VERSION 5.8 ;
BUSBITCHARS "[]" ;
DIVIDERCHAR "/" ;
UNITS
    DATABASE MICRONS 1000 ;
END UNITS

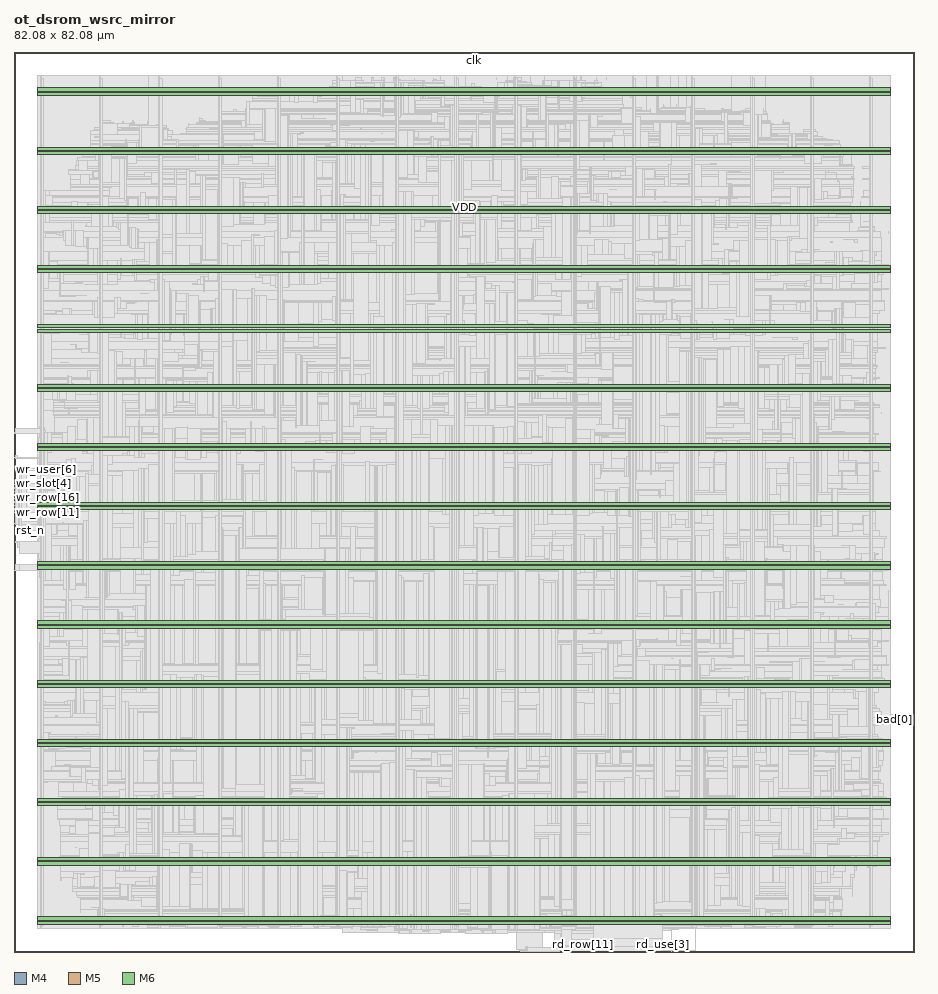
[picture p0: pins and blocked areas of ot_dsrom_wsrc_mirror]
MACRO ot_dsrom_wsrc_mirror
  FOREIGN ot_dsrom_wsrc_mirror 0 0 ;
  CLASS BLOCK ;
  SIZE 82.08 BY 82.08 ;
  PIN bad[0]
    DIRECTION OUTPUT ;
    USE SIGNAL ;
    PORT
      LAYER M4 ;
        RECT  81.996 21.216 82.08 21.24 ;
    END
  END bad[0]
  PIN bad[1]
    DIRECTION OUTPUT ;
    USE SIGNAL ;
    PORT
      LAYER M4 ;
        RECT  81.996 21.312 82.08 21.336 ;
    END
  END bad[1]
  PIN bad[2]
    DIRECTION OUTPUT ;
    USE SIGNAL ;
    PORT
      LAYER M4 ;
        RECT  81.996 21.408 82.08 21.432 ;
    END
  END bad[2]
  PIN bad[3]
    DIRECTION OUTPUT ;
    USE SIGNAL ;
    PORT
      LAYER M4 ;
        RECT  81.996 21.504 82.08 21.528 ;
    END
  END bad[3]
  PIN clk
    DIRECTION INPUT ;
    USE SIGNAL ;
    PORT
      LAYER M5 ;
        RECT  41.952 81.996 41.976 82.08 ;
    END
  END clk
  PIN j_user[0]
    DIRECTION INPUT ;
    USE SIGNAL ;
    PORT
      LAYER M5 ;
        RECT  49.824 0 49.848 0.084 ;
    END
  END j_user[0]
  PIN j_user[1]
    DIRECTION INPUT ;
    USE SIGNAL ;
    PORT
      LAYER M5 ;
        RECT  49.92 0 49.944 0.084 ;
    END
  END j_user[1]
  PIN j_user[2]
    DIRECTION INPUT ;
    USE SIGNAL ;
    PORT
      LAYER M5 ;
        RECT  50.016 0 50.04 0.084 ;
    END
  END j_user[2]
  PIN j_user[3]
    DIRECTION INPUT ;
    USE SIGNAL ;
    PORT
      LAYER M5 ;
        RECT  50.112 0 50.136 0.084 ;
    END
  END j_user[3]
  PIN j_user[4]
    DIRECTION INPUT ;
    USE SIGNAL ;
    PORT
      LAYER M5 ;
        RECT  50.208 0 50.232 0.084 ;
    END
  END j_user[4]
  PIN j_user[5]
    DIRECTION INPUT ;
    USE SIGNAL ;
    PORT
      LAYER M5 ;
        RECT  50.304 0 50.328 0.084 ;
    END
  END j_user[5]
  PIN j_user[6]
    DIRECTION INPUT ;
    USE SIGNAL ;
    PORT
      LAYER M5 ;
        RECT  50.4 0 50.424 0.084 ;
    END
  END j_user[6]
  PIN j_user[7]
    DIRECTION INPUT ;
    USE SIGNAL ;
    PORT
      LAYER M5 ;
        RECT  50.496 0 50.52 0.084 ;
    END
  END j_user[7]
  PIN j_user[8]
    DIRECTION INPUT ;
    USE SIGNAL ;
    PORT
      LAYER M5 ;
        RECT  50.592 0 50.616 0.084 ;
    END
  END j_user[8]
  PIN j_user[9]
    DIRECTION INPUT ;
    USE SIGNAL ;
    PORT
      LAYER M5 ;
        RECT  50.688 0 50.712 0.084 ;
    END
  END j_user[9]
  PIN rd_row[0]
    DIRECTION INPUT ;
    USE SIGNAL ;
    PORT
      LAYER M5 ;
        RECT  50.784 0 50.808 0.084 ;
    END
  END rd_row[0]
  PIN rd_row[10]
    DIRECTION INPUT ;
    USE SIGNAL ;
    PORT
      LAYER M5 ;
        RECT  51.744 0 51.768 0.084 ;
    END
  END rd_row[10]
  PIN rd_row[11]
    DIRECTION INPUT ;
    USE SIGNAL ;
    PORT
      LAYER M5 ;
        RECT  51.84 0 51.864 0.084 ;
    END
  END rd_row[11]
  PIN rd_row[12]
    DIRECTION INPUT ;
    USE SIGNAL ;
    PORT
      LAYER M5 ;
        RECT  51.936 0 51.96 0.084 ;
    END
  END rd_row[12]
  PIN rd_row[13]
    DIRECTION INPUT ;
    USE SIGNAL ;
    PORT
      LAYER M5 ;
        RECT  52.032 0 52.056 0.084 ;
    END
  END rd_row[13]
  PIN rd_row[14]
    DIRECTION INPUT ;
    USE SIGNAL ;
    PORT
      LAYER M5 ;
        RECT  52.128 0 52.152 0.084 ;
    END
  END rd_row[14]
  PIN rd_row[15]
    DIRECTION INPUT ;
    USE SIGNAL ;
    PORT
      LAYER M5 ;
        RECT  52.224 0 52.248 0.084 ;
    END
  END rd_row[15]
  PIN rd_row[16]
    DIRECTION INPUT ;
    USE SIGNAL ;
    PORT
      LAYER M5 ;
        RECT  52.32 0 52.344 0.084 ;
    END
  END rd_row[16]
  PIN rd_row[17]
    DIRECTION INPUT ;
    USE SIGNAL ;
    PORT
      LAYER M5 ;
        RECT  52.416 0 52.44 0.084 ;
    END
  END rd_row[17]
  PIN rd_row[18]
    DIRECTION INPUT ;
    USE SIGNAL ;
    PORT
      LAYER M5 ;
        RECT  52.512 0 52.536 0.084 ;
    END
  END rd_row[18]
  PIN rd_row[19]
    DIRECTION INPUT ;
    USE SIGNAL ;
    PORT
      LAYER M5 ;
        RECT  52.608 0 52.632 0.084 ;
    END
  END rd_row[19]
  PIN rd_row[1]
    DIRECTION INPUT ;
    USE SIGNAL ;
    PORT
      LAYER M5 ;
        RECT  50.88 0 50.904 0.084 ;
    END
  END rd_row[1]
  PIN rd_row[20]
    DIRECTION INPUT ;
    USE SIGNAL ;
    PORT
      LAYER M5 ;
        RECT  52.704 0 52.728 0.084 ;
    END
  END rd_row[20]
  PIN rd_row[21]
    DIRECTION INPUT ;
    USE SIGNAL ;
    PORT
      LAYER M5 ;
        RECT  52.8 0 52.824 0.084 ;
    END
  END rd_row[21]
  PIN rd_row[22]
    DIRECTION INPUT ;
    USE SIGNAL ;
    PORT
      LAYER M5 ;
        RECT  52.896 0 52.92 0.084 ;
    END
  END rd_row[22]
  PIN rd_row[23]
    DIRECTION INPUT ;
    USE SIGNAL ;
    PORT
      LAYER M5 ;
        RECT  52.992 0 53.016 0.084 ;
    END
  END rd_row[23]
  PIN rd_row[24]
    DIRECTION INPUT ;
    USE SIGNAL ;
    PORT
      LAYER M5 ;
        RECT  53.088 0 53.112 0.084 ;
    END
  END rd_row[24]
  PIN rd_row[25]
    DIRECTION INPUT ;
    USE SIGNAL ;
    PORT
      LAYER M5 ;
        RECT  53.184 0 53.208 0.084 ;
    END
  END rd_row[25]
  PIN rd_row[26]
    DIRECTION INPUT ;
    USE SIGNAL ;
    PORT
      LAYER M5 ;
        RECT  53.28 0 53.304 0.084 ;
    END
  END rd_row[26]
  PIN rd_row[27]
    DIRECTION INPUT ;
    USE SIGNAL ;
    PORT
      LAYER M5 ;
        RECT  53.376 0 53.4 0.084 ;
    END
  END rd_row[27]
  PIN rd_row[28]
    DIRECTION INPUT ;
    USE SIGNAL ;
    PORT
      LAYER M5 ;
        RECT  53.472 0 53.496 0.084 ;
    END
  END rd_row[28]
  PIN rd_row[29]
    DIRECTION INPUT ;
    USE SIGNAL ;
    PORT
      LAYER M5 ;
        RECT  53.568 0 53.592 0.084 ;
    END
  END rd_row[29]
  PIN rd_row[2]
    DIRECTION INPUT ;
    USE SIGNAL ;
    PORT
      LAYER M5 ;
        RECT  50.976 0 51 0.084 ;
    END
  END rd_row[2]
  PIN rd_row[30]
    DIRECTION INPUT ;
    USE SIGNAL ;
    PORT
      LAYER M5 ;
        RECT  53.664 0 53.688 0.084 ;
    END
  END rd_row[30]
  PIN rd_row[31]
    DIRECTION INPUT ;
    USE SIGNAL ;
    PORT
      LAYER M5 ;
        RECT  53.76 0 53.784 0.084 ;
    END
  END rd_row[31]
  PIN rd_row[32]
    DIRECTION INPUT ;
    USE SIGNAL ;
    PORT
      LAYER M5 ;
        RECT  53.856 0 53.88 0.084 ;
    END
  END rd_row[32]
  PIN rd_row[33]
    DIRECTION INPUT ;
    USE SIGNAL ;
    PORT
      LAYER M5 ;
        RECT  53.952 0 53.976 0.084 ;
    END
  END rd_row[33]
  PIN rd_row[34]
    DIRECTION INPUT ;
    USE SIGNAL ;
    PORT
      LAYER M5 ;
        RECT  54.048 0 54.072 0.084 ;
    END
  END rd_row[34]
  PIN rd_row[35]
    DIRECTION INPUT ;
    USE SIGNAL ;
    PORT
      LAYER M5 ;
        RECT  54.144 0 54.168 0.084 ;
    END
  END rd_row[35]
  PIN rd_row[36]
    DIRECTION INPUT ;
    USE SIGNAL ;
    PORT
      LAYER M5 ;
        RECT  54.24 0 54.264 0.084 ;
    END
  END rd_row[36]
  PIN rd_row[37]
    DIRECTION INPUT ;
    USE SIGNAL ;
    PORT
      LAYER M5 ;
        RECT  54.336 0 54.36 0.084 ;
    END
  END rd_row[37]
  PIN rd_row[38]
    DIRECTION INPUT ;
    USE SIGNAL ;
    PORT
      LAYER M5 ;
        RECT  54.432 0 54.456 0.084 ;
    END
  END rd_row[38]
  PIN rd_row[39]
    DIRECTION INPUT ;
    USE SIGNAL ;
    PORT
      LAYER M5 ;
        RECT  54.528 0 54.552 0.084 ;
    END
  END rd_row[39]
  PIN rd_row[3]
    DIRECTION INPUT ;
    USE SIGNAL ;
    PORT
      LAYER M5 ;
        RECT  51.072 0 51.096 0.084 ;
    END
  END rd_row[3]
  PIN rd_row[40]
    DIRECTION INPUT ;
    USE SIGNAL ;
    PORT
      LAYER M5 ;
        RECT  54.624 0 54.648 0.084 ;
    END
  END rd_row[40]
  PIN rd_row[41]
    DIRECTION INPUT ;
    USE SIGNAL ;
    PORT
      LAYER M5 ;
        RECT  54.72 0 54.744 0.084 ;
    END
  END rd_row[41]
  PIN rd_row[42]
    DIRECTION INPUT ;
    USE SIGNAL ;
    PORT
      LAYER M5 ;
        RECT  54.816 0 54.84 0.084 ;
    END
  END rd_row[42]
  PIN rd_row[43]
    DIRECTION INPUT ;
    USE SIGNAL ;
    PORT
      LAYER M5 ;
        RECT  54.912 0 54.936 0.084 ;
    END
  END rd_row[43]
  PIN rd_row[44]
    DIRECTION INPUT ;
    USE SIGNAL ;
    PORT
      LAYER M5 ;
        RECT  55.008 0 55.032 0.084 ;
    END
  END rd_row[44]
  PIN rd_row[45]
    DIRECTION INPUT ;
    USE SIGNAL ;
    PORT
      LAYER M5 ;
        RECT  55.104 0 55.128 0.084 ;
    END
  END rd_row[45]
  PIN rd_row[46]
    DIRECTION INPUT ;
    USE SIGNAL ;
    PORT
      LAYER M5 ;
        RECT  55.2 0 55.224 0.084 ;
    END
  END rd_row[46]
  PIN rd_row[47]
    DIRECTION INPUT ;
    USE SIGNAL ;
    PORT
      LAYER M5 ;
        RECT  55.296 0 55.32 0.084 ;
    END
  END rd_row[47]
  PIN rd_row[48]
    DIRECTION INPUT ;
    USE SIGNAL ;
    PORT
      LAYER M5 ;
        RECT  55.392 0 55.416 0.084 ;
    END
  END rd_row[48]
  PIN rd_row[49]
    DIRECTION INPUT ;
    USE SIGNAL ;
    PORT
      LAYER M5 ;
        RECT  55.488 0 55.512 0.084 ;
    END
  END rd_row[49]
  PIN rd_row[4]
    DIRECTION INPUT ;
    USE SIGNAL ;
    PORT
      LAYER M5 ;
        RECT  51.168 0 51.192 0.084 ;
    END
  END rd_row[4]
  PIN rd_row[50]
    DIRECTION INPUT ;
    USE SIGNAL ;
    PORT
      LAYER M5 ;
        RECT  55.584 0 55.608 0.084 ;
    END
  END rd_row[50]
  PIN rd_row[51]
    DIRECTION INPUT ;
    USE SIGNAL ;
    PORT
      LAYER M5 ;
        RECT  55.68 0 55.704 0.084 ;
    END
  END rd_row[51]
  PIN rd_row[52]
    DIRECTION INPUT ;
    USE SIGNAL ;
    PORT
      LAYER M5 ;
        RECT  55.776 0 55.8 0.084 ;
    END
  END rd_row[52]
  PIN rd_row[53]
    DIRECTION INPUT ;
    USE SIGNAL ;
    PORT
      LAYER M5 ;
        RECT  55.872 0 55.896 0.084 ;
    END
  END rd_row[53]
  PIN rd_row[54]
    DIRECTION INPUT ;
    USE SIGNAL ;
    PORT
      LAYER M5 ;
        RECT  55.968 0 55.992 0.084 ;
    END
  END rd_row[54]
  PIN rd_row[55]
    DIRECTION INPUT ;
    USE SIGNAL ;
    PORT
      LAYER M5 ;
        RECT  56.064 0 56.088 0.084 ;
    END
  END rd_row[55]
  PIN rd_row[56]
    DIRECTION INPUT ;
    USE SIGNAL ;
    PORT
      LAYER M5 ;
        RECT  56.16 0 56.184 0.084 ;
    END
  END rd_row[56]
  PIN rd_row[57]
    DIRECTION INPUT ;
    USE SIGNAL ;
    PORT
      LAYER M5 ;
        RECT  56.256 0 56.28 0.084 ;
    END
  END rd_row[57]
  PIN rd_row[58]
    DIRECTION INPUT ;
    USE SIGNAL ;
    PORT
      LAYER M5 ;
        RECT  56.352 0 56.376 0.084 ;
    END
  END rd_row[58]
  PIN rd_row[59]
    DIRECTION INPUT ;
    USE SIGNAL ;
    PORT
      LAYER M5 ;
        RECT  56.448 0 56.472 0.084 ;
    END
  END rd_row[59]
  PIN rd_row[5]
    DIRECTION INPUT ;
    USE SIGNAL ;
    PORT
      LAYER M5 ;
        RECT  51.264 0 51.288 0.084 ;
    END
  END rd_row[5]
  PIN rd_row[60]
    DIRECTION INPUT ;
    USE SIGNAL ;
    PORT
      LAYER M5 ;
        RECT  56.544 0 56.568 0.084 ;
    END
  END rd_row[60]
  PIN rd_row[61]
    DIRECTION INPUT ;
    USE SIGNAL ;
    PORT
      LAYER M5 ;
        RECT  56.64 0 56.664 0.084 ;
    END
  END rd_row[61]
  PIN rd_row[62]
    DIRECTION INPUT ;
    USE SIGNAL ;
    PORT
      LAYER M5 ;
        RECT  56.736 0 56.76 0.084 ;
    END
  END rd_row[62]
  PIN rd_row[63]
    DIRECTION INPUT ;
    USE SIGNAL ;
    PORT
      LAYER M5 ;
        RECT  56.832 0 56.856 0.084 ;
    END
  END rd_row[63]
  PIN rd_row[64]
    DIRECTION INPUT ;
    USE SIGNAL ;
    PORT
      LAYER M5 ;
        RECT  56.928 0 56.952 0.084 ;
    END
  END rd_row[64]
  PIN rd_row[65]
    DIRECTION INPUT ;
    USE SIGNAL ;
    PORT
      LAYER M5 ;
        RECT  57.024 0 57.048 0.084 ;
    END
  END rd_row[65]
  PIN rd_row[66]
    DIRECTION INPUT ;
    USE SIGNAL ;
    PORT
      LAYER M5 ;
        RECT  57.12 0 57.144 0.084 ;
    END
  END rd_row[66]
  PIN rd_row[67]
    DIRECTION INPUT ;
    USE SIGNAL ;
    PORT
      LAYER M5 ;
        RECT  57.216 0 57.24 0.084 ;
    END
  END rd_row[67]
  PIN rd_row[68]
    DIRECTION INPUT ;
    USE SIGNAL ;
    PORT
      LAYER M5 ;
        RECT  57.312 0 57.336 0.084 ;
    END
  END rd_row[68]
  PIN rd_row[69]
    DIRECTION INPUT ;
    USE SIGNAL ;
    PORT
      LAYER M5 ;
        RECT  57.408 0 57.432 0.084 ;
    END
  END rd_row[69]
  PIN rd_row[6]
    DIRECTION INPUT ;
    USE SIGNAL ;
    PORT
      LAYER M5 ;
        RECT  51.36 0 51.384 0.084 ;
    END
  END rd_row[6]
  PIN rd_row[70]
    DIRECTION INPUT ;
    USE SIGNAL ;
    PORT
      LAYER M5 ;
        RECT  57.504 0 57.528 0.084 ;
    END
  END rd_row[70]
  PIN rd_row[71]
    DIRECTION INPUT ;
    USE SIGNAL ;
    PORT
      LAYER M5 ;
        RECT  57.6 0 57.624 0.084 ;
    END
  END rd_row[71]
  PIN rd_row[72]
    DIRECTION INPUT ;
    USE SIGNAL ;
    PORT
      LAYER M5 ;
        RECT  57.696 0 57.72 0.084 ;
    END
  END rd_row[72]
  PIN rd_row[73]
    DIRECTION INPUT ;
    USE SIGNAL ;
    PORT
      LAYER M5 ;
        RECT  57.792 0 57.816 0.084 ;
    END
  END rd_row[73]
  PIN rd_row[74]
    DIRECTION INPUT ;
    USE SIGNAL ;
    PORT
      LAYER M5 ;
        RECT  57.888 0 57.912 0.084 ;
    END
  END rd_row[74]
  PIN rd_row[75]
    DIRECTION INPUT ;
    USE SIGNAL ;
    PORT
      LAYER M5 ;
        RECT  57.984 0 58.008 0.084 ;
    END
  END rd_row[75]
  PIN rd_row[76]
    DIRECTION INPUT ;
    USE SIGNAL ;
    PORT
      LAYER M5 ;
        RECT  58.08 0 58.104 0.084 ;
    END
  END rd_row[76]
  PIN rd_row[77]
    DIRECTION INPUT ;
    USE SIGNAL ;
    PORT
      LAYER M5 ;
        RECT  58.176 0 58.2 0.084 ;
    END
  END rd_row[77]
  PIN rd_row[78]
    DIRECTION INPUT ;
    USE SIGNAL ;
    PORT
      LAYER M5 ;
        RECT  58.272 0 58.296 0.084 ;
    END
  END rd_row[78]
  PIN rd_row[79]
    DIRECTION INPUT ;
    USE SIGNAL ;
    PORT
      LAYER M5 ;
        RECT  58.368 0 58.392 0.084 ;
    END
  END rd_row[79]
  PIN rd_row[7]
    DIRECTION INPUT ;
    USE SIGNAL ;
    PORT
      LAYER M5 ;
        RECT  51.456 0 51.48 0.084 ;
    END
  END rd_row[7]
  PIN rd_row[80]
    DIRECTION INPUT ;
    USE SIGNAL ;
    PORT
      LAYER M5 ;
        RECT  58.464 0 58.488 0.084 ;
    END
  END rd_row[80]
  PIN rd_row[81]
    DIRECTION INPUT ;
    USE SIGNAL ;
    PORT
      LAYER M5 ;
        RECT  58.56 0 58.584 0.084 ;
    END
  END rd_row[81]
  PIN rd_row[82]
    DIRECTION INPUT ;
    USE SIGNAL ;
    PORT
      LAYER M5 ;
        RECT  58.656 0 58.68 0.084 ;
    END
  END rd_row[82]
  PIN rd_row[83]
    DIRECTION INPUT ;
    USE SIGNAL ;
    PORT
      LAYER M5 ;
        RECT  58.752 0 58.776 0.084 ;
    END
  END rd_row[83]
  PIN rd_row[8]
    DIRECTION INPUT ;
    USE SIGNAL ;
    PORT
      LAYER M5 ;
        RECT  51.552 0 51.576 0.084 ;
    END
  END rd_row[8]
  PIN rd_row[9]
    DIRECTION INPUT ;
    USE SIGNAL ;
    PORT
      LAYER M5 ;
        RECT  51.648 0 51.672 0.084 ;
    END
  END rd_row[9]
  PIN rd_use[0]
    DIRECTION INPUT ;
    USE SIGNAL ;
    PORT
      LAYER M5 ;
        RECT  58.848 0 58.872 0.084 ;
    END
  END rd_use[0]
  PIN rd_use[1]
    DIRECTION INPUT ;
    USE SIGNAL ;
    PORT
      LAYER M5 ;
        RECT  58.944 0 58.968 0.084 ;
    END
  END rd_use[1]
  PIN rd_use[2]
    DIRECTION INPUT ;
    USE SIGNAL ;
    PORT
      LAYER M5 ;
        RECT  59.04 0 59.064 0.084 ;
    END
  END rd_use[2]
  PIN rd_use[3]
    DIRECTION INPUT ;
    USE SIGNAL ;
    PORT
      LAYER M5 ;
        RECT  59.136 0 59.16 0.084 ;
    END
  END rd_use[3]
  PIN rst_n
    DIRECTION INPUT ;
    USE SIGNAL ;
    PORT
      LAYER M6 ;
        RECT  0 38.4 0.069 38.432 ;
    END
  END rst_n
  PIN wr_clr
    DIRECTION INPUT ;
    USE SIGNAL ;
    PORT
      LAYER M6 ;
        RECT  0 38.528 0.069 38.56 ;
    END
  END wr_clr
  PIN wr_row[0]
    DIRECTION INPUT ;
    USE SIGNAL ;
    PORT
      LAYER M6 ;
        RECT  0 38.656 0.069 38.688 ;
    END
  END wr_row[0]
  PIN wr_row[10]
    DIRECTION INPUT ;
    USE SIGNAL ;
    PORT
      LAYER M6 ;
        RECT  0 39.936 0.069 39.968 ;
    END
  END wr_row[10]
  PIN wr_row[11]
    DIRECTION INPUT ;
    USE SIGNAL ;
    PORT
      LAYER M6 ;
        RECT  0 40.064 0.069 40.096 ;
    END
  END wr_row[11]
  PIN wr_row[12]
    DIRECTION INPUT ;
    USE SIGNAL ;
    PORT
      LAYER M6 ;
        RECT  0 40.192 0.069 40.224 ;
    END
  END wr_row[12]
  PIN wr_row[13]
    DIRECTION INPUT ;
    USE SIGNAL ;
    PORT
      LAYER M6 ;
        RECT  0 40.32 0.069 40.352 ;
    END
  END wr_row[13]
  PIN wr_row[14]
    DIRECTION INPUT ;
    USE SIGNAL ;
    PORT
      LAYER M6 ;
        RECT  0 40.448 0.069 40.48 ;
    END
  END wr_row[14]
  PIN wr_row[15]
    DIRECTION INPUT ;
    USE SIGNAL ;
    PORT
      LAYER M6 ;
        RECT  0 40.576 0.069 40.608 ;
    END
  END wr_row[15]
  PIN wr_row[16]
    DIRECTION INPUT ;
    USE SIGNAL ;
    PORT
      LAYER M6 ;
        RECT  0 40.704 0.069 40.736 ;
    END
  END wr_row[16]
  PIN wr_row[17]
    DIRECTION INPUT ;
    USE SIGNAL ;
    PORT
      LAYER M6 ;
        RECT  0 40.832 0.069 40.864 ;
    END
  END wr_row[17]
  PIN wr_row[18]
    DIRECTION INPUT ;
    USE SIGNAL ;
    PORT
      LAYER M6 ;
        RECT  0 40.96 0.069 40.992 ;
    END
  END wr_row[18]
  PIN wr_row[19]
    DIRECTION INPUT ;
    USE SIGNAL ;
    PORT
      LAYER M6 ;
        RECT  0 41.088 0.069 41.12 ;
    END
  END wr_row[19]
  PIN wr_row[1]
    DIRECTION INPUT ;
    USE SIGNAL ;
    PORT
      LAYER M6 ;
        RECT  0 38.784 0.069 38.816 ;
    END
  END wr_row[1]
  PIN wr_row[20]
    DIRECTION INPUT ;
    USE SIGNAL ;
    PORT
      LAYER M6 ;
        RECT  0 41.216 0.069 41.248 ;
    END
  END wr_row[20]
  PIN wr_row[2]
    DIRECTION INPUT ;
    USE SIGNAL ;
    PORT
      LAYER M6 ;
        RECT  0 38.912 0.069 38.944 ;
    END
  END wr_row[2]
  PIN wr_row[3]
    DIRECTION INPUT ;
    USE SIGNAL ;
    PORT
      LAYER M6 ;
        RECT  0 39.04 0.069 39.072 ;
    END
  END wr_row[3]
  PIN wr_row[4]
    DIRECTION INPUT ;
    USE SIGNAL ;
    PORT
      LAYER M6 ;
        RECT  0 39.168 0.069 39.2 ;
    END
  END wr_row[4]
  PIN wr_row[5]
    DIRECTION INPUT ;
    USE SIGNAL ;
    PORT
      LAYER M6 ;
        RECT  0 39.296 0.069 39.328 ;
    END
  END wr_row[5]
  PIN wr_row[6]
    DIRECTION INPUT ;
    USE SIGNAL ;
    PORT
      LAYER M6 ;
        RECT  0 39.424 0.069 39.456 ;
    END
  END wr_row[6]
  PIN wr_row[7]
    DIRECTION INPUT ;
    USE SIGNAL ;
    PORT
      LAYER M6 ;
        RECT  0 39.552 0.069 39.584 ;
    END
  END wr_row[7]
  PIN wr_row[8]
    DIRECTION INPUT ;
    USE SIGNAL ;
    PORT
      LAYER M6 ;
        RECT  0 39.68 0.069 39.712 ;
    END
  END wr_row[8]
  PIN wr_row[9]
    DIRECTION INPUT ;
    USE SIGNAL ;
    PORT
      LAYER M6 ;
        RECT  0 39.808 0.069 39.84 ;
    END
  END wr_row[9]
  PIN wr_set
    DIRECTION INPUT ;
    USE SIGNAL ;
    PORT
      LAYER M6 ;
        RECT  0 41.344 0.069 41.376 ;
    END
  END wr_set
  PIN wr_slot[0]
    DIRECTION INPUT ;
    USE SIGNAL ;
    PORT
      LAYER M6 ;
        RECT  0 41.472 0.069 41.504 ;
    END
  END wr_slot[0]
  PIN wr_slot[1]
    DIRECTION INPUT ;
    USE SIGNAL ;
    PORT
      LAYER M6 ;
        RECT  0 41.6 0.069 41.632 ;
    END
  END wr_slot[1]
  PIN wr_slot[2]
    DIRECTION INPUT ;
    USE SIGNAL ;
    PORT
      LAYER M6 ;
        RECT  0 41.728 0.069 41.76 ;
    END
  END wr_slot[2]
  PIN wr_slot[3]
    DIRECTION INPUT ;
    USE SIGNAL ;
    PORT
      LAYER M6 ;
        RECT  0 41.856 0.069 41.888 ;
    END
  END wr_slot[3]
  PIN wr_slot[4]
    DIRECTION INPUT ;
    USE SIGNAL ;
    PORT
      LAYER M6 ;
        RECT  0 41.984 0.069 42.016 ;
    END
  END wr_slot[4]
  PIN wr_slot[5]
    DIRECTION INPUT ;
    USE SIGNAL ;
    PORT
      LAYER M6 ;
        RECT  0 42.112 0.069 42.144 ;
    END
  END wr_slot[5]
  PIN wr_slot[6]
    DIRECTION INPUT ;
    USE SIGNAL ;
    PORT
      LAYER M6 ;
        RECT  0 42.24 0.069 42.272 ;
    END
  END wr_slot[6]
  PIN wr_tag
    DIRECTION INPUT ;
    USE SIGNAL ;
    PORT
      LAYER M6 ;
        RECT  0 42.368 0.069 42.4 ;
    END
  END wr_tag
  PIN wr_user[0]
    DIRECTION INPUT ;
    USE SIGNAL ;
    PORT
      LAYER M6 ;
        RECT  0 42.496 0.069 42.528 ;
    END
  END wr_user[0]
  PIN wr_user[1]
    DIRECTION INPUT ;
    USE SIGNAL ;
    PORT
      LAYER M6 ;
        RECT  0 42.624 0.069 42.656 ;
    END
  END wr_user[1]
  PIN wr_user[2]
    DIRECTION INPUT ;
    USE SIGNAL ;
    PORT
      LAYER M6 ;
        RECT  0 42.752 0.069 42.784 ;
    END
  END wr_user[2]
  PIN wr_user[3]
    DIRECTION INPUT ;
    USE SIGNAL ;
    PORT
      LAYER M6 ;
        RECT  0 42.88 0.069 42.912 ;
    END
  END wr_user[3]
  PIN wr_user[4]
    DIRECTION INPUT ;
    USE SIGNAL ;
    PORT
      LAYER M6 ;
        RECT  0 43.008 0.069 43.04 ;
    END
  END wr_user[4]
  PIN wr_user[5]
    DIRECTION INPUT ;
    USE SIGNAL ;
    PORT
      LAYER M6 ;
        RECT  0 43.136 0.069 43.168 ;
    END
  END wr_user[5]
  PIN wr_user[6]
    DIRECTION INPUT ;
    USE SIGNAL ;
    PORT
      LAYER M6 ;
        RECT  0 43.264 0.069 43.296 ;
    END
  END wr_user[6]
  PIN wr_user[7]
    DIRECTION INPUT ;
    USE SIGNAL ;
    PORT
      LAYER M6 ;
        RECT  0 43.392 0.069 43.424 ;
    END
  END wr_user[7]
  PIN wr_user[8]
    DIRECTION INPUT ;
    USE SIGNAL ;
    PORT
      LAYER M6 ;
        RECT  0 43.52 0.069 43.552 ;
    END
  END wr_user[8]
  PIN wr_user[9]
    DIRECTION INPUT ;
    USE SIGNAL ;
    PORT
      LAYER M6 ;
        RECT  0 43.648 0.069 43.68 ;
    END
  END wr_user[9]
  PIN VDD
    DIRECTION INOUT ;
    USE POWER ;
    PORT
      LAYER M6 ;
        RECT  2.16 78.513 79.92 78.801 ;
        RECT  2.16 73.113 79.92 73.401 ;
        RECT  2.16 67.713 79.92 68.001 ;
        RECT  2.16 62.313 79.92 62.601 ;
        RECT  2.16 56.913 79.92 57.201 ;
        RECT  2.16 51.513 79.92 51.801 ;
        RECT  2.16 46.113 79.92 46.401 ;
        RECT  2.16 40.713 79.92 41.001 ;
        RECT  2.16 35.313 79.92 35.601 ;
        RECT  2.16 29.913 79.92 30.201 ;
        RECT  2.16 24.513 79.92 24.801 ;
        RECT  2.16 19.113 79.92 19.401 ;
        RECT  2.16 13.713 79.92 14.001 ;
        RECT  2.16 8.313 79.92 8.601 ;
        RECT  2.16 2.913 79.92 3.201 ;
    END
  END VDD
  PIN VSS
    DIRECTION INOUT ;
    USE GROUND ;
    PORT
      LAYER M6 ;
        RECT  2.16 78.129 79.92 78.417 ;
        RECT  2.16 72.729 79.92 73.017 ;
        RECT  2.16 67.329 79.92 67.617 ;
        RECT  2.16 61.929 79.92 62.217 ;
        RECT  2.16 56.529 79.92 56.817 ;
        RECT  2.16 51.129 79.92 51.417 ;
        RECT  2.16 45.729 79.92 46.017 ;
        RECT  2.16 40.329 79.92 40.617 ;
        RECT  2.16 34.929 79.92 35.217 ;
        RECT  2.16 29.529 79.92 29.817 ;
        RECT  2.16 24.129 79.92 24.417 ;
        RECT  2.16 18.729 79.92 19.017 ;
        RECT  2.16 13.329 79.92 13.617 ;
        RECT  2.16 7.929 79.92 8.217 ;
        RECT  2.16 2.529 79.92 2.817 ;
    END
  END VSS
  OBS
    LAYER RVTN ;
     RECT  2.16 2.16 79.92 2.295 ;
     RECT  2.16 2.565 79.92 2.835 ;
     RECT  2.16 3.105 79.92 3.375 ;
     RECT  2.16 3.645 79.92 3.915 ;
     RECT  2.16 4.185 79.92 4.455 ;
     RECT  2.16 4.725 79.92 4.995 ;
     RECT  2.16 5.265 79.92 5.535 ;
     RECT  2.16 5.805 79.92 6.075 ;
     RECT  2.16 6.345 79.92 6.615 ;
     RECT  2.16 6.885 79.92 7.155 ;
     RECT  2.16 7.425 79.92 7.695 ;
     RECT  2.16 7.965 79.92 8.235 ;
     RECT  2.16 8.505 79.92 8.775 ;
     RECT  2.16 9.045 79.92 9.315 ;
     RECT  2.16 9.585 79.92 9.855 ;
     RECT  2.16 10.125 79.92 10.395 ;
     RECT  2.16 10.665 79.92 10.935 ;
     RECT  2.16 11.205 79.92 11.475 ;
     RECT  2.16 11.745 79.92 12.015 ;
     RECT  2.16 12.285 79.92 12.555 ;
     RECT  2.16 12.825 79.92 13.095 ;
     RECT  2.16 13.365 79.92 13.635 ;
     RECT  2.16 13.905 79.92 14.175 ;
     RECT  2.16 14.445 79.92 14.715 ;
     RECT  2.16 14.985 79.92 15.255 ;
     RECT  2.16 15.525 79.92 15.795 ;
     RECT  2.16 16.065 79.92 16.335 ;
     RECT  2.16 16.605 79.92 16.875 ;
     RECT  2.16 17.145 79.92 17.415 ;
     RECT  2.16 17.685 79.92 17.955 ;
     RECT  2.16 18.225 79.92 18.495 ;
     RECT  2.16 18.765 79.92 19.035 ;
     RECT  2.16 19.305 79.92 19.575 ;
     RECT  2.16 19.845 79.92 20.115 ;
     RECT  2.16 20.385 79.92 20.655 ;
     RECT  2.16 20.925 79.92 21.195 ;
     RECT  2.16 21.465 79.92 21.735 ;
     RECT  2.16 22.005 79.92 22.275 ;
     RECT  2.16 22.545 79.92 22.815 ;
     RECT  2.16 23.085 79.92 23.355 ;
     RECT  2.16 23.625 79.92 23.895 ;
     RECT  2.16 24.165 79.92 24.435 ;
     RECT  2.16 24.705 79.92 24.975 ;
     RECT  2.16 25.245 79.92 25.515 ;
     RECT  2.16 25.785 79.92 26.055 ;
     RECT  2.16 26.325 79.92 26.595 ;
     RECT  2.16 26.865 79.92 27.135 ;
     RECT  2.16 27.405 79.92 27.675 ;
     RECT  2.16 27.945 79.92 28.215 ;
     RECT  2.16 28.485 79.92 28.755 ;
     RECT  2.16 29.025 79.92 29.295 ;
     RECT  2.16 29.565 79.92 29.835 ;
     RECT  2.16 30.105 79.92 30.375 ;
     RECT  2.16 30.645 79.92 30.915 ;
     RECT  2.16 31.185 79.92 31.455 ;
     RECT  2.16 31.725 79.92 31.995 ;
     RECT  2.16 32.265 79.92 32.535 ;
     RECT  2.16 32.805 79.92 33.075 ;
     RECT  2.16 33.345 79.92 33.615 ;
     RECT  2.16 33.885 79.92 34.155 ;
     RECT  2.16 34.425 79.92 34.695 ;
     RECT  2.16 34.965 79.92 35.235 ;
     RECT  2.16 35.505 79.92 35.775 ;
     RECT  2.16 36.045 79.92 36.315 ;
     RECT  2.16 36.585 79.92 36.855 ;
     RECT  2.16 37.125 79.92 37.395 ;
     RECT  2.16 37.665 79.92 37.935 ;
     RECT  2.16 38.205 79.92 38.475 ;
     RECT  2.16 38.745 79.92 39.015 ;
     RECT  2.16 39.285 79.92 39.555 ;
     RECT  2.16 39.825 79.92 40.095 ;
     RECT  2.16 40.365 79.92 40.635 ;
     RECT  2.16 40.905 79.92 41.175 ;
     RECT  2.16 41.445 79.92 41.715 ;
     RECT  2.16 41.985 79.92 42.255 ;
     RECT  2.16 42.525 79.92 42.795 ;
     RECT  2.16 43.065 79.92 43.335 ;
     RECT  2.16 43.605 79.92 43.875 ;
     RECT  2.16 44.145 79.92 44.415 ;
     RECT  2.16 44.685 79.92 44.955 ;
     RECT  2.16 45.225 79.92 45.495 ;
     RECT  2.16 45.765 79.92 46.035 ;
     RECT  2.16 46.305 79.92 46.575 ;
     RECT  2.16 46.845 79.92 47.115 ;
     RECT  2.16 47.385 79.92 47.655 ;
     RECT  2.16 47.925 79.92 48.195 ;
     RECT  2.16 48.465 79.92 48.735 ;
     RECT  2.16 49.005 79.92 49.275 ;
     RECT  2.16 49.545 79.92 49.815 ;
     RECT  2.16 50.085 79.92 50.355 ;
     RECT  2.16 50.625 79.92 50.895 ;
     RECT  2.16 51.165 79.92 51.435 ;
     RECT  2.16 51.705 79.92 51.975 ;
     RECT  2.16 52.245 79.92 52.515 ;
     RECT  2.16 52.785 79.92 53.055 ;
     RECT  2.16 53.325 79.92 53.595 ;
     RECT  2.16 53.865 79.92 54.135 ;
     RECT  2.16 54.405 79.92 54.675 ;
     RECT  2.16 54.945 79.92 55.215 ;
     RECT  2.16 55.485 79.92 55.755 ;
     RECT  2.16 56.025 79.92 56.295 ;
     RECT  2.16 56.565 79.92 56.835 ;
     RECT  2.16 57.105 79.92 57.375 ;
     RECT  2.16 57.645 79.92 57.915 ;
     RECT  2.16 58.185 79.92 58.455 ;
     RECT  2.16 58.725 79.92 58.995 ;
     RECT  2.16 59.265 79.92 59.535 ;
     RECT  2.16 59.805 79.92 60.075 ;
     RECT  2.16 60.345 79.92 60.615 ;
     RECT  2.16 60.885 79.92 61.155 ;
     RECT  2.16 61.425 79.92 61.695 ;
     RECT  2.16 61.965 79.92 62.235 ;
     RECT  2.16 62.505 79.92 62.775 ;
     RECT  2.16 63.045 79.92 63.315 ;
     RECT  2.16 63.585 79.92 63.855 ;
     RECT  2.16 64.125 79.92 64.395 ;
     RECT  2.16 64.665 79.92 64.935 ;
     RECT  2.16 65.205 79.92 65.475 ;
     RECT  2.16 65.745 79.92 66.015 ;
     RECT  2.16 66.285 79.92 66.555 ;
     RECT  2.16 66.825 79.92 67.095 ;
     RECT  2.16 67.365 79.92 67.635 ;
     RECT  2.16 67.905 79.92 68.175 ;
     RECT  2.16 68.445 79.92 68.715 ;
     RECT  2.16 68.985 79.92 69.255 ;
     RECT  2.16 69.525 79.92 69.795 ;
     RECT  2.16 70.065 79.92 70.335 ;
     RECT  2.16 70.605 79.92 70.875 ;
     RECT  2.16 71.145 79.92 71.415 ;
     RECT  2.16 71.685 79.92 71.955 ;
     RECT  2.16 72.225 79.92 72.495 ;
     RECT  2.16 72.765 79.92 73.035 ;
     RECT  2.16 73.305 79.92 73.575 ;
     RECT  2.16 73.845 79.92 74.115 ;
     RECT  2.16 74.385 79.92 74.655 ;
     RECT  2.16 74.925 79.92 75.195 ;
     RECT  2.16 75.465 79.92 75.735 ;
     RECT  2.16 76.005 79.92 76.275 ;
     RECT  2.16 76.545 79.92 76.815 ;
     RECT  2.16 77.085 79.92 77.355 ;
     RECT  2.16 77.625 79.92 77.895 ;
     RECT  2.16 78.165 79.92 78.435 ;
     RECT  2.16 78.705 79.92 78.975 ;
     RECT  2.16 79.245 79.92 79.515 ;
     RECT  2.16 79.785 79.92 79.92 ;
    LAYER RVTP ;
     RECT  2.16 2.295 79.92 2.565 ;
     RECT  2.16 2.835 79.92 3.105 ;
     RECT  2.16 3.375 79.92 3.645 ;
     RECT  2.16 3.915 79.92 4.185 ;
     RECT  2.16 4.455 79.92 4.725 ;
     RECT  2.16 4.995 79.92 5.265 ;
     RECT  2.16 5.535 79.92 5.805 ;
     RECT  2.16 6.075 79.92 6.345 ;
     RECT  2.16 6.615 79.92 6.885 ;
     RECT  2.16 7.155 79.92 7.425 ;
     RECT  2.16 7.695 79.92 7.965 ;
     RECT  2.16 8.235 79.92 8.505 ;
     RECT  2.16 8.775 79.92 9.045 ;
     RECT  2.16 9.315 79.92 9.585 ;
     RECT  2.16 9.855 79.92 10.125 ;
     RECT  2.16 10.395 79.92 10.665 ;
     RECT  2.16 10.935 79.92 11.205 ;
     RECT  2.16 11.475 79.92 11.745 ;
     RECT  2.16 12.015 79.92 12.285 ;
     RECT  2.16 12.555 79.92 12.825 ;
     RECT  2.16 13.095 79.92 13.365 ;
     RECT  2.16 13.635 79.92 13.905 ;
     RECT  2.16 14.175 79.92 14.445 ;
     RECT  2.16 14.715 79.92 14.985 ;
     RECT  2.16 15.255 79.92 15.525 ;
     RECT  2.16 15.795 79.92 16.065 ;
     RECT  2.16 16.335 79.92 16.605 ;
     RECT  2.16 16.875 79.92 17.145 ;
     RECT  2.16 17.415 79.92 17.685 ;
     RECT  2.16 17.955 79.92 18.225 ;
     RECT  2.16 18.495 79.92 18.765 ;
     RECT  2.16 19.035 79.92 19.305 ;
     RECT  2.16 19.575 79.92 19.845 ;
     RECT  2.16 20.115 79.92 20.385 ;
     RECT  2.16 20.655 79.92 20.925 ;
     RECT  2.16 21.195 79.92 21.465 ;
     RECT  2.16 21.735 79.92 22.005 ;
     RECT  2.16 22.275 79.92 22.545 ;
     RECT  2.16 22.815 79.92 23.085 ;
     RECT  2.16 23.355 79.92 23.625 ;
     RECT  2.16 23.895 79.92 24.165 ;
     RECT  2.16 24.435 79.92 24.705 ;
     RECT  2.16 24.975 79.92 25.245 ;
     RECT  2.16 25.515 79.92 25.785 ;
     RECT  2.16 26.055 79.92 26.325 ;
     RECT  2.16 26.595 79.92 26.865 ;
     RECT  2.16 27.135 79.92 27.405 ;
     RECT  2.16 27.675 79.92 27.945 ;
     RECT  2.16 28.215 79.92 28.485 ;
     RECT  2.16 28.755 79.92 29.025 ;
     RECT  2.16 29.295 79.92 29.565 ;
     RECT  2.16 29.835 79.92 30.105 ;
     RECT  2.16 30.375 79.92 30.645 ;
     RECT  2.16 30.915 79.92 31.185 ;
     RECT  2.16 31.455 79.92 31.725 ;
     RECT  2.16 31.995 79.92 32.265 ;
     RECT  2.16 32.535 79.92 32.805 ;
     RECT  2.16 33.075 79.92 33.345 ;
     RECT  2.16 33.615 79.92 33.885 ;
     RECT  2.16 34.155 79.92 34.425 ;
     RECT  2.16 34.695 79.92 34.965 ;
     RECT  2.16 35.235 79.92 35.505 ;
     RECT  2.16 35.775 79.92 36.045 ;
     RECT  2.16 36.315 79.92 36.585 ;
     RECT  2.16 36.855 79.92 37.125 ;
     RECT  2.16 37.395 79.92 37.665 ;
     RECT  2.16 37.935 79.92 38.205 ;
     RECT  2.16 38.475 79.92 38.745 ;
     RECT  2.16 39.015 79.92 39.285 ;
     RECT  2.16 39.555 79.92 39.825 ;
     RECT  2.16 40.095 79.92 40.365 ;
     RECT  2.16 40.635 79.92 40.905 ;
     RECT  2.16 41.175 79.92 41.445 ;
     RECT  2.16 41.715 79.92 41.985 ;
     RECT  2.16 42.255 79.92 42.525 ;
     RECT  2.16 42.795 79.92 43.065 ;
     RECT  2.16 43.335 79.92 43.605 ;
     RECT  2.16 43.875 79.92 44.145 ;
     RECT  2.16 44.415 79.92 44.685 ;
     RECT  2.16 44.955 79.92 45.225 ;
     RECT  2.16 45.495 79.92 45.765 ;
     RECT  2.16 46.035 79.92 46.305 ;
     RECT  2.16 46.575 79.92 46.845 ;
     RECT  2.16 47.115 79.92 47.385 ;
     RECT  2.16 47.655 79.92 47.925 ;
     RECT  2.16 48.195 79.92 48.465 ;
     RECT  2.16 48.735 79.92 49.005 ;
     RECT  2.16 49.275 79.92 49.545 ;
     RECT  2.16 49.815 79.92 50.085 ;
     RECT  2.16 50.355 79.92 50.625 ;
     RECT  2.16 50.895 79.92 51.165 ;
     RECT  2.16 51.435 79.92 51.705 ;
     RECT  2.16 51.975 79.92 52.245 ;
     RECT  2.16 52.515 79.92 52.785 ;
     RECT  2.16 53.055 79.92 53.325 ;
     RECT  2.16 53.595 79.92 53.865 ;
     RECT  2.16 54.135 79.92 54.405 ;
     RECT  2.16 54.675 79.92 54.945 ;
     RECT  2.16 55.215 79.92 55.485 ;
     RECT  2.16 55.755 79.92 56.025 ;
     RECT  2.16 56.295 79.92 56.565 ;
     RECT  2.16 56.835 79.92 57.105 ;
     RECT  2.16 57.375 79.92 57.645 ;
     RECT  2.16 57.915 79.92 58.185 ;
     RECT  2.16 58.455 79.92 58.725 ;
     RECT  2.16 58.995 79.92 59.265 ;
     RECT  2.16 59.535 79.92 59.805 ;
     RECT  2.16 60.075 79.92 60.345 ;
     RECT  2.16 60.615 79.92 60.885 ;
     RECT  2.16 61.155 79.92 61.425 ;
     RECT  2.16 61.695 79.92 61.965 ;
     RECT  2.16 62.235 79.92 62.505 ;
     RECT  2.16 62.775 79.92 63.045 ;
     RECT  2.16 63.315 79.92 63.585 ;
     RECT  2.16 63.855 79.92 64.125 ;
     RECT  2.16 64.395 79.92 64.665 ;
     RECT  2.16 64.935 79.92 65.205 ;
     RECT  2.16 65.475 79.92 65.745 ;
     RECT  2.16 66.015 79.92 66.285 ;
     RECT  2.16 66.555 79.92 66.825 ;
     RECT  2.16 67.095 79.92 67.365 ;
     RECT  2.16 67.635 79.92 67.905 ;
     RECT  2.16 68.175 79.92 68.445 ;
     RECT  2.16 68.715 79.92 68.985 ;
     RECT  2.16 69.255 79.92 69.525 ;
     RECT  2.16 69.795 79.92 70.065 ;
     RECT  2.16 70.335 79.92 70.605 ;
     RECT  2.16 70.875 79.92 71.145 ;
     RECT  2.16 71.415 79.92 71.685 ;
     RECT  2.16 71.955 79.92 72.225 ;
     RECT  2.16 72.495 79.92 72.765 ;
     RECT  2.16 73.035 79.92 73.305 ;
     RECT  2.16 73.575 79.92 73.845 ;
     RECT  2.16 74.115 79.92 74.385 ;
     RECT  2.16 74.655 79.92 74.925 ;
     RECT  2.16 75.195 79.92 75.465 ;
     RECT  2.16 75.735 79.92 76.005 ;
     RECT  2.16 76.275 79.92 76.545 ;
     RECT  2.16 76.815 79.92 77.085 ;
     RECT  2.16 77.355 79.92 77.625 ;
     RECT  2.16 77.895 79.92 78.165 ;
     RECT  2.16 78.435 79.92 78.705 ;
     RECT  2.16 78.975 79.92 79.245 ;
     RECT  2.16 79.515 79.92 79.785 ;
    LAYER M1 ;
     RECT  2.16 2.151 79.92 79.929 ;
    LAYER M2 ;
     RECT  0.571 39.024 0.607 39.042 ;
     RECT  1.723 42.192 2.119 42.75 ;
     RECT  1.147 44.082 2.119 44.1 ;
     RECT  2.119 42.192 2.155 44.1 ;
     RECT  0.607 39.024 2.16 39.276 ;
     RECT  1.723 40.302 2.16 40.32 ;
     RECT  2.155 41.958 2.16 44.1 ;
     RECT  2.155 45.774 2.16 45.792 ;
     RECT  2.16 2.151 12.307 79.929 ;
     RECT  12.307 2.106 13.163 79.929 ;
     RECT  13.163 2.151 29.947 79.929 ;
     RECT  29.947 1.8 35.095 79.929 ;
     RECT  35.095 1.728 38.939 79.929 ;
     RECT  38.939 1.764 41.179 79.929 ;
     RECT  41.179 1.728 44.987 79.929 ;
     RECT  46.507 0.036 46.651 0.054 ;
     RECT  46.651 0.036 46.903 0.126 ;
     RECT  44.987 1.764 47.147 79.929 ;
     RECT  46.903 0.036 48.163 0.198 ;
     RECT  47.147 1.8 48.343 79.929 ;
     RECT  48.163 0.036 50.107 0.234 ;
     RECT  50.107 0.036 50.999 0.279 ;
     RECT  48.343 1.764 51.295 79.929 ;
     RECT  51.295 1.692 51.655 79.929 ;
     RECT  51.655 1.152 51.755 79.929 ;
     RECT  51.755 1.152 51.791 1.17 ;
     RECT  50.999 0.036 52.619 0.234 ;
     RECT  52.619 0.216 52.727 0.234 ;
     RECT  51.755 2.034 56.363 79.929 ;
     RECT  56.363 2.106 57.695 79.929 ;
     RECT  57.695 2.151 58.639 79.929 ;
     RECT  58.639 2.106 58.711 79.929 ;
     RECT  58.711 2.034 58.819 79.929 ;
     RECT  58.819 1.998 59.891 79.929 ;
     RECT  59.891 2.034 60.611 79.929 ;
     RECT  60.611 2.106 61.367 79.929 ;
     RECT  61.367 2.151 65.443 79.929 ;
     RECT  65.443 2.106 68.531 79.929 ;
     RECT  68.531 2.151 79.92 79.929 ;
     RECT  79.92 20.736 80.951 21.654 ;
     RECT  80.951 20.736 80.987 20.754 ;
    LAYER M3 ;
     RECT  46.512 0.031 46.53 0.043 ;
     RECT  46.512 0.043 46.782 0.067 ;
     RECT  52.596 0.031 52.614 0.067 ;
     RECT  46.512 0.067 47.466 0.091 ;
     RECT  51.552 0.043 51.57 0.091 ;
     RECT  52.416 0.067 52.614 0.091 ;
     RECT  56.952 0.043 56.97 0.091 ;
     RECT  50.112 0.091 52.614 0.139 ;
     RECT  55.944 0.091 55.962 0.139 ;
     RECT  56.808 0.091 58.482 0.139 ;
     RECT  50.112 0.139 52.722 0.187 ;
     RECT  46.152 0.091 47.466 0.211 ;
     RECT  46.152 0.211 48.186 0.235 ;
     RECT  50.112 0.187 53.118 0.235 ;
     RECT  50.112 0.235 53.19 0.239 ;
     RECT  53.1 0.239 53.19 0.317 ;
     RECT  55.944 0.139 58.482 0.317 ;
     RECT  54.468 0.043 54.486 0.379 ;
     RECT  50.112 0.239 52.29 0.427 ;
     RECT  49.932 0.427 52.29 0.475 ;
     RECT  54.072 0.379 54.486 0.523 ;
     RECT  49.248 0.475 52.29 0.557 ;
     RECT  50.58 0.557 52.29 1.147 ;
     RECT  53.172 0.317 53.19 1.147 ;
     RECT  54.072 0.523 54.954 1.147 ;
     RECT  55.944 0.317 58.41 1.147 ;
     RECT  49.248 0.557 49.842 1.723 ;
     RECT  50.58 1.147 59.094 1.723 ;
     RECT  41.184 1.723 41.202 1.759 ;
     RECT  45.864 0.235 48.186 1.759 ;
     RECT  36.252 1.759 36.27 1.795 ;
     RECT  43.92 1.759 43.938 1.795 ;
     RECT  37.764 1.795 37.782 1.831 ;
     RECT  35.1 1.723 35.118 1.876 ;
     RECT  38.916 1.723 38.934 1.876 ;
     RECT  39.78 1.831 39.798 1.876 ;
     RECT  41.04 1.759 41.202 1.876 ;
     RECT  42.768 1.795 42.786 1.876 ;
     RECT  35.1 1.876 35.19 1.921 ;
     RECT  36.036 1.795 36.27 1.921 ;
     RECT  38.916 1.876 39.798 1.921 ;
     RECT  42.624 1.876 42.786 1.921 ;
     RECT  43.668 1.795 43.938 1.921 ;
     RECT  44.964 1.723 44.982 1.921 ;
     RECT  49.248 1.723 59.094 1.921 ;
     RECT  32.148 1.921 32.166 1.957 ;
     RECT  33.12 1.831 33.138 1.957 ;
     RECT  37.296 1.831 37.818 1.957 ;
     RECT  40.572 1.876 41.202 1.957 ;
     RECT  45.864 1.759 48.366 1.957 ;
     RECT  49.176 1.921 59.094 1.957 ;
     RECT  44.964 1.921 45.126 1.963 ;
     RECT  45.864 1.957 59.094 1.963 ;
     RECT  35.1 1.921 36.27 1.993 ;
     RECT  42.624 1.921 43.938 1.993 ;
     RECT  59.976 0.091 59.994 1.993 ;
     RECT  38.844 1.921 39.798 2.029 ;
     RECT  40.572 1.957 41.742 2.029 ;
     RECT  59.868 1.993 59.994 2.029 ;
     RECT  32.148 1.957 33.138 2.065 ;
     RECT  34.74 1.993 36.27 2.065 ;
     RECT  37.296 1.957 37.962 2.065 ;
     RECT  38.844 2.029 41.742 2.065 ;
     RECT  42.516 1.993 43.938 2.065 ;
     RECT  38.844 2.065 43.938 2.101 ;
     RECT  44.964 1.963 59.094 2.101 ;
     RECT  59.868 2.029 60.606 2.101 ;
     RECT  13.14 2.101 13.158 2.143 ;
     RECT  29.952 1.795 29.97 2.143 ;
     RECT  44.964 2.101 61.362 2.143 ;
     RECT  62.136 0.139 62.154 2.143 ;
     RECT  29.415 2.143 29.97 2.191 ;
     RECT  30.816 2.101 30.834 2.191 ;
     RECT  31.572 2.065 33.138 2.191 ;
     RECT  17.28 2.191 17.298 2.203 ;
     RECT  18.615 2.143 18.705 2.203 ;
     RECT  12.312 2.101 12.33 2.227 ;
     RECT  13.14 2.143 13.305 2.227 ;
     RECT  15.66 2.191 15.678 2.227 ;
     RECT  16.812 2.203 18.705 2.227 ;
     RECT  22.32 2.191 22.338 2.227 ;
     RECT  24.015 2.143 24.105 2.227 ;
     RECT  38.844 2.101 44.01 2.227 ;
     RECT  67.215 2.143 67.305 2.227 ;
     RECT  68.508 2.101 68.526 2.227 ;
     RECT  71.208 2.191 71.226 2.227 ;
     RECT  12.312 2.227 13.374 2.263 ;
     RECT  20.88 2.227 20.898 2.263 ;
     RECT  23.4 2.227 24.105 2.263 ;
     RECT  27.72 2.227 27.738 2.263 ;
     RECT  28.836 2.191 29.97 2.263 ;
     RECT  30.78 2.191 30.834 2.263 ;
     RECT  31.572 2.191 33.714 2.263 ;
     RECT  44.964 2.143 62.154 2.263 ;
     RECT  64.476 2.227 64.494 2.263 ;
     RECT  71.208 2.227 71.874 2.263 ;
     RECT  72.615 2.143 72.705 2.263 ;
     RECT  28.836 2.263 30.834 2.293 ;
     RECT  31.572 2.263 33.858 2.293 ;
     RECT  14.148 2.263 14.166 2.299 ;
     RECT  27.36 2.263 27.738 2.299 ;
     RECT  28.836 2.293 33.858 2.299 ;
     RECT  34.74 2.065 37.962 2.299 ;
     RECT  14.148 2.299 14.31 2.335 ;
     RECT  15.66 2.227 16.002 2.335 ;
     RECT  16.812 2.227 19.026 2.371 ;
     RECT  20.88 2.263 21.186 2.371 ;
     RECT  22.212 2.227 22.338 2.371 ;
     RECT  23.256 2.263 24.138 2.371 ;
     RECT  25.2 2.227 25.218 2.371 ;
     RECT  26.1 2.299 26.118 2.371 ;
     RECT  27.36 2.299 37.962 2.371 ;
     RECT  38.844 2.227 44.082 2.371 ;
     RECT  63.36 2.263 63.378 2.371 ;
     RECT  64.404 2.263 64.494 2.371 ;
     RECT  65.448 2.101 65.466 2.371 ;
     RECT  66.672 2.227 68.526 2.371 ;
     RECT  69.516 2.263 69.534 2.371 ;
     RECT  71.208 2.263 72.705 2.371 ;
     RECT  74.268 2.335 74.286 2.371 ;
     RECT  2.415 2.143 2.505 2.413 ;
     RECT  7.815 2.143 7.905 2.413 ;
     RECT  12.132 2.263 13.374 2.413 ;
     RECT  14.148 2.335 16.002 2.413 ;
     RECT  23.076 2.371 24.174 2.413 ;
     RECT  71.172 2.371 72.705 2.413 ;
     RECT  78.015 2.143 78.105 2.413 ;
     RECT  44.856 2.263 62.226 2.443 ;
     RECT  63 2.371 65.466 2.443 ;
     RECT  16.812 2.371 22.338 2.461 ;
     RECT  23.076 2.413 24.297 2.461 ;
     RECT  12.132 2.413 16.002 2.497 ;
     RECT  16.812 2.461 24.297 2.497 ;
     RECT  10.8 2.299 11.394 2.569 ;
     RECT  12.132 2.497 24.297 2.569 ;
     RECT  66.672 2.371 69.894 2.587 ;
     RECT  7.815 2.413 8.097 2.605 ;
     RECT  9.936 2.371 9.954 2.605 ;
     RECT  25.2 2.371 26.226 2.605 ;
     RECT  44.856 2.443 65.466 2.605 ;
     RECT  66.6 2.587 69.894 2.605 ;
     RECT  71.172 2.413 72.897 2.605 ;
     RECT  7.488 2.605 8.694 2.641 ;
     RECT  9.792 2.605 9.954 2.641 ;
     RECT  10.8 2.569 24.297 2.641 ;
     RECT  25.2 2.605 26.334 2.641 ;
     RECT  27.36 2.371 44.082 2.641 ;
     RECT  44.856 2.605 69.894 2.641 ;
     RECT  70.956 2.605 73.062 2.641 ;
     RECT  27.072 2.641 70.218 2.731 ;
     RECT  70.956 2.641 73.242 2.731 ;
     RECT  25.164 2.641 26.334 2.767 ;
     RECT  9.576 2.641 24.297 2.779 ;
     RECT  25.092 2.767 26.334 2.779 ;
     RECT  74.268 2.371 74.61 2.827 ;
     RECT  7.488 2.641 8.838 2.861 ;
     RECT  7.596 2.861 8.838 3.001 ;
     RECT  9.576 2.779 26.334 3.001 ;
     RECT  27.072 2.731 73.242 3.001 ;
     RECT  74.016 2.827 74.61 3.001 ;
     RECT  7.596 3.001 26.334 3.109 ;
     RECT  27.072 3.001 74.61 3.109 ;
     RECT  7.596 3.109 74.61 3.145 ;
     RECT  7.596 3.145 74.646 3.541 ;
     RECT  7.596 3.541 74.682 3.685 ;
     RECT  75.42 2.803 75.438 3.685 ;
     RECT  7.596 3.685 75.438 3.811 ;
     RECT  7.596 3.811 75.546 3.875 ;
     RECT  6.048 3.613 6.066 3.919 ;
     RECT  7.596 3.875 74.718 3.919 ;
     RECT  6.048 3.919 74.718 4.801 ;
     RECT  75.528 3.875 75.546 4.801 ;
     RECT  6.048 4.801 75.582 4.919 ;
     RECT  6.048 4.919 75.438 4.927 ;
     RECT  5.76 4.927 75.438 5.161 ;
     RECT  5.688 5.161 75.438 5.539 ;
     RECT  5.292 5.539 75.438 5.755 ;
     RECT  76.428 5.071 76.446 5.755 ;
     RECT  5.292 5.755 76.446 5.999 ;
     RECT  76.32 5.999 76.446 6.781 ;
     RECT  4.284 6.511 4.302 6.817 ;
     RECT  5.292 5.999 75.582 6.817 ;
     RECT  76.32 6.781 76.626 7.079 ;
     RECT  4.284 6.817 75.582 7.321 ;
     RECT  4.284 7.321 75.798 7.339 ;
     RECT  4.248 7.339 75.798 7.385 ;
     RECT  76.608 7.079 76.626 7.429 ;
     RECT  78.015 2.413 78.297 7.699 ;
     RECT  76.608 7.429 76.806 7.771 ;
     RECT  77.832 7.699 78.297 7.771 ;
     RECT  4.284 7.385 75.798 7.861 ;
     RECT  76.608 7.771 76.95 7.861 ;
     RECT  4.284 7.861 76.95 7.889 ;
     RECT  4.284 7.889 76.806 8.401 ;
     RECT  77.832 7.771 78.642 8.401 ;
     RECT  77.832 8.401 79.11 8.537 ;
     RECT  4.248 8.401 76.806 8.581 ;
     RECT  4.14 8.581 76.806 8.735 ;
     RECT  4.248 8.735 76.806 8.779 ;
     RECT  77.832 8.537 78.786 8.779 ;
     RECT  4.248 8.779 78.786 10.093 ;
     RECT  4.248 10.093 78.93 10.561 ;
     RECT  4.248 10.561 79.218 10.741 ;
     RECT  4.248 10.741 79.794 10.859 ;
     RECT  4.248 10.859 79.146 11.551 ;
     RECT  4.14 11.551 79.146 12.055 ;
     RECT  3.96 12.055 79.146 12.091 ;
     RECT  3.96 12.091 79.794 12.209 ;
     RECT  3.96 12.209 79.326 13.019 ;
     RECT  3.96 13.019 28.134 13.469 ;
     RECT  28.98 13.019 79.074 13.801 ;
     RECT  4.392 13.469 28.134 13.945 ;
     RECT  28.98 13.801 79.182 13.945 ;
     RECT  4.392 13.945 79.182 13.981 ;
     RECT  4.392 13.981 79.578 14.099 ;
     RECT  4.392 14.099 79.254 14.215 ;
     RECT  4.068 14.215 79.254 14.639 ;
     RECT  4.068 14.639 5.67 14.675 ;
     RECT  6.624 14.639 79.254 15.359 ;
     RECT  4.068 14.675 5.454 15.421 ;
     RECT  6.624 15.359 79.038 15.421 ;
     RECT  2.415 2.413 2.697 15.493 ;
     RECT  2.415 15.493 3.078 15.529 ;
     RECT  4.068 15.421 79.038 15.529 ;
     RECT  2.415 15.529 79.038 15.719 ;
     RECT  2.415 15.719 78.822 16.501 ;
     RECT  2.415 16.501 79.002 16.565 ;
     RECT  3.42 16.565 79.002 16.943 ;
     RECT  3.78 16.943 79.002 17.041 ;
     RECT  3.78 17.041 79.182 17.455 ;
     RECT  2.415 16.565 2.697 18.265 ;
     RECT  3.78 17.455 79.254 18.265 ;
     RECT  2.415 18.265 79.254 18.419 ;
     RECT  2.415 18.419 79.182 19.499 ;
     RECT  2.415 19.499 78.858 19.679 ;
     RECT  2.415 19.679 78.714 19.877 ;
     RECT  2.415 19.877 78.498 20.695 ;
     RECT  2.415 20.695 78.822 20.731 ;
     RECT  80.964 20.731 80.982 21.211 ;
     RECT  80.784 21.211 80.982 21.299 ;
     RECT  80.928 21.299 80.982 21.341 ;
     RECT  2.415 20.731 79.326 21.389 ;
     RECT  2.415 21.389 79.182 21.425 ;
     RECT  80.928 21.341 80.946 21.659 ;
     RECT  2.415 21.425 79.146 21.929 ;
     RECT  2.415 21.929 79.002 21.965 ;
     RECT  2.415 21.965 78.966 22.199 ;
     RECT  2.415 22.199 78.822 22.235 ;
     RECT  2.415 22.235 78.678 22.469 ;
     RECT  2.415 22.469 78.498 22.505 ;
     RECT  2.415 22.505 78.462 23.629 ;
     RECT  2.415 23.629 78.822 24.133 ;
     RECT  2.34 24.133 78.822 24.331 ;
     RECT  2.34 24.331 79.362 24.511 ;
     RECT  2.34 24.511 79.47 24.629 ;
     RECT  2.34 24.629 79.362 24.773 ;
     RECT  2.34 24.773 44.01 24.809 ;
     RECT  44.892 24.773 79.362 24.899 ;
     RECT  44.892 24.899 79.218 25.007 ;
     RECT  44.892 25.007 79.11 25.555 ;
     RECT  2.34 24.809 43.974 25.591 ;
     RECT  44.856 25.555 79.11 25.591 ;
     RECT  2.34 25.591 79.11 26.131 ;
     RECT  2.34 26.131 79.794 26.249 ;
     RECT  2.34 26.249 79.578 26.933 ;
     RECT  57.564 26.933 79.578 27.059 ;
     RECT  57.564 27.059 79.11 27.365 ;
     RECT  2.34 26.933 56.826 27.715 ;
     RECT  57.564 27.365 79.074 27.715 ;
     RECT  2.34 27.715 79.074 28.247 ;
     RECT  2.415 28.247 79.074 28.291 ;
     RECT  2.415 28.291 79.794 28.409 ;
     RECT  2.415 28.409 79.074 29.405 ;
     RECT  75.204 29.405 79.074 29.641 ;
     RECT  2.415 29.405 74.358 29.803 ;
     RECT  2.376 29.803 74.358 30.569 ;
     RECT  2.415 30.569 74.358 30.613 ;
     RECT  75.204 29.641 79.794 30.613 ;
     RECT  2.415 30.613 79.794 31.379 ;
     RECT  2.415 31.379 79.002 31.531 ;
     RECT  2.376 31.531 79.002 32.189 ;
     RECT  79.776 31.379 79.794 32.999 ;
     RECT  2.376 32.189 78.93 33.421 ;
     RECT  2.376 33.421 79.578 33.539 ;
     RECT  2.376 33.539 79.254 33.917 ;
     RECT  2.376 33.917 79.218 34.735 ;
     RECT  2.304 34.735 79.218 34.771 ;
     RECT  2.304 34.771 79.794 34.889 ;
     RECT  2.304 34.889 79.686 35.429 ;
     RECT  2.304 35.429 79.218 35.815 ;
     RECT  2.196 35.815 79.218 36.931 ;
     RECT  2.196 36.931 79.362 37.741 ;
     RECT  2.196 37.741 79.578 37.859 ;
     RECT  2.196 37.859 78.894 38.471 ;
     RECT  2.196 38.471 78.534 39.119 ;
     RECT  0.576 39.019 0.594 39.253 ;
     RECT  0.576 39.253 0.63 39.821 ;
     RECT  0.576 39.821 0.594 39.917 ;
     RECT  2.232 39.119 78.534 40.219 ;
     RECT  1.728 40.219 78.534 40.325 ;
     RECT  2.196 40.325 78.534 40.711 ;
     RECT  2.196 40.711 78.966 40.829 ;
     RECT  2.304 40.829 78.534 40.865 ;
     RECT  2.376 40.865 78.534 40.937 ;
     RECT  2.376 40.937 78.39 41.755 ;
     RECT  2.304 41.755 78.39 41.899 ;
     RECT  1.98 41.899 78.39 42.139 ;
     RECT  1.728 42.139 78.39 42.755 ;
     RECT  2.124 42.755 78.39 43.807 ;
     RECT  2.124 43.807 79.038 43.853 ;
     RECT  2.124 43.853 78.822 43.871 ;
     RECT  1.152 43.051 1.17 44.105 ;
     RECT  2.16 43.871 78.822 44.609 ;
     RECT  2.16 44.609 78.297 45.797 ;
     RECT  2.196 45.797 78.297 46.381 ;
     RECT  2.196 46.381 78.57 46.877 ;
     RECT  2.304 46.877 78.57 47.191 ;
     RECT  2.304 47.191 78.822 47.309 ;
     RECT  2.304 47.309 78.39 47.381 ;
     RECT  2.304 47.381 2.862 47.579 ;
     RECT  2.304 47.579 2.826 47.759 ;
     RECT  2.34 47.759 2.826 47.849 ;
     RECT  2.34 47.849 2.697 47.885 ;
     RECT  3.672 47.381 78.39 48.731 ;
     RECT  3.672 48.731 78.354 48.901 ;
     RECT  3.636 48.901 78.354 49.009 ;
     RECT  79.128 49.081 79.146 49.199 ;
     RECT  3.564 49.009 78.354 49.315 ;
     RECT  3.492 49.315 78.354 49.373 ;
     RECT  3.564 49.373 78.354 49.621 ;
     RECT  3.564 49.621 78.966 49.811 ;
     RECT  25.56 49.811 78.966 49.919 ;
     RECT  25.56 49.919 78.498 50.009 ;
     RECT  3.564 49.811 24.822 50.081 ;
     RECT  25.56 50.009 78.354 50.117 ;
     RECT  3.564 50.081 12.114 50.279 ;
     RECT  2.415 47.885 2.697 50.395 ;
     RECT  3.564 50.279 4.77 50.395 ;
     RECT  2.415 50.395 4.77 50.432 ;
     RECT  12.96 50.081 24.822 50.665 ;
     RECT  25.56 50.117 78.297 50.665 ;
     RECT  5.58 50.279 12.114 50.827 ;
     RECT  12.96 50.665 78.297 50.827 ;
     RECT  3.528 50.432 4.77 51.097 ;
     RECT  5.58 50.827 78.297 51.097 ;
     RECT  3.528 51.097 78.297 51.169 ;
     RECT  3.528 51.169 78.714 51.269 ;
     RECT  3.528 51.269 78.642 51.359 ;
     RECT  2.415 50.432 2.697 51.475 ;
     RECT  3.528 51.359 78.57 51.475 ;
     RECT  2.415 51.475 78.57 52.213 ;
     RECT  2.415 52.213 78.678 52.321 ;
     RECT  2.415 52.321 78.894 52.439 ;
     RECT  2.415 52.439 78.57 53.221 ;
     RECT  2.415 53.221 78.642 53.401 ;
     RECT  2.415 53.401 78.786 53.519 ;
     RECT  2.415 53.519 78.57 53.591 ;
     RECT  3.42 53.591 78.57 54.095 ;
     RECT  15.408 54.095 78.57 54.401 ;
     RECT  21.996 54.401 78.57 54.667 ;
     RECT  21.996 54.667 78.75 54.869 ;
     RECT  3.42 54.095 14.67 54.949 ;
     RECT  15.408 54.401 21.258 54.949 ;
     RECT  22.068 54.869 78.75 55.021 ;
     RECT  22.068 55.021 79.47 55.139 ;
     RECT  3.42 54.949 21.258 55.651 ;
     RECT  22.068 55.139 78.786 55.651 ;
     RECT  3.42 55.651 78.786 56.641 ;
     RECT  3.42 56.641 78.966 56.759 ;
     RECT  2.415 53.591 2.697 57.109 ;
     RECT  3.42 56.759 78.786 57.109 ;
     RECT  2.415 57.109 78.786 58.225 ;
     RECT  2.415 58.225 78.966 58.531 ;
     RECT  2.415 58.531 79.362 59.341 ;
     RECT  2.415 59.341 79.398 59.459 ;
     RECT  2.415 59.459 79.146 60.305 ;
     RECT  53.136 60.305 79.146 60.421 ;
     RECT  53.136 60.421 79.794 60.539 ;
     RECT  2.415 60.305 52.398 61.123 ;
     RECT  53.136 60.539 79.146 61.123 ;
     RECT  2.415 61.123 79.146 61.771 ;
     RECT  2.415 61.771 79.254 62.041 ;
     RECT  2.415 62.041 79.794 62.699 ;
     RECT  2.415 62.699 79.146 63.101 ;
     RECT  2.415 63.101 69.498 63.931 ;
     RECT  70.236 63.101 79.146 63.931 ;
     RECT  2.415 63.931 79.146 65.165 ;
     RECT  2.415 65.165 79.002 65.669 ;
     RECT  79.776 65.551 79.794 65.669 ;
     RECT  76.932 65.669 78.498 65.777 ;
     RECT  77.004 65.777 78.498 66.119 ;
     RECT  77.22 66.119 78.498 66.209 ;
     RECT  2.415 65.669 76.194 66.559 ;
     RECT  2.415 66.559 76.482 66.749 ;
     RECT  2.415 66.749 76.338 67.019 ;
     RECT  75.024 67.019 76.338 67.289 ;
     RECT  77.22 66.209 78.297 67.829 ;
     RECT  2.415 67.019 74.286 67.909 ;
     RECT  75.024 67.289 76.266 67.909 ;
     RECT  2.415 67.909 76.266 68.099 ;
     RECT  3.528 68.099 76.266 68.377 ;
     RECT  77.22 67.829 77.238 68.441 ;
     RECT  3.528 68.377 76.446 68.791 ;
     RECT  78.015 67.829 78.297 68.791 ;
     RECT  3.528 68.791 76.554 68.909 ;
     RECT  77.292 68.791 78.297 68.909 ;
     RECT  3.528 68.909 8.838 68.945 ;
     RECT  2.415 68.099 2.697 68.971 ;
     RECT  3.528 68.945 8.73 68.971 ;
     RECT  2.415 68.971 8.73 69.449 ;
     RECT  77.436 68.909 78.297 69.449 ;
     RECT  2.415 69.449 3.186 69.485 ;
     RECT  4.284 69.449 4.302 69.491 ;
     RECT  5.184 69.449 8.73 69.763 ;
     RECT  5.184 69.763 8.874 69.835 ;
     RECT  9.612 68.909 76.518 69.835 ;
     RECT  5.184 69.835 76.518 70.025 ;
     RECT  5.184 70.025 6.03 70.411 ;
     RECT  6.876 70.025 76.518 70.411 ;
     RECT  78.015 69.449 78.297 70.411 ;
     RECT  6.876 70.411 76.662 70.529 ;
     RECT  77.4 70.411 78.297 70.529 ;
     RECT  5.148 70.411 6.03 70.915 ;
     RECT  5.004 70.915 6.03 70.951 ;
     RECT  6.876 70.529 76.518 70.951 ;
     RECT  5.004 70.951 76.518 71.261 ;
     RECT  5.004 71.261 5.886 71.339 ;
     RECT  6.66 71.261 76.518 71.491 ;
     RECT  78.015 70.529 78.297 71.491 ;
     RECT  6.66 71.491 76.662 71.609 ;
     RECT  77.4 71.491 78.297 71.609 ;
     RECT  5.652 71.339 5.886 71.753 ;
     RECT  76.392 71.609 76.446 71.789 ;
     RECT  5.724 71.753 5.886 72.149 ;
     RECT  5.76 72.149 5.886 72.193 ;
     RECT  6.66 71.609 75.582 72.193 ;
     RECT  5.76 72.193 75.582 72.491 ;
     RECT  6.228 72.491 75.582 72.571 ;
     RECT  6.228 72.571 75.618 72.955 ;
     RECT  76.392 71.789 76.41 72.955 ;
     RECT  6.228 72.955 76.41 72.995 ;
     RECT  7.02 72.995 76.41 73.031 ;
     RECT  7.02 73.031 75.942 73.067 ;
     RECT  7.02 73.067 75.87 73.229 ;
     RECT  7.02 73.229 75.762 73.409 ;
     RECT  7.02 73.409 75.402 73.679 ;
     RECT  7.02 73.679 75.33 73.769 ;
     RECT  7.02 73.769 75.258 74.039 ;
     RECT  22.752 74.039 74.61 74.075 ;
     RECT  22.752 74.075 74.106 74.147 ;
     RECT  55.548 74.147 74.106 74.219 ;
     RECT  55.584 74.219 73.71 74.381 ;
     RECT  55.584 74.381 73.314 74.453 ;
     RECT  7.02 74.039 21.978 74.579 ;
     RECT  15.228 74.579 21.978 74.651 ;
     RECT  55.584 74.453 71.226 74.651 ;
     RECT  15.732 74.651 21.978 74.827 ;
     RECT  22.752 74.147 54.81 74.827 ;
     RECT  72 74.453 73.314 74.849 ;
     RECT  7.02 74.579 14.49 74.885 ;
     RECT  7.02 74.885 14.13 74.921 ;
     RECT  72 74.849 73.062 74.993 ;
     RECT  15.732 74.827 54.81 75.001 ;
     RECT  55.584 74.651 70.686 75.001 ;
     RECT  7.344 74.921 14.13 75.029 ;
     RECT  9.828 75.029 14.13 75.119 ;
     RECT  7.344 75.029 9.054 75.155 ;
     RECT  15.732 75.001 70.686 75.155 ;
     RECT  9.828 75.119 13.95 75.2 ;
     RECT  9.864 75.2 13.95 75.227 ;
     RECT  9.936 75.227 13.95 75.389 ;
     RECT  9.936 75.389 12.222 75.425 ;
     RECT  12.996 75.389 13.497 75.425 ;
     RECT  15.912 75.155 70.686 75.425 ;
     RECT  15.912 75.425 69.282 75.461 ;
     RECT  16.668 75.461 69.282 75.533 ;
     RECT  9.936 75.425 11.034 75.539 ;
     RECT  70.056 75.425 70.686 75.541 ;
     RECT  15.912 75.461 15.93 75.569 ;
     RECT  7.815 75.155 9.054 75.659 ;
     RECT  10.728 75.539 11.034 75.659 ;
     RECT  70.056 75.541 70.722 75.659 ;
     RECT  7.815 75.659 8.982 75.695 ;
     RECT  10.836 75.659 11.034 75.695 ;
     RECT  16.668 75.533 69.03 75.695 ;
     RECT  16.884 75.695 69.03 75.731 ;
     RECT  70.056 75.659 70.182 75.731 ;
     RECT  9.936 75.539 9.954 75.767 ;
     RECT  12.204 75.425 12.222 75.767 ;
     RECT  18.36 75.731 69.03 75.767 ;
     RECT  7.815 75.695 8.802 75.803 ;
     RECT  10.836 75.695 10.854 75.803 ;
     RECT  16.884 75.731 17.478 75.803 ;
     RECT  18.615 75.767 69.03 75.839 ;
     RECT  70.164 75.731 70.182 75.929 ;
     RECT  16.884 75.803 17.154 76.001 ;
     RECT  16.884 76.001 16.902 76.109 ;
     RECT  18.615 75.839 68.706 76.349 ;
     RECT  18.615 76.349 67.497 76.469 ;
     RECT  68.364 76.349 68.706 76.469 ;
     RECT  58.788 76.469 67.497 76.541 ;
     RECT  18.615 76.469 58.05 76.649 ;
     RECT  58.896 76.541 67.497 76.649 ;
     RECT  68.364 76.469 68.598 76.649 ;
     RECT  21.096 76.649 58.05 76.739 ;
     RECT  66.384 76.649 67.497 76.739 ;
     RECT  58.896 76.649 65.43 76.775 ;
     RECT  63.864 76.775 65.43 76.781 ;
     RECT  20.052 76.649 20.322 76.811 ;
     RECT  64.548 76.781 65.43 76.811 ;
     RECT  21.096 76.739 57.222 76.847 ;
     RECT  21.096 76.847 35.838 76.883 ;
     RECT  58.896 76.775 62.982 76.883 ;
     RECT  66.672 76.739 67.497 76.883 ;
     RECT  68.364 76.649 68.382 76.883 ;
     RECT  21.24 76.883 35.838 76.919 ;
     RECT  58.032 76.739 58.05 76.919 ;
     RECT  58.896 76.883 62.55 76.919 ;
     RECT  64.548 76.811 64.674 76.919 ;
     RECT  58.896 76.919 62.097 76.925 ;
     RECT  36.576 76.847 57.222 77.009 ;
     RECT  59.04 76.925 62.097 77.009 ;
     RECT  59.22 77.009 62.097 77.045 ;
     RECT  61.632 77.045 62.097 77.117 ;
     RECT  59.22 77.045 59.31 77.153 ;
     RECT  36.576 77.009 55.566 77.279 ;
     RECT  59.22 77.153 59.238 77.279 ;
     RECT  60.408 77.045 60.426 77.279 ;
     RECT  21.456 76.919 35.838 77.585 ;
     RECT  21.744 77.585 35.838 77.665 ;
     RECT  36.576 77.279 55.494 77.665 ;
     RECT  21.744 77.665 55.494 77.855 ;
     RECT  56.415 77.009 56.697 77.971 ;
     RECT  21.78 77.855 55.494 78.089 ;
     RECT  56.268 77.971 56.697 78.089 ;
     RECT  21.78 78.089 54.522 78.125 ;
     RECT  21.78 78.125 25.11 78.197 ;
     RECT  23.076 78.197 25.074 78.221 ;
     RECT  21.816 78.197 21.978 78.233 ;
     RECT  55.332 78.089 55.35 78.233 ;
     RECT  21.96 78.233 21.978 78.359 ;
     RECT  23.076 78.221 24.966 78.359 ;
     RECT  25.848 78.125 54.126 78.359 ;
     RECT  26.064 78.359 27.954 78.395 ;
     RECT  23.076 78.359 24.297 78.431 ;
     RECT  26.064 78.395 27.09 78.431 ;
     RECT  28.728 78.359 54.054 78.431 ;
     RECT  26.136 78.431 27.09 78.467 ;
     RECT  27.828 78.395 27.882 78.467 ;
     RECT  26.136 78.467 26.154 78.503 ;
     RECT  26.928 78.467 27.09 78.629 ;
     RECT  27.864 78.467 27.882 78.629 ;
     RECT  45.576 78.431 54.054 78.629 ;
     RECT  26.928 78.629 26.946 78.665 ;
     RECT  28.728 78.431 44.73 78.701 ;
     RECT  43.488 78.701 44.73 78.737 ;
     RECT  43.524 78.737 44.73 78.773 ;
     RECT  28.728 78.701 42.678 78.899 ;
     RECT  28.728 78.899 39.474 78.935 ;
     RECT  41.544 78.899 41.994 78.971 ;
     RECT  45.576 78.629 53.586 78.971 ;
     RECT  45.576 78.971 49.626 79.043 ;
     RECT  45.576 79.043 47.286 79.079 ;
     RECT  41.688 78.971 41.994 79.169 ;
     RECT  29.088 78.935 39.294 79.241 ;
     RECT  34.632 79.241 39.294 79.277 ;
     RECT  45.576 79.079 47.178 79.277 ;
     RECT  52.92 78.971 53.586 79.277 ;
     RECT  31.068 79.241 33.822 79.313 ;
     RECT  44.1 78.773 44.73 79.313 ;
     RECT  45.576 79.277 46.782 79.321 ;
     RECT  44.82 79.321 46.782 79.349 ;
     RECT  29.088 79.241 30.33 79.439 ;
     RECT  31.104 79.313 31.878 79.439 ;
     RECT  34.632 79.277 37.422 79.439 ;
     RECT  38.196 79.277 39.294 79.439 ;
     RECT  44.82 79.349 46.314 79.439 ;
     RECT  48.168 79.043 48.33 79.439 ;
     RECT  49.104 79.043 49.626 79.439 ;
     RECT  50.4 78.971 52.146 79.439 ;
     RECT  52.92 79.277 53.226 79.439 ;
     RECT  37.26 79.439 37.278 79.469 ;
     RECT  48.168 79.439 48.186 79.469 ;
     RECT  49.248 79.439 49.266 79.469 ;
     RECT  29.088 79.439 30.186 79.475 ;
     RECT  31.14 79.439 31.878 79.475 ;
     RECT  32.616 79.313 33.822 79.475 ;
     RECT  38.268 79.439 38.826 79.475 ;
     RECT  50.4 79.439 52.002 79.475 ;
     RECT  53.064 79.439 53.154 79.475 ;
     RECT  34.632 79.439 36.522 79.511 ;
     RECT  34.632 79.511 35.262 79.583 ;
     RECT  38.268 79.475 38.574 79.583 ;
     RECT  32.616 79.475 32.814 79.619 ;
     RECT  36.504 79.511 36.522 79.619 ;
     RECT  38.268 79.583 38.286 79.619 ;
     RECT  2.415 69.485 2.697 79.667 ;
     RECT  7.815 75.803 8.097 79.667 ;
     RECT  13.215 75.425 13.497 79.667 ;
     RECT  18.615 76.649 18.897 79.667 ;
     RECT  24.015 78.431 24.297 79.667 ;
     RECT  29.415 79.475 29.697 79.667 ;
     RECT  34.632 79.583 35.097 79.667 ;
     RECT  40.215 78.899 40.497 79.667 ;
     RECT  51.015 79.475 51.297 79.667 ;
     RECT  56.415 78.089 56.697 79.667 ;
     RECT  61.815 77.117 62.097 79.667 ;
     RECT  67.215 76.883 67.497 79.667 ;
     RECT  72.615 74.993 72.897 79.667 ;
     RECT  78.015 71.609 78.297 79.667 ;
     RECT  31.14 79.475 31.698 79.709 ;
     RECT  32.616 79.619 32.778 79.709 ;
     RECT  33.552 79.475 33.822 79.709 ;
     RECT  34.632 79.667 34.905 79.709 ;
     RECT  43.992 79.555 44.01 79.709 ;
     RECT  45.576 79.439 46.314 79.709 ;
     RECT  53.136 79.475 53.154 79.709 ;
     RECT  31.14 79.709 31.194 79.745 ;
     RECT  54 79.591 54.018 79.781 ;
     RECT  2.415 79.667 2.505 79.937 ;
     RECT  7.815 79.667 7.905 79.937 ;
     RECT  13.215 79.667 13.305 79.937 ;
     RECT  18.615 79.667 18.705 79.937 ;
     RECT  24.015 79.667 24.105 79.937 ;
     RECT  29.415 79.667 29.505 79.937 ;
     RECT  34.815 79.709 34.905 79.937 ;
     RECT  40.215 79.667 40.305 79.937 ;
     RECT  45.615 79.709 45.705 79.937 ;
     RECT  51.015 79.667 51.105 79.937 ;
     RECT  56.415 79.667 56.505 79.937 ;
     RECT  61.815 79.667 61.905 79.937 ;
     RECT  67.215 79.667 67.305 79.937 ;
     RECT  72.615 79.667 72.705 79.937 ;
     RECT  78.015 79.667 78.105 79.937 ;
    LAYER M4 ;
     RECT  0.037 39.072 0.085 39.096 ;
     RECT  0.037 42 0.085 42.024 ;
     RECT  0.037 34.752 0.133 34.776 ;
     RECT  0.085 38.976 0.133 39.096 ;
     RECT  0.085 40.08 0.133 42.696 ;
     RECT  0.085 45.12 0.133 45.144 ;
     RECT  0.037 47.328 0.133 47.352 ;
     RECT  0.133 38.976 0.181 42.696 ;
     RECT  0.181 37.392 0.277 37.416 ;
     RECT  0.133 45.024 0.323 45.24 ;
     RECT  0.277 37.344 0.325 37.416 ;
     RECT  0.181 38.976 0.373 43.08 ;
     RECT  0.325 36.912 0.469 37.416 ;
     RECT  0.133 34.752 0.517 35.304 ;
     RECT  0.373 38.448 0.517 43.08 ;
     RECT  0.517 38.448 0.641 43.896 ;
     RECT  0.641 40.08 1.181 43.896 ;
     RECT  0.641 38.448 2.293 39 ;
     RECT  1.181 40.08 2.293 42.696 ;
     RECT  1.181 43.872 2.293 43.896 ;
     RECT  0.323 45.024 2.293 45.144 ;
     RECT  0.517 34.752 2.365 35.352 ;
     RECT  0.133 47.328 2.401 47.784 ;
     RECT  2.365 27.888 2.408 27.912 ;
     RECT  2.365 34.128 2.408 35.352 ;
     RECT  0.469 36.384 2.408 37.416 ;
     RECT  2.293 38.448 2.408 42.696 ;
     RECT  2.293 43.872 2.408 45.72 ;
     RECT  2.401 47.04 2.408 47.784 ;
     RECT  2.408 2.148 2.512 79.932 ;
     RECT  2.512 2.418 2.704 79.662 ;
     RECT  2.704 43.152 2.801 47.352 ;
     RECT  2.704 66.576 2.867 69.48 ;
     RECT  2.704 22.608 2.873 22.824 ;
     RECT  2.704 33.888 2.909 42.072 ;
     RECT  2.704 65.136 2.917 65.592 ;
     RECT  2.909 40.08 3.011 42.072 ;
     RECT  2.801 43.632 3.089 47.352 ;
     RECT  2.704 18.432 3.107 19.992 ;
     RECT  2.704 60.528 3.107 63.864 ;
     RECT  2.867 68.976 3.197 69.48 ;
     RECT  3.107 61.44 3.233 63.864 ;
     RECT  2.704 27.888 3.269 29.784 ;
     RECT  2.867 66.576 3.277 67.512 ;
     RECT  3.107 19.968 3.341 19.992 ;
     RECT  2.909 33.888 3.413 39 ;
     RECT  3.089 45.552 3.443 47.352 ;
     RECT  3.443 45.696 3.449 47.352 ;
     RECT  2.704 49.344 3.539 49.368 ;
     RECT  2.704 25.248 3.697 25.272 ;
     RECT  3.449 45.696 3.773 46.2 ;
     RECT  2.704 58.128 3.805 58.152 ;
     RECT  3.805 58.128 3.845 58.392 ;
     RECT  3.011 40.416 3.881 42.072 ;
     RECT  2.917 65.568 3.905 65.592 ;
     RECT  3.697 25.248 3.913 25.32 ;
     RECT  3.413 38.064 3.917 39 ;
     RECT  2.704 50.4 3.949 50.424 ;
     RECT  2.704 51.84 3.949 51.864 ;
     RECT  2.704 56.4 3.949 56.424 ;
     RECT  3.805 21.504 3.971 21.528 ;
     RECT  3.233 61.44 3.971 63 ;
     RECT  3.917 38.16 3.981 39 ;
     RECT  3.269 28.8 3.985 29.784 ;
     RECT  2.704 26.688 4.021 26.712 ;
     RECT  3.107 18.432 4.025 18.552 ;
     RECT  3.277 67.488 4.025 67.512 ;
     RECT  4.021 26.448 4.093 26.712 ;
     RECT  3.949 56.4 4.093 56.76 ;
     RECT  3.971 61.44 4.117 62.184 ;
     RECT  3.949 50.4 4.129 51.864 ;
     RECT  4.117 60.672 4.129 62.184 ;
     RECT  3.905 65.472 4.129 65.592 ;
     RECT  3.985 28.8 4.165 29.832 ;
     RECT  2.704 30.96 4.165 30.984 ;
     RECT  4.129 50.16 4.169 51.864 ;
     RECT  4.093 56.4 4.169 56.808 ;
     RECT  4.129 59.808 4.205 62.184 ;
     RECT  3.413 33.888 4.241 37.08 ;
     RECT  3.197 69.456 4.313 69.48 ;
     RECT  4.093 26.352 4.417 26.712 ;
     RECT  3.845 58.176 4.417 58.392 ;
     RECT  3.913 25.2 4.453 25.32 ;
     RECT  4.417 26.352 4.453 26.76 ;
     RECT  3.773 46.08 4.453 46.2 ;
     RECT  3.449 47.28 4.453 47.352 ;
     RECT  4.129 65.376 4.453 65.592 ;
     RECT  3.981 38.976 4.46 39 ;
     RECT  4.241 33.888 4.489 37.032 ;
     RECT  3.881 41.376 4.489 42.072 ;
     RECT  3.089 43.632 4.489 44.472 ;
     RECT  4.453 65.376 4.489 65.784 ;
     RECT  4.169 56.736 4.493 56.808 ;
     RECT  4.205 60.96 4.529 62.184 ;
     RECT  4.165 28.8 4.547 30.984 ;
     RECT  4.46 38.976 4.547 39.144 ;
     RECT  4.169 50.16 4.561 50.184 ;
     RECT  2.873 22.608 4.597 22.776 ;
     RECT  4.025 18.528 4.601 18.552 ;
     RECT  4.561 49.584 4.601 50.184 ;
     RECT  4.489 41.376 4.643 44.472 ;
     RECT  4.489 64.848 4.669 65.784 ;
     RECT  4.547 29.808 4.741 30.984 ;
     RECT  4.345 32.064 4.741 32.088 ;
     RECT  4.741 29.808 4.777 32.088 ;
     RECT  4.489 33.072 4.777 37.032 ;
     RECT  4.493 56.784 4.781 56.808 ;
     RECT  4.7 20.736 4.787 20.76 ;
     RECT  4.643 44.448 4.813 44.472 ;
     RECT  4.169 51.216 4.885 51.864 ;
     RECT  4.597 22.608 4.921 22.824 ;
     RECT  4.453 46.08 4.921 47.352 ;
     RECT  4.547 38.976 4.957 39 ;
     RECT  4.201 53.76 4.961 53.784 ;
     RECT  4.885 51.216 4.969 52.536 ;
     RECT  4.601 49.584 4.981 49.608 ;
     RECT  4.453 25.2 4.993 26.76 ;
     RECT  4.777 27.984 4.993 28.392 ;
     RECT  4.777 29.808 4.997 37.032 ;
     RECT  5.029 11.424 5.065 11.448 ;
     RECT  4.561 17.04 5.065 17.064 ;
     RECT  4.813 18.672 5.065 18.696 ;
     RECT  4.021 24.096 5.065 24.12 ;
     RECT  4.993 25.2 5.065 28.392 ;
     RECT  4.981 48.96 5.069 49.608 ;
     RECT  4.529 62.16 5.069 62.184 ;
     RECT  5.065 24.096 5.077 28.392 ;
     RECT  4.417 58.176 5.101 58.68 ;
     RECT  4.997 33.072 5.105 37.032 ;
     RECT  5.125 21.504 5.173 21.528 ;
     RECT  4.921 22.608 5.173 22.92 ;
     RECT  5.065 15.984 5.177 17.112 ;
     RECT  5.105 35.712 5.177 37.032 ;
     RECT  4.813 44.448 5.209 44.904 ;
     RECT  4.997 29.808 5.213 32.088 ;
     RECT  4.969 51.216 5.213 52.488 ;
     RECT  5.101 58.128 5.213 58.68 ;
     RECT  4.669 64.416 5.245 65.784 ;
     RECT  4.993 67.872 5.245 67.896 ;
     RECT  5.245 67.872 5.281 68.424 ;
     RECT  5.173 21.504 5.321 22.92 ;
     RECT  4.237 7.344 5.389 7.368 ;
     RECT  5.389 6.672 5.429 7.368 ;
     RECT  5.213 51.216 5.429 51.864 ;
     RECT  5.245 64.416 5.429 66.744 ;
     RECT  5.321 21.744 5.533 22.92 ;
     RECT  5.429 51.216 5.533 51.24 ;
     RECT  4.205 59.808 5.533 59.832 ;
     RECT  5.105 33.072 5.573 34.728 ;
     RECT  5.209 44.448 5.573 45 ;
     RECT  5.065 18.672 5.605 18.792 ;
     RECT  4.529 60.96 5.605 60.984 ;
     RECT  5.533 59.76 5.617 59.88 ;
     RECT  5.065 10.8 5.641 11.448 ;
     RECT  5.533 21.744 5.641 23.064 ;
     RECT  5.077 24.096 5.641 26.712 ;
     RECT  5.429 64.416 5.641 65.784 ;
     RECT  5.573 44.976 5.645 45 ;
     RECT  4.921 46.08 5.645 47.928 ;
     RECT  5.137 55.392 5.649 55.416 ;
     RECT  4.643 41.376 5.677 43.368 ;
     RECT  5.641 21.744 5.681 26.712 ;
     RECT  5.605 18.672 5.692 19.656 ;
     RECT  5.569 9.552 5.699 9.576 ;
     RECT  5.649 55.008 5.699 55.416 ;
     RECT  5.429 6.672 5.749 7.128 ;
     RECT  5.645 46.752 5.749 47.928 ;
     RECT  5.281 67.824 5.749 68.424 ;
     RECT  5.069 49.584 5.753 49.608 ;
     RECT  5.749 67.776 5.789 68.424 ;
     RECT  5.177 35.76 5.821 37.032 ;
     RECT  4.957 38.016 5.821 39 ;
     RECT  5.677 41.184 6.001 43.368 ;
     RECT  5.749 5.856 6.077 7.128 ;
     RECT  5.681 21.792 6.109 26.712 ;
     RECT  5.177 15.984 6.145 16.824 ;
     RECT  5.699 55.008 6.145 55.032 ;
     RECT  5.692 18.672 6.217 18.984 ;
     RECT  5.077 27.888 6.217 28.392 ;
     RECT  5.213 29.808 6.217 31.608 ;
     RECT  5.573 33.6 6.217 34.728 ;
     RECT  5.821 35.76 6.217 39 ;
     RECT  6.217 27.888 6.221 31.608 ;
     RECT  5.605 60.96 6.221 61.032 ;
     RECT  5.641 64.368 6.293 65.784 ;
     RECT  5.749 71.232 6.293 71.256 ;
     RECT  6.217 33.6 6.325 39 ;
     RECT  6.109 21.792 6.365 26.856 ;
     RECT  6.077 7.104 6.401 7.128 ;
     RECT  6.365 21.792 6.437 23.064 ;
     RECT  6.145 13.584 6.505 13.608 ;
     RECT  6.001 40.656 6.541 43.368 ;
     RECT  6.145 15.456 6.545 16.824 ;
     RECT  6.293 64.368 6.577 65.16 ;
     RECT  5.617 59.856 6.581 59.88 ;
     RECT  6.397 32.304 6.613 32.328 ;
     RECT  6.325 33.6 6.613 39.384 ;
     RECT  6.217 45.504 6.613 45.624 ;
     RECT  5.749 46.752 6.613 48.552 ;
     RECT  6.505 66.192 6.613 66.216 ;
     RECT  5.965 56.304 6.685 56.328 ;
     RECT  5.9 62.4 6.685 62.424 ;
     RECT  6.577 64.128 6.685 65.16 ;
     RECT  5.789 67.776 6.716 68.376 ;
     RECT  6.545 15.456 6.721 15.768 ;
     RECT  6.365 24.24 6.721 26.856 ;
     RECT  6.221 27.888 6.721 31.224 ;
     RECT  6.613 45.504 6.721 48.552 ;
     RECT  6.397 52.416 6.721 52.44 ;
     RECT  6.685 62.4 6.761 65.16 ;
     RECT  6.613 32.304 6.793 39.384 ;
     RECT  6.541 40.656 6.793 43.656 ;
     RECT  6.145 54.672 6.793 55.032 ;
     RECT  6.685 56.304 6.793 56.52 ;
     RECT  5.641 10.752 6.797 11.976 ;
     RECT  6.716 20.016 6.803 20.04 ;
     RECT  6.716 67.488 6.805 68.376 ;
     RECT  5.929 8.544 6.829 9.48 ;
     RECT  6.797 10.752 6.829 10.776 ;
     RECT  6.793 32.304 6.833 43.944 ;
     RECT  6.797 11.952 6.853 11.976 ;
     RECT  6.793 54.672 6.901 56.52 ;
     RECT  5.533 51.168 6.937 51.24 ;
     RECT  6.721 52.416 6.937 53.016 ;
     RECT  6.545 16.8 6.973 16.824 ;
     RECT  6.217 18.528 6.973 18.984 ;
     RECT  6.973 16.8 7.009 18.984 ;
     RECT  6.937 51.168 7.009 53.016 ;
     RECT  6.833 43.584 7.045 43.944 ;
     RECT  6.613 66.192 7.081 66.504 ;
     RECT  6.805 67.488 7.081 68.184 ;
     RECT  6.853 11.952 7.117 12.072 ;
     RECT  6.505 13.104 7.117 13.608 ;
     RECT  5.213 58.128 7.117 58.536 ;
     RECT  6.721 15.408 7.153 15.768 ;
     RECT  6.077 5.856 7.225 5.88 ;
     RECT  7.045 43.584 7.225 44.376 ;
     RECT  6.721 45.504 7.225 48.792 ;
     RECT  7.117 70.656 7.225 71.16 ;
     RECT  6.761 62.4 7.261 64.152 ;
     RECT  7.117 58.128 7.333 59.304 ;
     RECT  7.225 5.856 7.369 6.072 ;
     RECT  6.397 72.96 7.405 72.984 ;
     RECT  6.437 21.792 7.513 22.968 ;
     RECT  7.477 2.832 7.585 2.856 ;
     RECT  7.333 57.84 7.585 59.304 ;
     RECT  7.009 50.832 7.649 53.016 ;
     RECT  6.901 54.672 7.657 56.616 ;
     RECT  6.469 60.864 7.657 60.888 ;
     RECT  7.261 61.968 7.657 64.152 ;
     RECT  7.585 2.832 7.669 3.096 ;
     RECT  7.045 4.08 7.669 4.104 ;
     RECT  7.153 15.216 7.669 15.768 ;
     RECT  7.225 70.608 7.669 71.16 ;
     RECT  7.405 72.192 7.669 72.984 ;
     RECT  7.669 2.832 7.808 4.104 ;
     RECT  7.369 5.856 7.808 6.888 ;
     RECT  6.829 8.448 7.808 10.776 ;
     RECT  7.117 11.952 7.808 13.608 ;
     RECT  7.669 14.784 7.808 15.768 ;
     RECT  7.009 16.8 7.808 19.368 ;
     RECT  7.513 20.928 7.808 22.968 ;
     RECT  6.721 24.24 7.808 31.224 ;
     RECT  6.833 32.304 7.808 42.552 ;
     RECT  7.225 43.584 7.808 48.792 ;
     RECT  7.649 50.208 7.808 53.016 ;
     RECT  7.657 54.624 7.808 56.616 ;
     RECT  7.585 57.84 7.808 59.736 ;
     RECT  7.657 60.864 7.808 64.152 ;
     RECT  6.761 65.136 7.808 65.16 ;
     RECT  7.081 66.192 7.808 68.184 ;
     RECT  6.577 69.408 7.808 69.432 ;
     RECT  7.669 70.608 7.808 72.984 ;
     RECT  7.34 74.304 7.808 74.328 ;
     RECT  7.808 2.148 7.912 79.932 ;
     RECT  7.912 2.418 8.104 79.662 ;
     RECT  8.104 2.832 8.243 3.96 ;
     RECT  8.104 12.768 8.243 13.848 ;
     RECT  8.104 29.04 8.291 34.776 ;
     RECT  8.291 32.256 8.345 34.776 ;
     RECT  8.345 32.304 8.453 34.776 ;
     RECT  8.453 32.304 8.489 34.728 ;
     RECT  8.104 60.864 8.489 63.048 ;
     RECT  8.104 15.216 8.561 22.248 ;
     RECT  8.104 35.904 8.561 45.288 ;
     RECT  8.561 15.888 8.572 22.248 ;
     RECT  8.104 66.144 8.579 68.904 ;
     RECT  8.104 47.04 8.627 56.568 ;
     RECT  8.627 56.016 8.633 56.568 ;
     RECT  8.489 32.496 8.741 34.728 ;
     RECT  8.104 70.176 8.921 73.512 ;
     RECT  8.561 35.904 8.957 43.416 ;
     RECT  8.579 66.144 8.957 67.464 ;
     RECT  8.561 44.448 8.965 45.288 ;
     RECT  8.243 12.768 9.097 13.656 ;
     RECT  8.957 66.144 9.107 66.744 ;
     RECT  8.104 57.84 9.157 59.304 ;
     RECT  8.104 10.656 9.173 11.4 ;
     RECT  8.627 47.04 9.173 54.888 ;
     RECT  9.157 57.84 9.209 59.736 ;
     RECT  8.104 5.856 9.245 7.416 ;
     RECT  9.173 11.376 9.277 11.4 ;
     RECT  8.572 16.56 9.277 22.248 ;
     RECT  8.104 23.28 9.277 27.864 ;
     RECT  8.243 2.832 9.353 3.096 ;
     RECT  9.107 66.144 9.385 66.552 ;
     RECT  9.173 47.04 9.389 54.792 ;
     RECT  8.104 74.592 9.425 75.528 ;
     RECT  9.209 58.224 9.443 59.736 ;
     RECT  8.291 29.04 9.452 31.224 ;
     RECT  8.104 8.88 9.457 8.904 ;
     RECT  8.489 60.864 9.457 60.888 ;
     RECT  8.489 62.16 9.457 63.048 ;
     RECT  9.457 60.864 9.461 63.048 ;
     RECT  9.277 11.376 9.493 11.496 ;
     RECT  9.097 12.48 9.493 13.656 ;
     RECT  9.385 66.048 9.529 66.552 ;
     RECT  9.452 28.992 9.569 31.224 ;
     RECT  9.245 5.856 9.596 6.264 ;
     RECT  9.596 5.616 9.601 6.264 ;
     RECT  9.277 16.56 9.601 27.864 ;
     RECT  8.579 68.688 9.601 68.904 ;
     RECT  8.921 70.176 9.601 72.408 ;
     RECT  9.245 7.344 9.637 7.416 ;
     RECT  9.457 8.88 9.637 9.048 ;
     RECT  9.493 11.376 9.637 13.656 ;
     RECT  9.601 16.56 9.637 27.96 ;
     RECT  9.569 28.992 9.637 30.936 ;
     RECT  9.443 58.704 9.677 59.736 ;
     RECT  8.741 32.736 9.709 34.728 ;
     RECT  8.957 35.904 9.709 38.76 ;
     RECT  8.104 64.416 9.709 64.92 ;
     RECT  9.529 65.904 9.709 66.552 ;
     RECT  9.601 5.04 9.724 6.264 ;
     RECT  8.633 56.016 9.733 56.328 ;
     RECT  9.461 61.296 9.733 63.048 ;
     RECT  9.709 32.736 9.749 38.76 ;
     RECT  9.733 61.296 9.749 63.24 ;
     RECT  9.637 16.56 9.785 30.936 ;
     RECT  9.733 56.016 9.82 56.52 ;
     RECT  9.749 61.728 9.82 63.24 ;
     RECT  9.785 16.56 9.836 22.824 ;
     RECT  9.785 23.952 9.893 30.936 ;
     RECT  9.389 47.04 9.893 52.248 ;
     RECT  9.389 53.568 9.893 54.792 ;
     RECT  8.957 39.984 9.925 43.416 ;
     RECT  8.965 45.264 9.925 45.288 ;
     RECT  9.893 27.984 9.929 30.936 ;
     RECT  9.893 51.312 9.965 52.248 ;
     RECT  9.637 7.344 10.001 9.048 ;
     RECT  9.82 56.016 10.033 56.328 ;
     RECT  9.601 68.688 10.105 72.408 ;
     RECT  9.893 47.04 10.145 50.136 ;
     RECT  8.921 73.44 10.172 73.512 ;
     RECT  9.929 27.984 10.181 30.168 ;
     RECT  10.001 7.392 10.213 9.048 ;
     RECT  9.637 11.376 10.213 14.808 ;
     RECT  9.836 15.84 10.213 22.824 ;
     RECT  9.677 58.704 10.217 59.304 ;
     RECT  10.105 68.496 10.253 72.408 ;
     RECT  10.172 73.44 10.259 74.136 ;
     RECT  10.253 68.496 10.285 68.76 ;
     RECT  10.217 58.704 10.289 59.256 ;
     RECT  10.253 70.704 10.307 72.408 ;
     RECT  10.307 71.952 10.321 72.408 ;
     RECT  10.259 73.44 10.321 73.8 ;
     RECT  9.925 45.264 10.357 45.48 ;
     RECT  9.709 64.416 10.357 66.552 ;
     RECT  10.285 67.728 10.357 68.76 ;
     RECT  9.724 5.04 10.393 6.12 ;
     RECT  10.357 64.416 10.397 68.76 ;
     RECT  10.213 10.992 10.433 22.824 ;
     RECT  10.181 27.984 10.433 28.2 ;
     RECT  10.393 4.704 10.465 6.12 ;
     RECT  10.433 28.08 10.469 28.2 ;
     RECT  10.213 7.392 10.505 9.816 ;
     RECT  10.469 28.176 10.505 28.2 ;
     RECT  10.505 9.024 10.573 9.816 ;
     RECT  10.433 10.992 10.573 22.2 ;
     RECT  10.357 45.264 10.573 45.624 ;
     RECT  10.145 47.04 10.573 47.88 ;
     RECT  10.397 64.416 10.573 66.072 ;
     RECT  9.425 75.168 10.577 75.528 ;
     RECT  9.893 53.568 10.609 54.12 ;
     RECT  10.573 64.224 10.717 66.072 ;
     RECT  10.465 4.656 10.721 6.12 ;
     RECT  9.82 61.728 10.789 63.048 ;
     RECT  9.749 32.736 10.861 35.88 ;
     RECT  10.721 4.656 10.901 5.064 ;
     RECT  10.573 9.024 10.924 22.2 ;
     RECT  10.789 31.2 10.933 31.224 ;
     RECT  9.749 36.864 10.933 38.76 ;
     RECT  9.925 39.984 10.933 43.896 ;
     RECT  10.033 55.92 10.933 56.328 ;
     RECT  10.573 45.264 10.969 47.88 ;
     RECT  10.789 61.728 10.969 63.144 ;
     RECT  9.353 2.832 10.973 2.856 ;
     RECT  10.289 59.184 10.973 59.256 ;
     RECT  9.965 51.36 10.981 52.248 ;
     RECT  10.609 53.376 10.981 54.12 ;
     RECT  10.981 51.36 11.005 54.12 ;
     RECT  10.181 29.184 11.041 30.168 ;
     RECT  10.933 31.2 11.041 31.56 ;
     RECT  10.505 7.392 11.045 7.992 ;
     RECT  10.717 64.128 11.045 66.072 ;
     RECT  11.005 51.36 11.068 54.168 ;
     RECT  10.861 32.688 11.081 35.88 ;
     RECT  10.721 6.096 11.113 6.12 ;
     RECT  10.933 55.92 11.113 56.424 ;
     RECT  10.753 58.128 11.113 58.152 ;
     RECT  9.893 23.952 11.149 26.616 ;
     RECT  10.924 9.024 11.153 14.232 ;
     RECT  10.321 71.952 11.153 73.8 ;
     RECT  11.153 9.024 11.189 11.784 ;
     RECT  10.973 59.232 11.189 59.256 ;
     RECT  10.969 61.2 11.189 63.144 ;
     RECT  11.041 29.184 11.221 31.56 ;
     RECT  11.113 55.92 11.257 58.152 ;
     RECT  10.924 15.504 11.261 22.2 ;
     RECT  11.045 64.128 11.261 65.976 ;
     RECT  10.397 67.248 11.261 68.76 ;
     RECT  10.969 45.12 11.329 47.88 ;
     RECT  10.145 49.536 11.329 50.136 ;
     RECT  11.068 51.36 11.329 52.296 ;
     RECT  11.261 67.296 11.329 68.76 ;
     RECT  11.153 72.768 11.329 73.8 ;
     RECT  11.261 64.128 11.333 65.928 ;
     RECT  10.933 36.864 11.365 43.896 ;
     RECT  11.329 45.12 11.401 48.456 ;
     RECT  11.329 49.536 11.401 52.296 ;
     RECT  11.329 72.768 11.413 74.088 ;
     RECT  10.577 75.168 11.413 75.384 ;
     RECT  11.401 45.12 11.441 52.296 ;
     RECT  11.333 65.904 11.477 65.928 ;
     RECT  11.149 23.664 11.509 26.616 ;
     RECT  11.329 67.296 11.545 68.904 ;
     RECT  11.441 45.12 11.621 47.88 ;
     RECT  10.901 4.656 11.653 5.016 ;
     RECT  11.081 34.416 11.653 35.88 ;
     RECT  11.365 36.864 11.653 44.136 ;
     RECT  11.413 72.768 11.657 75.384 ;
     RECT  11.509 23.664 11.725 27.432 ;
     RECT  11.725 23.664 11.729 27.72 ;
     RECT  11.621 47.328 11.729 47.88 ;
     RECT  11.257 55.872 11.729 58.152 ;
     RECT  11.045 7.968 11.765 7.992 ;
     RECT  11.261 15.504 11.765 21.864 ;
     RECT  11.653 34.416 11.801 44.136 ;
     RECT  11.068 53.376 11.801 54.168 ;
     RECT  11.621 45.12 11.909 45.48 ;
     RECT  11.729 23.952 11.941 27.72 ;
     RECT  11.221 28.8 11.941 31.56 ;
     RECT  11.801 53.52 11.941 54.168 ;
     RECT  11.189 62.976 11.941 63.144 ;
     RECT  11.333 64.128 11.941 64.68 ;
     RECT  10.307 70.704 11.941 70.728 ;
     RECT  11.801 37.344 11.945 44.136 ;
     RECT  11.941 23.952 12.013 31.56 ;
     RECT  11.081 32.688 12.013 33.384 ;
     RECT  11.441 49.056 12.017 52.296 ;
     RECT  11.545 67.296 12.017 69.288 ;
     RECT  12.013 23.952 12.053 33.384 ;
     RECT  11.941 53.52 12.053 54.84 ;
     RECT  12.053 53.52 12.076 54.696 ;
     RECT  11.945 37.344 12.131 39.576 ;
     RECT  11.729 55.968 12.157 58.152 ;
     RECT  11.945 40.656 12.229 44.136 ;
     RECT  12.017 67.296 12.229 68.712 ;
     RECT  11.581 60.048 12.233 60.072 ;
     RECT  11.189 11.232 12.301 11.784 ;
     RECT  12.157 55.968 12.301 58.248 ;
     RECT  12.284 59.28 12.301 59.304 ;
     RECT  11.189 61.2 12.337 61.224 ;
     RECT  11.941 62.976 12.337 64.68 ;
     RECT  11.113 6.096 12.373 6.408 ;
     RECT  12.337 61.2 12.409 61.368 ;
     RECT  12.053 24.192 12.481 33.384 ;
     RECT  11.801 34.416 12.481 35.736 ;
     RECT  12.301 10.944 12.517 11.784 ;
     RECT  11.153 13.056 12.517 14.232 ;
     RECT  11.941 70.704 12.517 71.064 ;
     RECT  11.189 9.024 12.613 9.816 ;
     RECT  12.517 10.944 12.613 14.232 ;
     RECT  12.373 6.096 12.661 6.84 ;
     RECT  11.729 47.376 12.697 47.88 ;
     RECT  12.409 61.056 12.769 61.368 ;
     RECT  12.613 9.024 12.805 14.232 ;
     RECT  12.049 2.832 12.913 2.856 ;
     RECT  12.017 49.488 12.949 52.296 ;
     RECT  12.076 53.52 12.949 54.12 ;
     RECT  11.653 4.176 12.985 5.016 ;
     RECT  12.661 6.096 12.985 6.888 ;
     RECT  12.337 62.448 13.021 64.68 ;
     RECT  12.229 66.816 13.021 68.712 ;
     RECT  12.985 3.84 13.057 6.888 ;
     RECT  13.057 3.84 13.093 7.752 ;
     RECT  12.805 9.024 13.093 14.328 ;
     RECT  11.765 15.504 13.093 17.496 ;
     RECT  12.949 49.488 13.093 54.12 ;
     RECT  12.769 60.336 13.093 61.368 ;
     RECT  13.021 62.448 13.093 64.968 ;
     RECT  12.913 2.784 13.208 2.856 ;
     RECT  13.093 3.84 13.208 14.328 ;
     RECT  13.093 15.504 13.208 17.688 ;
     RECT  11.765 18.72 13.208 21.864 ;
     RECT  12.481 24.192 13.208 35.736 ;
     RECT  12.131 37.44 13.208 39.576 ;
     RECT  12.229 40.656 13.208 44.472 ;
     RECT  11.909 45.456 13.208 45.48 ;
     RECT  12.697 47.328 13.208 47.88 ;
     RECT  13.093 49.008 13.208 54.12 ;
     RECT  12.301 55.968 13.208 59.304 ;
     RECT  13.093 60.336 13.208 64.968 ;
     RECT  13.021 66.768 13.208 68.712 ;
     RECT  12.517 70.08 13.208 71.064 ;
     RECT  11.657 72.768 13.208 75.192 ;
     RECT  13.208 2.148 13.312 79.932 ;
     RECT  13.312 2.418 13.504 79.662 ;
     RECT  13.504 53.808 13.565 54.696 ;
     RECT  13.504 10.8 13.637 14.424 ;
     RECT  13.504 74.112 13.667 75.144 ;
     RECT  13.504 26.304 13.709 47.736 ;
     RECT  13.504 55.776 13.745 61.368 ;
     RECT  13.504 2.784 13.781 2.856 ;
     RECT  13.504 49.008 13.853 52.296 ;
     RECT  13.853 49.008 13.925 52.104 ;
     RECT  13.667 74.112 13.961 75 ;
     RECT  13.781 2.784 14.141 2.808 ;
     RECT  13.504 4.176 14.141 9.384 ;
     RECT  13.745 55.776 14.177 61.128 ;
     RECT  13.504 15.504 14.243 25.272 ;
     RECT  14.177 55.776 14.249 60.504 ;
     RECT  13.709 26.304 14.285 39.048 ;
     RECT  14.249 56.304 14.285 60.504 ;
     RECT  13.961 74.112 14.321 74.328 ;
     RECT  14.285 56.304 14.357 60.312 ;
     RECT  13.709 40.128 14.429 47.736 ;
     RECT  13.637 10.944 14.497 14.424 ;
     RECT  14.243 15.504 14.497 17.496 ;
     RECT  13.504 62.64 14.497 63.672 ;
     RECT  13.504 65.472 14.497 68.616 ;
     RECT  13.504 70.032 14.497 70.104 ;
     RECT  14.497 10.944 14.537 17.496 ;
     RECT  13.925 49.248 14.537 52.104 ;
     RECT  14.285 34.368 14.573 39.048 ;
     RECT  14.537 49.536 14.573 52.104 ;
     RECT  14.537 15.36 14.581 17.496 ;
     RECT  14.497 69.984 14.605 70.104 ;
     RECT  13.504 71.136 14.605 71.352 ;
     RECT  14.429 41.184 14.609 47.736 ;
     RECT  14.285 26.304 14.677 33.384 ;
     RECT  14.609 45.12 14.713 47.736 ;
     RECT  14.497 62.64 14.741 68.616 ;
     RECT  14.713 45.12 14.753 47.832 ;
     RECT  14.357 56.544 14.753 60.312 ;
     RECT  14.573 36.048 14.785 39.048 ;
     RECT  14.429 40.128 14.785 40.152 ;
     RECT  14.605 69.984 14.789 71.352 ;
     RECT  13.504 72.768 14.821 72.792 ;
     RECT  14.321 74.112 14.821 74.136 ;
     RECT  14.243 18.48 14.825 25.272 ;
     RECT  14.753 59.28 14.825 60.312 ;
     RECT  14.741 62.64 14.857 68.712 ;
     RECT  14.789 69.984 14.857 70.008 ;
     RECT  14.573 49.776 14.861 52.104 ;
     RECT  14.857 62.64 14.861 70.008 ;
     RECT  14.821 72.768 14.969 74.136 ;
     RECT  13.565 53.856 15.005 54.696 ;
     RECT  14.537 10.944 15.013 14.088 ;
     RECT  15.013 10.848 15.1 14.088 ;
     RECT  15.1 10.944 15.105 14.088 ;
     RECT  14.141 4.176 15.109 9.048 ;
     RECT  14.573 34.368 15.113 35.016 ;
     RECT  14.785 36.048 15.149 40.152 ;
     RECT  14.825 18.48 15.221 25.032 ;
     RECT  15.037 2.832 15.289 2.856 ;
     RECT  14.677 26.256 15.365 33.384 ;
     RECT  14.861 50.208 15.397 52.104 ;
     RECT  15.397 50.208 15.443 53.304 ;
     RECT  15.221 18.48 15.473 18.504 ;
     RECT  14.753 56.544 15.493 58.152 ;
     RECT  15.005 54.432 15.505 54.696 ;
     RECT  15.493 56.256 15.505 58.152 ;
     RECT  15.289 2.496 15.509 2.856 ;
     RECT  15.105 12.048 15.532 14.088 ;
     RECT  15.365 26.304 15.577 33.384 ;
     RECT  15.505 54.432 15.581 58.152 ;
     RECT  15.149 36.048 15.617 39.768 ;
     RECT  15.509 2.496 15.649 2.616 ;
     RECT  14.753 45.12 15.649 45.72 ;
     RECT  15.581 56.64 15.757 58.152 ;
     RECT  14.825 59.28 15.757 60.024 ;
     RECT  14.861 65.52 15.757 70.008 ;
     RECT  14.789 71.136 15.757 71.352 ;
     RECT  15.685 75.12 15.772 75.144 ;
     RECT  14.753 46.848 15.781 47.832 ;
     RECT  15.649 2.208 15.797 2.616 ;
     RECT  15.649 44.88 15.829 45.72 ;
     RECT  15.781 46.848 15.829 47.88 ;
     RECT  15.617 36.048 15.833 39.048 ;
     RECT  15.829 44.88 15.868 47.88 ;
     RECT  15.757 56.64 15.941 60.024 ;
     RECT  15.443 50.208 15.973 52.008 ;
     RECT  15.757 65.52 15.977 71.352 ;
     RECT  14.861 62.64 16.019 64.44 ;
     RECT  15.109 4.176 16.045 9.912 ;
     RECT  15.977 70.128 16.049 71.352 ;
     RECT  16.045 3.984 16.085 9.912 ;
     RECT  16.085 7.248 16.229 9.912 ;
     RECT  15.833 36.24 16.265 39.048 ;
     RECT  15.221 19.584 16.297 25.032 ;
     RECT  16.229 7.248 16.3 9.768 ;
     RECT  15.577 26.304 16.333 33.96 ;
     RECT  15.113 34.992 16.333 35.016 ;
     RECT  15.105 10.944 16.357 10.968 ;
     RECT  15.532 12.048 16.357 13.656 ;
     RECT  16.333 26.304 16.369 35.016 ;
     RECT  14.969 72.768 16.405 73.512 ;
     RECT  14.581 15.504 16.412 17.496 ;
     RECT  14.609 41.184 16.441 43.608 ;
     RECT  16.357 10.944 16.477 13.656 ;
     RECT  16.297 18.768 16.477 25.032 ;
     RECT  15.577 48.96 16.508 48.984 ;
     RECT  15.973 50.064 16.508 52.008 ;
     RECT  16.477 10.8 16.513 13.656 ;
     RECT  16.369 26.256 16.513 35.016 ;
     RECT  16.405 72.768 16.513 73.56 ;
     RECT  15.443 53.04 16.553 53.304 ;
     RECT  16.049 70.128 16.553 71.16 ;
     RECT  16.513 26.256 16.589 35.064 ;
     RECT  16.265 36.288 16.589 39.048 ;
     RECT  16.412 15.456 16.621 17.496 ;
     RECT  16.477 18.768 16.621 25.272 ;
     RECT  16.553 53.28 16.693 53.304 ;
     RECT  15.581 54.432 16.693 55.368 ;
     RECT  16.645 75.648 16.732 75.672 ;
     RECT  16.297 60.864 16.765 60.984 ;
     RECT  16.508 48.96 16.769 52.008 ;
     RECT  16.589 26.256 16.805 33.384 ;
     RECT  15.941 56.64 16.805 59.832 ;
     RECT  16.513 72.144 16.805 73.56 ;
     RECT  16.693 53.28 16.837 55.368 ;
     RECT  16.805 56.64 16.837 59.256 ;
     RECT  16.837 53.28 16.913 59.256 ;
     RECT  16.913 56.256 16.924 59.256 ;
     RECT  15.977 65.52 16.981 68.664 ;
     RECT  16.553 70.128 16.981 70.824 ;
     RECT  16.924 56.64 16.985 59.256 ;
     RECT  15.868 44.88 17.021 47.736 ;
     RECT  16.441 41.184 17.053 43.656 ;
     RECT  16.765 60.864 17.053 61.368 ;
     RECT  16.019 62.832 17.053 64.44 ;
     RECT  16.621 15.456 17.057 25.272 ;
     RECT  16.589 34.608 17.125 35.064 ;
     RECT  16.589 36.528 17.125 39.048 ;
     RECT  17.053 40.224 17.125 43.656 ;
     RECT  17.021 45.12 17.129 47.736 ;
     RECT  16.913 53.28 17.129 54.888 ;
     RECT  17.053 62.64 17.137 64.44 ;
     RECT  16.3 7.248 17.161 9.24 ;
     RECT  17.137 63.12 17.161 64.44 ;
     RECT  16.981 65.52 17.161 70.824 ;
     RECT  17.125 36.528 17.171 43.656 ;
     RECT  17.161 7.152 17.201 9.24 ;
     RECT  17.129 53.904 17.201 54.888 ;
     RECT  16.085 3.984 17.233 6.12 ;
     RECT  17.201 7.152 17.233 9.048 ;
     RECT  16.513 10.8 17.241 14.28 ;
     RECT  17.057 15.456 17.241 25.176 ;
     RECT  17.125 34.608 17.269 35.304 ;
     RECT  17.241 10.8 17.273 25.176 ;
     RECT  17.053 60.864 17.276 61.56 ;
     RECT  17.276 60.24 17.363 61.56 ;
     RECT  17.161 63.12 17.453 70.824 ;
     RECT  17.129 45.12 17.597 46.536 ;
     RECT  17.233 3.984 17.653 9.048 ;
     RECT  16.769 49.056 17.665 52.008 ;
     RECT  17.363 61.2 17.773 61.56 ;
     RECT  16.805 72.144 17.773 72.984 ;
     RECT  16.985 56.64 17.953 58.584 ;
     RECT  17.953 56.64 18.025 58.68 ;
     RECT  17.665 49.056 18.133 52.824 ;
     RECT  18.025 56.64 18.133 58.728 ;
     RECT  18.133 48.768 18.205 52.824 ;
     RECT  17.201 53.904 18.205 54.744 ;
     RECT  17.171 41.184 18.241 43.656 ;
     RECT  16.805 26.304 18.373 33.384 ;
     RECT  17.269 34.608 18.373 35.4 ;
     RECT  17.171 36.528 18.373 39.624 ;
     RECT  18.133 56.496 18.421 58.728 ;
     RECT  18.241 41.136 18.469 43.656 ;
     RECT  17.597 45.552 18.601 46.536 ;
     RECT  17.773 61.2 18.601 62.04 ;
     RECT  17.453 63.12 18.601 69.528 ;
     RECT  15.797 2.208 18.608 2.52 ;
     RECT  17.653 3.936 18.608 9.048 ;
     RECT  17.273 10.8 18.608 25.128 ;
     RECT  18.373 26.304 18.608 35.4 ;
     RECT  18.373 36.528 18.608 39.768 ;
     RECT  18.469 41.136 18.608 43.848 ;
     RECT  18.601 45.504 18.608 46.536 ;
     RECT  17.129 47.664 18.608 47.736 ;
     RECT  18.205 48.768 18.608 54.744 ;
     RECT  18.421 56.496 18.608 59.592 ;
     RECT  18.601 61.2 18.608 69.528 ;
     RECT  17.453 70.608 18.608 70.824 ;
     RECT  17.773 72.144 18.608 73.224 ;
     RECT  17.845 75.12 18.608 75.144 ;
     RECT  18.608 2.148 18.712 79.932 ;
     RECT  18.712 2.418 18.904 79.662 ;
     RECT  18.904 56.496 18.929 70.632 ;
     RECT  18.929 56.496 18.965 64.632 ;
     RECT  18.904 41.088 19.001 48.792 ;
     RECT  18.904 14.928 19.037 38.76 ;
     RECT  19.001 41.088 19.037 48.408 ;
     RECT  18.904 71.856 19.043 75.432 ;
     RECT  19.037 14.928 19.132 38.52 ;
     RECT  19.043 71.856 19.145 74.568 ;
     RECT  19.037 41.28 19.361 48.408 ;
     RECT  19.145 74.544 19.379 74.568 ;
     RECT  18.965 62.016 19.505 64.632 ;
     RECT  18.904 3.984 19.685 9.096 ;
     RECT  19.361 41.28 19.756 47.736 ;
     RECT  19.756 47.088 19.763 47.736 ;
     RECT  18.904 49.824 19.897 55.176 ;
     RECT  18.965 56.496 19.897 60.456 ;
     RECT  18.904 10.656 19.969 11.256 ;
     RECT  19.897 49.824 19.973 60.456 ;
     RECT  18.929 66.144 19.973 70.632 ;
     RECT  19.969 10.608 20.005 11.256 ;
     RECT  18.904 12.288 20.005 13.656 ;
     RECT  19.505 62.016 20.045 64.392 ;
     RECT  20.005 10.608 20.185 13.656 ;
     RECT  19.132 14.928 20.185 37.992 ;
     RECT  20.185 10.608 20.189 37.992 ;
     RECT  19.756 41.28 20.261 46.104 ;
     RECT  19.973 49.824 20.261 55.8 ;
     RECT  20.261 49.824 20.293 52.92 ;
     RECT  20.189 15.312 20.333 37.992 ;
     RECT  19.973 56.784 20.333 60.456 ;
     RECT  20.333 26.304 20.473 37.992 ;
     RECT  19.145 71.856 20.513 73.512 ;
     RECT  19.973 66.384 20.549 70.632 ;
     RECT  20.293 49.536 20.579 52.92 ;
     RECT  20.473 26.304 20.585 38.76 ;
     RECT  20.221 75.792 20.617 75.816 ;
     RECT  20.513 72.48 20.657 73.512 ;
     RECT  20.261 45.504 20.693 46.104 ;
     RECT  20.549 66.384 20.693 70.2 ;
     RECT  20.261 41.28 20.725 44.472 ;
     RECT  20.045 62.448 20.725 64.392 ;
     RECT  20.617 75.504 20.725 75.816 ;
     RECT  20.189 10.608 20.761 14.136 ;
     RECT  20.693 67.392 20.801 70.2 ;
     RECT  19.685 3.984 20.869 9.048 ;
     RECT  20.761 10.176 20.869 14.136 ;
     RECT  20.585 36.816 20.869 38.76 ;
     RECT  18.904 39.744 20.869 39.768 ;
     RECT  20.725 41.232 20.869 44.472 ;
     RECT  19.933 2.928 20.905 2.952 ;
     RECT  20.869 36.816 20.941 39.768 ;
     RECT  20.869 41.184 20.941 44.472 ;
     RECT  20.941 36.816 20.945 44.472 ;
     RECT  20.801 67.44 20.945 70.2 ;
     RECT  20.945 67.44 20.981 68.424 ;
     RECT  20.905 2.64 21.049 2.952 ;
     RECT  20.869 3.984 21.049 14.136 ;
     RECT  20.693 45.792 21.085 46.104 ;
     RECT  19.763 47.664 21.085 47.736 ;
     RECT  20.945 69.744 21.089 70.2 ;
     RECT  20.725 75.216 21.121 75.816 ;
     RECT  20.945 36.816 21.125 43.656 ;
     RECT  20.585 26.304 21.161 35.544 ;
     RECT  21.121 75.216 21.205 76.776 ;
     RECT  21.205 75.216 21.233 77.544 ;
     RECT  20.261 53.904 21.337 55.8 ;
     RECT  20.333 56.784 21.337 59.64 ;
     RECT  21.049 2.64 21.341 14.136 ;
     RECT  21.161 34.32 21.413 35.544 ;
     RECT  21.233 75.504 21.485 77.544 ;
     RECT  21.085 45.792 21.548 47.736 ;
     RECT  21.548 45.792 21.635 48.408 ;
     RECT  20.725 62.448 21.661 64.872 ;
     RECT  20.579 49.824 21.692 52.92 ;
     RECT  21.337 53.904 21.692 59.64 ;
     RECT  21.692 49.824 21.697 59.64 ;
     RECT  21.697 49.824 21.733 60.552 ;
     RECT  20.657 72.768 21.737 73.512 ;
     RECT  21.737 72.768 21.769 72.792 ;
     RECT  21.125 37.92 21.773 43.656 ;
     RECT  21.661 62.448 21.841 65.4 ;
     RECT  20.693 66.384 21.841 66.408 ;
     RECT  20.981 67.44 21.841 68.376 ;
     RECT  21.841 61.968 21.845 65.4 ;
     RECT  21.733 49.488 21.917 60.552 ;
     RECT  21.773 37.92 21.953 40.152 ;
     RECT  21.635 45.792 21.985 47.736 ;
     RECT  21.845 61.968 21.985 64.392 ;
     RECT  21.917 49.488 22.133 59.832 ;
     RECT  21.161 26.304 22.309 33.192 ;
     RECT  21.773 41.136 22.345 43.656 ;
     RECT  20.333 15.312 22.381 25.32 ;
     RECT  22.309 26.304 22.381 33.288 ;
     RECT  22.381 15.312 22.385 33.288 ;
     RECT  22.133 54.768 22.385 59.832 ;
     RECT  21.845 65.376 22.385 65.4 ;
     RECT  22.385 30.336 22.417 33.288 ;
     RECT  21.413 34.32 22.417 34.776 ;
     RECT  21.985 61.536 22.421 64.392 ;
     RECT  22.385 15.312 22.493 29.352 ;
     RECT  21.089 69.744 22.597 70.056 ;
     RECT  21.841 74.064 22.633 74.088 ;
     RECT  21.485 75.504 22.633 76.872 ;
     RECT  21.341 2.64 22.652 13.656 ;
     RECT  21.985 45.6 22.669 47.736 ;
     RECT  22.421 61.536 22.705 61.656 ;
     RECT  22.417 30.336 22.745 34.776 ;
     RECT  22.597 69.744 22.745 70.968 ;
     RECT  22.652 2.64 22.787 14.088 ;
     RECT  22.745 70.032 22.787 70.968 ;
     RECT  22.787 10.128 22.813 14.088 ;
     RECT  22.493 15.312 22.813 29.304 ;
     RECT  22.133 49.488 22.813 53.544 ;
     RECT  22.633 74.064 22.813 76.872 ;
     RECT  21.841 66.384 22.817 68.376 ;
     RECT  22.421 62.688 22.849 64.392 ;
     RECT  22.787 2.64 22.853 9.096 ;
     RECT  22.669 45.6 22.853 47.88 ;
     RECT  22.345 41.136 22.885 44.424 ;
     RECT  22.853 45.6 22.885 47.736 ;
     RECT  22.813 73.92 22.921 76.872 ;
     RECT  22.745 30.336 22.925 33.624 ;
     RECT  22.817 66.432 22.925 68.376 ;
     RECT  21.953 37.968 22.993 40.152 ;
     RECT  22.885 41.136 22.993 47.736 ;
     RECT  22.385 54.864 23.033 59.832 ;
     RECT  22.925 67.296 23.209 68.376 ;
     RECT  21.769 71.952 23.245 72.792 ;
     RECT  22.201 78 23.353 78.024 ;
     RECT  22.705 60.96 23.389 61.656 ;
     RECT  22.813 10.128 23.461 29.304 ;
     RECT  22.925 30.336 23.461 33.384 ;
     RECT  22.813 49.008 23.641 53.544 ;
     RECT  23.641 49.008 23.749 53.592 ;
     RECT  22.849 62.688 23.785 65.256 ;
     RECT  23.749 48.768 23.821 53.592 ;
     RECT  22.787 70.032 23.857 70.584 ;
     RECT  23.245 71.616 23.857 72.792 ;
     RECT  23.389 60.816 23.893 61.656 ;
     RECT  22.921 73.92 23.893 76.968 ;
     RECT  23.461 10.128 24.001 33.384 ;
     RECT  23.857 70.032 24.001 72.792 ;
     RECT  23.893 73.776 24.001 76.968 ;
     RECT  22.853 2.784 24.008 9.096 ;
     RECT  24.001 10.128 24.008 33.576 ;
     RECT  23.228 35.616 24.008 35.64 ;
     RECT  21.125 36.816 24.008 36.936 ;
     RECT  22.993 37.968 24.008 47.736 ;
     RECT  23.821 48.72 24.008 53.592 ;
     RECT  23.033 54.864 24.008 59.496 ;
     RECT  23.893 60.576 24.008 61.656 ;
     RECT  23.785 62.688 24.008 65.784 ;
     RECT  23.209 67.296 24.008 69 ;
     RECT  24.001 70.032 24.008 76.968 ;
     RECT  23.353 78 24.008 78.216 ;
     RECT  24.008 2.148 24.112 79.932 ;
     RECT  24.112 2.418 24.304 79.662 ;
     RECT  24.304 30.336 24.419 33.576 ;
     RECT  24.304 36.816 24.419 48.792 ;
     RECT  24.419 30.336 24.473 33.384 ;
     RECT  24.304 49.824 24.509 63.816 ;
     RECT  24.304 10.128 24.581 29.304 ;
     RECT  24.419 48.48 24.581 48.792 ;
     RECT  24.509 49.824 24.581 59.496 ;
     RECT  24.473 32.208 24.689 33.384 ;
     RECT  24.581 55.68 24.689 59.496 ;
     RECT  24.473 30.336 24.797 31.224 ;
     RECT  24.419 36.816 24.797 46.728 ;
     RECT  24.304 65.04 24.977 76.248 ;
     RECT  24.509 60.624 25.013 63.816 ;
     RECT  24.977 65.136 25.049 76.248 ;
     RECT  25.013 60.672 25.085 63.816 ;
     RECT  24.304 77.568 25.085 78.216 ;
     RECT  24.581 10.224 25.121 29.304 ;
     RECT  25.049 75.744 25.121 76.248 ;
     RECT  24.304 2.418 25.189 9.096 ;
     RECT  25.121 14.4 25.193 29.304 ;
     RECT  25.049 65.136 25.193 74.616 ;
     RECT  24.797 36.816 25.265 46.248 ;
     RECT  25.193 14.4 25.337 14.952 ;
     RECT  25.265 36.816 25.337 44.424 ;
     RECT  25.265 45.984 25.337 46.248 ;
     RECT  25.337 14.544 25.373 14.952 ;
     RECT  25.193 65.76 25.373 74.616 ;
     RECT  25.085 77.568 25.549 78.072 ;
     RECT  25.337 36.816 25.553 44.184 ;
     RECT  24.581 48.48 25.669 48.744 ;
     RECT  24.581 49.824 25.697 54.648 ;
     RECT  25.669 47.856 25.729 48.744 ;
     RECT  25.697 49.824 25.729 54.456 ;
     RECT  25.193 16.08 25.733 29.304 ;
     RECT  25.553 36.816 25.769 43.944 ;
     RECT  25.729 47.856 25.769 54.456 ;
     RECT  25.733 26.544 25.837 29.304 ;
     RECT  25.189 2.304 25.873 9.096 ;
     RECT  25.837 26.544 25.877 29.352 ;
     RECT  25.373 68.928 25.877 74.616 ;
     RECT  24.797 31.2 25.916 31.224 ;
     RECT  24.689 32.304 25.916 33.384 ;
     RECT  24.689 55.68 25.945 59.208 ;
     RECT  25.549 77.52 25.949 78.072 ;
     RECT  25.873 2.304 25.981 9.144 ;
     RECT  25.121 10.224 25.981 13.416 ;
     RECT  25.945 55.68 25.985 59.256 ;
     RECT  25.085 60.864 26.017 63.816 ;
     RECT  25.877 74.592 26.089 74.616 ;
     RECT  25.733 16.08 26.093 25.416 ;
     RECT  25.877 27.168 26.125 29.352 ;
     RECT  25.981 2.304 26.129 13.416 ;
     RECT  25.769 48 26.129 54.456 ;
     RECT  26.089 74.592 26.129 74.712 ;
     RECT  25.916 31.2 26.197 33.384 ;
     RECT  26.125 35.808 26.197 35.832 ;
     RECT  26.017 60.864 26.197 64.728 ;
     RECT  25.373 65.76 26.197 67.848 ;
     RECT  26.129 48 26.201 54.408 ;
     RECT  25.877 68.928 26.201 73.272 ;
     RECT  25.405 76.368 26.233 76.392 ;
     RECT  26.093 16.08 26.243 19.896 ;
     RECT  26.201 48 26.273 54.36 ;
     RECT  25.373 14.688 26.309 14.952 ;
     RECT  26.197 60.864 26.413 67.848 ;
     RECT  26.201 68.928 26.413 72.792 ;
     RECT  26.129 74.688 26.417 74.712 ;
     RECT  25.337 45.984 26.453 46.104 ;
     RECT  26.413 60.864 26.525 72.792 ;
     RECT  26.197 31.2 26.531 34.344 ;
     RECT  26.243 16.08 26.629 17.496 ;
     RECT  26.273 48 26.705 53.88 ;
     RECT  26.705 48.048 26.777 53.88 ;
     RECT  26.093 20.928 26.993 25.416 ;
     RECT  26.125 27.168 27.025 29.64 ;
     RECT  26.197 35.52 27.097 35.832 ;
     RECT  25.769 36.816 27.101 43.8 ;
     RECT  26.993 20.928 27.173 24.504 ;
     RECT  26.629 15.792 27.205 17.496 ;
     RECT  26.243 18.48 27.205 19.896 ;
     RECT  26.233 75.984 27.281 76.392 ;
     RECT  27.101 40.128 27.308 43.8 ;
     RECT  27.308 40.128 27.313 44.664 ;
     RECT  25.985 55.68 27.313 56.088 ;
     RECT  25.985 57.36 27.313 59.256 ;
     RECT  26.129 3.12 27.349 13.416 ;
     RECT  27.313 55.68 27.349 59.256 ;
     RECT  25.949 77.568 27.349 78.072 ;
     RECT  26.525 60.864 27.389 64.728 ;
     RECT  27.313 40.128 27.395 44.952 ;
     RECT  27.205 15.792 27.421 19.896 ;
     RECT  27.173 20.928 27.421 24.216 ;
     RECT  26.525 65.76 27.421 72.792 ;
     RECT  26.593 46.368 27.493 46.536 ;
     RECT  26.777 53.856 27.497 53.88 ;
     RECT  27.421 15.792 27.529 24.216 ;
     RECT  27.421 65.76 27.569 72.984 ;
     RECT  27.281 75.984 27.605 76.056 ;
     RECT  26.777 48.048 27.635 52.872 ;
     RECT  27.349 77.52 27.641 78.072 ;
     RECT  27.395 40.128 27.677 43.8 ;
     RECT  27.389 60.864 27.677 63.672 ;
     RECT  27.349 2.304 27.685 13.416 ;
     RECT  26.521 14.448 27.685 14.472 ;
     RECT  27.685 2.304 27.713 14.472 ;
     RECT  27.677 60.864 27.713 62.472 ;
     RECT  27.349 55.248 27.779 59.256 ;
     RECT  27.493 46.368 27.836 46.632 ;
     RECT  27.635 48.048 27.836 49.896 ;
     RECT  27.635 50.928 27.853 52.872 ;
     RECT  27.836 46.368 27.857 49.896 ;
     RECT  27.101 36.816 27.893 39.096 ;
     RECT  27.857 46.368 27.923 47.256 ;
     RECT  27.569 65.76 27.929 69.576 ;
     RECT  27.713 60.96 27.965 62.472 ;
     RECT  27.929 65.76 28.001 69 ;
     RECT  27.857 48.432 28.037 49.896 ;
     RECT  27.853 50.928 28.037 52.92 ;
     RECT  27.529 15.456 28.073 24.216 ;
     RECT  27.779 57.456 28.073 59.256 ;
     RECT  27.641 78.048 28.073 78.072 ;
     RECT  27.713 2.304 28.109 9.048 ;
     RECT  27.025 25.776 28.141 29.64 ;
     RECT  27.395 44.928 28.145 44.952 ;
     RECT  27.569 70.656 28.145 72.216 ;
     RECT  26.531 31.2 28.165 34.152 ;
     RECT  28.109 2.304 28.181 5.016 ;
     RECT  28.165 30.768 28.249 34.152 ;
     RECT  27.097 35.328 28.249 35.832 ;
     RECT  28.249 30.768 28.285 35.832 ;
     RECT  27.893 36.816 28.285 36.84 ;
     RECT  28.285 30.768 28.309 36.84 ;
     RECT  27.713 10.08 28.321 14.472 ;
     RECT  28.073 15.456 28.321 19.8 ;
     RECT  28.073 21.168 28.357 24.216 ;
     RECT  28.309 30.672 28.397 36.84 ;
     RECT  27.605 76.032 28.433 76.056 ;
     RECT  27.893 37.968 28.465 39.096 ;
     RECT  27.677 40.128 28.465 43.704 ;
     RECT  28.357 21.168 28.501 24.408 ;
     RECT  28.141 25.584 28.501 29.64 ;
     RECT  27.923 46.368 28.537 46.632 ;
     RECT  28.037 48.48 28.645 49.896 ;
     RECT  28.037 50.928 28.645 52.872 ;
     RECT  27.677 63.456 28.645 63.672 ;
     RECT  27.389 64.704 28.645 64.728 ;
     RECT  27.965 61.392 28.681 62.472 ;
     RECT  28.645 63.456 28.681 64.728 ;
     RECT  28.429 73.488 28.825 73.512 ;
     RECT  28.465 37.968 28.897 43.704 ;
     RECT  28.897 37.968 28.969 43.944 ;
     RECT  28.001 66.768 28.981 69 ;
     RECT  28.073 57.648 29.005 59.256 ;
     RECT  28.981 66.768 29.029 69.48 ;
     RECT  28.145 70.656 29.029 71.976 ;
     RECT  28.537 45.552 29.077 46.632 ;
     RECT  29.005 57.648 29.077 59.496 ;
     RECT  28.897 75.408 29.077 75.432 ;
     RECT  28.645 48.48 29.185 52.872 ;
     RECT  28.969 37.968 29.293 44.376 ;
     RECT  29.029 66.768 29.329 71.976 ;
     RECT  28.181 3.12 29.365 5.016 ;
     RECT  28.109 6.096 29.365 9.048 ;
     RECT  29.077 57.552 29.365 59.784 ;
     RECT  29.365 3.12 29.408 9.048 ;
     RECT  28.321 10.08 29.408 19.8 ;
     RECT  28.501 21.168 29.408 29.64 ;
     RECT  28.397 30.768 29.408 36.84 ;
     RECT  29.293 37.968 29.408 44.472 ;
     RECT  29.077 45.552 29.408 47.304 ;
     RECT  29.185 48.48 29.408 53.016 ;
     RECT  29.293 54.384 29.408 54.408 ;
     RECT  27.779 55.44 29.408 56.088 ;
     RECT  29.365 57.12 29.408 59.784 ;
     RECT  28.681 61.392 29.408 64.728 ;
     RECT  28.825 65.712 29.408 65.736 ;
     RECT  29.329 66.768 29.408 72.168 ;
     RECT  28.825 73.488 29.408 73.8 ;
     RECT  29.077 74.88 29.408 75.432 ;
     RECT  29.077 79.44 29.408 79.464 ;
     RECT  29.408 2.148 29.512 79.932 ;
     RECT  29.512 2.418 29.704 79.662 ;
     RECT  29.704 54.192 29.801 69.048 ;
     RECT  29.704 37.872 29.843 53.016 ;
     RECT  29.843 40.128 29.909 53.016 ;
     RECT  29.909 45.504 29.987 53.016 ;
     RECT  29.801 59.472 30.017 69.048 ;
     RECT  29.909 40.128 30.089 44.472 ;
     RECT  29.704 30.864 30.233 36.84 ;
     RECT  30.017 59.472 30.241 67.8 ;
     RECT  30.017 68.976 30.275 69.048 ;
     RECT  29.704 70.08 30.277 74.088 ;
     RECT  29.704 3.12 30.305 7.464 ;
     RECT  29.704 8.448 30.305 20.52 ;
     RECT  30.305 3.12 30.413 7.224 ;
     RECT  30.305 9.024 30.413 20.52 ;
     RECT  30.277 70.08 30.449 73.8 ;
     RECT  30.233 30.912 30.485 36.84 ;
     RECT  30.413 9.264 30.557 20.52 ;
     RECT  29.987 47.952 30.557 53.016 ;
     RECT  29.704 75.36 30.593 75.384 ;
     RECT  30.485 35.472 30.733 36.84 ;
     RECT  29.843 37.872 30.733 38.808 ;
     RECT  30.557 51.36 30.733 53.016 ;
     RECT  29.801 54.192 30.733 58.248 ;
     RECT  29.704 76.56 30.733 77.16 ;
     RECT  29.704 78.48 30.733 79.464 ;
     RECT  30.557 17.616 30.737 20.52 ;
     RECT  30.737 19.632 30.809 20.52 ;
     RECT  30.241 59.472 30.809 65.544 ;
     RECT  30.449 70.08 30.809 73.752 ;
     RECT  30.737 17.616 30.851 18.264 ;
     RECT  30.485 30.912 30.917 34.152 ;
     RECT  30.413 3.12 30.949 4.008 ;
     RECT  30.851 17.616 30.953 18.216 ;
     RECT  30.733 51.36 30.985 58.248 ;
     RECT  30.809 59.472 30.985 63.672 ;
     RECT  30.241 66.768 30.985 67.8 ;
     RECT  30.557 47.952 30.989 49.896 ;
     RECT  30.985 51.36 30.989 63.672 ;
     RECT  30.809 70.08 31.021 73.608 ;
     RECT  30.985 66.768 31.025 67.848 ;
     RECT  30.413 4.992 31.061 7.224 ;
     RECT  30.557 9.264 31.097 16.392 ;
     RECT  30.809 20.4 31.097 20.52 ;
     RECT  29.987 45.504 31.097 46.776 ;
     RECT  30.733 35.472 31.169 38.808 ;
     RECT  30.733 76.56 31.169 79.464 ;
     RECT  31.169 79.44 31.205 79.464 ;
     RECT  31.169 37.872 31.313 38.808 ;
     RECT  31.061 6.672 31.333 7.224 ;
     RECT  30.989 48.912 31.349 49.896 ;
     RECT  31.333 6.672 31.381 7.992 ;
     RECT  31.097 9.264 31.381 16.344 ;
     RECT  30.953 18.192 31.385 18.216 ;
     RECT  29.704 21.744 31.417 29.304 ;
     RECT  31.349 49.536 31.525 49.896 ;
     RECT  31.169 35.472 31.561 36.84 ;
     RECT  31.021 69.6 31.597 73.608 ;
     RECT  31.169 76.56 31.597 77.784 ;
     RECT  31.525 75.168 31.628 75.192 ;
     RECT  31.097 45.792 31.633 46.776 ;
     RECT  31.025 66.816 31.633 67.848 ;
     RECT  31.597 68.88 31.633 73.608 ;
     RECT  30.949 2.304 31.669 4.008 ;
     RECT  31.061 4.992 31.669 5.544 ;
     RECT  31.525 49.536 31.705 50.328 ;
     RECT  30.989 51.36 31.705 52.68 ;
     RECT  31.628 75.12 31.715 75.192 ;
     RECT  31.381 6.672 31.745 16.344 ;
     RECT  31.417 21.12 31.853 29.304 ;
     RECT  31.597 76.464 31.907 77.784 ;
     RECT  31.633 66.816 32.033 73.608 ;
     RECT  30.089 40.128 32.065 44.376 ;
     RECT  31.705 49.536 32.065 52.68 ;
     RECT  31.853 21.12 32.069 25.08 ;
     RECT  31.669 2.304 32.209 5.544 ;
     RECT  31.745 6.672 32.209 9.096 ;
     RECT  31.907 76.464 32.213 76.968 ;
     RECT  32.213 76.56 32.249 76.968 ;
     RECT  32.069 21.12 32.285 24.84 ;
     RECT  30.989 53.904 32.285 63.672 ;
     RECT  30.809 64.704 32.317 65.544 ;
     RECT  32.033 66.816 32.317 72.936 ;
     RECT  32.285 53.904 32.321 58.248 ;
     RECT  30.917 30.912 32.425 33.816 ;
     RECT  32.065 40.128 32.429 44.76 ;
     RECT  32.065 49.536 32.497 52.776 ;
     RECT  32.321 53.904 32.497 58.2 ;
     RECT  31.633 45.792 32.537 47.928 ;
     RECT  32.317 64.704 32.537 72.936 ;
     RECT  32.537 66.288 32.573 72.936 ;
     RECT  32.573 66.288 32.609 69 ;
     RECT  31.715 75.168 32.717 75.192 ;
     RECT  32.209 2.304 32.785 9.096 ;
     RECT  31.745 10.08 32.785 16.344 ;
     RECT  32.285 21.12 32.785 24.216 ;
     RECT  31.853 26.256 32.785 29.304 ;
     RECT  32.425 30.48 32.785 33.816 ;
     RECT  32.497 49.536 32.789 58.2 ;
     RECT  32.537 47.712 32.825 47.928 ;
     RECT  31.313 37.872 32.857 38.76 ;
     RECT  32.429 40.128 32.857 44.376 ;
     RECT  32.533 73.92 32.861 73.944 ;
     RECT  31.561 34.848 32.917 36.84 ;
     RECT  32.857 37.872 32.917 44.376 ;
     RECT  32.713 79.248 32.917 79.272 ;
     RECT  32.785 26.256 33.001 33.816 ;
     RECT  32.917 34.848 33.001 44.376 ;
     RECT  33.001 26.256 33.071 44.376 ;
     RECT  32.789 49.536 33.073 56.856 ;
     RECT  32.285 59.232 33.073 63.672 ;
     RECT  32.537 64.704 33.073 64.872 ;
     RECT  33.073 59.232 33.077 64.872 ;
     RECT  33.001 18.192 33.085 18.216 ;
     RECT  33.071 26.208 33.109 44.376 ;
     RECT  32.713 19.344 33.113 19.368 ;
     RECT  32.789 57.936 33.289 58.2 ;
     RECT  33.077 59.232 33.289 64.392 ;
     RECT  32.609 66.288 33.292 68.952 ;
     RECT  32.537 45.792 33.365 46.728 ;
     RECT  33.365 45.984 33.401 46.728 ;
     RECT  32.785 2.304 33.433 16.344 ;
     RECT  32.249 76.8 33.469 76.968 ;
     RECT  32.917 78.624 33.469 79.272 ;
     RECT  33.433 2.304 33.505 17.112 ;
     RECT  32.785 20.88 33.577 24.216 ;
     RECT  33.109 25.44 33.577 44.376 ;
     RECT  33.5 74.64 33.587 74.664 ;
     RECT  33.469 76.272 33.644 79.272 ;
     RECT  33.292 67.248 33.649 68.952 ;
     RECT  32.573 70.176 33.649 72.936 ;
     RECT  33.649 67.248 33.653 72.936 ;
     RECT  33.644 76.176 33.653 79.272 ;
     RECT  33.653 77.664 33.685 79.272 ;
     RECT  33.073 48.816 33.689 56.856 ;
     RECT  33.653 76.176 33.731 76.536 ;
     RECT  33.685 77.664 33.769 79.56 ;
     RECT  33.689 50.976 33.829 56.856 ;
     RECT  33.289 57.936 33.829 64.392 ;
     RECT  33.577 20.88 33.937 44.376 ;
     RECT  33.401 46.176 33.973 46.728 ;
     RECT  32.825 47.712 33.973 47.736 ;
     RECT  33.505 2.304 34.289 17.208 ;
     RECT  33.541 65.712 34.412 65.736 ;
     RECT  33.829 50.976 34.513 64.392 ;
     RECT  33.973 46.176 34.693 47.736 ;
     RECT  33.689 48.816 34.693 49.848 ;
     RECT  33.731 76.272 34.729 76.536 ;
     RECT  33.769 77.664 34.729 79.272 ;
     RECT  34.513 50.976 34.765 64.68 ;
     RECT  34.412 65.712 34.765 65.928 ;
     RECT  34.693 46.176 34.801 49.848 ;
     RECT  34.765 50.976 34.801 65.928 ;
     RECT  34.289 2.304 34.808 17.304 ;
     RECT  33.541 19.872 34.808 19.896 ;
     RECT  33.937 20.88 34.808 44.472 ;
     RECT  34.801 46.176 34.808 65.928 ;
     RECT  33.653 67.248 34.808 72.744 ;
     RECT  34.549 74.976 34.808 75 ;
     RECT  34.729 76.272 34.808 79.272 ;
     RECT  34.808 2.148 34.912 79.932 ;
     RECT  34.912 2.148 35.104 79.662 ;
     RECT  35.104 2.148 35.201 24.168 ;
     RECT  35.104 76.08 35.26 79.272 ;
     RECT  35.104 25.296 35.309 34.344 ;
     RECT  35.26 76.272 35.309 79.272 ;
     RECT  35.201 21.168 35.345 24.168 ;
     RECT  35.201 2.148 35.452 20.184 ;
     RECT  35.104 35.328 35.489 69.336 ;
     RECT  35.309 76.368 35.489 79.272 ;
     RECT  35.309 25.296 35.525 34.152 ;
     RECT  35.489 35.328 35.555 48.696 ;
     RECT  35.525 25.296 35.633 33.864 ;
     RECT  35.345 21.168 35.651 24.072 ;
     RECT  35.452 10.176 35.669 20.184 ;
     RECT  35.489 49.824 35.669 69.336 ;
     RECT  35.452 2.148 35.845 9.192 ;
     RECT  35.104 70.656 35.891 74.904 ;
     RECT  35.489 76.512 35.957 79.272 ;
     RECT  35.669 17.664 36.209 20.184 ;
     RECT  35.651 21.168 36.245 23.976 ;
     RECT  35.669 60 36.268 69.336 ;
     RECT  36.245 23.04 36.281 23.976 ;
     RECT  35.555 35.328 36.281 48.6 ;
     RECT  36.281 35.328 36.284 45.864 ;
     RECT  36.281 23.328 36.353 23.976 ;
     RECT  35.669 49.824 36.353 59.016 ;
     RECT  36.284 34.896 36.371 45.864 ;
     RECT  35.845 2.064 36.457 9.192 ;
     RECT  35.669 10.176 36.457 16.68 ;
     RECT  36.209 18.768 36.461 20.184 ;
     RECT  36.268 67.92 36.461 69.336 ;
     RECT  35.891 70.944 36.461 74.904 ;
     RECT  36.461 74.016 36.497 74.904 ;
     RECT  35.957 76.512 36.497 79.032 ;
     RECT  36.457 2.064 36.533 16.68 ;
     RECT  36.268 60 36.533 66.792 ;
     RECT  36.461 70.944 36.569 72.888 ;
     RECT  36.497 74.016 36.569 74.856 ;
     RECT  36.353 53.664 36.673 59.016 ;
     RECT  35.633 25.296 36.745 33.816 ;
     RECT  36.533 2.064 36.749 16.536 ;
     RECT  36.371 35.664 36.749 45.864 ;
     RECT  36.353 49.824 36.817 52.584 ;
     RECT  36.569 70.944 36.853 72.552 ;
     RECT  36.745 25.056 36.857 33.816 ;
     RECT  36.569 74.304 36.899 74.856 ;
     RECT  36.245 21.168 37.033 22.008 ;
     RECT  36.749 35.712 37.043 45.864 ;
     RECT  36.209 17.664 37.045 17.688 ;
     RECT  36.497 77.664 37.073 79.032 ;
     RECT  36.281 47.232 37.105 48.6 ;
     RECT  36.817 49.584 37.105 52.584 ;
     RECT  36.533 65.808 37.109 66.792 ;
     RECT  36.749 2.064 37.145 15.96 ;
     RECT  37.105 47.232 37.217 52.584 ;
     RECT  37.073 77.808 37.244 79.032 ;
     RECT  37.033 20.832 37.285 22.008 ;
     RECT  37.244 77.808 37.331 79.464 ;
     RECT  36.857 25.2 37.381 33.816 ;
     RECT  37.109 66.144 37.433 66.792 ;
     RECT  36.673 53.664 37.541 59.112 ;
     RECT  37.433 66.624 37.541 66.792 ;
     RECT  37.331 77.808 37.541 79.032 ;
     RECT  37.285 20.832 37.609 22.2 ;
     RECT  36.853 70.176 37.619 72.552 ;
     RECT  37.145 2.064 37.649 15.912 ;
     RECT  37.541 54.048 37.721 59.112 ;
     RECT  36.899 74.832 37.721 74.856 ;
     RECT  37.541 77.808 37.757 78.36 ;
     RECT  37.649 2.064 37.793 14.52 ;
     RECT  37.721 54.048 37.793 57.96 ;
     RECT  36.353 23.328 37.825 23.928 ;
     RECT  37.381 25.2 37.825 34.536 ;
     RECT  36.461 18.768 37.829 19.8 ;
     RECT  37.043 35.76 37.829 45.864 ;
     RECT  37.829 40.128 37.865 45.864 ;
     RECT  37.609 20.832 37.933 22.296 ;
     RECT  37.825 23.328 37.933 34.536 ;
     RECT  37.217 49.584 37.937 52.584 ;
     RECT  37.217 47.232 37.969 48.6 ;
     RECT  37.789 73.824 37.969 73.848 ;
     RECT  37.619 72.528 38.041 72.552 ;
     RECT  37.969 73.824 38.041 74.328 ;
     RECT  37.045 17.52 38.077 17.688 ;
     RECT  36.497 76.512 38.113 76.536 ;
     RECT  36.461 67.92 38.149 69 ;
     RECT  37.937 49.824 38.153 52.584 ;
     RECT  37.829 35.76 38.261 38.808 ;
     RECT  38.041 72.528 38.297 74.328 ;
     RECT  37.829 19.44 38.329 19.8 ;
     RECT  37.933 20.832 38.329 34.68 ;
     RECT  38.261 35.76 38.329 38.76 ;
     RECT  37.721 59.088 38.333 59.112 ;
     RECT  37.541 66.624 38.437 66.648 ;
     RECT  38.077 16.896 38.585 18.168 ;
     RECT  37.969 46.224 38.621 48.6 ;
     RECT  38.297 72.528 38.621 74.088 ;
     RECT  36.533 60.096 38.653 64.68 ;
     RECT  38.437 65.664 38.653 66.648 ;
     RECT  38.113 75.648 38.657 76.536 ;
     RECT  38.653 60.096 38.689 66.648 ;
     RECT  38.149 67.776 38.689 69 ;
     RECT  37.619 70.176 38.689 71.208 ;
     RECT  37.649 15.744 38.725 15.912 ;
     RECT  38.689 67.776 38.725 71.208 ;
     RECT  38.621 72.528 38.725 74.04 ;
     RECT  38.725 67.776 38.729 74.04 ;
     RECT  38.153 50.976 38.761 52.584 ;
     RECT  38.689 59.28 38.78 66.648 ;
     RECT  38.725 15.36 38.821 15.912 ;
     RECT  37.793 54.048 38.828 54.168 ;
     RECT  38.773 79.44 38.86 79.464 ;
     RECT  38.78 59.28 38.867 66.792 ;
     RECT  38.729 67.824 38.867 74.04 ;
     RECT  37.757 77.808 38.869 77.928 ;
     RECT  38.585 16.896 38.873 17.976 ;
     RECT  38.828 53.952 38.915 54.168 ;
     RECT  38.915 54.048 38.945 54.168 ;
     RECT  38.869 77.136 38.977 77.928 ;
     RECT  38.821 15.072 38.981 15.912 ;
     RECT  37.865 40.128 39.085 45 ;
     RECT  39.085 40.08 39.109 45 ;
     RECT  38.761 50.976 39.157 52.776 ;
     RECT  38.977 77.136 39.233 78.168 ;
     RECT  38.945 54.144 39.265 54.168 ;
     RECT  37.793 55.2 39.265 57.96 ;
     RECT  38.153 49.824 39.301 49.896 ;
     RECT  38.657 75.648 39.301 76.152 ;
     RECT  39.109 39.888 39.349 45 ;
     RECT  38.621 46.224 39.349 47.976 ;
     RECT  39.265 54.144 39.404 57.96 ;
     RECT  39.301 49.248 39.644 49.896 ;
     RECT  39.157 50.976 39.644 52.968 ;
     RECT  39.644 49.248 39.661 52.968 ;
     RECT  38.329 19.44 39.697 38.76 ;
     RECT  39.697 19.44 39.733 38.808 ;
     RECT  39.349 39.888 39.733 47.976 ;
     RECT  38.867 73.536 39.733 74.04 ;
     RECT  39.301 75.024 39.733 76.152 ;
     RECT  39.404 54.144 39.769 58.152 ;
     RECT  38.867 59.28 39.769 66.648 ;
     RECT  39.733 73.536 39.769 76.152 ;
     RECT  39.233 77.136 39.769 77.16 ;
     RECT  37.793 2.064 39.797 13.992 ;
     RECT  38.981 15.072 39.797 15.816 ;
     RECT  39.733 19.44 39.913 47.976 ;
     RECT  39.769 54.144 39.925 66.648 ;
     RECT  38.867 67.824 39.925 72.216 ;
     RECT  39.797 2.064 39.949 15.816 ;
     RECT  38.873 17.136 39.949 17.976 ;
     RECT  39.949 2.064 39.973 17.976 ;
     RECT  39.913 19.008 39.973 47.976 ;
     RECT  39.769 73.536 40.021 77.16 ;
     RECT  39.973 2.064 40.208 47.976 ;
     RECT  39.661 48.96 40.208 52.968 ;
     RECT  39.925 54.144 40.208 72.216 ;
     RECT  40.021 73.344 40.208 77.16 ;
     RECT  39.233 78.144 40.208 78.168 ;
     RECT  40.208 2.064 40.312 79.932 ;
     RECT  40.312 2.064 40.504 79.662 ;
     RECT  40.504 77.664 40.565 78.648 ;
     RECT  40.504 65.28 40.601 73.368 ;
     RECT  40.504 36.816 40.637 55.224 ;
     RECT  40.601 67.824 40.835 73.368 ;
     RECT  40.504 56.304 40.889 59.88 ;
     RECT  40.601 65.28 40.889 66.504 ;
     RECT  40.504 19.104 40.924 21.72 ;
     RECT  40.504 23.088 40.961 35.208 ;
     RECT  40.835 67.872 40.969 73.368 ;
     RECT  40.889 58.656 41.027 59.88 ;
     RECT  40.969 67.872 41.033 72.168 ;
     RECT  40.637 37.056 41.105 55.224 ;
     RECT  40.889 56.304 41.105 57.576 ;
     RECT  41.027 59.04 41.105 59.88 ;
     RECT  41.105 48.96 41.177 55.224 ;
     RECT  40.565 77.664 41.213 77.688 ;
     RECT  40.504 2.064 41.321 3.432 ;
     RECT  40.504 61.536 41.321 64.152 ;
     RECT  41.177 48.96 41.393 50.088 ;
     RECT  40.504 8.736 41.429 17.064 ;
     RECT  40.924 19.632 41.497 21.72 ;
     RECT  40.961 23.088 41.497 33.528 ;
     RECT  41.105 56.304 41.497 56.664 ;
     RECT  41.321 61.536 41.573 61.704 ;
     RECT  41.177 51.072 41.603 55.224 ;
     RECT  40.969 73.344 41.605 73.368 ;
     RECT  41.66 77.712 41.669 77.736 ;
     RECT  41.321 2.256 41.677 3.432 ;
     RECT  40.504 4.416 41.677 7.752 ;
     RECT  41.321 62.832 41.677 64.152 ;
     RECT  40.889 65.28 41.677 65.304 ;
     RECT  41.605 73.344 41.713 73.608 ;
     RECT  41.669 77.712 41.747 78.696 ;
     RECT  41.429 8.784 41.753 17.064 ;
     RECT  41.033 69.504 41.753 72.168 ;
     RECT  41.747 78.048 41.753 78.696 ;
     RECT  41.713 73.344 41.785 74.472 ;
     RECT  40.961 34.56 41.821 35.208 ;
     RECT  41.497 19.632 41.893 33.528 ;
     RECT  41.105 59.136 41.893 59.88 ;
     RECT  40.889 66.48 41.893 66.504 ;
     RECT  41.033 67.872 41.893 68.52 ;
     RECT  41.105 37.056 41.933 47.976 ;
     RECT  41.893 19.392 42.073 33.528 ;
     RECT  41.497 56.208 42.073 56.664 ;
     RECT  42.001 58.128 42.073 58.152 ;
     RECT  41.893 59.136 42.109 59.928 ;
     RECT  41.573 61.536 42.109 61.56 ;
     RECT  41.677 62.832 42.109 65.304 ;
     RECT  41.893 66.48 42.109 68.52 ;
     RECT  42.073 18.576 42.14 33.528 ;
     RECT  41.821 34.56 42.14 35.688 ;
     RECT  42.14 18.576 42.143 35.688 ;
     RECT  41.933 37.056 42.143 38.76 ;
     RECT  41.393 49.536 42.145 50.088 ;
     RECT  41.603 51.072 42.145 52.872 ;
     RECT  41.603 54.096 42.145 55.224 ;
     RECT  42.073 56.208 42.145 58.152 ;
     RECT  41.785 73.344 42.145 74.856 ;
     RECT  41.677 76.368 42.145 76.392 ;
     RECT  42.145 54.096 42.181 58.152 ;
     RECT  42.109 59.136 42.181 61.56 ;
     RECT  42.143 18.576 42.227 38.76 ;
     RECT  41.677 2.256 42.289 7.752 ;
     RECT  41.933 39.792 42.329 47.976 ;
     RECT  42.145 73.344 42.401 76.392 ;
     RECT  42.109 62.832 42.473 68.52 ;
     RECT  42.473 62.832 42.581 68.424 ;
     RECT  42.401 76.368 42.649 76.392 ;
     RECT  41.753 8.784 42.721 8.808 ;
     RECT  42.227 34.896 42.725 38.76 ;
     RECT  42.649 76.368 42.733 76.728 ;
     RECT  41.753 10.128 42.793 17.064 ;
     RECT  41.753 78.048 42.793 78.552 ;
     RECT  42.725 35.136 42.797 38.76 ;
     RECT  42.145 49.536 42.865 52.872 ;
     RECT  42.581 62.832 42.865 66.84 ;
     RECT  42.793 10.128 42.905 17.16 ;
     RECT  42.181 54.096 42.905 61.56 ;
     RECT  42.905 15.216 42.941 17.16 ;
     RECT  42.905 54.096 42.941 59.496 ;
     RECT  42.865 49.536 42.973 52.968 ;
     RECT  42.905 60.528 42.977 61.56 ;
     RECT  42.329 40.032 43.045 47.976 ;
     RECT  42.865 62.544 43.049 66.84 ;
     RECT  42.973 49.056 43.153 52.968 ;
     RECT  42.797 35.136 43.157 38.664 ;
     RECT  42.227 18.576 43.189 33.384 ;
     RECT  42.289 2.16 43.261 7.752 ;
     RECT  42.721 8.736 43.261 8.808 ;
     RECT  43.189 17.712 43.283 33.384 ;
     RECT  43.153 49.056 43.301 53.112 ;
     RECT  43.261 2.16 43.333 8.808 ;
     RECT  41.753 70.368 43.333 72.168 ;
     RECT  42.941 15.216 43.337 16.296 ;
     RECT  43.333 2.16 43.34 9.144 ;
     RECT  42.905 10.128 43.34 13.704 ;
     RECT  43.301 49.488 43.369 53.112 ;
     RECT  42.941 54.096 43.369 59.16 ;
     RECT  43.283 18.576 43.405 33.384 ;
     RECT  43.34 2.16 43.417 13.704 ;
     RECT  43.417 2.16 43.427 13.656 ;
     RECT  42.401 73.344 43.441 75.192 ;
     RECT  42.733 76.368 43.441 76.536 ;
     RECT  42.581 67.92 43.477 68.424 ;
     RECT  43.477 67.92 43.513 68.568 ;
     RECT  43.427 2.16 43.517 9.144 ;
     RECT  43.517 2.16 43.549 8.808 ;
     RECT  42.977 60.528 43.553 60.984 ;
     RECT  43.333 70.368 43.621 72.216 ;
     RECT  43.621 70.368 43.628 72.264 ;
     RECT  43.441 73.344 43.628 76.536 ;
     RECT  43.045 40.032 43.657 48.024 ;
     RECT  43.628 70.368 43.715 76.536 ;
     RECT  43.405 18.576 43.733 33.48 ;
     RECT  43.657 39.984 43.769 48.024 ;
     RECT  43.769 39.984 43.801 47.832 ;
     RECT  43.715 73.344 43.837 76.536 ;
     RECT  42.793 77.52 43.837 78.552 ;
     RECT  43.369 49.488 43.841 59.16 ;
     RECT  43.733 19.92 43.877 33.48 ;
     RECT  43.841 49.488 43.907 56.328 ;
     RECT  43.427 10.128 43.913 13.656 ;
     RECT  43.733 18.576 43.913 18.888 ;
     RECT  43.157 35.136 43.913 35.496 ;
     RECT  43.049 62.928 43.913 66.84 ;
     RECT  43.837 73.344 43.913 78.552 ;
     RECT  43.841 57.456 43.945 59.16 ;
     RECT  43.553 60.528 43.945 60.744 ;
     RECT  43.337 15.216 43.949 16.008 ;
     RECT  43.913 76.368 44.017 78.552 ;
     RECT  43.877 25.728 44.089 33.48 ;
     RECT  44.053 34.704 44.089 34.728 ;
     RECT  43.913 63.072 44.089 66.84 ;
     RECT  43.513 67.92 44.089 69 ;
     RECT  44.089 63.072 44.093 69 ;
     RECT  44.017 76.368 44.093 78.696 ;
     RECT  43.157 36.528 44.161 38.664 ;
     RECT  44.093 63.072 44.165 64.92 ;
     RECT  44.093 76.368 44.195 76.584 ;
     RECT  44.093 78.048 44.273 78.696 ;
     RECT  44.161 36 44.3 38.664 ;
     RECT  43.913 18.624 44.309 18.888 ;
     RECT  43.945 57.456 44.309 60.744 ;
     RECT  44.165 63.072 44.417 64.2 ;
     RECT  43.715 70.368 44.449 72.264 ;
     RECT  43.913 73.344 44.453 75.24 ;
     RECT  44.273 78.096 44.453 78.696 ;
     RECT  43.877 19.92 44.476 24.744 ;
     RECT  44.093 65.952 44.483 68.424 ;
     RECT  44.476 19.92 44.489 22.872 ;
     RECT  44.453 74.4 44.489 75.24 ;
     RECT  43.913 10.176 44.557 13.656 ;
     RECT  44.557 10.176 44.593 13.704 ;
     RECT  43.801 39.792 44.597 47.832 ;
     RECT  44.483 67.632 44.597 68.424 ;
     RECT  43.949 15.456 44.809 16.008 ;
     RECT  44.476 23.904 44.845 24.744 ;
     RECT  44.089 25.728 44.845 34.728 ;
     RECT  44.809 15.456 44.881 16.584 ;
     RECT  43.907 49.824 44.953 56.328 ;
     RECT  44.309 57.456 44.953 60.12 ;
     RECT  44.953 49.824 44.989 60.12 ;
     RECT  43.549 2.064 45.025 8.808 ;
     RECT  44.881 15.456 45.025 17.448 ;
     RECT  44.597 45.504 45.025 47.832 ;
     RECT  45.025 1.968 45.097 8.808 ;
     RECT  44.593 10.176 45.097 14.28 ;
     RECT  45.025 15.456 45.097 17.64 ;
     RECT  44.309 18.624 45.097 18.84 ;
     RECT  45.097 1.968 45.133 14.28 ;
     RECT  45.133 1.968 45.209 14.424 ;
     RECT  44.195 76.368 45.349 76.392 ;
     RECT  45.349 76.368 45.493 76.776 ;
     RECT  44.3 36 45.565 38.808 ;
     RECT  44.597 39.792 45.565 44.232 ;
     RECT  45.025 45.504 45.565 47.88 ;
     RECT  45.209 2.064 45.608 14.424 ;
     RECT  45.097 15.456 45.608 18.84 ;
     RECT  44.489 19.92 45.608 22.824 ;
     RECT  44.845 23.904 45.608 34.728 ;
     RECT  45.565 36 45.608 44.232 ;
     RECT  45.565 45.456 45.608 47.88 ;
     RECT  44.989 49.776 45.608 60.12 ;
     RECT  45.421 61.104 45.608 61.128 ;
     RECT  44.417 63.216 45.608 64.2 ;
     RECT  44.483 65.952 45.608 66.6 ;
     RECT  44.597 68.16 45.608 68.424 ;
     RECT  44.449 69.456 45.608 72.264 ;
     RECT  44.453 73.344 45.608 73.368 ;
     RECT  44.489 74.64 45.608 75.24 ;
     RECT  45.493 76.368 45.608 77.112 ;
     RECT  44.453 78.096 45.608 78.408 ;
     RECT  45.608 2.064 45.712 79.932 ;
     RECT  45.712 2.064 45.904 79.662 ;
     RECT  45.904 19.92 45.965 44.472 ;
     RECT  45.904 15.456 46.001 15.624 ;
     RECT  45.965 19.92 46.037 22.728 ;
     RECT  45.853 0.24 46.141 0.264 ;
     RECT  45.904 62.544 46.145 64.2 ;
     RECT  46.145 62.736 46.217 64.2 ;
     RECT  45.904 65.76 46.217 77.16 ;
     RECT  46.217 70.32 46.253 77.16 ;
     RECT  46.253 70.32 46.289 73.944 ;
     RECT  45.904 45.456 46.325 45.768 ;
     RECT  46.289 70.368 46.325 73.944 ;
     RECT  46.253 75.216 46.325 77.16 ;
     RECT  46.325 70.368 46.397 71.4 ;
     RECT  45.904 46.848 46.577 48.408 ;
     RECT  46.141 0.096 46.609 0.264 ;
     RECT  45.965 23.712 46.613 44.472 ;
     RECT  46.397 70.368 46.649 71.352 ;
     RECT  45.904 16.704 46.739 18.744 ;
     RECT  46.577 46.848 46.739 48.312 ;
     RECT  46.609 0.096 46.751 0.504 ;
     RECT  46.325 75.216 46.757 77.112 ;
     RECT  46.751 0.048 46.793 0.504 ;
     RECT  46.649 70.656 46.793 71.352 ;
     RECT  46.757 75.216 46.793 75.96 ;
     RECT  46.217 68.208 46.828 69.336 ;
     RECT  45.904 54.336 46.865 57.624 ;
     RECT  46.613 36.048 46.898 44.472 ;
     RECT  46.793 75.84 46.901 75.96 ;
     RECT  46.739 17.424 47.005 18.744 ;
     RECT  45.904 50.064 47.041 51.336 ;
     RECT  45.904 52.416 47.041 53.016 ;
     RECT  45.904 78.144 47.045 78.648 ;
     RECT  47.041 50.064 47.173 53.016 ;
     RECT  45.904 59.52 47.185 61.368 ;
     RECT  46.217 63.216 47.185 64.2 ;
     RECT  47.005 17.424 47.188 18.792 ;
     RECT  46.898 36.048 47.189 44.424 ;
     RECT  46.325 45.504 47.189 45.768 ;
     RECT  46.739 46.848 47.189 48.264 ;
     RECT  46.217 65.76 47.219 67.032 ;
     RECT  47.189 36.048 47.225 44.328 ;
     RECT  47.185 62.976 47.257 64.2 ;
     RECT  47.173 49.968 47.26 53.016 ;
     RECT  46.325 72.72 47.276 73.944 ;
     RECT  47.185 59.424 47.293 61.368 ;
     RECT  47.257 62.976 47.293 64.632 ;
     RECT  46.865 54.336 47.333 57.336 ;
     RECT  47.276 72.72 47.363 74.808 ;
     RECT  47.293 59.424 47.365 64.632 ;
     RECT  47.365 59.424 47.369 64.968 ;
     RECT  45.904 2.064 47.441 14.424 ;
     RECT  47.225 38.112 47.441 44.328 ;
     RECT  47.26 50.448 47.509 53.016 ;
     RECT  47.333 54.336 47.509 57 ;
     RECT  47.509 50.448 47.513 57 ;
     RECT  47.369 59.808 47.585 64.968 ;
     RECT  47.363 72.72 47.585 74.136 ;
     RECT  47.513 50.448 47.596 56.904 ;
     RECT  47.219 66 47.653 67.032 ;
     RECT  46.828 68.736 47.653 69.336 ;
     RECT  46.793 70.656 47.653 70.68 ;
     RECT  46.037 19.92 47.689 22.152 ;
     RECT  47.596 50.448 47.699 52.584 ;
     RECT  47.585 59.904 47.729 62.328 ;
     RECT  46.001 15.456 47.761 15.48 ;
     RECT  47.189 45.744 47.765 45.768 ;
     RECT  47.441 38.976 47.801 44.328 ;
     RECT  47.699 52.416 47.801 52.584 ;
     RECT  47.653 66 47.801 67.272 ;
     RECT  47.653 68.736 47.861 70.68 ;
     RECT  47.189 47.04 47.869 48.264 ;
     RECT  46.901 75.84 47.869 75.864 ;
     RECT  46.757 76.944 47.869 77.112 ;
     RECT  47.045 78.144 47.869 78.6 ;
     RECT  46.613 23.712 47.873 34.728 ;
     RECT  47.699 50.448 47.873 51.432 ;
     RECT  47.761 15.456 47.893 16.296 ;
     RECT  47.188 17.424 47.893 18.84 ;
     RECT  47.441 2.064 47.909 10.392 ;
     RECT  47.893 15.456 47.909 18.84 ;
     RECT  47.873 23.712 47.909 34.392 ;
     RECT  47.596 54.336 47.909 56.904 ;
     RECT  47.689 19.92 47.941 22.536 ;
     RECT  47.909 23.712 47.941 33.96 ;
     RECT  47.873 50.448 47.981 51.24 ;
     RECT  47.861 68.736 48.035 71.352 ;
     RECT  47.909 2.208 48.053 10.392 ;
     RECT  47.869 75.84 48.053 78.6 ;
     RECT  47.869 47.04 48.157 48.936 ;
     RECT  48.157 47.04 48.193 48.984 ;
     RECT  47.941 19.92 48.268 33.96 ;
     RECT  47.585 63.312 48.277 64.968 ;
     RECT  47.801 66 48.277 66.168 ;
     RECT  47.801 39.024 48.301 44.328 ;
     RECT  47.801 52.56 48.305 52.584 ;
     RECT  47.225 36.048 48.421 37.08 ;
     RECT  47.909 17.856 48.445 18.84 ;
     RECT  47.585 73.008 48.445 74.136 ;
     RECT  48.445 73.008 48.517 74.856 ;
     RECT  48.053 75.84 48.517 78.408 ;
     RECT  48.517 73.008 48.549 78.408 ;
     RECT  47.801 67.248 48.553 67.272 ;
     RECT  48.053 2.208 48.557 3.432 ;
     RECT  48.193 46.464 48.557 48.984 ;
     RECT  48.549 73.008 48.593 77.976 ;
     RECT  47.441 11.52 48.629 14.424 ;
     RECT  48.301 39.024 48.629 44.472 ;
     RECT  48.557 46.464 48.701 47.88 ;
     RECT  48.593 73.008 48.701 76.392 ;
     RECT  48.053 5.04 48.769 10.392 ;
     RECT  47.909 54.624 48.769 56.904 ;
     RECT  48.085 58.128 48.769 58.152 ;
     RECT  47.729 62.256 48.773 62.328 ;
     RECT  48.421 35.904 48.805 37.08 ;
     RECT  48.805 35.904 48.841 37.32 ;
     RECT  47.909 15.456 48.877 16.824 ;
     RECT  48.445 17.856 48.877 18.936 ;
     RECT  48.557 48.912 48.985 48.984 ;
     RECT  48.277 63.312 48.997 66.168 ;
     RECT  48.553 67.248 48.997 67.32 ;
     RECT  48.629 11.712 49.021 14.424 ;
     RECT  48.877 15.456 49.021 18.936 ;
     RECT  48.629 39.888 49.021 44.472 ;
     RECT  48.157 79.44 49.021 79.464 ;
     RECT  48.841 35.328 49.025 37.32 ;
     RECT  48.985 48.912 49.025 49.032 ;
     RECT  49.021 11.712 49.057 18.936 ;
     RECT  48.268 19.92 49.057 33.672 ;
     RECT  48.035 68.736 49.057 70.632 ;
     RECT  48.557 2.208 49.061 2.808 ;
     RECT  47.729 59.904 49.061 60.936 ;
     RECT  49.025 36.576 49.093 37.32 ;
     RECT  48.841 38.4 49.093 38.424 ;
     RECT  49.021 39.888 49.093 45 ;
     RECT  48.701 46.464 49.093 47.832 ;
     RECT  49.093 36.576 49.139 38.424 ;
     RECT  48.769 54.624 49.187 58.152 ;
     RECT  46.793 0.048 49.237 0.456 ;
     RECT  47.981 50.496 49.237 51.24 ;
     RECT  48.769 5.04 49.273 10.728 ;
     RECT  48.701 73.008 49.273 75.48 ;
     RECT  48.773 62.256 49.345 62.28 ;
     RECT  49.057 11.712 49.381 33.672 ;
     RECT  49.025 48.96 49.385 49.032 ;
     RECT  48.997 63.312 49.417 67.32 ;
     RECT  49.139 38.112 49.421 38.424 ;
     RECT  49.061 59.904 49.489 60.264 ;
     RECT  49.273 72.72 49.561 75.48 ;
     RECT  48.593 77.424 49.561 77.976 ;
     RECT  49.021 78.96 49.561 79.464 ;
     RECT  49.381 11.712 49.565 33.864 ;
     RECT  49.385 48.96 49.565 48.984 ;
     RECT  49.237 50.448 49.597 51.24 ;
     RECT  49.057 68.736 49.637 70.728 ;
     RECT  49.187 54.624 49.645 57.048 ;
     RECT  49.565 29.04 49.669 33.864 ;
     RECT  49.025 35.328 49.669 35.352 ;
     RECT  49.561 77.424 49.669 79.464 ;
     RECT  49.669 29.04 49.673 35.352 ;
     RECT  49.645 54.624 49.673 56.712 ;
     RECT  49.561 72.576 49.673 75.48 ;
     RECT  49.669 76.896 49.715 79.464 ;
     RECT  49.715 76.896 49.756 76.92 ;
     RECT  49.237 0.048 49.772 0.504 ;
     RECT  49.273 4.128 49.777 10.728 ;
     RECT  49.187 58.032 49.777 58.152 ;
     RECT  49.637 68.736 49.817 70.296 ;
     RECT  49.777 3.888 49.849 10.728 ;
     RECT  49.565 11.712 49.849 28.008 ;
     RECT  49.849 3.888 49.889 28.008 ;
     RECT  49.345 61.344 49.909 62.28 ;
     RECT  49.061 2.304 49.957 2.808 ;
     RECT  49.777 58.032 49.964 58.248 ;
     RECT  49.489 59.808 49.964 60.264 ;
     RECT  49.909 61.344 49.993 62.328 ;
     RECT  49.417 63.312 49.993 67.464 ;
     RECT  49.673 29.376 49.997 35.352 ;
     RECT  49.993 61.344 50.029 67.464 ;
     RECT  49.817 68.736 50.029 68.808 ;
     RECT  49.957 2.304 50.053 3.768 ;
     RECT  49.997 29.472 50.137 35.352 ;
     RECT  49.139 36.576 50.137 37.08 ;
     RECT  49.021 52.944 50.281 52.968 ;
     RECT  49.093 39.888 50.317 47.832 ;
     RECT  49.673 74.976 50.317 75.48 ;
     RECT  49.597 50.448 50.353 51.912 ;
     RECT  50.053 2.256 50.425 3.768 ;
     RECT  50.281 52.944 50.437 53.592 ;
     RECT  49.715 77.952 50.677 79.464 ;
     RECT  50.353 50.16 50.725 51.912 ;
     RECT  49.673 72.576 50.749 73.896 ;
     RECT  50.317 74.976 50.749 75.528 ;
     RECT  50.029 61.344 50.785 68.808 ;
     RECT  49.817 69.888 50.785 70.296 ;
     RECT  50.425 1.728 50.819 3.768 ;
     RECT  49.964 58.032 50.821 60.264 ;
     RECT  50.785 61.296 50.821 68.808 ;
     RECT  50.137 29.472 50.857 37.08 ;
     RECT  49.889 4.752 50.869 28.008 ;
     RECT  50.725 50.112 50.893 51.912 ;
     RECT  50.317 39.888 50.929 48.648 ;
     RECT  50.819 2.064 51.008 3.768 ;
     RECT  50.869 4.752 51.008 28.44 ;
     RECT  50.857 29.472 51.008 37.176 ;
     RECT  49.421 38.16 51.008 38.424 ;
     RECT  50.929 39.888 51.008 48.984 ;
     RECT  50.893 50.064 51.008 51.912 ;
     RECT  50.437 52.896 51.008 53.592 ;
     RECT  49.673 54.624 51.008 56.328 ;
     RECT  50.821 58.032 51.008 68.808 ;
     RECT  50.785 69.888 51.008 70.68 ;
     RECT  50.749 72.576 51.008 75.528 ;
     RECT  50.677 77.568 51.008 79.464 ;
     RECT  51.008 2.064 51.112 79.932 ;
     RECT  51.112 2.064 51.251 79.662 ;
     RECT  51.251 2.208 51.304 79.662 ;
     RECT  49.772 0.048 51.325 0.552 ;
     RECT  51.304 50.064 51.365 50.808 ;
     RECT  51.304 65.52 51.401 69.192 ;
     RECT  51.325 0.048 51.409 0.6 ;
     RECT  51.304 71.328 51.58 75.816 ;
     RECT  51.409 0.048 51.581 0.552 ;
     RECT  51.401 65.76 51.581 69.192 ;
     RECT  51.304 34.56 51.689 38.04 ;
     RECT  51.304 61.632 51.731 64.392 ;
     RECT  51.304 54.624 51.797 56.328 ;
     RECT  51.304 77.568 51.797 79.272 ;
     RECT  51.304 27.264 51.833 28.008 ;
     RECT  51.833 27.264 51.869 27.912 ;
     RECT  51.797 77.568 51.869 77.976 ;
     RECT  51.304 19.872 52.013 22.776 ;
     RECT  51.869 77.952 52.049 77.976 ;
     RECT  51.689 34.656 52.06 38.04 ;
     RECT  51.304 48.96 52.121 48.984 ;
     RECT  51.797 54.72 52.157 56.328 ;
     RECT  51.731 62.16 52.265 64.392 ;
     RECT  51.581 69.168 52.297 69.192 ;
     RECT  51.304 70.272 52.297 70.296 ;
     RECT  51.304 11.712 52.333 14.568 ;
     RECT  51.304 15.744 52.333 18.072 ;
     RECT  51.304 59.184 52.333 59.208 ;
     RECT  51.304 23.808 52.369 26.184 ;
     RECT  51.304 30.336 52.369 33.096 ;
     RECT  52.369 30.192 52.405 33.096 ;
     RECT  51.365 50.112 52.405 50.808 ;
     RECT  51.304 51.888 52.405 52.44 ;
     RECT  52.333 58.704 52.405 59.208 ;
     RECT  51.58 72.96 52.405 75.816 ;
     RECT  52.265 62.16 52.409 62.28 ;
     RECT  51.304 39.792 52.445 45.816 ;
     RECT  51.581 65.76 52.453 67.32 ;
     RECT  52.405 72.96 52.492 76.248 ;
     RECT  52.297 69.168 52.501 70.296 ;
     RECT  51.58 71.328 52.501 71.64 ;
     RECT  52.445 39.792 52.517 44.472 ;
     RECT  51.581 0.096 52.549 0.552 ;
     RECT  52.453 65.52 52.553 67.32 ;
     RECT  51.304 2.208 52.585 10.728 ;
     RECT  52.333 11.712 52.585 18.072 ;
     RECT  52.445 45.744 52.585 45.816 ;
     RECT  51.304 46.8 52.585 47.688 ;
     RECT  52.409 62.256 52.589 62.28 ;
     RECT  52.501 69.168 52.621 71.64 ;
     RECT  52.492 75.168 52.621 76.248 ;
     RECT  52.621 68.496 52.625 71.64 ;
     RECT  52.549 0.096 52.669 1.176 ;
     RECT  52.157 55.92 52.693 56.328 ;
     RECT  52.405 58.656 52.729 59.208 ;
     RECT  52.517 39.984 52.787 44.472 ;
     RECT  52.369 23.664 52.801 26.184 ;
     RECT  51.869 27.264 52.801 27.336 ;
     RECT  52.405 29.04 52.837 29.064 ;
     RECT  52.405 30.096 52.837 33.096 ;
     RECT  52.06 34.656 52.837 37.752 ;
     RECT  52.625 68.496 52.841 70.824 ;
     RECT  52.729 58.656 52.909 59.352 ;
     RECT  52.265 63.648 52.909 64.392 ;
     RECT  52.585 45.744 52.913 47.688 ;
     RECT  52.837 29.04 52.924 37.752 ;
     RECT  52.787 40.08 52.949 44.472 ;
     RECT  52.013 19.872 52.981 22.632 ;
     RECT  52.801 23.664 52.981 27.336 ;
     RECT  52.945 54.432 53.017 54.552 ;
     RECT  52.585 2.208 53.027 18.072 ;
     RECT  52.841 70.512 53.027 70.824 ;
     RECT  52.693 55.92 53.053 56.376 ;
     RECT  51.304 57.408 53.053 57.432 ;
     RECT  52.909 58.656 53.092 60.168 ;
     RECT  53.092 58.608 53.125 60.168 ;
     RECT  52.841 68.496 53.125 69.192 ;
     RECT  53.027 17.088 53.129 18.072 ;
     RECT  52.924 34.176 53.129 37.752 ;
     RECT  53.129 17.136 53.201 18.072 ;
     RECT  52.621 75.168 53.212 76.392 ;
     RECT  53.125 58.608 53.233 60.696 ;
     RECT  53.053 55.92 53.305 57.432 ;
     RECT  53.233 58.608 53.305 61.176 ;
     RECT  52.405 50.112 53.309 52.44 ;
     RECT  51.797 79.248 53.309 79.272 ;
     RECT  53.125 68.4 53.341 69.192 ;
     RECT  53.305 55.92 53.345 61.176 ;
     RECT  53.017 53.568 53.365 54.552 ;
     RECT  53.345 55.92 53.365 60.696 ;
     RECT  53.089 48.096 53.377 48.12 ;
     RECT  52.913 45.744 53.381 47.112 ;
     RECT  53.365 53.568 53.453 60.696 ;
     RECT  52.949 43.152 53.525 44.472 ;
     RECT  53.525 43.536 53.555 44.472 ;
     RECT  52.981 19.872 53.593 27.336 ;
     RECT  53.377 48.096 53.593 48.648 ;
     RECT  53.309 50.112 53.593 52.104 ;
     RECT  53.453 53.568 53.593 54.648 ;
     RECT  52.924 29.04 53.596 33.048 ;
     RECT  53.381 45.744 53.597 47.064 ;
     RECT  53.212 76.224 53.633 76.392 ;
     RECT  53.633 76.368 53.669 76.392 ;
     RECT  53.129 34.8 53.701 37.752 ;
     RECT  53.557 38.784 53.701 38.808 ;
     RECT  52.909 63.648 53.701 64.968 ;
     RECT  52.669 0.144 53.729 1.176 ;
     RECT  53.027 2.208 53.729 15.528 ;
     RECT  53.555 44.112 53.737 44.472 ;
     RECT  53.597 45.744 53.737 46.008 ;
     RECT  52.553 66.192 53.737 67.32 ;
     RECT  53.341 68.352 53.737 69.192 ;
     RECT  53.701 34.8 53.777 38.808 ;
     RECT  52.492 72.96 53.797 73.896 ;
     RECT  53.729 0.144 53.813 15.528 ;
     RECT  52.949 40.08 53.849 42.072 ;
     RECT  53.596 29.616 53.884 33.048 ;
     RECT  53.797 72.144 53.884 73.896 ;
     RECT  53.884 73.008 53.885 73.896 ;
     RECT  53.593 19.872 53.917 27.624 ;
     RECT  53.201 17.184 53.953 18.072 ;
     RECT  53.813 0.144 54.065 1.224 ;
     RECT  53.917 19.392 54.097 27.624 ;
     RECT  53.849 40.08 54.169 41.976 ;
     RECT  53.737 66.192 54.172 69.192 ;
     RECT  54.097 19.392 54.173 28.44 ;
     RECT  53.701 63.648 54.173 65.016 ;
     RECT  53.027 70.512 54.205 70.68 ;
     RECT  54.173 23.616 54.245 28.44 ;
     RECT  53.597 47.04 54.245 47.064 ;
     RECT  53.212 75.168 54.317 75.192 ;
     RECT  53.953 17.184 54.385 18.168 ;
     RECT  54.173 19.392 54.385 22.632 ;
     RECT  53.777 34.8 54.385 38.184 ;
     RECT  53.453 56.016 54.389 60.696 ;
     RECT  54.172 66.192 54.389 68.424 ;
     RECT  53.813 2.208 54.421 15.528 ;
     RECT  54.065 0.144 54.457 0.6 ;
     RECT  54.173 63.648 54.461 64.776 ;
     RECT  53.737 44.112 54.497 46.008 ;
     RECT  54.205 70.512 54.497 71.208 ;
     RECT  54.389 66.192 54.533 68.328 ;
     RECT  53.593 48.096 54.565 52.104 ;
     RECT  53.885 73.056 54.565 73.896 ;
     RECT  54.385 17.184 54.601 22.632 ;
     RECT  54.565 47.712 54.601 52.104 ;
     RECT  53.593 53.088 54.601 54.648 ;
     RECT  54.601 47.712 54.677 54.648 ;
     RECT  54.245 23.616 54.707 28.152 ;
     RECT  54.533 66.192 54.707 68.088 ;
     RECT  54.677 47.712 54.713 53.4 ;
     RECT  53.884 30.144 54.745 33.048 ;
     RECT  54.385 34.08 54.745 38.184 ;
     RECT  54.707 66.192 54.749 67.704 ;
     RECT  54.389 56.016 54.805 60.168 ;
     RECT  54.169 39.792 54.889 41.976 ;
     RECT  54.745 30.144 54.949 38.184 ;
     RECT  54.889 39.792 54.949 42.216 ;
     RECT  54.313 69.504 54.965 69.528 ;
     RECT  54.707 26.064 55.001 28.152 ;
     RECT  54.949 30.144 55.037 42.216 ;
     RECT  55.001 26.064 55.145 26.088 ;
     RECT  54.713 47.712 55.145 49.032 ;
     RECT  54.457 0.048 55.177 0.6 ;
     RECT  55.037 39.792 55.213 42.216 ;
     RECT  54.601 17.136 55.217 22.632 ;
     RECT  54.805 55.824 55.235 60.168 ;
     RECT  55.217 17.184 55.249 22.632 ;
     RECT  54.707 23.616 55.249 24.648 ;
     RECT  55.037 30.144 55.253 38.76 ;
     RECT  55.177 0.048 55.26 1.176 ;
     RECT  54.745 76.464 55.321 76.488 ;
     RECT  55.249 17.184 55.325 24.648 ;
     RECT  54.497 70.656 55.325 71.208 ;
     RECT  55.321 76.464 55.381 76.92 ;
     RECT  55.001 27.072 55.393 28.152 ;
     RECT  55.325 17.184 55.397 18.312 ;
     RECT  55.393 27.072 55.397 28.392 ;
     RECT  55.26 0.048 55.427 1.224 ;
     RECT  55.235 56.208 55.501 60.168 ;
     RECT  55.213 61.2 55.501 61.368 ;
     RECT  54.497 44.112 55.645 45.048 ;
     RECT  54.461 63.648 55.645 64.584 ;
     RECT  54.565 73.056 55.645 74.472 ;
     RECT  54.421 2.208 55.717 15.576 ;
     RECT  55.645 43.92 55.717 45.048 ;
     RECT  54.601 46.32 55.753 46.584 ;
     RECT  55.145 47.712 55.753 48.696 ;
     RECT  55.253 30.144 55.789 35.832 ;
     RECT  55.325 70.8 55.789 71.208 ;
     RECT  55.325 19.344 55.813 24.648 ;
     RECT  55.717 43.344 55.861 45.048 ;
     RECT  55.501 56.208 55.933 61.368 ;
     RECT  55.933 56.208 56.005 62.136 ;
     RECT  55.213 39.792 56.041 42.36 ;
     RECT  55.861 43.344 56.077 45.192 ;
     RECT  55.753 46.32 56.077 48.696 ;
     RECT  56.041 39.744 56.149 42.36 ;
     RECT  56.077 43.344 56.149 48.696 ;
     RECT  56.149 39.744 56.257 48.696 ;
     RECT  55.717 2.208 56.408 15.96 ;
     RECT  55.397 17.184 56.408 18.168 ;
     RECT  55.813 19.344 56.408 24.984 ;
     RECT  55.397 27.168 56.408 28.392 ;
     RECT  55.789 29.568 56.408 35.832 ;
     RECT  55.253 37.056 56.408 38.76 ;
     RECT  56.257 39.744 56.408 48.792 ;
     RECT  54.713 50.352 56.408 53.4 ;
     RECT  54.677 54.432 56.408 54.648 ;
     RECT  56.005 56.208 56.408 62.232 ;
     RECT  55.645 63.264 56.408 64.584 ;
     RECT  54.749 66.288 56.408 67.704 ;
     RECT  55.645 68.88 56.408 68.904 ;
     RECT  55.789 70.8 56.408 71.64 ;
     RECT  55.645 72.96 56.408 74.472 ;
     RECT  55.381 75.552 56.408 76.92 ;
     RECT  56.408 2.148 56.512 79.932 ;
     RECT  56.512 2.304 56.704 79.662 ;
     RECT  56.704 17.088 56.801 28.488 ;
     RECT  56.704 43.104 56.801 58.2 ;
     RECT  56.704 68.88 56.801 71.64 ;
     RECT  56.704 60.624 56.834 63.624 ;
     RECT  56.704 30.72 56.837 42.072 ;
     RECT  56.837 30.72 56.908 33.816 ;
     RECT  56.704 59.28 56.909 59.592 ;
     RECT  56.837 34.896 56.945 42.072 ;
     RECT  55.427 0.048 56.981 1.176 ;
     RECT  56.834 60.672 57.017 63.624 ;
     RECT  56.704 64.896 57.017 67.464 ;
     RECT  56.801 27.888 57.059 28.488 ;
     RECT  56.704 2.304 57.089 16.056 ;
     RECT  56.801 43.872 57.089 58.2 ;
     RECT  57.017 60.672 57.089 62.568 ;
     RECT  56.704 72.816 57.097 76.2 ;
     RECT  57.059 27.984 57.125 28.488 ;
     RECT  56.945 34.896 57.161 40.152 ;
     RECT  57.097 75.84 57.161 76.2 ;
     RECT  57.161 34.896 57.233 35.832 ;
     RECT  57.161 37.056 57.233 38.424 ;
     RECT  57.089 43.872 57.305 58.152 ;
     RECT  56.801 68.88 57.305 71.448 ;
     RECT  56.909 59.28 57.377 59.496 ;
     RECT  57.305 68.88 57.484 71.4 ;
     RECT  57.233 35.088 57.485 35.832 ;
     RECT  57.484 70.512 57.485 71.4 ;
     RECT  57.089 2.304 57.629 15.816 ;
     RECT  57.097 72.816 57.881 74.808 ;
     RECT  57.017 64.992 57.884 67.464 ;
     RECT  56.801 17.088 57.953 26.616 ;
     RECT  57.884 64.992 57.971 67.56 ;
     RECT  56.704 29.568 58.057 29.592 ;
     RECT  56.908 30.912 58.057 33.816 ;
     RECT  58.057 29.568 58.061 33.816 ;
     RECT  57.161 75.84 58.061 75.864 ;
     RECT  57.305 43.872 58.085 58.104 ;
     RECT  58.085 43.536 58.169 58.104 ;
     RECT  57.233 37.68 58.237 38.424 ;
     RECT  57.161 39.456 58.237 40.152 ;
     RECT  57.017 63.6 58.273 63.624 ;
     RECT  57.881 74.784 58.309 74.808 ;
     RECT  57.629 2.688 58.345 15.816 ;
     RECT  57.953 17.088 58.345 26.232 ;
     RECT  57.377 59.28 58.357 59.352 ;
     RECT  57.089 60.672 58.357 62.328 ;
     RECT  58.237 37.68 58.381 40.152 ;
     RECT  57.484 68.88 58.412 69.528 ;
     RECT  58.357 59.28 58.417 62.328 ;
     RECT  58.273 63.552 58.417 63.816 ;
     RECT  58.345 2.688 58.421 26.232 ;
     RECT  57.485 70.56 58.421 71.352 ;
     RECT  58.417 59.28 58.444 63.816 ;
     RECT  58.444 59.28 58.453 59.352 ;
     RECT  58.412 68.64 58.499 69.528 ;
     RECT  58.169 43.92 58.529 58.104 ;
     RECT  58.421 70.56 58.529 71.304 ;
     RECT  57.125 28.416 58.556 28.488 ;
     RECT  58.421 4.464 58.565 26.232 ;
     RECT  57.485 35.328 58.633 35.832 ;
     RECT  58.381 37.392 58.633 40.152 ;
     RECT  58.061 30.048 58.637 33.816 ;
     RECT  58.499 69.504 58.637 69.528 ;
     RECT  58.556 28.416 58.643 28.632 ;
     RECT  57.971 64.992 58.681 67.128 ;
     RECT  58.633 35.328 58.709 40.152 ;
     RECT  58.529 43.92 58.745 44.52 ;
     RECT  56.945 41.664 58.777 42.072 ;
     RECT  58.444 60.576 58.781 63.816 ;
     RECT  57.881 73.488 58.844 73.8 ;
     RECT  58.309 74.784 58.844 75.672 ;
     RECT  58.777 41.616 58.849 42.072 ;
     RECT  58.529 45.552 58.853 58.104 ;
     RECT  58.853 48.96 58.889 58.104 ;
     RECT  58.849 41.472 58.957 42.072 ;
     RECT  58.844 73.488 58.957 75.672 ;
     RECT  58.957 41.472 58.961 42.168 ;
     RECT  58.745 44.112 58.961 44.52 ;
     RECT  58.709 35.808 58.972 40.152 ;
     RECT  58.421 2.688 58.993 3.384 ;
     RECT  58.993 2.256 59.033 3.384 ;
     RECT  59.033 2.256 59.077 3.288 ;
     RECT  58.781 63.168 59.101 63.816 ;
     RECT  58.681 64.992 59.101 65.064 ;
     RECT  56.981 0.096 59.105 1.176 ;
     RECT  59.077 2.88 59.105 3.288 ;
     RECT  59.105 0.096 59.123 0.264 ;
     RECT  58.565 4.56 59.177 26.232 ;
     RECT  58.889 57.456 59.177 58.104 ;
     RECT  59.177 57.552 59.213 58.104 ;
     RECT  58.637 30.048 59.249 33.384 ;
     RECT  59.177 4.608 59.315 26.232 ;
     RECT  59.269 68.4 59.317 68.424 ;
     RECT  58.853 45.552 59.321 47.976 ;
     RECT  58.529 70.56 59.353 70.68 ;
     RECT  59.315 4.608 59.357 25.752 ;
     RECT  59.249 30.72 59.357 33.384 ;
     RECT  58.961 41.616 59.413 42.168 ;
     RECT  58.681 66.288 59.461 67.128 ;
     RECT  58.889 48.96 59.465 56.328 ;
     RECT  59.357 30.72 59.501 32.856 ;
     RECT  59.317 68.352 59.501 68.424 ;
     RECT  59.213 57.648 59.533 58.104 ;
     RECT  58.453 59.232 59.533 59.352 ;
     RECT  58.972 35.808 59.573 37.704 ;
     RECT  59.321 45.552 59.573 47.928 ;
     RECT  59.105 2.88 59.645 3.048 ;
     RECT  58.972 38.736 59.645 40.152 ;
     RECT  58.643 28.416 59.677 28.44 ;
     RECT  59.389 29.472 59.677 29.496 ;
     RECT  59.101 63.168 59.677 65.064 ;
     RECT  59.461 66.288 59.677 67.176 ;
     RECT  59.353 69.84 59.677 70.68 ;
     RECT  59.465 51.984 59.681 56.328 ;
     RECT  59.501 68.352 59.681 68.376 ;
     RECT  59.677 63.168 59.785 67.176 ;
     RECT  59.785 63.168 59.821 67.32 ;
     RECT  59.357 4.608 59.825 13.656 ;
     RECT  59.677 69.84 59.843 71.832 ;
     RECT  59.821 63.168 59.897 67.56 ;
     RECT  59.843 71.136 59.897 71.832 ;
     RECT  59.645 38.736 59.933 39.912 ;
     RECT  59.681 56.208 59.965 56.328 ;
     RECT  59.897 71.808 59.965 71.832 ;
     RECT  58.957 73.344 59.965 75.672 ;
     RECT  59.965 71.808 59.969 75.672 ;
     RECT  58.885 76.896 59.969 76.92 ;
     RECT  59.533 57.648 60.001 59.352 ;
     RECT  59.123 0.096 60.005 0.168 ;
     RECT  60.001 57.648 60.077 59.544 ;
     RECT  59.413 41.616 60.109 42.984 ;
     RECT  60.001 26.784 60.113 26.808 ;
     RECT  60.109 40.896 60.145 42.984 ;
     RECT  58.961 44.16 60.145 44.52 ;
     RECT  58.781 60.576 60.185 61.992 ;
     RECT  60.185 60.672 60.217 61.992 ;
     RECT  60.077 59.232 60.257 59.544 ;
     RECT  59.933 38.976 60.329 39.912 ;
     RECT  60.257 59.232 60.364 59.352 ;
     RECT  59.357 14.736 60.365 25.752 ;
     RECT  59.677 28.416 60.397 29.496 ;
     RECT  60.217 60.672 60.397 62.04 ;
     RECT  59.897 63.168 60.397 64.296 ;
     RECT  60.077 57.648 60.401 58.248 ;
     RECT  59.969 72.72 60.445 75.672 ;
     RECT  60.401 57.648 60.469 58.008 ;
     RECT  59.897 65.424 60.473 67.56 ;
     RECT  59.843 69.84 60.473 70.104 ;
     RECT  59.573 35.808 60.545 37.608 ;
     RECT  59.965 56.208 60.613 56.424 ;
     RECT  59.825 13.344 60.649 13.656 ;
     RECT  60.365 14.736 60.649 16.056 ;
     RECT  60.361 2.448 60.653 2.472 ;
     RECT  60.469 57.6 60.653 58.008 ;
     RECT  60.445 72.72 60.653 74.424 ;
     RECT  60.365 17.424 60.661 25.752 ;
     RECT  60.145 40.896 60.685 44.52 ;
     RECT  59.573 45.792 60.685 47.928 ;
     RECT  59.465 49.152 60.685 51 ;
     RECT  59.681 51.984 60.689 55.128 ;
     RECT  60.397 60.672 60.689 64.296 ;
     RECT  60.685 40.896 60.721 51 ;
     RECT  60.689 51.984 60.721 54.744 ;
     RECT  60.613 56.208 60.721 56.472 ;
     RECT  60.653 57.6 60.721 57.96 ;
     RECT  60.661 17.424 60.748 26.712 ;
     RECT  60.397 27.936 60.761 29.496 ;
     RECT  60.473 66.24 60.761 67.56 ;
     RECT  59.501 30.72 60.793 32.328 ;
     RECT  60.721 56.208 60.829 57.96 ;
     RECT  60.793 30.72 60.901 33.048 ;
     RECT  60.761 29.04 60.937 29.496 ;
     RECT  60.901 30.624 60.937 33.048 ;
     RECT  60.689 60.816 61.225 64.296 ;
     RECT  60.445 75.648 61.225 75.672 ;
     RECT  61.045 76.992 61.225 77.016 ;
     RECT  60.329 38.976 61.285 39.432 ;
     RECT  60.721 40.896 61.369 54.744 ;
     RECT  60.473 70.08 61.505 70.104 ;
     RECT  61.505 70.08 61.525 70.968 ;
     RECT  61.285 38.688 61.549 39.432 ;
     RECT  61.369 40.464 61.549 54.744 ;
     RECT  59.825 4.608 61.621 12.312 ;
     RECT  61.525 69.984 61.621 70.968 ;
     RECT  61.621 4.512 61.669 12.312 ;
     RECT  60.649 13.344 61.669 16.056 ;
     RECT  60.545 35.808 61.669 37.464 ;
     RECT  61.549 38.688 61.669 54.744 ;
     RECT  60.829 55.968 61.669 57.96 ;
     RECT  60.653 72.768 61.669 74.424 ;
     RECT  61.225 75.648 61.669 77.016 ;
     RECT  61.669 4.512 61.808 16.056 ;
     RECT  60.748 17.424 61.808 26.04 ;
     RECT  60.761 27.936 61.808 27.96 ;
     RECT  60.937 29.04 61.808 33.048 ;
     RECT  60.829 34.224 61.808 34.248 ;
     RECT  61.669 35.424 61.808 37.464 ;
     RECT  61.669 38.688 61.808 58.104 ;
     RECT  60.364 59.328 61.808 59.352 ;
     RECT  61.225 60.816 61.808 64.92 ;
     RECT  60.761 66.24 61.808 67.368 ;
     RECT  60.937 68.352 61.808 68.376 ;
     RECT  61.621 69.84 61.808 70.968 ;
     RECT  61.669 72.768 61.808 77.016 ;
     RECT  61.808 2.148 61.912 79.932 ;
     RECT  61.912 2.418 62.104 79.662 ;
     RECT  62.104 2.448 62.129 37.992 ;
     RECT  60.005 0.144 62.165 0.168 ;
     RECT  62.104 73.344 62.165 75.192 ;
     RECT  62.129 2.448 62.201 32.76 ;
     RECT  62.201 28.416 62.243 32.76 ;
     RECT  62.104 55.824 62.273 57.624 ;
     RECT  62.273 55.824 62.345 57.336 ;
     RECT  62.201 2.448 62.353 27.384 ;
     RECT  62.104 42.048 62.417 54.216 ;
     RECT  62.165 73.344 62.489 75.144 ;
     RECT  62.417 45.264 62.525 54.216 ;
     RECT  62.345 55.824 62.531 56.712 ;
     RECT  62.353 2.448 62.561 26.232 ;
     RECT  62.525 45.456 62.561 54.216 ;
     RECT  62.561 22.608 62.633 26.232 ;
     RECT  62.129 33.888 62.675 37.992 ;
     RECT  62.561 45.984 62.705 54.216 ;
     RECT  62.104 58.704 62.723 68.616 ;
     RECT  62.633 22.608 62.741 23.928 ;
     RECT  62.104 39.216 62.741 40.632 ;
     RECT  62.104 69.84 62.741 71.832 ;
     RECT  62.723 58.704 62.777 68.088 ;
     RECT  62.489 73.776 62.777 75.144 ;
     RECT  62.777 73.776 62.813 74.904 ;
     RECT  62.104 76.368 62.885 76.392 ;
     RECT  62.561 2.448 62.921 21.528 ;
     RECT  62.705 45.984 62.921 54.12 ;
     RECT  62.921 3.84 62.993 21.528 ;
     RECT  62.993 12.288 63.037 21.528 ;
     RECT  63.037 17.136 63.065 21.528 ;
     RECT  62.921 45.984 63.065 54.072 ;
     RECT  63.037 12.288 63.137 15.864 ;
     RECT  63.137 12.528 63.173 15.864 ;
     RECT  62.993 3.84 63.251 11.208 ;
     RECT  63.173 12.528 63.251 12.552 ;
     RECT  63.173 14.064 63.251 15.864 ;
     RECT  63.065 17.136 63.251 18.216 ;
     RECT  62.741 39.792 63.277 40.632 ;
     RECT  63.251 17.136 63.317 17.736 ;
     RECT  62.353 27.312 63.317 27.384 ;
     RECT  62.777 58.704 63.34 62.04 ;
     RECT  63.251 14.256 63.353 15.864 ;
     RECT  62.417 42.048 63.385 44.232 ;
     RECT  62.633 25.2 63.425 26.232 ;
     RECT  62.675 34.752 63.457 37.992 ;
     RECT  63.317 17.616 63.461 17.736 ;
     RECT  62.741 71.808 63.493 71.832 ;
     RECT  62.243 28.512 63.5 32.76 ;
     RECT  62.777 63.024 63.605 68.088 ;
     RECT  63.425 25.632 63.637 26.232 ;
     RECT  62.531 56.064 63.673 56.328 ;
     RECT  63.596 57.456 63.673 57.48 ;
     RECT  63.673 56.064 63.683 57.48 ;
     RECT  63.457 34.752 63.781 38.568 ;
     RECT  63.277 39.792 63.781 40.92 ;
     RECT  63.385 41.952 63.781 44.232 ;
     RECT  63.605 64.56 63.785 68.088 ;
     RECT  62.813 73.776 63.809 74.424 ;
     RECT  63.5 28.128 63.817 32.76 ;
     RECT  63.781 34.752 63.817 40.92 ;
     RECT  63.683 56.064 63.829 57 ;
     RECT  63.781 41.952 63.853 45 ;
     RECT  63.065 45.984 63.853 46.872 ;
     RECT  63.853 41.952 63.857 46.872 ;
     RECT  63.857 42.048 63.868 46.872 ;
     RECT  63.251 4.224 63.893 11.208 ;
     RECT  63.637 25.632 63.893 26.76 ;
     RECT  63.785 66.096 63.893 68.088 ;
     RECT  63.809 72.912 63.893 74.424 ;
     RECT  63.817 28.128 63.925 32.856 ;
     RECT  63.893 67.344 63.929 68.088 ;
     RECT  63.929 67.392 63.961 68.088 ;
     RECT  63.868 45.552 64.037 46.872 ;
     RECT  63.065 47.856 64.067 54.072 ;
     RECT  62.741 22.752 64.073 23.928 ;
     RECT  63.493 71.808 64.073 71.928 ;
     RECT  64.073 22.752 64.109 22.872 ;
     RECT  63.829 55.824 64.109 57 ;
     RECT  64.067 49.776 64.177 54.072 ;
     RECT  63.893 73.776 64.177 74.424 ;
     RECT  63.34 58.704 64.181 60.888 ;
     RECT  63.34 61.968 64.213 62.04 ;
     RECT  63.605 63.024 64.213 63.24 ;
     RECT  62.741 69.84 64.249 70.68 ;
     RECT  63.785 64.56 64.253 64.584 ;
     RECT  64.109 22.752 64.289 22.776 ;
     RECT  63.961 67.392 64.321 68.568 ;
     RECT  63.925 28.128 64.364 32.904 ;
     RECT  64.364 27.744 64.451 32.904 ;
     RECT  63.893 4.224 64.469 6.024 ;
     RECT  63.893 25.728 64.469 25.896 ;
     RECT  63.065 19.344 64.501 21.528 ;
     RECT  63.853 75.744 64.501 75.768 ;
     RECT  63.829 76.752 64.501 76.776 ;
     RECT  62.921 2.448 64.505 2.472 ;
     RECT  64.501 75.744 64.541 76.776 ;
     RECT  64.213 61.968 64.597 63.24 ;
     RECT  64.037 45.648 64.613 46.872 ;
     RECT  63.461 17.712 64.681 17.736 ;
     RECT  63.817 34.128 64.685 40.92 ;
     RECT  64.177 49.776 64.685 54.936 ;
     RECT  64.451 28.128 64.693 32.904 ;
     RECT  64.685 34.128 64.693 37.176 ;
     RECT  64.073 23.904 64.825 23.928 ;
     RECT  64.597 61.872 64.825 63.24 ;
     RECT  64.177 73.776 64.825 74.616 ;
     RECT  64.541 75.744 64.825 76.536 ;
     RECT  64.693 28.128 64.865 37.176 ;
     RECT  63.893 66.096 64.892 66.312 ;
     RECT  64.501 19.344 64.933 22.248 ;
     RECT  63.868 42.048 64.933 44.472 ;
     RECT  64.865 28.128 64.937 35.976 ;
     RECT  64.933 42.048 64.969 44.52 ;
     RECT  64.937 31.44 64.973 35.976 ;
     RECT  64.892 65.904 64.979 66.312 ;
     RECT  64.979 66.096 64.981 66.312 ;
     RECT  64.321 67.392 64.981 68.712 ;
     RECT  63.893 7.152 65.005 11.208 ;
     RECT  64.685 38.208 65.005 40.92 ;
     RECT  64.969 41.952 65.005 44.52 ;
     RECT  64.613 45.648 65.005 46.68 ;
     RECT  64.469 25.824 65.009 25.896 ;
     RECT  64.249 69.84 65.009 71.304 ;
     RECT  63.353 14.256 65.029 15.816 ;
     RECT  64.681 16.848 65.029 17.736 ;
     RECT  64.825 73.776 65.045 76.536 ;
     RECT  65.029 14.256 65.113 17.736 ;
     RECT  64.933 18.864 65.113 22.248 ;
     RECT  64.825 61.872 65.117 64.104 ;
     RECT  64.981 66.096 65.149 68.712 ;
     RECT  65.009 69.84 65.149 70.104 ;
     RECT  65.045 73.776 65.153 74.856 ;
     RECT  64.825 23.904 65.18 24.168 ;
     RECT  65.005 7.152 65.185 11.976 ;
     RECT  64.437 13.008 65.185 13.032 ;
     RECT  64.973 31.44 65.189 34.68 ;
     RECT  64.973 35.808 65.189 35.976 ;
     RECT  65.009 71.088 65.189 71.304 ;
     RECT  64.109 55.92 65.221 56.568 ;
     RECT  64.837 57.648 65.221 57.672 ;
     RECT  64.469 4.944 65.257 6.024 ;
     RECT  65.185 7.152 65.257 13.032 ;
     RECT  64.181 58.752 65.257 60.888 ;
     RECT  65.117 61.872 65.257 62.952 ;
     RECT  65.149 66.096 65.261 70.104 ;
     RECT  65.18 23.28 65.267 24.168 ;
     RECT  65.221 55.92 65.297 57.672 ;
     RECT  64.685 50.16 65.329 54.936 ;
     RECT  65.267 24.144 65.333 24.168 ;
     RECT  65.261 67.632 65.333 70.104 ;
     RECT  65.257 4.944 65.401 13.032 ;
     RECT  65.333 68.688 65.405 70.104 ;
     RECT  65.153 73.776 65.441 74.04 ;
     RECT  65.149 72.528 65.473 72.552 ;
     RECT  65.441 73.776 65.473 73.8 ;
     RECT  65.009 25.824 65.477 25.848 ;
     RECT  65.113 26.832 65.516 26.856 ;
     RECT  64.937 28.128 65.516 29.832 ;
     RECT  65.113 14.256 65.545 22.248 ;
     RECT  65.545 14.256 65.549 23.064 ;
     RECT  65.189 31.44 65.549 33.864 ;
     RECT  65.405 68.688 65.549 69.912 ;
     RECT  65.117 63.936 65.581 64.104 ;
     RECT  65.297 56.352 65.585 57.672 ;
     RECT  65.189 71.088 65.585 71.16 ;
     RECT  65.516 26.832 65.621 29.832 ;
     RECT  64.067 47.856 65.621 48.216 ;
     RECT  65.621 27.024 65.649 29.832 ;
     RECT  65.401 4.944 65.833 13.176 ;
     RECT  65.549 14.256 65.833 16.872 ;
     RECT  65.257 58.752 65.905 62.952 ;
     RECT  65.549 17.856 65.909 23.064 ;
     RECT  65.261 66.096 65.939 66.504 ;
     RECT  65.649 29.808 65.941 29.832 ;
     RECT  65.549 31.44 65.941 33.576 ;
     RECT  65.549 68.688 65.945 68.712 ;
     RECT  65.833 4.944 66.013 16.872 ;
     RECT  64.865 37.104 66.013 37.176 ;
     RECT  65.005 38.208 66.013 46.68 ;
     RECT  65.329 50.16 66.049 55.176 ;
     RECT  66.013 4.272 66.125 16.872 ;
     RECT  65.905 57.936 66.133 62.952 ;
     RECT  65.581 63.936 66.133 64.92 ;
     RECT  66.013 37.104 66.193 46.68 ;
     RECT  65.941 29.808 66.197 33.576 ;
     RECT  66.193 37.104 66.197 46.728 ;
     RECT  65.045 76.512 66.229 76.536 ;
     RECT  65.189 35.808 66.301 35.832 ;
     RECT  66.197 37.104 66.301 37.464 ;
     RECT  65.585 71.136 66.301 71.16 ;
     RECT  65.585 56.352 66.373 56.856 ;
     RECT  66.337 25.056 66.409 25.08 ;
     RECT  66.125 4.272 66.445 10.92 ;
     RECT  66.229 76.368 66.517 76.536 ;
     RECT  65.689 2.784 66.553 2.808 ;
     RECT  66.337 34.8 66.553 34.824 ;
     RECT  66.301 35.808 66.553 37.464 ;
     RECT  66.553 2.688 66.589 2.808 ;
     RECT  66.409 24.72 66.589 25.08 ;
     RECT  66.589 2.592 66.62 2.808 ;
     RECT  66.589 24.624 66.62 25.08 ;
     RECT  66.62 2.256 66.625 2.808 ;
     RECT  65.909 21.12 66.625 23.064 ;
     RECT  66.62 24.624 66.625 25.128 ;
     RECT  65.649 27.024 66.661 28.632 ;
     RECT  66.197 30.576 66.661 33.576 ;
     RECT  65.621 48.192 66.661 48.216 ;
     RECT  66.049 49.536 66.661 55.176 ;
     RECT  66.373 56.304 66.697 56.856 ;
     RECT  66.661 30.576 66.841 33.672 ;
     RECT  66.553 34.8 66.841 37.464 ;
     RECT  65.909 17.856 66.877 20.088 ;
     RECT  66.625 21.12 66.877 25.128 ;
     RECT  66.133 57.936 66.949 64.92 ;
     RECT  65.939 66.288 66.956 66.504 ;
     RECT  66.949 57.936 66.997 65.016 ;
     RECT  66.956 66.192 66.997 66.504 ;
     RECT  66.125 11.952 67.021 16.872 ;
     RECT  66.877 17.856 67.021 25.128 ;
     RECT  66.517 75.408 67.129 76.536 ;
     RECT  66.197 38.496 67.201 46.728 ;
     RECT  66.661 48.192 67.201 55.176 ;
     RECT  66.625 2.256 67.208 2.904 ;
     RECT  66.445 4.128 67.208 10.92 ;
     RECT  67.021 11.952 67.208 25.128 ;
     RECT  66.661 26.208 67.208 29.352 ;
     RECT  66.841 30.576 67.208 37.464 ;
     RECT  67.201 38.496 67.208 55.176 ;
     RECT  66.697 56.256 67.208 56.856 ;
     RECT  66.997 57.936 67.208 66.504 ;
     RECT  65.333 67.632 67.208 67.656 ;
     RECT  65.549 69.888 67.208 69.912 ;
     RECT  66.301 71.136 67.208 71.304 ;
     RECT  65.473 72.528 67.208 73.8 ;
     RECT  67.129 74.928 67.208 76.536 ;
     RECT  67.208 2.148 67.312 79.932 ;
     RECT  67.312 2.418 67.504 79.662 ;
     RECT  67.504 66 67.601 67.272 ;
     RECT  67.504 18.192 67.673 25.992 ;
     RECT  67.504 2.592 67.709 3.96 ;
     RECT  67.504 38.496 67.763 54.84 ;
     RECT  67.763 48.96 67.811 54.84 ;
     RECT  67.504 72.576 67.817 76.344 ;
     RECT  67.817 73.632 67.853 76.344 ;
     RECT  67.811 49.536 67.9 54.744 ;
     RECT  67.709 2.736 67.997 3.96 ;
     RECT  67.504 5.184 67.997 10.632 ;
     RECT  67.504 11.952 67.997 17.064 ;
     RECT  67.997 17.04 68.033 17.064 ;
     RECT  67.9 54.72 68.033 54.744 ;
     RECT  67.673 18.192 68.105 23.928 ;
     RECT  67.853 74.304 68.177 76.344 ;
     RECT  67.763 38.496 68.249 47.688 ;
     RECT  67.504 56.256 68.249 57.624 ;
     RECT  67.504 30.672 68.465 37.464 ;
     RECT  67.9 49.536 68.465 53.352 ;
     RECT  67.673 24.912 68.473 25.992 ;
     RECT  68.105 18.192 68.501 23.592 ;
     RECT  68.473 24.912 68.501 25.08 ;
     RECT  68.465 30.672 68.531 35.88 ;
     RECT  68.249 56.352 68.537 57.624 ;
     RECT  67.997 2.784 68.573 3.96 ;
     RECT  68.249 38.496 68.573 46.68 ;
     RECT  68.531 33.6 68.609 35.88 ;
     RECT  68.501 18.192 68.641 23.16 ;
     RECT  67.997 5.184 68.677 5.304 ;
     RECT  67.504 27.648 68.677 29.016 ;
     RECT  68.609 33.6 68.681 34.776 ;
     RECT  67.504 61.344 68.713 64.968 ;
     RECT  67.601 66 68.713 66.216 ;
     RECT  68.465 37.008 68.749 37.464 ;
     RECT  68.573 38.496 68.749 44.136 ;
     RECT  68.609 35.856 68.753 35.88 ;
     RECT  67.997 11.952 68.825 15.576 ;
     RECT  68.677 27.408 68.825 29.016 ;
     RECT  68.465 49.536 68.893 50.376 ;
     RECT  68.749 37.008 68.897 44.136 ;
     RECT  68.537 57.12 68.924 57.624 ;
     RECT  67.504 58.608 68.924 59.832 ;
     RECT  68.465 51.36 68.929 53.352 ;
     RECT  68.713 61.344 68.963 66.216 ;
     RECT  68.501 24.912 68.969 24.936 ;
     RECT  68.177 74.304 68.969 75.528 ;
     RECT  68.825 11.952 69.001 13.128 ;
     RECT  68.531 30.672 69.001 31.944 ;
     RECT  68.963 66.192 69.001 66.216 ;
     RECT  67.601 67.248 69.001 67.272 ;
     RECT  68.573 2.784 69.005 3.624 ;
     RECT  68.897 37.008 69.005 40.44 ;
     RECT  68.963 61.344 69.005 64.968 ;
     RECT  68.924 57.12 69.033 59.832 ;
     RECT  68.641 17.136 69.037 23.16 ;
     RECT  69.001 66.192 69.041 67.272 ;
     RECT  69.033 58.608 69.113 59.832 ;
     RECT  67.504 68.256 69.113 71.256 ;
     RECT  68.969 74.544 69.113 75.528 ;
     RECT  69.005 2.784 69.149 3.528 ;
     RECT  67.997 6.336 69.149 9.864 ;
     RECT  69.149 9.072 69.185 9.864 ;
     RECT  68.249 47.664 69.217 47.688 ;
     RECT  69.113 69.456 69.221 71.256 ;
     RECT  69.149 6.336 69.257 8.04 ;
     RECT  69.005 37.008 69.257 39.912 ;
     RECT  68.825 14.112 69.289 15.576 ;
     RECT  69.221 69.6 69.293 71.256 ;
     RECT  69.113 74.544 69.293 74.616 ;
     RECT  69.001 30.192 69.365 31.944 ;
     RECT  69.217 47.664 69.397 48.408 ;
     RECT  68.893 49.44 69.397 50.376 ;
     RECT  69.033 57.12 69.401 57.624 ;
     RECT  68.677 5.136 69.437 5.304 ;
     RECT  69.005 61.728 69.473 64.968 ;
     RECT  68.897 41.76 69.532 44.136 ;
     RECT  69.257 37.008 69.617 37.896 ;
     RECT  68.573 45.696 69.617 46.68 ;
     RECT  69.397 47.664 69.644 50.376 ;
     RECT  68.929 51.36 69.644 53.592 ;
     RECT  69.473 61.728 69.653 64.92 ;
     RECT  69.293 74.592 69.653 74.616 ;
     RECT  69.289 14.112 69.685 15.912 ;
     RECT  69.037 17.088 69.685 23.16 ;
     RECT  69.685 14.112 69.725 23.16 ;
     RECT  69.644 47.664 69.731 53.592 ;
     RECT  69.185 9.312 69.757 9.864 ;
     RECT  69.365 31.2 69.761 31.944 ;
     RECT  68.825 27.888 69.793 29.016 ;
     RECT  69.365 30.192 69.793 30.216 ;
     RECT  69.257 6.336 69.797 7.992 ;
     RECT  69.757 9.312 69.829 10.344 ;
     RECT  67.817 72.576 69.836 72.6 ;
     RECT  69.532 41.76 69.865 42.552 ;
     RECT  69.731 47.664 69.868 50.376 ;
     RECT  69.836 72.336 69.877 72.6 ;
     RECT  69.041 66.288 69.901 67.272 ;
     RECT  69.113 68.256 69.901 68.28 ;
     RECT  69.877 72.336 69.923 72.936 ;
     RECT  69.617 46.56 69.937 46.68 ;
     RECT  69.868 47.664 69.937 48.264 ;
     RECT  69.149 2.784 69.973 3.144 ;
     RECT  69.829 9.312 69.973 10.824 ;
     RECT  69.001 11.808 69.973 13.128 ;
     RECT  69.217 56.064 70.009 56.088 ;
     RECT  69.937 46.56 70.013 48.264 ;
     RECT  69.725 14.928 70.081 23.16 ;
     RECT  68.681 33.648 70.081 34.776 ;
     RECT  69.973 2.736 70.117 3.144 ;
     RECT  69.761 31.344 70.117 31.944 ;
     RECT  69.617 37.008 70.117 37.176 ;
     RECT  69.731 51.36 70.117 53.592 ;
     RECT  70.117 31.344 70.153 32.184 ;
     RECT  70.081 33.168 70.153 34.776 ;
     RECT  70.117 36.624 70.153 37.176 ;
     RECT  69.923 72.912 70.153 72.936 ;
     RECT  70.153 36.528 70.157 37.176 ;
     RECT  69.293 71.088 70.157 71.256 ;
     RECT  69.113 59.04 70.189 59.064 ;
     RECT  69.901 60.336 70.189 60.36 ;
     RECT  70.153 31.344 70.225 34.776 ;
     RECT  70.117 51.36 70.261 54.072 ;
     RECT  70.117 2.736 70.333 3.864 ;
     RECT  69.437 5.184 70.333 5.304 ;
     RECT  69.797 6.336 70.333 7.752 ;
     RECT  70.189 60.336 70.409 60.936 ;
     RECT  69.868 49.344 70.481 50.376 ;
     RECT  70.153 72.912 70.513 72.984 ;
     RECT  69.653 62.544 70.517 64.92 ;
     RECT  70.157 71.232 70.517 71.256 ;
     RECT  69.793 27.888 70.549 30.216 ;
     RECT  69.532 43.632 70.549 44.136 ;
     RECT  70.517 62.736 70.549 64.92 ;
     RECT  69.401 57.12 70.589 57.144 ;
     RECT  70.513 72.912 70.621 73.56 ;
     RECT  69.973 9.312 70.625 13.128 ;
     RECT  70.081 14.928 70.625 23.784 ;
     RECT  70.333 2.736 70.657 3.912 ;
     RECT  70.333 5.184 70.657 7.752 ;
     RECT  69.257 39.024 70.657 39.912 ;
     RECT  69.865 41.088 70.657 42.552 ;
     RECT  70.549 43.632 70.657 44.664 ;
     RECT  70.261 51.36 70.657 54.36 ;
     RECT  70.657 2.736 70.661 7.752 ;
     RECT  70.657 51.36 70.661 54.504 ;
     RECT  69.325 24.816 70.691 24.84 ;
     RECT  70.691 24.768 70.693 24.84 ;
     RECT  70.657 41.088 70.693 44.664 ;
     RECT  70.481 49.68 70.693 50.376 ;
     RECT  70.657 39.024 70.765 40.104 ;
     RECT  70.693 41.088 70.765 45.096 ;
     RECT  70.549 62.736 70.769 65.256 ;
     RECT  70.225 31.344 70.801 35.352 ;
     RECT  70.157 36.528 70.801 37.08 ;
     RECT  69.901 66.288 70.801 68.28 ;
     RECT  69.293 69.6 70.801 69.768 ;
     RECT  70.625 19.392 70.805 23.784 ;
     RECT  70.801 31.344 70.841 37.08 ;
     RECT  70.625 9.36 70.873 13.128 ;
     RECT  70.769 64.896 70.877 65.256 ;
     RECT  70.873 9.36 70.909 13.752 ;
     RECT  70.621 72.912 70.909 74.424 ;
     RECT  70.693 24.768 70.981 25.032 ;
     RECT  68.857 26.448 70.981 26.472 ;
     RECT  70.013 47.328 70.981 48.264 ;
     RECT  70.909 72.912 70.981 74.616 ;
     RECT  70.981 47.328 71.017 48.696 ;
     RECT  70.009 56.016 71.017 56.088 ;
     RECT  70.661 2.784 71.053 7.752 ;
     RECT  70.765 39.024 71.129 45.096 ;
     RECT  70.805 21.264 71.237 23.784 ;
     RECT  70.661 51.888 71.267 54.504 ;
     RECT  71.017 46.8 71.269 48.696 ;
     RECT  71.267 54.048 71.273 54.504 ;
     RECT  70.769 62.736 71.273 63.912 ;
     RECT  70.981 72.672 71.273 74.616 ;
     RECT  71.269 46.272 71.305 48.696 ;
     RECT  70.189 58.512 71.341 59.064 ;
     RECT  70.841 31.728 71.345 37.08 ;
     RECT  71.273 72.672 71.345 73.56 ;
     RECT  71.129 39.024 71.381 44.664 ;
     RECT  71.017 55.872 71.453 56.088 ;
     RECT  70.801 66.288 71.489 69.768 ;
     RECT  70.909 9.36 71.561 13.896 ;
     RECT  70.877 65.088 71.629 65.256 ;
     RECT  71.489 66.288 71.629 69.72 ;
     RECT  70.981 24.768 71.665 26.472 ;
     RECT  71.305 46.128 71.737 48.696 ;
     RECT  70.693 49.68 71.737 50.808 ;
     RECT  71.341 58.512 71.773 59.256 ;
     RECT  71.053 2.784 71.797 7.848 ;
     RECT  71.237 21.264 71.809 22.824 ;
     RECT  71.273 63.792 71.809 63.912 ;
     RECT  71.665 24.768 71.845 26.76 ;
     RECT  71.737 46.128 71.917 50.808 ;
     RECT  71.267 51.888 71.917 52.776 ;
     RECT  71.561 9.36 71.989 13.224 ;
     RECT  71.989 9.216 72.025 13.224 ;
     RECT  71.273 54.096 72.037 54.504 ;
     RECT  70.409 60.816 72.061 60.936 ;
     RECT  71.345 72.672 72.061 72.696 ;
     RECT  71.773 58.416 72.169 59.256 ;
     RECT  72.061 60.672 72.277 60.936 ;
     RECT  70.805 19.392 72.349 20.04 ;
     RECT  71.273 74.592 72.349 74.616 ;
     RECT  71.809 63.792 72.373 64.104 ;
     RECT  71.629 65.088 72.373 69.72 ;
     RECT  72.349 19.008 72.385 20.04 ;
     RECT  71.809 21.12 72.385 22.824 ;
     RECT  71.797 2.544 72.469 7.848 ;
     RECT  70.549 27.888 72.469 30.36 ;
     RECT  71.345 31.92 72.469 37.08 ;
     RECT  70.625 14.928 72.493 18.024 ;
     RECT  72.385 19.008 72.493 22.824 ;
     RECT  72.037 54.096 72.493 55.512 ;
     RECT  71.917 46.128 72.529 52.776 ;
     RECT  72.469 2.544 72.608 7.896 ;
     RECT  72.025 8.976 72.608 13.224 ;
     RECT  72.493 14.928 72.608 22.824 ;
     RECT  71.845 24.144 72.608 26.76 ;
     RECT  72.469 27.888 72.608 37.08 ;
     RECT  71.381 39.024 72.608 42.552 ;
     RECT  71.381 43.584 72.608 44.664 ;
     RECT  72.529 45.744 72.608 52.776 ;
     RECT  72.493 54.096 72.608 55.8 ;
     RECT  72.421 57.072 72.608 57.096 ;
     RECT  72.169 58.416 72.608 59.304 ;
     RECT  72.277 60.672 72.608 61.224 ;
     RECT  71.273 62.736 72.608 62.808 ;
     RECT  72.373 63.792 72.608 69.72 ;
     RECT  72.061 71.904 72.608 72.696 ;
     RECT  72.349 74.064 72.608 74.616 ;
     RECT  72.608 2.148 72.712 79.932 ;
     RECT  72.712 2.418 72.904 79.662 ;
     RECT  72.904 4.656 72.965 5.208 ;
     RECT  72.904 32.256 72.965 37.08 ;
     RECT  72.904 65.76 72.965 67.032 ;
     RECT  72.904 17.712 73.001 20.04 ;
     RECT  72.904 63.792 73.001 64.104 ;
     RECT  72.904 68.4 73.001 70.536 ;
     RECT  73.001 17.904 73.037 20.04 ;
     RECT  72.904 38.832 73.045 49.128 ;
     RECT  72.904 60.96 73.045 62.136 ;
     RECT  72.965 4.656 73.073 5.064 ;
     RECT  72.904 6.288 73.109 9.864 ;
     RECT  73.001 64.032 73.109 64.104 ;
     RECT  73.045 38.832 73.145 48.264 ;
     RECT  72.904 57.552 73.145 59.304 ;
     RECT  73.145 57.552 73.235 58.824 ;
     RECT  72.904 11.136 73.253 13.224 ;
     RECT  72.965 66.288 73.253 67.032 ;
     RECT  73.037 17.904 73.289 17.928 ;
     RECT  73.145 38.832 73.289 47.928 ;
     RECT  72.904 50.16 73.289 53.832 ;
     RECT  73.289 41.952 73.325 47.928 ;
     RECT  73.325 41.952 73.361 46.632 ;
     RECT  73.109 64.032 73.433 64.056 ;
     RECT  73.253 11.952 73.523 13.224 ;
     RECT  73.289 38.832 73.523 40.92 ;
     RECT  73.045 60.96 73.523 61.704 ;
     RECT  72.904 28.224 73.541 30.984 ;
     RECT  72.965 32.256 73.541 36.552 ;
     RECT  72.904 14.208 73.571 16.056 ;
     RECT  73.289 50.304 73.571 53.832 ;
     RECT  73.523 11.952 73.577 13.08 ;
     RECT  73.541 33.6 73.577 36.552 ;
     RECT  73.001 68.64 73.612 70.536 ;
     RECT  73.523 38.832 73.613 39.816 ;
     RECT  73.523 40.848 73.613 40.92 ;
     RECT  73.361 41.952 73.613 46.296 ;
     RECT  73.571 52.176 73.613 53.832 ;
     RECT  72.904 71.904 73.613 72.84 ;
     RECT  73.109 6.288 73.649 7.368 ;
     RECT  73.523 61.008 73.649 61.704 ;
     RECT  73.613 72.48 73.793 72.84 ;
     RECT  72.904 74.064 73.829 74.088 ;
     RECT  73.541 30.768 73.859 30.984 ;
     RECT  73.612 68.64 73.865 69.336 ;
     RECT  73.859 30.96 73.9 30.984 ;
     RECT  72.904 26.496 73.901 26.52 ;
     RECT  73.253 67.008 73.907 67.032 ;
     RECT  73.541 32.256 73.933 32.472 ;
     RECT  72.904 2.832 74.005 3.624 ;
     RECT  73.073 4.656 74.005 4.68 ;
     RECT  73.613 52.512 74.005 53.832 ;
     RECT  72.904 54.96 74.005 54.984 ;
     RECT  73.612 70.512 74.005 70.536 ;
     RECT  74.005 70.512 74.045 71.256 ;
     RECT  73.109 8.544 74.153 9.864 ;
     RECT  73.865 68.736 74.153 69.336 ;
     RECT  73.571 14.688 74.185 16.056 ;
     RECT  73.577 34.08 74.189 35.784 ;
     RECT  73.613 41.952 74.189 45.768 ;
     RECT  73.649 6.336 74.221 7.368 ;
     RECT  72.904 21.168 74.221 22.584 ;
     RECT  72.904 23.664 74.221 25.224 ;
     RECT  74.005 52.512 74.257 54.984 ;
     RECT  73.541 28.224 74.261 29.688 ;
     RECT  73.325 47.664 74.293 47.928 ;
     RECT  74.053 48.96 74.293 48.984 ;
     RECT  74.189 35.52 74.297 35.784 ;
     RECT  74.045 71.088 74.297 71.256 ;
     RECT  74.005 2.832 74.369 4.68 ;
     RECT  74.221 21.168 74.369 25.224 ;
     RECT  74.369 4.56 74.401 4.68 ;
     RECT  74.293 47.664 74.401 48.984 ;
     RECT  73.571 50.304 74.401 50.664 ;
     RECT  74.369 2.832 74.405 2.856 ;
     RECT  74.369 23.424 74.405 25.224 ;
     RECT  74.185 14.688 74.437 16.536 ;
     RECT  74.437 64.8 74.473 64.824 ;
     RECT  74.221 6.336 74.477 8.04 ;
     RECT  73.577 12 74.545 13.08 ;
     RECT  74.437 14.688 74.545 16.728 ;
     RECT  74.221 26.832 74.545 26.856 ;
     RECT  74.401 47.664 74.549 50.664 ;
     RECT  73.613 40.848 74.581 40.872 ;
     RECT  74.189 41.952 74.581 42.264 ;
     RECT  73.235 57.552 74.581 58.44 ;
     RECT  73.037 19.536 74.617 20.04 ;
     RECT  74.369 21.168 74.617 21.672 ;
     RECT  74.257 52.512 74.617 55.848 ;
     RECT  73.649 61.008 74.617 61.608 ;
     RECT  74.405 23.664 74.621 25.224 ;
     RECT  73.897 73.536 74.621 73.56 ;
     RECT  73.613 38.976 74.636 39.816 ;
     RECT  74.636 38.928 74.653 39.816 ;
     RECT  74.581 40.848 74.653 42.264 ;
     RECT  74.581 56.928 74.653 58.44 ;
     RECT  74.473 64.704 74.675 64.824 ;
     RECT  74.401 4.56 74.693 5.112 ;
     RECT  74.477 7.056 74.693 8.04 ;
     RECT  73.933 31.92 74.693 32.472 ;
     RECT  74.545 12 74.765 16.728 ;
     RECT  74.765 12 74.773 13.704 ;
     RECT  74.653 56.832 74.797 58.44 ;
     RECT  74.545 26.832 74.828 26.952 ;
     RECT  74.261 28.224 74.828 29.4 ;
     RECT  74.005 62.688 74.828 62.856 ;
     RECT  74.693 7.728 74.837 8.04 ;
     RECT  74.773 11.376 74.86 13.704 ;
     RECT  74.837 7.728 74.873 7.992 ;
     RECT  74.549 48.528 74.873 50.664 ;
     RECT  74.765 14.688 74.905 16.728 ;
     RECT  74.041 18.192 74.905 18.216 ;
     RECT  74.828 26.832 74.915 29.4 ;
     RECT  74.797 56.832 74.941 58.68 ;
     RECT  74.915 28.272 74.981 29.4 ;
     RECT  74.617 60.432 75.013 61.608 ;
     RECT  74.828 62.688 75.013 63.864 ;
     RECT  74.297 71.088 75.013 71.112 ;
     RECT  75.013 70.56 75.017 71.112 ;
     RECT  74.617 51.888 75.049 55.848 ;
     RECT  74.941 56.832 75.049 58.728 ;
     RECT  74.153 9.84 75.085 9.864 ;
     RECT  75.017 70.56 75.085 70.584 ;
     RECT  74.653 38.016 75.107 42.264 ;
     RECT  74.153 68.736 75.157 68.952 ;
     RECT  75.085 70.272 75.161 70.584 ;
     RECT  74.905 14.688 75.193 18.216 ;
     RECT  74.617 19.536 75.193 21.672 ;
     RECT  74.189 43.44 75.197 45.768 ;
     RECT  75.107 38.016 75.203 41.016 ;
     RECT  74.86 12.336 75.233 13.704 ;
     RECT  74.621 25.2 75.233 25.224 ;
     RECT  75.203 38.016 75.233 39.048 ;
     RECT  75.203 40.56 75.244 41.016 ;
     RECT  74.693 5.088 75.253 5.112 ;
     RECT  73.793 72.48 75.26 72.504 ;
     RECT  75.26 72.288 75.263 72.504 ;
     RECT  75.157 68.688 75.265 68.952 ;
     RECT  75.161 70.272 75.265 70.296 ;
     RECT  75.085 9.84 75.269 10.344 ;
     RECT  75.193 14.688 75.269 21.672 ;
     RECT  74.915 26.832 75.269 26.952 ;
     RECT  74.297 35.76 75.269 35.784 ;
     RECT  74.873 49.44 75.269 50.664 ;
     RECT  75.013 60.432 75.269 63.864 ;
     RECT  75.265 68.688 75.269 70.296 ;
     RECT  75.263 71.76 75.301 72.504 ;
     RECT  75.049 51.888 75.305 58.728 ;
     RECT  75.221 67.008 75.305 67.032 ;
     RECT  75.269 26.88 75.341 26.952 ;
     RECT  75.301 71.76 75.347 72.984 ;
     RECT  75.269 49.44 75.377 50.568 ;
     RECT  75.269 68.688 75.377 69.672 ;
     RECT  74.189 34.08 75.409 34.104 ;
     RECT  75.341 26.928 75.413 26.952 ;
     RECT  75.269 10.32 75.445 10.344 ;
     RECT  75.253 5.088 75.449 5.784 ;
     RECT  75.269 14.688 75.449 19.56 ;
     RECT  75.107 42.192 75.452 42.264 ;
     RECT  75.197 43.44 75.452 43.848 ;
     RECT  75.305 54.672 75.481 58.728 ;
     RECT  75.409 34.08 75.493 34.776 ;
     RECT  75.305 51.888 75.517 52.536 ;
     RECT  75.452 42.192 75.539 43.848 ;
     RECT  75.481 54.672 75.557 59.208 ;
     RECT  75.269 61.728 75.593 63.864 ;
     RECT  75.557 57.84 75.625 59.208 ;
     RECT  75.197 44.832 75.629 45.768 ;
     RECT  75.557 54.672 75.629 56.856 ;
     RECT  75.229 31.68 75.635 31.704 ;
     RECT  75.539 42.192 75.665 42.264 ;
     RECT  75.593 61.728 75.665 63.336 ;
     RECT  75.493 34.08 75.697 34.104 ;
     RECT  75.347 72.96 75.701 72.984 ;
     RECT  75.697 33.648 75.737 34.104 ;
     RECT  75.449 14.688 75.773 17.064 ;
     RECT  74.653 47.424 75.773 47.448 ;
     RECT  74.621 23.664 75.781 23.928 ;
     RECT  75.449 5.76 75.809 5.784 ;
     RECT  75.697 67.248 75.809 67.848 ;
     RECT  75.244 40.992 75.845 41.016 ;
     RECT  75.629 54.672 75.845 56.28 ;
     RECT  75.445 10.32 75.881 11.304 ;
     RECT  75.449 18.768 75.881 19.56 ;
     RECT  75.665 42.24 75.881 42.264 ;
     RECT  75.881 19.2 75.917 19.56 ;
     RECT  75.233 12.336 76.021 13.128 ;
     RECT  75.269 20.544 76.021 21.672 ;
     RECT  74.981 28.368 76.061 29.4 ;
     RECT  75.917 19.2 76.097 19.32 ;
     RECT  75.629 44.832 76.097 45.72 ;
     RECT  75.665 62.496 76.097 63.336 ;
     RECT  75.877 35.808 76.237 35.928 ;
     RECT  75.445 37.056 76.237 37.08 ;
     RECT  74.873 7.968 76.273 7.992 ;
     RECT  75.805 30.384 76.273 30.408 ;
     RECT  75.809 67.248 76.309 67.272 ;
     RECT  75.305 53.664 76.345 53.688 ;
     RECT  75.845 54.672 76.345 55.848 ;
     RECT  75.269 60.432 76.345 60.456 ;
     RECT  76.345 53.664 76.349 55.848 ;
     RECT  76.309 66.624 76.349 67.272 ;
     RECT  76.061 28.368 76.385 28.872 ;
     RECT  76.349 66.624 76.403 66.648 ;
     RECT  75.377 68.928 76.403 69.672 ;
     RECT  75.773 16.512 76.417 17.064 ;
     RECT  75.517 51.84 76.421 52.536 ;
     RECT  76.345 60.432 76.421 60.984 ;
     RECT  75.233 38.352 76.457 39.048 ;
     RECT  76.097 62.976 76.457 63.336 ;
     RECT  75.347 71.76 76.457 71.784 ;
     RECT  75.589 25.728 76.489 25.752 ;
     RECT  76.405 70.656 76.492 70.68 ;
     RECT  75.773 14.688 76.529 15.24 ;
     RECT  76.349 54.144 76.529 55.848 ;
     RECT  76.403 69.456 76.529 69.48 ;
     RECT  76.273 30.384 76.565 30.888 ;
     RECT  75.661 64.944 76.597 64.968 ;
     RECT  75.781 23.664 76.604 23.976 ;
     RECT  76.489 25.728 76.633 26.616 ;
     RECT  76.421 60.96 76.669 60.984 ;
     RECT  75.881 10.32 76.673 10.824 ;
     RECT  75.377 49.44 76.673 50.328 ;
     RECT  76.597 64.848 76.693 64.968 ;
     RECT  76.273 7.968 76.745 8.808 ;
     RECT  76.604 23.136 76.745 23.976 ;
     RECT  75.539 43.488 76.748 43.848 ;
     RECT  76.097 44.832 76.748 44.856 ;
     RECT  76.237 35.808 76.781 37.08 ;
     RECT  75.625 57.84 76.781 59.256 ;
     RECT  76.748 43.488 76.817 44.856 ;
     RECT  76.777 31.488 76.849 31.8 ;
     RECT  76.673 10.704 76.853 10.824 ;
     RECT  76.817 43.488 76.885 44.568 ;
     RECT  76.693 64.752 76.925 64.968 ;
     RECT  76.925 64.752 76.961 64.776 ;
     RECT  76.885 42.768 76.972 44.568 ;
     RECT  76.021 20.544 76.993 22.152 ;
     RECT  76.745 23.136 76.993 23.736 ;
     RECT  76.741 46.032 76.997 46.056 ;
     RECT  76.673 50.304 77.033 50.328 ;
     RECT  76.417 16.512 77.101 17.784 ;
     RECT  77.101 15.84 77.281 17.784 ;
     RECT  76.097 19.296 77.281 19.32 ;
     RECT  76.529 14.688 77.317 14.808 ;
     RECT  76.781 35.808 77.317 36.312 ;
     RECT  77.317 35.376 77.324 36.312 ;
     RECT  76.457 39.024 77.425 39.048 ;
     RECT  76.457 62.976 77.425 63 ;
     RECT  77.18 63.984 77.425 64.008 ;
     RECT  76.565 30.384 77.461 30.408 ;
     RECT  77.425 39.024 77.497 39.768 ;
     RECT  76.421 51.84 77.497 52.296 ;
     RECT  77.497 38.736 77.509 39.768 ;
     RECT  76.993 20.544 77.749 23.736 ;
     RECT  77.497 51.216 77.785 52.296 ;
     RECT  76.529 54.144 77.857 55.272 ;
     RECT  77.281 15.84 77.893 19.32 ;
     RECT  77.749 20.544 77.893 24.504 ;
     RECT  76.385 28.368 77.893 28.632 ;
     RECT  77.749 48.672 78.001 48.696 ;
     RECT  76.745 7.968 78.008 7.992 ;
     RECT  76.853 10.704 78.008 10.728 ;
     RECT  76.021 12.288 78.008 13.128 ;
     RECT  77.317 14.304 78.008 14.808 ;
     RECT  77.893 15.84 78.008 24.504 ;
     RECT  76.633 25.728 78.008 26.712 ;
     RECT  77.893 27.888 78.008 28.632 ;
     RECT  77.461 29.616 78.008 30.408 ;
     RECT  76.849 31.488 78.008 31.896 ;
     RECT  75.737 33.648 78.008 33.672 ;
     RECT  77.324 34.752 78.008 36.312 ;
     RECT  77.509 38.112 78.008 39.768 ;
     RECT  76.972 43.488 78.008 44.568 ;
     RECT  77.509 45.6 78.008 45.624 ;
     RECT  77.893 46.608 78.008 46.632 ;
     RECT  78.001 48.672 78.008 49.32 ;
     RECT  77.785 51.216 78.008 52.824 ;
     RECT  77.857 53.808 78.008 55.272 ;
     RECT  76.781 57.84 78.008 59.064 ;
     RECT  76.669 60.96 78.008 61.896 ;
     RECT  77.425 62.976 78.008 64.008 ;
     RECT  77.489 66.624 78.008 66.648 ;
     RECT  78.008 2.148 78.112 79.932 ;
     RECT  78.112 2.418 78.304 79.662 ;
     RECT  78.304 39.744 78.329 39.768 ;
     RECT  78.304 58.512 78.329 58.536 ;
     RECT  78.304 7.968 78.401 7.992 ;
     RECT  78.304 46.608 78.419 46.92 ;
     RECT  78.304 49.152 78.419 49.176 ;
     RECT  78.304 51.216 78.437 51.24 ;
     RECT  78.304 52.8 78.437 52.824 ;
     RECT  78.304 56.832 78.437 56.856 ;
     RECT  78.304 35.808 78.509 36.408 ;
     RECT  78.304 61.056 78.509 63.912 ;
     RECT  78.304 22.224 78.542 22.296 ;
     RECT  78.304 29.616 78.545 31.752 ;
     RECT  78.509 35.808 78.545 36.312 ;
     RECT  78.545 30.96 78.581 31.752 ;
     RECT  78.509 63.552 78.617 63.912 ;
     RECT  78.304 16.8 78.689 19.512 ;
     RECT  78.542 22.272 78.689 22.296 ;
     RECT  78.617 63.696 78.689 63.912 ;
     RECT  78.304 25.728 78.725 26.136 ;
     RECT  78.304 27.888 78.725 28.392 ;
     RECT  78.689 63.888 78.733 63.912 ;
     RECT  78.509 61.056 78.755 62.184 ;
     RECT  78.304 54.672 78.761 54.696 ;
     RECT  78.304 14.208 78.797 15.144 ;
     RECT  78.755 61.68 78.797 62.184 ;
     RECT  78.689 16.8 78.803 18.408 ;
     RECT  78.803 16.8 78.833 17.4 ;
     RECT  78.304 24.48 78.833 24.504 ;
     RECT  78.725 25.728 78.833 25.752 ;
     RECT  78.545 29.616 78.833 29.64 ;
     RECT  78.581 30.96 78.833 31.512 ;
     RECT  78.304 34.8 78.833 34.824 ;
     RECT  78.689 19.488 78.844 19.512 ;
     RECT  78.797 15.12 78.869 15.144 ;
     RECT  78.725 28.368 78.869 28.392 ;
     RECT  78.545 36.288 78.869 36.312 ;
     RECT  78.797 62.16 78.869 62.184 ;
     RECT  78.304 10.176 78.941 10.2 ;
     RECT  78.833 30.96 78.941 30.984 ;
     RECT  78.304 43.824 79.049 43.848 ;
     RECT  80.773 21.216 80.917 21.24 ;
     RECT  80.917 21.216 82.044 21.528 ;
    LAYER M5 ;
     RECT  49.824 0.016 59.16 0.515 ;
     RECT  49.824 0.515 51.384 0.563 ;
     RECT  49.92 0.563 51.384 0.611 ;
     RECT  52.8 0.515 59.16 1.187 ;
     RECT  49.92 0.611 50.808 2.053 ;
     RECT  67.2 2.137 67.32 2.245 ;
     RECT  49.92 2.053 51.24 2.339 ;
     RECT  2.4 2.137 2.52 2.407 ;
     RECT  7.8 2.137 7.92 2.407 ;
     RECT  13.2 2.137 13.32 2.407 ;
     RECT  18.6 2.137 18.72 2.407 ;
     RECT  24 2.137 24.12 2.407 ;
     RECT  29.4 2.137 29.52 2.407 ;
     RECT  34.8 2.137 34.92 2.407 ;
     RECT  40.2 2.137 40.32 2.407 ;
     RECT  45.6 2.137 45.72 2.407 ;
     RECT  50.016 2.339 51.24 2.407 ;
     RECT  61.8 2.137 61.92 2.407 ;
     RECT  66.672 2.245 67.32 2.407 ;
     RECT  72.6 2.137 72.72 2.407 ;
     RECT  78 2.137 78.12 2.407 ;
     RECT  48.864 2.197 48.888 2.485 ;
     RECT  40.2 2.407 40.512 2.533 ;
     RECT  72.6 2.407 72.912 2.533 ;
     RECT  40.2 2.533 40.776 2.675 ;
     RECT  66.672 2.407 67.512 2.819 ;
     RECT  7.8 2.407 8.112 2.821 ;
     RECT  52.848 1.187 59.16 2.915 ;
     RECT  27.888 2.773 28.008 3.107 ;
     RECT  50.016 2.407 51.312 3.301 ;
     RECT  27.984 3.107 28.008 3.317 ;
     RECT  29.4 2.407 29.712 3.317 ;
     RECT  27.984 3.317 29.712 3.371 ;
     RECT  45.6 2.407 45.912 3.397 ;
     RECT  25.536 2.293 25.56 3.443 ;
     RECT  36.192 2.245 36.216 3.443 ;
     RECT  34.8 2.407 35.112 3.551 ;
     RECT  28.512 3.371 29.712 3.635 ;
     RECT  34.176 3.551 35.112 3.635 ;
     RECT  36.24 3.551 37.08 3.635 ;
     RECT  67.2 2.819 67.512 3.829 ;
     RECT  7.68 2.821 8.112 3.875 ;
     RECT  29.28 3.635 29.712 3.883 ;
     RECT  63.216 3.829 63.24 3.913 ;
     RECT  67.2 3.829 67.848 3.913 ;
     RECT  7.8 3.875 8.112 3.925 ;
     RECT  18.6 2.407 18.912 3.925 ;
     RECT  7.8 3.925 8.232 4.011 ;
     RECT  17.664 3.925 18.912 4.011 ;
     RECT  71.808 2.533 72.912 4.019 ;
     RECT  24 2.407 24.312 4.021 ;
     RECT  49.968 3.301 51.312 4.213 ;
     RECT  49.968 4.213 51.432 4.261 ;
     RECT  52.848 2.915 59.112 4.261 ;
     RECT  36.24 3.635 36.264 4.451 ;
     RECT  29.4 3.883 29.712 4.501 ;
     RECT  61.8 2.407 62.112 4.501 ;
     RECT  24 4.021 24.6 4.511 ;
     RECT  23.904 4.511 24.6 4.587 ;
     RECT  47.856 4.501 47.88 4.587 ;
     RECT  23.904 4.587 24.312 4.595 ;
     RECT  49.968 4.261 59.112 4.595 ;
     RECT  49.968 4.595 59.064 4.787 ;
     RECT  18.6 4.011 18.912 4.789 ;
     RECT  45.6 3.397 46.152 4.981 ;
     RECT  11.76 4.933 11.784 5.035 ;
     RECT  44.688 4.981 46.152 5.171 ;
     RECT  40.2 2.675 40.512 5.173 ;
     RECT  72.48 4.019 72.912 5.173 ;
     RECT  18.6 4.789 19.032 5.219 ;
     RECT  29.4 4.501 30.216 5.219 ;
     RECT  55.536 4.787 59.064 5.219 ;
     RECT  40.2 5.173 40.968 5.315 ;
     RECT  44.976 5.171 46.152 5.413 ;
     RECT  40.2 5.315 40.632 5.483 ;
     RECT  38.736 5.423 38.76 5.507 ;
     RECT  67.2 3.913 67.512 5.605 ;
     RECT  13.2 2.407 13.512 5.663 ;
     RECT  48.864 2.485 48.936 5.715 ;
     RECT  49.968 4.787 54.312 5.715 ;
     RECT  13.2 5.663 14.232 5.747 ;
     RECT  63.744 5.125 63.768 5.747 ;
     RECT  48.864 5.715 54.312 5.803 ;
     RECT  48.864 5.803 48.984 5.833 ;
     RECT  75.264 5.749 75.288 5.833 ;
     RECT  24 4.595 24.312 5.893 ;
     RECT  55.728 5.219 59.064 5.907 ;
     RECT  24 5.893 25.176 5.995 ;
     RECT  49.968 5.803 54.312 5.995 ;
     RECT  55.728 5.907 59.16 5.995 ;
     RECT  44.976 5.413 46.824 6.025 ;
     RECT  10.656 5.941 10.68 6.035 ;
     RECT  49.968 5.995 51.432 6.035 ;
     RECT  22.272 5.173 22.296 6.227 ;
     RECT  43.296 6.181 43.32 6.265 ;
     RECT  9.648 5.605 9.672 6.275 ;
     RECT  33.792 5.077 33.816 6.275 ;
     RECT  52.992 5.995 54.312 6.323 ;
     RECT  55.728 5.995 59.064 6.371 ;
     RECT  55.728 6.371 58.824 6.467 ;
     RECT  66.624 5.605 67.512 6.707 ;
     RECT  29.4 5.219 29.712 6.773 ;
     RECT  18.6 5.219 18.912 6.805 ;
     RECT  27.696 6.767 27.72 6.851 ;
     RECT  71.76 5.173 72.912 6.853 ;
     RECT  29.28 6.773 29.712 6.861 ;
     RECT  52.992 6.323 54.12 7.007 ;
     RECT  49.968 6.035 51.312 7.045 ;
     RECT  52.416 7.007 54.12 7.091 ;
     RECT  55.728 6.467 56.808 7.141 ;
     RECT  45.6 6.025 46.824 7.221 ;
     RECT  45.504 7.221 46.824 7.275 ;
     RECT  53.088 7.091 54.12 7.285 ;
     RECT  45.504 7.275 45.912 7.331 ;
     RECT  55.488 7.141 56.808 7.339 ;
     RECT  55.584 7.339 56.712 7.379 ;
     RECT  24 5.995 24.312 7.391 ;
     RECT  24 7.391 24.504 7.475 ;
     RECT  55.728 7.379 56.712 7.571 ;
     RECT  49.968 7.045 51.432 7.573 ;
     RECT  58.224 6.467 58.824 7.621 ;
     RECT  61.632 4.501 62.112 7.717 ;
     RECT  49.968 7.573 51.48 7.763 ;
     RECT  56.304 7.571 56.712 7.763 ;
     RECT  71.76 6.853 73.032 7.775 ;
     RECT  71.712 7.775 73.032 7.859 ;
     RECT  10.416 7.797 10.44 7.885 ;
     RECT  18.24 6.805 18.912 7.907 ;
     RECT  72.48 7.859 73.032 7.907 ;
     RECT  61.392 7.717 62.112 7.955 ;
     RECT  67.2 6.707 67.512 7.957 ;
     RECT  31.344 7.413 31.368 8.003 ;
     RECT  13.2 5.747 13.512 8.005 ;
     RECT  53.088 7.285 54.408 8.051 ;
     RECT  43.872 7.957 43.896 8.099 ;
     RECT  13.104 8.005 13.512 8.195 ;
     RECT  57.984 7.621 58.824 8.293 ;
     RECT  48.864 5.833 48.936 8.437 ;
     RECT  49.968 7.763 51.312 8.437 ;
     RECT  72.6 7.907 73.032 8.675 ;
     RECT  48.864 8.437 51.312 8.747 ;
     RECT  64.944 8.437 64.968 8.747 ;
     RECT  19.968 8.677 19.992 8.761 ;
     RECT  28.32 8.677 28.344 8.761 ;
     RECT  38.784 8.677 38.808 8.761 ;
     RECT  56.4 7.763 56.712 8.787 ;
     RECT  57.696 8.293 58.824 8.787 ;
     RECT  56.4 8.787 58.824 8.875 ;
     RECT  49.968 8.747 51.312 8.917 ;
     RECT  49.968 8.917 51.432 9.013 ;
     RECT  53.088 8.051 54.216 9.205 ;
     RECT  58.032 8.875 58.824 9.205 ;
     RECT  59.952 8.869 59.976 9.205 ;
     RECT  53.088 9.205 54.936 9.299 ;
     RECT  49.968 9.013 51.48 9.301 ;
     RECT  53.088 9.299 54.168 9.347 ;
     RECT  58.032 9.205 59.976 9.347 ;
     RECT  40.2 5.483 40.512 9.397 ;
     RECT  53.088 9.347 53.64 9.397 ;
     RECT  34.8 3.635 35.112 9.541 ;
     RECT  5.664 9.503 5.688 9.587 ;
     RECT  45.6 7.331 45.912 9.637 ;
     RECT  58.032 9.347 58.824 9.731 ;
     RECT  59.952 9.347 59.976 9.731 ;
     RECT  34.608 9.541 35.112 9.747 ;
     RECT  16.224 9.717 16.248 9.805 ;
     RECT  65.136 9.717 65.16 9.827 ;
     RECT  43.392 9.747 43.416 9.835 ;
     RECT  69.504 9.781 69.528 9.865 ;
     RECT  49.968 9.301 51.576 9.925 ;
     RECT  53.04 9.397 53.64 9.925 ;
     RECT  39.888 9.397 40.512 9.971 ;
     RECT  13.2 8.195 13.512 10.069 ;
     RECT  12.624 10.069 13.512 10.155 ;
     RECT  10.8 10.079 10.824 10.163 ;
     RECT  49.968 9.925 53.64 10.283 ;
     RECT  34.608 9.747 35.4 10.293 ;
     RECT  53.088 10.283 53.64 10.355 ;
     RECT  71.376 9.637 71.4 10.355 ;
     RECT  34.608 10.293 35.976 10.381 ;
     RECT  49.968 10.283 51.48 10.451 ;
     RECT  22.752 9.637 22.776 10.595 ;
     RECT  54.72 10.485 54.744 10.595 ;
     RECT  29.4 6.861 29.712 10.707 ;
     RECT  34.608 10.381 35.112 10.787 ;
     RECT  29.28 10.707 29.712 10.795 ;
     RECT  13.2 10.155 13.512 11.317 ;
     RECT  27.744 11.061 27.768 11.371 ;
     RECT  74.784 10.805 74.808 11.411 ;
     RECT  10.848 11.365 10.872 11.449 ;
     RECT  40.08 9.971 40.512 11.459 ;
     RECT  69.984 10.789 70.008 11.459 ;
     RECT  15.024 10.837 15.048 11.507 ;
     RECT  65.568 11.365 65.592 11.573 ;
     RECT  37.2 10.885 37.224 11.699 ;
     RECT  16.656 11.765 16.68 11.859 ;
     RECT  54.96 11.807 54.984 11.859 ;
     RECT  54.72 11.859 54.984 11.891 ;
     RECT  7.8 4.011 8.112 11.893 ;
     RECT  24 7.475 24.312 11.893 ;
     RECT  65.568 11.573 65.832 11.893 ;
     RECT  67.056 7.957 67.512 11.893 ;
     RECT  9.696 11.347 9.72 11.939 ;
     RECT  13.104 11.317 13.512 11.939 ;
     RECT  16.368 11.859 16.68 11.939 ;
     RECT  33.6 9.925 33.624 11.941 ;
     RECT  16.368 11.939 16.392 11.947 ;
     RECT  54.72 11.891 54.744 11.947 ;
     RECT  65.568 11.893 68.424 11.947 ;
     RECT  6.24 11.893 8.112 11.977 ;
     RECT  22.752 11.893 24.552 11.977 ;
     RECT  23.376 11.977 24.552 11.987 ;
     RECT  33.072 11.941 33.624 11.987 ;
     RECT  66 11.947 68.424 11.987 ;
     RECT  71.376 11.797 71.4 12.011 ;
     RECT  70.08 11.951 70.104 12.035 ;
     RECT  6.864 11.977 8.112 12.083 ;
     RECT  66 11.987 66.024 12.083 ;
     RECT  33.072 11.987 33.096 12.085 ;
     RECT  32.448 12.085 33.096 12.179 ;
     RECT  45.6 9.637 46.152 12.275 ;
     RECT  47.136 12.213 47.16 12.301 ;
     RECT  64.08 10.117 64.104 12.517 ;
     RECT  48.864 8.747 48.936 12.527 ;
     RECT  48.384 12.527 48.936 12.611 ;
     RECT  48.864 12.611 48.936 12.661 ;
     RECT  49.968 10.451 51.312 12.661 ;
     RECT  29.4 10.795 29.712 12.691 ;
     RECT  34.8 10.787 35.112 12.725 ;
     RECT  48.864 12.661 51.312 12.755 ;
     RECT  28.464 12.691 29.712 12.779 ;
     RECT  49.968 12.755 51.312 12.805 ;
     RECT  34.8 12.725 35.208 12.901 ;
     RECT  28.752 12.779 29.712 12.971 ;
     RECT  37.152 12.853 37.176 12.995 ;
     RECT  63.216 12.517 64.104 12.997 ;
     RECT  34.8 12.901 35.256 13.109 ;
     RECT  61.632 7.955 62.112 13.109 ;
     RECT  33.072 12.179 33.096 13.139 ;
     RECT  67.056 11.987 67.512 13.141 ;
     RECT  72.6 8.675 72.912 13.151 ;
     RECT  34.8 13.109 35.976 13.197 ;
     RECT  63.216 12.997 64.488 13.227 ;
     RECT  72.384 13.151 73.512 13.235 ;
     RECT  15.984 12.517 16.008 13.237 ;
     RECT  9.504 13.173 9.528 13.283 ;
     RECT  15.456 13.237 16.008 13.283 ;
     RECT  21.504 12.517 21.528 13.331 ;
     RECT  7.8 12.083 8.112 13.333 ;
     RECT  40.2 11.459 40.512 13.333 ;
     RECT  27.696 13.173 27.72 13.523 ;
     RECT  30.816 12.901 30.84 13.619 ;
     RECT  43.344 12.373 43.368 13.715 ;
     RECT  74.688 13.173 74.712 13.715 ;
     RECT  7.8 13.333 8.232 13.859 ;
     RECT  49.968 12.805 51.432 13.859 ;
     RECT  16.56 13.477 16.68 13.909 ;
     RECT  56.4 8.875 56.712 13.909 ;
     RECT  48.864 12.755 48.936 14.005 ;
     RECT  23.376 11.987 24.312 14.035 ;
     RECT  15.456 13.283 15.48 14.099 ;
     RECT  63.216 13.227 64.104 14.099 ;
     RECT  22.704 14.035 24.312 14.123 ;
     RECT  48.48 14.005 48.936 14.123 ;
     RECT  56.4 13.909 57 14.123 ;
     RECT  9.648 14.005 10.344 14.137 ;
     RECT  23.904 14.123 24.312 14.157 ;
     RECT  10.32 14.137 10.344 14.187 ;
     RECT  16.56 13.909 17.304 14.197 ;
     RECT  18.6 7.907 18.912 14.197 ;
     RECT  72.6 13.235 72.912 14.197 ;
     RECT  78 2.407 78.312 14.197 ;
     RECT  16.56 14.197 18.912 14.251 ;
     RECT  78 14.197 78.744 14.255 ;
     RECT  17.28 14.251 18.912 14.281 ;
     RECT  32.448 14.069 32.472 14.281 ;
     RECT  77.472 14.255 78.744 14.339 ;
     RECT  65.616 14.453 65.64 14.635 ;
     RECT  7.8 13.859 8.112 14.739 ;
     RECT  29.4 12.971 29.712 14.773 ;
     RECT  34.8 13.197 35.112 14.773 ;
     RECT  39.936 13.333 40.512 14.773 ;
     RECT  61.008 13.109 62.112 14.821 ;
     RECT  7.68 14.739 8.112 14.827 ;
     RECT  10.848 14.197 10.872 14.915 ;
     RECT  37.248 13.909 37.272 15.071 ;
     RECT  31.872 15.061 31.896 15.147 ;
     RECT  38.832 15.061 38.856 15.147 ;
     RECT  33.648 15.071 33.672 15.155 ;
     RECT  37.248 15.071 37.608 15.155 ;
     RECT  53.088 10.355 53.448 15.157 ;
     RECT  29.4 14.773 30.408 15.203 ;
     RECT  52.464 15.157 53.448 15.241 ;
     RECT  66.816 13.141 67.512 15.299 ;
     RECT  61.008 14.821 63 15.395 ;
     RECT  24 14.157 24.312 15.397 ;
     RECT  17.28 14.281 17.304 15.413 ;
     RECT  72.6 14.197 73.56 15.443 ;
     RECT  16.464 15.413 17.304 15.467 ;
     RECT  23.904 15.397 24.312 15.481 ;
     RECT  64.08 14.099 64.104 15.493 ;
     RECT  67.056 15.299 67.512 15.493 ;
     RECT  16.464 15.467 16.488 15.501 ;
     RECT  39.84 14.773 40.512 15.539 ;
     RECT  55.248 14.773 55.272 15.539 ;
     RECT  39.936 15.539 40.512 15.635 ;
     RECT  43.2 15.637 43.224 15.723 ;
     RECT  48.864 14.123 48.936 15.829 ;
     RECT  7.8 14.827 8.112 15.877 ;
     RECT  29.4 15.203 29.832 15.877 ;
     RECT  9.888 15.829 9.912 15.925 ;
     RECT  7.8 15.877 8.52 15.979 ;
     RECT  9.888 15.925 10.872 15.979 ;
     RECT  22.8 15.301 22.824 16.019 ;
     RECT  28.416 15.877 29.832 16.019 ;
     RECT  64.08 15.493 65.064 16.019 ;
     RECT  14.544 15.349 14.568 16.067 ;
     RECT  52.992 15.241 53.448 16.259 ;
     RECT  31.248 16.181 31.272 16.269 ;
     RECT  32.352 16.181 32.376 16.269 ;
     RECT  13.2 11.939 13.512 16.357 ;
     RECT  34.8 14.773 36.024 16.501 ;
     RECT  34.56 16.501 36.024 16.547 ;
     RECT  34.56 16.547 35.352 16.565 ;
     RECT  28.416 16.019 29.712 16.595 ;
     RECT  28.992 16.595 29.712 16.643 ;
     RECT  34.32 16.565 35.352 16.643 ;
     RECT  61.632 15.395 63 16.643 ;
     RECT  45.6 12.275 45.912 16.693 ;
     RECT  45.6 16.693 46.728 16.777 ;
     RECT  48.192 15.829 48.936 16.789 ;
     RECT  47.904 16.789 48.936 16.875 ;
     RECT  48.864 16.875 48.936 16.991 ;
     RECT  49.968 13.859 51.312 16.991 ;
     RECT  67.056 15.493 67.8 16.991 ;
     RECT  72.6 15.443 72.912 16.991 ;
     RECT  78 14.339 78.744 17.029 ;
     RECT  5.088 16.991 5.112 17.075 ;
     RECT  41.904 15.877 41.928 17.075 ;
     RECT  65.472 16.693 65.496 17.075 ;
     RECT  71.808 16.991 72.912 17.075 ;
     RECT  56.4 14.123 56.712 17.077 ;
     RECT  67.056 16.991 67.848 17.089 ;
     RECT  58.032 9.731 58.056 17.123 ;
     RECT  64.08 16.019 64.104 17.125 ;
     RECT  13.2 16.357 13.848 17.173 ;
     RECT  39.984 15.635 40.512 17.173 ;
     RECT  48.864 16.991 51.312 17.219 ;
     RECT  34.32 16.643 35.112 17.315 ;
     RECT  59.424 16.501 59.448 17.363 ;
     RECT  13.104 17.173 13.848 17.411 ;
     RECT  20.976 17.317 21 17.555 ;
     RECT  37.248 15.155 37.272 17.557 ;
     RECT  10.848 15.979 10.872 17.567 ;
     RECT  13.2 17.411 13.848 17.567 ;
     RECT  78 17.029 78.792 17.567 ;
     RECT  10.272 17.567 10.872 17.605 ;
     RECT  10.272 17.605 10.92 17.651 ;
     RECT  13.2 17.567 14.232 17.651 ;
     RECT  77.52 17.567 78.792 17.651 ;
     RECT  37.056 17.557 37.272 17.699 ;
     RECT  43.248 17.653 43.272 17.747 ;
     RECT  56.4 17.077 56.808 17.899 ;
     RECT  58.128 17.811 58.152 17.899 ;
     RECT  39.888 17.173 40.512 17.903 ;
     RECT  39.36 17.903 40.512 17.987 ;
     RECT  7.8 15.979 8.112 17.989 ;
     RECT  29.04 16.643 29.712 18.037 ;
     RECT  30.816 17.605 30.84 18.037 ;
     RECT  34.8 17.315 35.112 18.165 ;
     RECT  26.208 18.085 26.232 18.169 ;
     RECT  67.056 17.089 67.8 18.181 ;
     RECT  27.36 18.101 27.384 18.189 ;
     RECT  20.544 18.143 20.568 18.227 ;
     RECT  33.024 18.143 33.048 18.227 ;
     RECT  63.216 17.125 64.104 18.227 ;
     RECT  29.04 18.037 30.84 18.275 ;
     RECT  67.056 18.181 68.376 18.357 ;
     RECT  10.896 17.651 10.92 18.419 ;
     RECT  66.864 18.357 68.376 18.445 ;
     RECT  44.448 18.549 44.472 18.613 ;
     RECT  59.28 18.613 59.304 18.697 ;
     RECT  29.04 18.275 29.928 18.803 ;
     RECT  43.872 18.613 44.472 18.851 ;
     RECT  16.464 18.613 16.488 18.947 ;
     RECT  29.04 18.803 29.712 18.995 ;
     RECT  39.888 17.987 40.512 19.093 ;
     RECT  34.8 18.165 35.64 19.235 ;
     RECT  2.4 2.407 2.712 19.333 ;
     RECT  7.344 17.989 8.112 19.379 ;
     RECT  55.296 18.181 55.32 19.379 ;
     RECT  20.112 18.709 20.136 19.427 ;
     RECT  11.424 19.333 11.448 19.487 ;
     RECT  10.8 19.487 11.448 19.563 ;
     RECT  43.872 18.851 43.896 19.563 ;
     RECT  10.8 19.563 10.824 19.571 ;
     RECT  27.408 19.573 27.432 19.667 ;
     RECT  5.616 19.603 5.64 19.691 ;
     RECT  66.096 19.621 66.12 19.705 ;
     RECT  48.864 17.219 48.936 19.717 ;
     RECT  49.968 17.219 51.312 19.717 ;
     RECT  39.888 19.093 40.872 19.765 ;
     RECT  42.72 19.093 42.744 19.947 ;
     RECT  53.088 16.259 53.448 19.957 ;
     RECT  72.6 17.075 72.912 19.957 ;
     RECT  78 17.651 78.792 19.957 ;
     RECT  2.4 19.333 3.096 20.003 ;
     RECT  61.632 16.643 62.112 20.005 ;
     RECT  77.904 19.957 78.792 20.011 ;
     RECT  6.768 19.957 6.792 20.051 ;
     RECT  53.088 19.957 54.12 20.051 ;
     RECT  67.2 18.445 68.376 20.051 ;
     RECT  72.6 19.957 73.656 20.051 ;
     RECT  77.904 20.011 78.312 20.291 ;
     RECT  15.84 20.101 15.864 20.387 ;
     RECT  48.864 19.717 51.312 20.389 ;
     RECT  64.08 18.227 64.104 20.533 ;
     RECT  64.08 20.533 65.016 20.617 ;
     RECT  42.816 20.533 42.84 20.627 ;
     RECT  7.8 19.379 8.112 20.691 ;
     RECT  4.752 20.691 4.776 20.779 ;
     RECT  7.8 20.691 8.52 20.779 ;
     RECT  18.6 14.281 18.912 20.853 ;
     RECT  9.696 20.725 9.72 20.867 ;
     RECT  48.864 20.389 51.432 20.867 ;
     RECT  70.272 19.909 70.296 20.867 ;
     RECT  20.256 20.725 20.28 20.907 ;
     RECT  18.48 20.853 18.912 20.941 ;
     RECT  61.632 20.005 62.904 20.963 ;
     RECT  61.632 20.963 62.112 21.061 ;
     RECT  34.8 19.235 35.112 21.109 ;
     RECT  39.84 19.765 40.872 21.109 ;
     RECT  67.2 20.051 67.992 21.155 ;
     RECT  48.864 20.867 48.936 21.157 ;
     RECT  39.84 21.109 41.016 21.193 ;
     RECT  34.032 21.109 35.112 21.355 ;
     RECT  32.448 21.301 32.472 21.385 ;
     RECT  76.272 20.533 76.296 21.395 ;
     RECT  48.528 21.157 48.936 21.443 ;
     RECT  49.968 20.867 51.432 21.443 ;
     RECT  3.936 21.493 3.96 21.577 ;
     RECT  5.136 21.493 5.16 21.577 ;
     RECT  25.68 18.853 25.704 21.621 ;
     RECT  39.84 21.193 40.512 21.635 ;
     RECT  29.4 18.995 29.712 21.685 ;
     RECT  25.44 21.621 25.704 21.709 ;
     RECT  28.656 21.685 29.712 21.827 ;
     RECT  18.6 20.941 18.912 21.925 ;
     RECT  72.6 20.051 72.912 21.925 ;
     RECT  67.2 21.155 67.8 22.133 ;
     RECT  7.8 20.779 8.112 22.175 ;
     RECT  69.552 22.127 69.576 22.211 ;
     RECT  67.2 22.133 68.376 22.221 ;
     RECT  10.272 22.165 10.296 22.251 ;
     RECT  7.8 22.175 9.096 22.259 ;
     RECT  65.952 22.419 65.976 22.507 ;
     RECT  30.816 22.501 30.84 22.585 ;
     RECT  45.6 16.777 45.912 22.693 ;
     RECT  44.064 22.549 44.088 22.709 ;
     RECT  49.968 21.443 51.312 22.741 ;
     RECT  56.4 17.899 56.712 22.741 ;
     RECT  57.84 20.725 57.864 22.741 ;
     RECT  44.064 22.709 44.424 22.763 ;
     RECT  45.6 22.693 46.008 22.777 ;
     RECT  31.872 22.703 31.896 22.787 ;
     RECT  26.736 22.741 27.24 22.827 ;
     RECT  72.48 21.925 72.912 22.835 ;
     RECT  56.4 22.741 57.864 22.891 ;
     RECT  32.496 22.837 32.52 22.931 ;
     RECT  26.832 22.827 27.24 23.027 ;
     RECT  29.232 21.827 29.712 23.027 ;
     RECT  57.84 22.891 57.864 23.027 ;
     RECT  61.536 21.061 62.112 23.029 ;
     RECT  18.48 21.925 18.912 23.077 ;
     RECT  76.752 22.117 76.776 23.125 ;
     RECT  76.656 23.125 76.776 23.171 ;
     RECT  30.72 22.789 30.744 23.219 ;
     RECT  18.48 23.077 19.32 23.269 ;
     RECT  37.248 17.699 37.272 23.317 ;
     RECT  65.232 23.251 65.256 23.339 ;
     RECT  17.664 23.269 19.32 23.353 ;
     RECT  16.56 22.741 16.584 23.363 ;
     RECT  67.2 22.221 67.608 23.411 ;
     RECT  44.4 22.763 44.424 23.555 ;
     RECT  76.656 23.171 76.68 23.653 ;
     RECT  49.968 22.741 51.96 23.843 ;
     RECT  75.792 23.653 76.68 23.987 ;
     RECT  34.8 21.355 35.112 23.989 ;
     RECT  37.248 23.317 38.232 23.989 ;
     RECT  45.6 22.777 45.912 23.989 ;
     RECT  34.8 23.989 35.64 24.083 ;
     RECT  37.248 23.989 38.808 24.083 ;
     RECT  45.6 23.989 46.296 24.083 ;
     RECT  74.352 23.989 74.376 24.083 ;
     RECT  10.416 23.941 10.44 24.131 ;
     RECT  29.4 23.027 29.712 24.133 ;
     RECT  5.28 23.989 5.304 24.323 ;
     RECT  39.936 21.635 40.512 24.325 ;
     RECT  48.864 21.443 48.936 24.469 ;
     RECT  49.968 23.843 51.312 24.469 ;
     RECT  72.6 22.835 72.912 24.469 ;
     RECT  22.944 24.469 22.968 24.517 ;
     RECT  25.68 21.709 25.704 24.613 ;
     RECT  67.2 23.411 67.512 24.613 ;
     RECT  25.68 24.613 26.136 24.659 ;
     RECT  28.752 24.133 29.712 24.805 ;
     RECT  9.168 23.989 9.192 24.851 ;
     RECT  37.248 24.083 38.232 24.899 ;
     RECT  22.8 24.517 22.968 24.939 ;
     RECT  28.512 24.805 29.712 24.939 ;
     RECT  56.4 22.891 56.712 24.949 ;
     RECT  39.936 24.325 41.016 25.013 ;
     RECT  42.864 25.007 42.888 25.091 ;
     RECT  48.864 24.469 51.312 25.091 ;
     RECT  59.712 25.007 59.736 25.091 ;
     RECT  55.824 24.949 56.712 25.131 ;
     RECT  39.936 25.013 41.592 25.139 ;
     RECT  45.6 24.083 46.056 25.139 ;
     RECT  66.672 24.613 67.512 25.139 ;
     RECT  72.6 24.469 73.56 25.139 ;
     RECT  54.672 25.077 54.696 25.165 ;
     RECT  34.8 24.083 35.112 25.285 ;
     RECT  26.112 24.659 26.136 25.427 ;
     RECT  53.088 20.051 53.448 25.573 ;
     RECT  18.6 23.353 19.32 25.621 ;
     RECT  45.6 25.139 45.912 25.621 ;
     RECT  9.744 25.525 9.912 25.643 ;
     RECT  52.992 25.573 53.448 25.657 ;
     RECT  7.8 22.259 8.112 25.669 ;
     RECT  48.864 25.091 48.936 25.715 ;
     RECT  11.184 25.683 11.208 25.771 ;
     RECT  6.912 25.669 8.112 25.811 ;
     RECT  31.344 25.045 31.368 25.859 ;
     RECT  67.2 25.139 67.512 25.957 ;
     RECT  22.944 24.939 22.968 26.003 ;
     RECT  67.2 25.957 68.424 26.041 ;
     RECT  7.8 25.811 8.112 26.207 ;
     RECT  9.744 25.643 9.768 26.207 ;
     RECT  34.8 25.285 36.024 26.243 ;
     RECT  49.968 25.091 51.312 26.243 ;
     RECT  59.28 25.621 59.304 26.243 ;
     RECT  7.8 26.207 9.768 26.283 ;
     RECT  7.8 26.283 9.096 26.291 ;
     RECT  27.312 26.207 27.336 26.291 ;
     RECT  39.936 25.139 41.16 26.291 ;
     RECT  28.752 24.939 29.712 26.317 ;
     RECT  78 20.291 78.312 26.485 ;
     RECT  44.976 25.621 45.912 26.531 ;
     RECT  77.52 26.485 78.312 26.579 ;
     RECT  43.92 26.485 43.944 26.581 ;
     RECT  48.912 25.715 48.936 26.629 ;
     RECT  61.008 23.029 62.112 26.643 ;
     RECT  60.672 26.643 62.112 26.707 ;
     RECT  48.912 26.629 49.08 26.725 ;
     RECT  72.6 25.139 72.912 26.725 ;
     RECT  60.672 26.707 62.328 26.731 ;
     RECT  53.088 25.657 53.448 26.773 ;
     RECT  61.632 26.731 62.328 26.795 ;
     RECT  71.808 26.725 72.912 26.809 ;
     RECT  48.864 26.725 49.08 26.915 ;
     RECT  43.728 26.581 43.944 26.963 ;
     RECT  48.864 26.915 48.936 26.987 ;
     RECT  38.736 26.197 38.76 27.059 ;
     RECT  42.72 27.061 42.744 27.145 ;
     RECT  5.04 26.725 5.064 27.251 ;
     RECT  50.064 26.243 51.312 27.253 ;
     RECT  24 15.481 24.312 27.283 ;
     RECT  53.04 26.773 53.448 27.299 ;
     RECT  32.688 27.205 32.712 27.307 ;
     RECT  50.064 27.253 51.432 27.337 ;
     RECT  23.52 27.283 24.312 27.371 ;
     RECT  18.6 25.621 19.992 27.385 ;
     RECT  22.176 27.301 22.2 27.385 ;
     RECT  13.2 17.651 13.512 27.493 ;
     RECT  7.8 26.291 8.112 27.685 ;
     RECT  64.08 20.617 64.104 27.733 ;
     RECT  56.4 25.131 56.712 27.877 ;
     RECT  78 26.579 78.312 27.877 ;
     RECT  6.24 26.629 6.264 27.923 ;
     RECT  45.6 26.531 45.912 27.935 ;
     RECT  64.08 27.733 64.44 27.957 ;
     RECT  9.648 27.301 9.672 27.971 ;
     RECT  45.6 27.935 46.008 28.019 ;
     RECT  34.8 26.243 35.112 28.021 ;
     RECT  18.6 27.385 19.8 28.115 ;
     RECT  63.552 27.957 64.44 28.163 ;
     RECT  13.008 27.493 13.512 28.213 ;
     RECT  67.2 26.041 67.512 28.213 ;
     RECT  38.928 28.213 38.952 28.309 ;
     RECT  39.936 26.291 40.512 28.309 ;
     RECT  48.912 26.987 48.936 28.309 ;
     RECT  50.064 27.337 51.312 28.309 ;
     RECT  26.784 28.117 26.808 28.403 ;
     RECT  38.928 28.309 40.512 28.403 ;
     RECT  61.632 26.795 62.112 28.405 ;
     RECT  65.568 27.205 65.592 28.405 ;
     RECT  33.072 28.213 33.096 28.451 ;
     RECT  12.24 28.213 13.512 28.453 ;
     RECT  61.632 28.405 62.232 28.489 ;
     RECT  56.4 27.877 57.048 28.499 ;
     RECT  74.88 27.301 74.904 28.499 ;
     RECT  68.976 28.357 69 28.595 ;
     RECT  72.6 26.809 72.912 28.627 ;
     RECT  58.608 28.533 58.632 28.643 ;
     RECT  65.568 28.405 66.168 28.643 ;
     RECT  72.6 28.627 73.848 28.715 ;
     RECT  70.8 27.925 70.824 28.739 ;
     RECT  64.08 28.163 64.44 28.789 ;
     RECT  65.568 28.643 65.592 28.789 ;
     RECT  48.912 28.309 51.312 28.895 ;
     RECT  9.936 28.853 9.96 28.941 ;
     RECT  48.432 28.895 51.312 28.941 ;
     RECT  48.432 28.941 49.032 28.979 ;
     RECT  34.8 28.021 35.256 28.981 ;
     RECT  37.248 24.899 37.272 28.981 ;
     RECT  7.8 27.685 8.232 29.029 ;
     RECT  9.504 28.947 9.528 29.029 ;
     RECT  4.512 28.947 4.536 29.035 ;
     RECT  7.8 29.029 9.528 29.035 ;
     RECT  37.056 28.981 37.272 29.065 ;
     RECT  7.8 29.035 9.144 29.075 ;
     RECT  39.168 28.403 40.512 29.075 ;
     RECT  64.08 28.789 65.592 29.075 ;
     RECT  18.6 28.115 19.32 29.077 ;
     RECT  64.08 29.075 65.016 29.092 ;
     RECT  12 28.453 13.512 29.219 ;
     RECT  16.128 29.109 16.152 29.219 ;
     RECT  53.424 27.299 53.448 29.317 ;
     RECT  48.912 28.979 49.032 29.449 ;
     RECT  34.8 28.981 35.544 29.605 ;
     RECT  43.728 26.963 43.752 29.605 ;
     RECT  53.424 29.317 53.544 29.605 ;
     RECT  27.312 28.405 27.336 29.651 ;
     RECT  77.904 27.877 78.312 29.651 ;
     RECT  9.12 29.075 9.144 30.035 ;
     RECT  42.768 29.605 43.752 30.085 ;
     RECT  34.176 29.605 35.544 30.179 ;
     RECT  12 29.219 12.024 30.181 ;
     RECT  13.2 29.219 13.512 30.181 ;
     RECT  17.952 29.077 19.32 30.181 ;
     RECT  45.6 28.019 45.912 30.181 ;
     RECT  42.768 30.085 44.472 30.275 ;
     RECT  55.104 30.325 55.128 30.419 ;
     RECT  48.912 29.449 48.936 30.453 ;
     RECT  56.4 28.499 56.712 30.483 ;
     RECT  15.744 30.453 15.768 30.563 ;
     RECT  17.952 30.181 19.992 30.611 ;
     RECT  48.192 30.453 48.936 30.613 ;
     RECT  12 30.181 13.512 30.659 ;
     RECT  64.08 29.092 64.104 30.661 ;
     RECT  56.256 30.483 56.712 30.709 ;
     RECT  28.32 30.645 28.344 30.733 ;
     RECT  72.6 28.715 72.912 30.743 ;
     RECT  45.6 30.181 46.008 30.755 ;
     RECT  7.8 29.075 8.112 30.757 ;
     RECT  43.728 30.275 44.472 30.757 ;
     RECT  48.192 30.613 49.128 30.757 ;
     RECT  50.304 28.941 51.312 30.757 ;
     RECT  48.192 30.757 51.312 30.763 ;
     RECT  24 27.371 24.312 30.767 ;
     RECT  56.256 30.709 56.856 30.767 ;
     RECT  61.632 28.489 62.112 30.773 ;
     RECT  63.168 30.661 64.104 30.773 ;
     RECT  39.888 29.075 40.512 30.803 ;
     RECT  53.424 29.605 53.832 30.803 ;
     RECT  55.824 30.767 56.856 30.827 ;
     RECT  61.632 30.773 64.344 30.841 ;
     RECT  18.6 30.611 19.992 30.851 ;
     RECT  24 30.767 24.504 30.851 ;
     RECT  55.824 30.827 56.712 30.851 ;
     RECT  12.48 30.659 13.512 30.947 ;
     RECT  9.456 30.853 9.576 30.955 ;
     RECT  72.6 30.743 73.848 30.997 ;
     RECT  72.48 30.997 73.848 31.019 ;
     RECT  15.84 30.709 16.008 31.029 ;
     RECT  25.68 30.901 25.704 31.029 ;
     RECT  67.2 28.213 67.944 31.029 ;
     RECT  66.72 31.029 67.944 31.059 ;
     RECT  25.68 31.029 25.992 31.083 ;
     RECT  34.32 30.179 35.544 31.083 ;
     RECT  9.456 30.955 9.48 31.091 ;
     RECT  15.84 31.029 16.584 31.117 ;
     RECT  66.144 31.059 67.944 31.117 ;
     RECT  15.84 31.117 16.008 31.147 ;
     RECT  72.48 31.019 72.912 31.147 ;
     RECT  67.2 31.117 67.944 31.331 ;
     RECT  25.968 31.083 25.992 31.379 ;
     RECT  78 29.651 78.312 31.443 ;
     RECT  77.328 31.443 78.312 31.477 ;
     RECT  13.2 30.947 13.512 31.525 ;
     RECT  14.496 30.901 14.52 31.525 ;
     RECT  77.328 31.477 78.696 31.561 ;
     RECT  26.784 31.507 26.808 31.595 ;
     RECT  15.984 31.147 16.008 31.619 ;
     RECT  53.424 30.803 53.448 31.715 ;
     RECT  75.6 31.635 75.624 31.723 ;
     RECT  77.328 31.561 78.312 31.723 ;
     RECT  56.4 30.851 56.712 31.813 ;
     RECT  61.632 30.841 62.664 31.813 ;
     RECT  64.08 30.841 64.344 31.859 ;
     RECT  43.728 30.757 44.52 31.861 ;
     RECT  45.6 30.755 45.912 31.861 ;
     RECT  66.144 31.117 66.168 31.861 ;
     RECT  48.912 30.763 51.312 31.891 ;
     RECT  13.2 31.525 14.52 31.909 ;
     RECT  43.728 31.861 45.912 31.909 ;
     RECT  34.8 31.083 35.544 31.915 ;
     RECT  55.728 31.813 56.712 31.915 ;
     RECT  65.28 31.861 66.168 31.915 ;
     RECT  43.44 31.909 45.912 31.945 ;
     RECT  13.2 31.909 14.856 31.979 ;
     RECT  48.912 31.891 51.528 31.979 ;
     RECT  14.832 31.979 14.856 31.993 ;
     RECT  7.8 30.757 8.232 32.101 ;
     RECT  42.144 31.861 42.168 32.117 ;
     RECT  43.44 31.945 44.616 32.117 ;
     RECT  42.144 32.117 44.616 32.171 ;
     RECT  28.176 30.757 28.2 32.293 ;
     RECT  18.6 30.851 19.32 32.341 ;
     RECT  29.4 26.317 29.712 32.341 ;
     RECT  45.6 31.945 45.912 32.341 ;
     RECT  27.84 32.293 28.2 32.373 ;
     RECT  29.4 32.341 30.264 32.373 ;
     RECT  7.8 32.101 8.28 32.387 ;
     RECT  27.84 32.373 30.264 32.427 ;
     RECT  41.52 32.341 41.544 32.427 ;
     RECT  47.376 32.197 47.4 32.491 ;
     RECT  48.912 31.979 51.312 32.491 ;
     RECT  65.28 31.915 65.304 32.491 ;
     RECT  48.912 32.491 49.272 32.723 ;
     RECT  56.112 31.915 56.712 32.875 ;
     RECT  54.624 32.821 54.648 32.905 ;
     RECT  34.8 31.915 35.304 32.917 ;
     RECT  67.2 31.331 67.512 32.949 ;
     RECT  43.008 32.171 44.616 32.963 ;
     RECT  45.6 32.341 46.056 32.963 ;
     RECT  34.8 32.917 35.544 33.003 ;
     RECT  68.496 31.765 68.52 33.003 ;
     RECT  7.8 32.387 8.232 33.011 ;
     RECT  61.632 31.813 63 33.013 ;
     RECT  67.008 32.949 67.512 33.037 ;
     RECT  18.6 32.341 20.04 33.059 ;
     RECT  10.8 32.979 10.824 33.067 ;
     RECT  32.4 32.979 32.424 33.067 ;
     RECT  61.584 33.013 63 33.067 ;
     RECT  12.096 32.053 12.12 33.119 ;
     RECT  56.4 32.875 56.712 33.141 ;
     RECT  12 33.119 12.12 33.155 ;
     RECT  12 33.155 12.024 33.203 ;
     RECT  28.8 32.427 29.712 33.251 ;
     RECT  33.072 33.109 33.384 33.251 ;
     RECT  56.4 33.141 57.432 33.251 ;
     RECT  22.608 33.061 22.632 33.333 ;
     RECT  24 30.851 24.408 33.333 ;
     RECT  43.728 32.963 44.616 33.347 ;
     RECT  55.008 32.965 55.032 33.395 ;
     RECT  22.608 33.333 24.408 33.421 ;
     RECT  33.216 33.251 33.384 33.491 ;
     RECT  70.704 32.965 70.728 33.491 ;
     RECT  24 33.421 24.408 33.587 ;
     RECT  6.768 32.437 6.792 33.635 ;
     RECT  48.912 32.723 48.936 33.683 ;
     RECT  31.344 33.653 31.368 33.779 ;
     RECT  64.08 31.859 64.104 33.811 ;
     RECT  22.608 33.421 22.632 33.827 ;
     RECT  72.6 31.147 72.912 33.829 ;
     RECT  4.608 33.747 4.632 33.835 ;
     RECT  64.08 33.811 64.728 33.899 ;
     RECT  61.584 33.067 62.664 33.923 ;
     RECT  52.848 33.909 52.872 33.997 ;
     RECT  18.6 33.059 19.32 34.003 ;
     RECT  67.2 33.037 67.512 34.069 ;
     RECT  18.384 34.003 19.32 34.091 ;
     RECT  33.216 33.491 33.24 34.115 ;
     RECT  61.584 33.923 62.232 34.163 ;
     RECT  71.808 33.829 72.912 34.165 ;
     RECT  70.656 33.637 70.68 34.219 ;
     RECT  48.192 33.925 48.216 34.223 ;
     RECT  47.28 34.223 48.216 34.283 ;
     RECT  47.28 34.283 47.304 34.307 ;
     RECT  26.496 34.293 26.52 34.309 ;
     RECT  71.664 34.165 72.912 34.355 ;
     RECT  26.208 34.309 26.52 34.381 ;
     RECT  26.208 34.381 26.232 34.411 ;
     RECT  45.6 32.963 45.912 34.453 ;
     RECT  50.304 32.491 51.312 34.485 ;
     RECT  2.4 20.003 2.712 34.501 ;
     RECT  37.248 29.065 37.272 34.501 ;
     RECT  37.248 34.501 37.416 34.677 ;
     RECT  71.808 34.355 72.912 34.681 ;
     RECT  36.336 34.677 37.416 34.731 ;
     RECT  2.4 34.501 2.856 34.741 ;
     RECT  78 31.723 78.312 34.741 ;
     RECT  64.08 33.899 64.632 34.787 ;
     RECT  29.4 33.251 29.712 34.789 ;
     RECT  77.376 34.741 78.312 34.789 ;
     RECT  75.456 34.613 75.48 34.795 ;
     RECT  77.376 34.789 78.696 34.873 ;
     RECT  28.464 34.789 29.712 34.931 ;
     RECT  36.336 34.731 37.272 34.931 ;
     RECT  18.6 34.091 19.32 34.979 ;
     RECT  56.4 33.251 56.712 35.077 ;
     RECT  55.104 34.357 55.128 35.267 ;
     RECT  0.048 34.741 0.072 35.269 ;
     RECT  50.304 34.485 51.432 35.269 ;
     RECT  0.048 35.269 0.168 35.317 ;
     RECT  45.6 34.453 46.008 35.363 ;
     RECT  77.376 34.873 78.312 35.411 ;
     RECT  24 33.587 24.312 35.605 ;
     RECT  42.192 34.037 42.216 35.653 ;
     RECT  23.28 35.605 24.312 35.755 ;
     RECT  32.448 35.605 32.472 35.755 ;
     RECT  42.144 35.653 42.216 35.755 ;
     RECT  37.008 34.931 37.272 35.785 ;
     RECT  58.656 35.317 58.68 35.829 ;
     RECT  58.656 35.829 58.776 35.883 ;
     RECT  4.464 34.117 4.488 35.891 ;
     RECT  64.08 34.787 64.104 35.893 ;
     RECT  48.432 35.701 48.456 35.939 ;
     RECT  58.704 35.883 58.776 35.939 ;
     RECT  64.08 35.893 65.016 35.987 ;
     RECT  42.192 35.755 42.216 36.131 ;
     RECT  50.304 35.269 51.672 36.133 ;
     RECT  38.784 35.667 38.808 36.275 ;
     RECT  2.4 34.741 3.432 36.373 ;
     RECT  72.6 34.681 72.912 36.373 ;
     RECT  2.4 36.373 3.912 36.419 ;
     RECT  39.936 30.803 40.512 36.421 ;
     RECT  66.96 34.069 67.512 36.469 ;
     RECT  58.704 35.939 58.728 36.553 ;
     RECT  66.96 36.469 68.424 36.553 ;
     RECT  45.6 35.363 45.912 36.853 ;
     RECT  48.912 36.469 48.936 36.949 ;
     RECT  50.304 36.133 51.96 36.959 ;
     RECT  48.912 36.949 49.032 36.995 ;
     RECT  7.8 33.011 8.112 36.997 ;
     RECT  13.2 31.979 13.512 36.997 ;
     RECT  50.304 36.959 52.44 37.043 ;
     RECT  66.96 36.553 67.512 37.043 ;
     RECT  37.248 35.785 37.272 37.045 ;
     RECT  49.008 36.995 49.032 37.045 ;
     RECT  56.4 35.077 57.048 37.091 ;
     RECT  71.808 36.373 72.912 37.099 ;
     RECT  70.704 37.045 70.728 37.129 ;
     RECT  18.6 34.979 19.08 37.139 ;
     RECT  49.008 37.045 49.128 37.187 ;
     RECT  34.8 33.003 35.304 37.235 ;
     RECT  7.44 36.997 8.112 37.285 ;
     RECT  6.816 37.285 8.112 37.369 ;
     RECT  37.248 37.045 37.32 37.379 ;
     RECT  2.4 36.419 2.856 37.381 ;
     RECT  3.888 36.419 3.912 37.381 ;
     RECT  39.36 36.421 40.512 37.475 ;
     RECT  39.984 37.475 40.512 37.619 ;
     RECT  13.2 36.997 13.656 37.667 ;
     RECT  50.304 37.043 51.96 38.005 ;
     RECT  78 35.411 78.312 38.101 ;
     RECT  77.52 38.101 78.312 38.187 ;
     RECT  2.4 37.381 3.912 38.195 ;
     RECT  12.096 37.333 12.12 38.195 ;
     RECT  34.8 37.235 35.112 38.197 ;
     RECT  58.896 38.149 58.92 38.197 ;
     RECT  64.08 35.987 64.104 38.197 ;
     RECT  31.872 38.133 31.896 38.221 ;
     RECT  50.304 38.005 52.008 38.251 ;
     RECT  58.128 38.197 58.92 38.251 ;
     RECT  34.8 38.197 35.352 38.291 ;
     RECT  58.128 38.251 58.152 38.291 ;
     RECT  64.08 38.197 64.968 38.291 ;
     RECT  32.928 37.477 32.952 38.435 ;
     RECT  18.6 37.139 18.912 38.485 ;
     RECT  7.8 37.369 8.112 38.517 ;
     RECT  7.68 38.517 8.112 38.605 ;
     RECT  14.784 38.629 14.808 38.677 ;
     RECT  61.584 34.163 62.112 38.677 ;
     RECT  67.2 37.043 67.512 38.677 ;
     RECT  0.048 35.317 0.552 38.699 ;
     RECT  18.6 38.485 19.08 38.699 ;
     RECT  14.784 38.677 15.384 38.713 ;
     RECT  43.728 33.347 43.752 38.739 ;
     RECT  67.2 38.677 68.424 38.763 ;
     RECT  15.36 38.713 15.384 38.819 ;
     RECT  43.728 38.739 44.376 38.827 ;
     RECT  27.36 38.773 27.384 38.857 ;
     RECT  54.96 38.773 54.984 38.867 ;
     RECT  72.6 37.099 72.912 38.869 ;
     RECT  22.8 38.773 22.824 38.915 ;
     RECT  72.6 38.869 73.512 38.955 ;
     RECT  74.688 38.901 74.712 38.989 ;
     RECT  0.048 38.699 0.504 39.107 ;
     RECT  7.8 38.605 8.112 39.205 ;
     RECT  29.4 34.931 29.712 39.205 ;
     RECT  13.2 37.667 13.512 39.253 ;
     RECT  40.032 37.619 40.512 39.253 ;
     RECT  4.512 39.109 4.536 39.275 ;
     RECT  7.8 39.205 8.568 39.289 ;
     RECT  29.4 39.205 29.832 39.289 ;
     RECT  18.6 38.699 18.912 39.301 ;
     RECT  24 35.755 24.312 39.349 ;
     RECT  61.296 38.677 62.112 39.443 ;
     RECT  0.096 39.107 0.504 39.467 ;
     RECT  2.4 38.195 3 39.541 ;
     RECT  2.304 39.541 3 39.635 ;
     RECT  72.6 38.955 72.912 39.637 ;
     RECT  24 39.349 24.792 39.685 ;
     RECT  47.856 39.637 47.88 39.723 ;
     RECT  26.256 38.677 26.28 39.731 ;
     RECT  18.384 39.301 18.912 39.779 ;
     RECT  67.2 38.763 68.376 39.779 ;
     RECT  34.8 38.291 35.112 39.781 ;
     RECT  45.6 36.853 46.104 39.829 ;
     RECT  39.888 39.253 40.512 39.861 ;
     RECT  45.6 39.829 46.152 39.915 ;
     RECT  50.304 38.251 51.312 39.923 ;
     RECT  69.744 39.061 69.768 39.923 ;
     RECT  43.728 38.827 43.752 39.925 ;
     RECT  72.144 39.637 72.912 39.925 ;
     RECT  39.12 39.861 40.512 39.949 ;
     RECT  39.888 39.949 40.512 39.955 ;
     RECT  39.888 39.955 41.064 39.983 ;
     RECT  49.056 39.669 49.08 40.019 ;
     RECT  72.144 39.925 73.512 40.019 ;
     RECT  2.4 39.635 3 40.115 ;
     RECT  52.752 39.973 52.776 40.115 ;
     RECT  34.8 39.781 35.352 40.181 ;
     RECT  17.136 39.061 17.16 40.259 ;
     RECT  34.368 40.181 35.352 40.307 ;
     RECT  72.144 40.019 72.912 40.451 ;
     RECT  37.248 37.379 37.272 40.499 ;
     RECT  75.168 39.877 75.192 40.595 ;
     RECT  43.488 39.925 43.752 40.597 ;
     RECT  33.024 39.829 33.048 40.691 ;
     RECT  39.888 39.983 41.16 40.741 ;
     RECT  39.888 40.741 41.208 40.789 ;
     RECT  42.672 40.597 43.752 40.789 ;
     RECT  24 39.685 24.984 40.835 ;
     RECT  34.8 40.307 35.352 40.835 ;
     RECT  0.096 39.467 0.36 41.003 ;
     RECT  39.888 40.789 43.752 41.029 ;
     RECT  39.888 41.029 44.472 41.075 ;
     RECT  2.4 40.115 2.904 41.077 ;
     RECT  39.888 41.075 42.744 41.171 ;
     RECT  56.4 37.091 56.712 41.205 ;
     RECT  7.8 39.289 8.112 41.221 ;
     RECT  55.584 41.205 56.712 41.293 ;
     RECT  7.8 41.221 9.096 41.333 ;
     RECT  39.888 41.171 42.696 41.459 ;
     RECT  45.6 39.915 46.104 41.459 ;
     RECT  24 40.835 24.792 41.507 ;
     RECT  13.008 39.253 13.512 41.605 ;
     RECT  43.728 41.075 44.472 41.699 ;
     RECT  56.4 41.293 56.712 41.749 ;
     RECT  33.072 41.683 33.096 41.771 ;
     RECT  36.72 41.701 36.744 41.785 ;
     RECT  18.6 39.779 18.912 41.811 ;
     RECT  12.048 41.605 13.512 41.843 ;
     RECT  18.48 41.811 18.912 41.845 ;
     RECT  12.912 41.843 13.512 41.891 ;
     RECT  7.8 41.333 9.144 41.939 ;
     RECT  17.376 41.701 17.4 41.939 ;
     RECT  18.48 41.845 19.176 41.939 ;
     RECT  2.304 41.077 2.904 41.941 ;
     RECT  50.448 39.923 51.312 41.941 ;
     RECT  0.096 41.003 0.168 41.989 ;
     RECT  39.888 41.459 42.168 42.003 ;
     RECT  69.456 41.749 69.48 42.037 ;
     RECT  50.448 41.941 51.528 42.083 ;
     RECT  16.656 41.989 16.68 42.091 ;
     RECT  39.792 42.003 42.168 42.091 ;
     RECT  72.6 40.451 72.912 42.101 ;
     RECT  39.888 42.091 42.168 42.121 ;
     RECT  72.48 42.101 72.912 42.189 ;
     RECT  69.456 42.037 70.152 42.227 ;
     RECT  75.072 41.269 75.096 42.227 ;
     RECT  0.048 41.989 0.168 42.229 ;
     RECT  29.4 39.289 29.712 42.229 ;
     RECT  13.104 41.891 13.512 42.275 ;
     RECT  43.728 41.699 43.896 42.277 ;
     RECT  43.584 42.277 43.896 42.361 ;
     RECT  34.8 40.835 35.112 42.373 ;
     RECT  43.728 42.361 43.896 42.419 ;
     RECT  22.464 41.125 22.488 42.565 ;
     RECT  29.088 42.229 29.712 42.611 ;
     RECT  39.888 42.121 41.4 42.659 ;
     RECT  18.48 41.939 18.912 42.661 ;
     RECT  34.8 42.373 35.208 42.661 ;
     RECT  75.504 42.579 75.528 42.667 ;
     RECT  21.84 42.565 22.488 42.707 ;
     RECT  39.888 42.659 40.92 42.707 ;
     RECT  38.784 42.643 38.808 42.731 ;
     RECT  31.872 42.661 31.896 42.745 ;
     RECT  34.8 42.661 35.832 42.745 ;
     RECT  21.84 42.707 21.864 42.755 ;
     RECT  25.44 42.565 25.464 42.755 ;
     RECT  39.888 42.707 40.512 42.755 ;
     RECT  47.376 41.941 47.4 42.803 ;
     RECT  76.896 42.741 76.92 42.829 ;
     RECT  20.688 42.933 20.712 42.949 ;
     RECT  18.288 42.661 18.912 42.984 ;
     RECT  59.424 42.133 59.448 42.995 ;
     RECT  20.544 42.949 20.712 43.021 ;
     RECT  45.6 41.459 46.008 43.045 ;
     RECT  20.544 43.021 20.568 43.051 ;
     RECT  17.664 42.984 18.912 43.179 ;
     RECT  9.648 43.103 9.672 43.187 ;
     RECT  7.8 41.939 8.232 43.219 ;
     RECT  47.664 43.125 47.688 43.235 ;
     RECT  64.08 38.291 64.104 43.237 ;
     RECT  69.456 42.227 69.48 43.283 ;
     RECT  13.2 42.275 13.512 43.285 ;
     RECT  7.8 43.219 8.52 43.307 ;
     RECT  63.888 43.237 64.104 43.321 ;
     RECT  49.056 43.045 49.08 43.477 ;
     RECT  52.848 42.757 52.872 43.509 ;
     RECT  58.128 43.487 58.152 43.571 ;
     RECT  43.728 42.419 43.752 43.573 ;
     RECT  32.64 43.509 32.664 43.597 ;
     RECT  52.848 43.509 53.544 43.597 ;
     RECT  74.784 43.539 74.808 43.627 ;
     RECT  43.728 43.573 43.896 43.657 ;
     RECT  28.08 43.189 28.104 43.667 ;
     RECT  24 41.507 24.312 43.717 ;
     RECT  34.8 42.745 35.112 43.717 ;
     RECT  49.056 43.477 49.368 43.717 ;
     RECT  4.608 43.701 4.632 43.789 ;
     RECT  24 43.717 24.696 43.819 ;
     RECT  49.008 43.717 49.368 43.859 ;
     RECT  40.032 42.755 40.512 43.871 ;
     RECT  18.48 43.179 18.912 43.883 ;
     RECT  0.048 42.229 0.552 43.907 ;
     RECT  39.888 43.871 40.512 43.955 ;
     RECT  29.4 42.611 29.712 44.063 ;
     RECT  2.304 41.941 3.096 44.099 ;
     RECT  38.16 43.893 38.184 44.099 ;
     RECT  56.4 41.749 57 44.147 ;
     RECT  33.984 43.717 35.112 44.339 ;
     RECT  72.6 42.189 72.912 44.341 ;
     RECT  29.088 44.063 29.712 44.389 ;
     RECT  49.344 43.859 49.368 44.435 ;
     RECT  7.8 43.307 8.112 44.437 ;
     RECT  24 43.819 24.312 44.437 ;
     RECT  45.6 43.045 46.2 44.437 ;
     RECT  13.2 43.285 14.328 44.483 ;
     RECT  52.848 43.597 52.872 44.483 ;
     RECT  76.8 44.469 76.824 44.579 ;
     RECT  67.2 39.779 67.512 44.581 ;
     RECT  29.088 44.389 29.832 44.661 ;
     RECT  13.2 44.483 14.232 44.665 ;
     RECT  67.2 44.581 67.848 44.665 ;
     RECT  27.36 44.629 27.384 44.715 ;
     RECT  28.656 44.661 29.832 44.819 ;
     RECT  74.688 44.831 74.712 44.853 ;
     RECT  74.112 44.853 74.712 44.915 ;
     RECT  64.08 43.321 64.104 44.965 ;
     RECT  23.904 44.437 24.312 45.059 ;
     RECT  74.112 44.915 74.136 45.059 ;
     RECT  56.4 44.147 56.712 45.109 ;
     RECT  56.112 45.109 56.712 45.251 ;
     RECT  7.8 44.437 8.952 45.299 ;
     RECT  78 38.187 78.312 45.493 ;
     RECT  2.4 44.099 3.096 45.541 ;
     RECT  45.6 44.437 46.776 45.541 ;
     RECT  40.032 43.955 40.512 45.551 ;
     RECT  45.504 45.541 46.776 45.625 ;
     RECT  39.36 45.551 40.512 45.635 ;
     RECT  77.52 45.493 78.312 45.635 ;
     RECT  45.6 45.625 46.776 45.683 ;
     RECT  63.792 44.965 64.104 46.019 ;
     RECT  61.584 39.443 62.112 46.213 ;
     RECT  52.56 45.733 52.584 46.357 ;
     RECT  18.6 43.883 18.912 46.405 ;
     RECT  28.656 44.819 29.712 46.453 ;
     RECT  67.2 44.665 67.512 46.501 ;
     RECT  11.328 46.309 11.352 46.571 ;
     RECT  78 45.635 78.312 46.597 ;
     RECT  52.56 46.357 52.872 46.645 ;
     RECT  61.248 46.213 62.112 46.691 ;
     RECT  52.56 46.645 53.016 46.787 ;
     RECT  71.232 46.751 71.256 46.835 ;
     RECT  52.56 46.787 52.872 46.931 ;
     RECT  18.6 46.405 19.704 47.059 ;
     RECT  2.4 45.541 3.432 47.075 ;
     RECT  4.56 46.069 4.584 47.075 ;
     RECT  18.6 47.059 19.752 47.147 ;
     RECT  28.56 46.453 29.712 47.173 ;
     RECT  28.56 47.173 29.976 47.187 ;
     RECT  52.56 46.931 52.584 47.219 ;
     RECT  61.68 46.691 62.112 47.221 ;
     RECT  2.4 47.075 3.384 47.275 ;
     RECT  27.888 47.187 29.976 47.275 ;
     RECT  78 46.597 78.408 47.275 ;
     RECT  29.088 47.275 29.976 47.315 ;
     RECT  32.448 47.221 32.472 47.315 ;
     RECT  61.68 47.221 62.664 47.315 ;
     RECT  0.048 43.907 0.36 47.363 ;
     RECT  0.144 47.363 0.36 47.411 ;
     RECT  0.144 47.411 0.264 47.459 ;
     RECT  40.032 45.635 40.512 47.461 ;
     RECT  24 45.059 24.312 47.541 ;
     RECT  24 47.541 24.408 47.629 ;
     RECT  67.2 46.501 67.752 47.653 ;
     RECT  40.032 47.461 40.92 47.701 ;
     RECT  39.6 47.701 40.92 47.747 ;
     RECT  39.6 47.747 40.512 47.787 ;
     RECT  0.144 47.459 0.168 47.795 ;
     RECT  50.448 42.083 51.312 47.797 ;
     RECT  42.72 47.413 42.744 47.843 ;
     RECT  48.432 47.797 48.456 47.881 ;
     RECT  49.584 47.797 51.312 47.881 ;
     RECT  58.656 47.855 58.68 47.939 ;
     RECT  59.856 47.855 59.88 47.939 ;
     RECT  64.08 46.019 64.104 48.035 ;
     RECT  56.4 45.251 56.712 48.095 ;
     RECT  56.4 48.095 57.624 48.179 ;
     RECT  34.8 44.339 35.112 48.229 ;
     RECT  70.128 47.461 70.152 48.229 ;
     RECT  72.384 44.341 72.912 48.229 ;
     RECT  45.6 45.683 45.912 48.277 ;
     RECT  70.128 48.229 70.776 48.339 ;
     RECT  45.6 48.277 46.728 48.363 ;
     RECT  47.952 48.309 47.976 48.419 ;
     RECT  21.6 48.339 21.624 48.427 ;
     RECT  69.792 48.339 70.776 48.427 ;
     RECT  74.304 48.339 74.328 48.427 ;
     RECT  29.4 47.315 29.976 48.515 ;
     RECT  61.68 47.315 62.616 48.517 ;
     RECT  34.704 48.229 35.112 48.629 ;
     RECT  36.48 48.181 36.504 48.629 ;
     RECT  25.68 47.845 25.704 48.659 ;
     RECT  34.704 48.629 36.504 48.683 ;
     RECT  34.704 48.683 35.544 48.717 ;
     RECT  40.032 47.787 40.512 48.787 ;
     RECT  40.032 48.787 40.728 48.875 ;
     RECT  7.8 45.299 8.112 48.949 ;
     RECT  61.632 48.517 62.616 48.949 ;
     RECT  15.792 47.845 15.816 48.995 ;
     RECT  24 47.629 24.312 48.997 ;
     RECT  4.992 48.915 5.016 49.003 ;
     RECT  74.064 48.915 74.088 49.003 ;
     RECT  34.704 48.717 35.112 49.043 ;
     RECT  78 47.275 78.312 49.077 ;
     RECT  72.384 48.229 73.032 49.139 ;
     RECT  56.4 48.179 57.048 49.187 ;
     RECT  78 49.077 78.408 49.187 ;
     RECT  7.8 48.949 9 49.189 ;
     RECT  18.6 47.147 18.912 49.299 ;
     RECT  2.4 47.275 2.712 49.333 ;
     RECT  7.8 49.189 9.096 49.363 ;
     RECT  17.712 49.299 18.912 49.387 ;
     RECT  43.728 43.657 43.752 49.439 ;
     RECT  43.728 49.439 43.896 49.523 ;
     RECT  13.2 44.665 13.512 49.525 ;
     RECT  67.2 47.653 67.8 49.525 ;
     RECT  70.224 48.427 70.248 49.525 ;
     RECT  69.792 49.525 70.248 49.579 ;
     RECT  67.2 49.525 68.376 49.609 ;
     RECT  43.728 49.523 43.752 49.619 ;
     RECT  53.808 48.949 53.832 49.619 ;
     RECT  54.384 49.653 54.6 49.741 ;
     RECT  69.792 49.579 69.816 49.763 ;
     RECT  61.632 48.949 62.76 49.813 ;
     RECT  38.928 49.845 38.952 49.933 ;
     RECT  34.8 49.043 35.112 49.939 ;
     RECT  47.184 49.909 47.208 50.003 ;
     RECT  61.008 49.813 62.76 50.003 ;
     RECT  34.8 49.939 35.688 50.027 ;
     RECT  16.56 49.205 16.584 50.053 ;
     RECT  72.384 49.139 72.912 50.101 ;
     RECT  15.984 50.053 16.872 50.155 ;
     RECT  7.8 49.363 9.72 50.159 ;
     RECT  18.6 49.387 18.912 50.159 ;
     RECT  54.384 49.741 54.456 50.185 ;
     RECT  20.544 49.525 20.568 50.219 ;
     RECT  7.68 50.159 9.72 50.243 ;
     RECT  18.6 50.159 19.368 50.243 ;
     RECT  23.376 48.997 24.312 50.291 ;
     RECT  40.032 48.875 40.512 50.293 ;
     RECT  56.4 49.187 56.712 50.341 ;
     RECT  13.2 49.525 14.28 50.357 ;
     RECT  39.696 50.293 40.512 50.387 ;
     RECT  15.984 50.155 16.008 50.389 ;
     RECT  13.2 50.357 14.808 50.411 ;
     RECT  2.4 49.333 3.528 50.435 ;
     RECT  14.784 50.411 14.808 50.445 ;
     RECT  7.8 50.243 9.72 50.531 ;
     RECT  25.872 50.485 25.896 50.579 ;
     RECT  7.8 50.531 8.904 50.603 ;
     RECT  64.032 49.045 64.056 50.677 ;
     RECT  71.664 50.101 72.912 50.723 ;
     RECT  27.6 50.549 27.624 50.725 ;
     RECT  26.784 50.725 27.624 50.731 ;
     RECT  72.384 50.723 72.912 50.773 ;
     RECT  29.4 48.515 29.712 50.783 ;
     RECT  64.032 50.677 65.064 50.859 ;
     RECT  21.648 50.783 21.672 50.867 ;
     RECT  28.656 50.783 29.712 50.867 ;
     RECT  67.2 49.609 67.896 50.869 ;
     RECT  20.256 50.805 20.28 50.893 ;
     RECT  65.04 50.859 65.064 50.923 ;
     RECT  66.336 50.869 67.896 50.963 ;
     RECT  15.792 50.389 16.008 50.965 ;
     RECT  72.384 50.773 73.032 50.965 ;
     RECT  61.104 50.003 62.76 50.975 ;
     RECT  22.704 50.899 22.728 50.987 ;
     RECT  32.976 50.101 33 50.997 ;
     RECT  34.8 50.027 35.112 50.997 ;
     RECT  59.904 50.927 59.928 51.011 ;
     RECT  60.96 50.975 62.76 51.051 ;
     RECT  60.96 51.051 62.616 51.059 ;
     RECT  32.976 50.997 33.48 51.108 ;
     RECT  34.8 50.997 35.208 51.155 ;
     RECT  54.432 50.185 54.456 51.157 ;
     RECT  61.632 51.059 62.616 51.299 ;
     RECT  15.408 50.965 16.008 51.347 ;
     RECT  50.448 47.881 51.312 51.347 ;
     RECT  72.384 50.965 73.272 51.349 ;
     RECT  26.784 50.731 26.808 51.587 ;
     RECT  33.456 51.108 33.48 51.635 ;
     RECT  61.632 51.299 62.112 51.635 ;
     RECT  34.8 51.155 35.112 51.887 ;
     RECT  54.432 51.157 54.696 51.923 ;
     RECT  56.4 50.341 57 51.923 ;
     RECT  27.408 51.859 27.528 51.947 ;
     RECT  47.28 51.877 47.304 51.957 ;
     RECT  47.28 51.957 47.688 51.961 ;
     RECT  34.224 51.887 35.112 51.971 ;
     RECT  29.4 50.867 29.712 51.973 ;
     RECT  27.408 51.947 27.432 52.011 ;
     RECT  47.664 51.961 47.688 52.067 ;
     RECT  40.032 50.387 40.512 52.069 ;
     RECT  28.608 51.973 29.712 52.075 ;
     RECT  54.096 52.051 54.12 52.139 ;
     RECT  45.6 48.363 45.912 52.165 ;
     RECT  45.504 52.165 45.912 52.213 ;
     RECT  18.6 50.243 18.912 52.243 ;
     RECT  34.608 51.971 35.112 52.267 ;
     RECT  75.12 52.179 75.144 52.267 ;
     RECT  69.696 51.205 69.72 52.309 ;
     RECT  18.48 52.243 18.912 52.331 ;
     RECT  22.8 52.127 22.824 52.341 ;
     RECT  29.4 52.075 29.712 52.405 ;
     RECT  31.056 52.261 31.08 52.405 ;
     RECT  40.032 52.069 41.016 52.405 ;
     RECT  68.976 52.309 69.72 52.451 ;
     RECT  5.136 51.829 5.16 52.463 ;
     RECT  4.896 52.463 5.16 52.499 ;
     RECT  22.368 52.341 22.824 52.499 ;
     RECT  39.312 52.405 41.016 52.499 ;
     RECT  4.896 52.499 4.92 52.547 ;
     RECT  29.4 52.405 31.08 52.651 ;
     RECT  24 50.291 24.312 52.725 ;
     RECT  40.032 52.499 41.016 52.725 ;
     RECT  40.032 52.725 41.592 52.787 ;
     RECT  42.768 52.703 42.792 52.787 ;
     RECT  51 51.347 51.312 52.885 ;
     RECT  64.032 50.859 64.056 52.885 ;
     RECT  50.448 52.885 51.312 52.971 ;
     RECT  61.68 51.635 62.112 52.981 ;
     RECT  45.024 52.213 46.296 53.027 ;
     RECT  22.896 52.947 22.92 53.035 ;
     RECT  15.408 51.347 15.432 53.075 ;
     RECT  68.976 52.451 69 53.171 ;
     RECT  41.568 52.787 41.592 53.267 ;
     RECT  72.384 51.349 73.56 53.267 ;
     RECT  61.536 52.981 62.112 53.315 ;
     RECT  61.68 53.315 62.112 53.317 ;
     RECT  63.792 52.885 64.632 53.317 ;
     RECT  67.2 50.963 67.512 53.317 ;
     RECT  32.784 52.261 32.808 53.363 ;
     RECT  10.992 52.885 11.016 53.411 ;
     RECT  12 51.925 12.024 53.471 ;
     RECT  13.2 50.411 13.512 53.471 ;
     RECT  24 52.725 24.408 53.493 ;
     RECT  61.68 53.317 64.632 53.507 ;
     RECT  12 53.471 13.512 53.555 ;
     RECT  71.232 53.471 71.256 53.555 ;
     RECT  23.712 53.493 24.408 53.557 ;
     RECT  23.712 53.557 24.504 53.581 ;
     RECT  47.52 53.509 47.544 53.611 ;
     RECT  24 53.581 24.504 53.651 ;
     RECT  67.2 53.317 67.608 53.701 ;
     RECT  67.2 53.701 67.8 53.779 ;
     RECT  21.744 53.685 21.768 53.795 ;
     RECT  43.776 53.557 43.8 53.795 ;
     RECT  64.032 53.507 64.632 53.795 ;
     RECT  67.2 53.779 67.848 53.813 ;
     RECT  66.432 53.813 67.848 53.867 ;
     RECT  38.88 53.907 38.904 53.995 ;
     RECT  66.432 53.867 67.8 54.035 ;
     RECT  56.4 51.923 56.712 54.047 ;
     RECT  72.384 53.267 72.912 54.047 ;
     RECT  56.4 54.047 57.624 54.131 ;
     RECT  71.808 54.047 72.912 54.131 ;
     RECT  40.032 52.787 40.512 54.419 ;
     RECT  51 52.971 51.312 54.581 ;
     RECT  53.04 54.517 53.064 54.581 ;
     RECT  51 54.581 53.064 54.635 ;
     RECT  40.2 54.419 40.512 54.661 ;
     RECT  14.544 54.613 14.568 54.699 ;
     RECT  12 53.555 12.024 54.707 ;
     RECT  45.6 53.027 45.912 54.805 ;
     RECT  24 53.651 24.312 54.837 ;
     RECT  67.2 54.035 67.8 54.851 ;
     RECT  23.232 54.837 24.312 54.925 ;
     RECT  32.448 54.949 32.472 55.033 ;
     RECT  45.6 54.805 46.104 55.091 ;
     RECT  51 54.635 52.104 55.139 ;
     RECT  72.048 54.131 72.912 55.139 ;
     RECT  53.376 55.221 53.4 55.309 ;
     RECT  15.936 54.645 15.96 55.379 ;
     RECT  5.664 54.997 5.688 55.427 ;
     RECT  13.2 53.555 13.512 55.765 ;
     RECT  7.8 50.603 8.112 55.813 ;
     RECT  61.68 53.507 62.112 55.813 ;
     RECT  64.032 53.795 64.056 55.813 ;
     RECT  13.2 55.765 14.232 55.851 ;
     RECT  63.84 55.813 64.056 55.915 ;
     RECT  54.816 55.813 55.224 55.925 ;
     RECT  52.704 55.891 52.728 55.979 ;
     RECT  54 55.925 55.224 55.979 ;
     RECT  64.032 55.915 64.056 56.099 ;
     RECT  47.904 56.101 47.928 56.245 ;
     RECT  15.504 56.211 15.528 56.299 ;
     RECT  16.848 56.211 16.872 56.299 ;
     RECT  61.68 55.813 62.52 56.309 ;
     RECT  47.328 56.245 47.928 56.329 ;
     RECT  7.8 55.813 8.616 56.389 ;
     RECT  6.816 56.389 8.616 56.427 ;
     RECT  60.96 56.309 62.52 56.483 ;
     RECT  9.744 56.373 9.768 56.531 ;
     RECT  64.944 56.309 64.968 56.531 ;
     RECT  24 54.925 24.312 56.677 ;
     RECT  54 55.979 54.024 56.723 ;
     RECT  61.2 56.483 62.52 56.723 ;
     RECT  55.2 55.979 55.224 56.771 ;
     RECT  40.2 54.661 40.824 56.869 ;
     RECT  47.904 56.329 47.928 56.915 ;
     RECT  61.2 56.723 62.112 56.963 ;
     RECT  23.376 56.677 24.312 57.059 ;
     RECT  27.744 55.237 27.768 57.059 ;
     RECT  39.456 56.869 40.824 57.059 ;
     RECT  49.584 55.141 49.608 57.059 ;
     RECT  49.152 57.253 49.176 57.337 ;
     RECT  39.12 57.263 39.144 57.347 ;
     RECT  29.4 52.651 30.12 57.503 ;
     RECT  40.2 57.059 40.824 57.541 ;
     RECT  64.848 57.619 64.872 57.707 ;
     RECT  13.2 55.851 13.512 57.877 ;
     RECT  76.944 57.829 76.968 57.913 ;
     RECT  51 55.139 51.312 58.021 ;
     RECT  13.2 57.877 13.608 58.067 ;
     RECT  56.4 54.131 56.712 58.069 ;
     RECT  56.4 58.069 56.808 58.079 ;
     RECT  61.68 56.963 62.112 58.115 ;
     RECT  18.6 52.331 18.912 58.117 ;
     RECT  40.2 57.541 40.92 58.117 ;
     RECT  55.824 58.079 56.808 58.155 ;
     RECT  6.816 56.427 8.112 58.163 ;
     RECT  15.36 58.079 15.384 58.163 ;
     RECT  21.12 58.079 21.144 58.163 ;
     RECT  55.824 58.155 56.712 58.163 ;
     RECT  68.976 57.589 69 58.163 ;
     RECT  9.408 58.165 9.432 58.259 ;
     RECT  29.088 57.503 30.12 58.515 ;
     RECT  16.56 58.117 16.584 58.549 ;
     RECT  28.512 58.515 30.12 58.549 ;
     RECT  18.048 58.117 18.912 58.603 ;
     RECT  27.888 58.549 30.12 58.603 ;
     RECT  16.56 58.549 17.064 58.633 ;
     RECT  7.8 58.163 8.112 58.645 ;
     RECT  39.456 58.117 40.92 58.645 ;
     RECT  67.2 54.851 67.608 58.645 ;
     RECT  39.456 58.645 41.016 58.655 ;
     RECT  25.632 58.597 25.656 58.681 ;
     RECT  7.8 58.645 8.664 58.731 ;
     RECT  43.968 58.117 43.992 58.739 ;
     RECT  63.648 57.445 63.672 58.739 ;
     RECT  72.384 55.139 72.912 58.741 ;
     RECT  44.112 58.741 44.136 58.835 ;
     RECT  53.76 58.741 53.784 58.835 ;
     RECT  72.384 58.741 73.224 58.835 ;
     RECT  24 57.059 24.312 58.837 ;
     RECT  27.888 58.603 27.912 58.883 ;
     RECT  24 58.837 24.504 59.125 ;
     RECT  23.904 59.125 24.504 59.219 ;
     RECT  13.2 58.067 13.512 59.221 ;
     RECT  34.8 52.267 35.112 59.231 ;
     RECT  24 59.219 24.504 59.236 ;
     RECT  13.2 59.221 13.704 59.253 ;
     RECT  12.336 59.253 13.704 59.307 ;
     RECT  60.288 59.221 60.312 59.307 ;
     RECT  64.368 59.221 64.392 59.307 ;
     RECT  34.8 59.231 35.208 59.315 ;
     RECT  39.456 58.655 41.64 59.315 ;
     RECT  59.232 59.231 59.256 59.315 ;
     RECT  12.336 59.307 13.512 59.341 ;
     RECT  7.8 58.731 8.112 59.701 ;
     RECT  16.56 58.633 16.584 59.747 ;
     RECT  9.168 59.667 9.192 59.755 ;
     RECT  7.68 59.701 8.112 59.785 ;
     RECT  5.568 59.749 5.592 59.833 ;
     RECT  67.2 58.645 67.992 59.843 ;
     RECT  39.888 59.315 41.64 59.891 ;
     RECT  24 59.236 24.408 59.939 ;
     RECT  33.024 59.893 33.048 59.941 ;
     RECT  34.8 59.315 35.112 59.941 ;
     RECT  33.024 59.941 35.112 60.011 ;
     RECT  67.2 59.843 67.896 60.243 ;
     RECT  50.016 58.021 51.312 60.275 ;
     RECT  64.416 59.461 64.44 60.275 ;
     RECT  17.328 60.213 17.352 60.301 ;
     RECT  66.528 60.243 67.896 60.331 ;
     RECT  2.4 50.435 2.712 60.469 ;
     RECT  56.4 58.163 56.712 60.613 ;
     RECT  2.4 60.469 3.432 60.627 ;
     RECT  13.2 59.341 13.512 60.709 ;
     RECT  2.4 60.627 4.152 60.715 ;
     RECT  45.6 55.091 45.912 60.767 ;
     RECT  45.6 60.767 46.728 60.789 ;
     RECT  45.6 60.789 47.352 60.851 ;
     RECT  47.328 60.851 47.352 60.877 ;
     RECT  27.36 60.853 27.384 60.937 ;
     RECT  39.888 59.891 40.92 60.949 ;
     RECT  72.384 58.835 72.912 60.949 ;
     RECT  56.4 60.613 56.808 61.011 ;
     RECT  58.368 59.797 58.392 61.011 ;
     RECT  78 49.187 78.312 61.045 ;
     RECT  56.4 61.011 58.392 61.099 ;
     RECT  72.384 60.949 73.512 61.151 ;
     RECT  72.336 61.151 73.512 61.235 ;
     RECT  33.984 60.011 35.112 61.331 ;
     RECT  12.96 60.709 13.512 61.379 ;
     RECT  56.4 61.099 57.048 61.419 ;
     RECT  72.384 61.235 73.512 61.493 ;
     RECT  75.024 61.459 75.048 61.493 ;
     RECT  72.384 61.493 75.048 61.547 ;
     RECT  18.6 58.603 18.912 61.557 ;
     RECT  47.568 61.477 47.592 61.561 ;
     RECT  39.6 60.949 40.92 61.619 ;
     RECT  58.368 61.099 58.392 61.619 ;
     RECT  72.384 61.547 74.088 61.619 ;
     RECT  50.832 60.275 51.312 61.621 ;
     RECT  17.856 61.557 18.912 61.645 ;
     RECT  50.832 61.621 51.72 61.765 ;
     RECT  2.4 60.715 3.432 61.813 ;
     RECT  61.8 58.115 62.112 61.813 ;
     RECT  63.264 61.765 63.288 61.867 ;
     RECT  61.68 61.813 62.112 61.907 ;
     RECT  64.608 61.813 65.592 61.907 ;
     RECT  75.12 61.813 75.144 61.907 ;
     RECT  56.4 61.419 57 62.101 ;
     RECT  72.384 61.619 73.032 62.147 ;
     RECT  2.4 61.813 4.056 62.195 ;
     RECT  67.2 60.331 67.608 62.195 ;
     RECT  78 61.045 78.744 62.195 ;
     RECT  5.952 60.997 5.976 62.435 ;
     RECT  49.92 61.765 51.72 62.531 ;
     RECT  45.6 60.851 45.912 62.533 ;
     RECT  7.8 59.785 8.112 62.677 ;
     RECT  25.68 62.101 25.704 62.677 ;
     RECT  7.8 62.677 8.568 62.763 ;
     RECT  25.68 62.677 26.136 62.763 ;
     RECT  56.304 62.101 57 62.763 ;
     RECT  13.104 61.379 13.512 62.803 ;
     RECT  12.48 62.803 13.512 62.821 ;
     RECT  15.984 62.629 16.008 62.867 ;
     RECT  12.48 62.821 13.704 62.891 ;
     RECT  13.2 62.891 13.704 62.905 ;
     RECT  19.92 62.629 19.944 62.915 ;
     RECT  3.936 62.195 3.96 63.011 ;
     RECT  45.6 62.533 46.008 63.187 ;
     RECT  78 62.195 78.312 63.187 ;
     RECT  51 62.531 51.72 63.203 ;
     RECT  9.744 63.187 9.768 63.275 ;
     RECT  33.792 62.677 33.816 63.275 ;
     RECT  38.448 63.187 38.472 63.275 ;
     RECT  45.6 63.187 46.776 63.275 ;
     RECT  66.144 63.205 66.168 63.289 ;
     RECT  56.304 62.763 56.712 63.299 ;
     RECT  58.704 62.581 58.728 63.299 ;
     RECT  43.296 63.455 43.32 63.539 ;
     RECT  45.6 63.275 46.008 63.541 ;
     RECT  74.88 62.677 74.904 63.779 ;
     RECT  18.6 61.645 18.912 63.781 ;
     RECT  29.4 58.603 30.12 63.781 ;
     RECT  53.424 63.699 53.448 63.787 ;
     RECT  45.024 63.541 46.008 63.827 ;
     RECT  49.92 62.531 49.944 63.829 ;
     RECT  51 63.203 51.312 63.829 ;
     RECT  61.8 61.907 62.112 63.839 ;
     RECT  77.616 63.187 78.312 63.839 ;
     RECT  25.296 63.763 25.32 63.851 ;
     RECT  77.616 63.839 78.696 63.861 ;
     RECT  45.36 63.827 46.008 63.875 ;
     RECT  17.088 62.629 17.112 63.923 ;
     RECT  29.04 63.781 30.12 63.923 ;
     RECT  61.536 63.839 62.112 63.923 ;
     RECT  77.232 63.861 78.696 63.923 ;
     RECT  18.288 63.781 18.912 64.019 ;
     RECT  77.232 63.923 78.312 64.019 ;
     RECT  34.8 61.331 35.112 64.069 ;
     RECT  12 64.053 12.024 64.141 ;
     RECT  67.2 62.195 67.512 64.165 ;
     RECT  45.6 63.875 46.008 64.211 ;
     RECT  24 59.939 24.312 64.309 ;
     RECT  23.328 64.309 24.312 64.393 ;
     RECT  9.648 64.053 9.672 64.451 ;
     RECT  49.92 63.829 51.312 64.451 ;
     RECT  68.496 64.357 68.52 64.549 ;
     RECT  40.2 61.619 40.92 64.645 ;
     RECT  42.24 64.117 42.264 64.693 ;
     RECT  42.24 64.693 42.744 64.739 ;
     RECT  76.704 64.723 76.728 64.811 ;
     RECT  74.64 64.751 74.664 64.835 ;
     RECT  68.496 64.549 68.808 64.883 ;
     RECT  47.856 64.885 47.88 64.969 ;
     RECT  26.496 63.861 26.52 64.991 ;
     RECT  49.92 64.451 49.944 64.991 ;
     RECT  38.784 64.885 38.808 65.027 ;
     RECT  66.96 64.165 67.512 65.027 ;
     RECT  49.008 64.991 49.944 65.067 ;
     RECT  26.208 64.991 26.52 65.075 ;
     RECT  49.008 65.067 49.032 65.075 ;
     RECT  24 64.393 24.312 65.125 ;
     RECT  24 65.125 25.08 65.267 ;
     RECT  72.384 62.147 72.912 65.269 ;
     RECT  68.928 65.269 68.952 65.353 ;
     RECT  71.76 65.269 72.912 65.451 ;
     RECT  13.2 62.905 13.512 65.461 ;
     RECT  34.464 64.069 35.112 65.461 ;
     RECT  13.2 65.461 14.232 65.509 ;
     RECT  29.4 63.923 30.12 65.509 ;
     RECT  3.936 65.461 3.96 65.545 ;
     RECT  13.2 65.509 15 65.545 ;
     RECT  34.464 65.461 35.928 65.545 ;
     RECT  2.4 62.195 2.904 65.603 ;
     RECT  10.896 64.053 10.92 65.651 ;
     RECT  45.6 64.211 45.912 65.749 ;
     RECT  47.184 65.749 47.208 65.899 ;
     RECT  48.288 65.797 48.312 65.899 ;
     RECT  34.464 65.545 35.112 65.939 ;
     RECT  64.944 65.845 64.968 65.939 ;
     RECT  58.608 65.509 58.632 65.963 ;
     RECT  67.008 65.027 67.512 65.989 ;
     RECT  61.8 63.923 62.112 66.037 ;
     RECT  26.496 65.075 26.52 66.085 ;
     RECT  67.008 65.989 67.848 66.091 ;
     RECT  61.8 66.037 62.232 66.121 ;
     RECT  42.72 64.739 42.744 66.131 ;
     RECT  60.144 65.875 60.168 66.131 ;
     RECT  64.464 65.973 64.584 66.131 ;
     RECT  65.904 66.037 65.928 66.131 ;
     RECT  14.88 65.545 15 66.179 ;
     RECT  29.4 65.509 30.216 66.179 ;
     RECT  67.008 66.091 67.512 66.227 ;
     RECT  49.584 66.085 49.608 66.325 ;
     RECT  17.184 65.701 17.208 66.421 ;
     RECT  7.8 62.763 8.112 66.469 ;
     RECT  2.4 65.603 2.712 66.565 ;
     RECT  78 64.019 78.312 66.579 ;
     RECT  17.136 66.421 17.208 66.661 ;
     RECT  49.008 66.325 49.608 66.667 ;
     RECT  77.52 66.579 78.312 66.667 ;
     RECT  61.8 66.121 62.112 66.677 ;
     RECT  76.368 66.613 76.392 66.697 ;
     RECT  14.88 66.179 14.904 66.707 ;
     RECT  7.392 66.469 8.112 66.709 ;
     RECT  17.088 66.661 17.208 66.741 ;
     RECT  25.92 66.085 26.52 66.755 ;
     RECT  71.232 66.677 71.256 66.765 ;
     RECT  7.392 66.709 9.096 66.795 ;
     RECT  61.68 66.677 62.112 66.851 ;
     RECT  38.832 66.757 38.856 66.859 ;
     RECT  52.464 65.509 52.488 66.899 ;
     RECT  72.6 65.451 72.912 66.963 ;
     RECT  44.448 66.911 44.472 66.995 ;
     RECT  7.392 66.795 8.568 66.997 ;
     RECT  18.6 64.019 18.912 66.997 ;
     RECT  72.6 66.963 73.896 67.051 ;
     RECT  16.752 66.741 17.208 67.061 ;
     RECT  18.6 66.997 19.464 67.061 ;
     RECT  70.704 66.997 70.728 67.081 ;
     RECT  75.264 66.997 75.288 67.081 ;
     RECT  39.936 64.645 40.92 67.091 ;
     RECT  16.752 67.061 19.464 67.115 ;
     RECT  26.496 66.755 26.52 67.179 ;
     RECT  16.752 67.115 18.912 67.189 ;
     RECT  61.8 66.851 62.112 67.189 ;
     RECT  61.8 67.189 62.76 67.273 ;
     RECT  6.768 66.997 8.568 67.283 ;
     RECT  15.984 67.189 18.912 67.283 ;
     RECT  49.008 66.667 49.032 67.283 ;
     RECT  75.84 67.189 75.864 67.283 ;
     RECT  2.4 66.565 3.24 67.523 ;
     RECT  16.752 67.283 16.776 67.523 ;
     RECT  33.216 66.613 33.24 67.571 ;
     RECT  64.992 67.237 65.016 67.621 ;
     RECT  54.144 66.933 54.168 67.669 ;
     RECT  64.368 67.621 65.016 67.763 ;
     RECT  29.4 66.179 30.12 67.765 ;
     RECT  34.8 65.939 35.112 67.765 ;
     RECT  51 64.451 51.312 67.765 ;
     RECT  36.192 66.133 36.216 67.907 ;
     RECT  40.2 67.091 40.92 68.053 ;
     RECT  54.096 67.669 54.168 68.053 ;
     RECT  10.8 67.237 10.824 68.063 ;
     RECT  41.904 66.469 41.928 68.063 ;
     RECT  39.84 68.053 40.92 68.101 ;
     RECT  41.904 68.063 42.168 68.101 ;
     RECT  10.8 68.063 11.448 68.139 ;
     RECT  34.176 67.765 35.112 68.139 ;
     RECT  54.096 68.053 54.696 68.139 ;
     RECT  57.936 67.525 57.96 68.139 ;
     RECT  64.8 67.763 65.016 68.139 ;
     RECT  11.424 68.139 11.448 68.147 ;
     RECT  39.84 68.101 42.168 68.147 ;
     RECT  43.344 68.063 43.368 68.147 ;
     RECT  45.6 65.749 46.008 68.149 ;
     RECT  45.6 68.149 46.776 68.243 ;
     RECT  29.4 67.765 30.264 68.245 ;
     RECT  6.768 67.283 6.792 68.341 ;
     RECT  7.8 67.283 8.568 68.341 ;
     RECT  44.448 68.149 44.472 68.387 ;
     RECT  64.992 68.139 65.016 68.387 ;
     RECT  59.28 68.389 59.304 68.405 ;
     RECT  6.768 68.341 8.568 68.425 ;
     RECT  58.464 68.405 59.304 68.473 ;
     RECT  61.8 67.273 62.112 68.581 ;
     RECT  54.096 68.139 54.12 68.627 ;
     RECT  17.088 68.597 17.112 68.629 ;
     RECT  61.8 68.581 62.712 68.665 ;
     RECT  58.464 68.473 58.488 68.675 ;
     RECT  17.088 68.629 17.208 68.685 ;
     RECT  16.032 68.629 16.056 68.715 ;
     RECT  14.784 67.765 14.808 68.723 ;
     RECT  18.6 67.283 18.912 68.725 ;
     RECT  50.256 67.765 51.312 68.771 ;
     RECT  56.4 63.299 56.712 68.869 ;
     RECT  6.864 68.425 8.568 68.915 ;
     RECT  17.184 68.685 17.208 68.915 ;
     RECT  28.8 68.245 30.264 68.963 ;
     RECT  18.6 68.725 19.032 68.981 ;
     RECT  2.4 67.523 2.856 69.011 ;
     RECT  28.992 68.963 30.264 69.011 ;
     RECT  20.448 68.773 20.472 69.035 ;
     RECT  27.744 68.965 27.768 69.049 ;
     RECT  15.936 69.045 15.96 69.155 ;
     RECT  72.6 67.051 72.912 69.301 ;
     RECT  26.736 68.341 26.76 69.365 ;
     RECT  6.864 68.915 8.112 69.443 ;
     RECT  18.6 68.981 19.464 69.443 ;
     RECT  26.448 69.365 27.432 69.453 ;
     RECT  18.6 69.443 19.032 69.491 ;
     RECT  27.312 69.453 27.432 69.491 ;
     RECT  28.992 69.011 30.12 69.517 ;
     RECT  39.84 68.147 41.64 69.539 ;
     RECT  39.84 69.539 40.92 69.547 ;
     RECT  27.312 69.491 27.336 69.587 ;
     RECT  76.368 68.917 76.392 69.683 ;
     RECT  56.4 68.869 57.432 69.731 ;
     RECT  61.8 68.665 62.112 69.973 ;
     RECT  34.8 68.139 35.112 70.021 ;
     RECT  13.2 65.545 13.512 70.035 ;
     RECT  13.2 70.035 14.28 70.069 ;
     RECT  13.056 70.069 14.28 70.123 ;
     RECT  13.056 70.123 13.512 70.153 ;
     RECT  24 65.267 24.312 70.549 ;
     RECT  72.6 69.301 73.56 70.585 ;
     RECT  23.376 70.549 24.312 70.635 ;
     RECT  34.032 70.021 35.112 70.645 ;
     RECT  51 68.771 51.312 70.645 ;
     RECT  29.04 69.517 30.12 70.691 ;
     RECT  34.032 70.645 35.88 70.691 ;
     RECT  38.688 70.405 38.712 70.699 ;
     RECT  53.904 70.611 53.928 70.699 ;
     RECT  76.416 70.611 76.44 70.699 ;
     RECT  34.176 70.691 35.88 70.729 ;
     RECT  50.88 70.645 51.312 70.773 ;
     RECT  50.88 70.773 52.536 70.789 ;
     RECT  50.88 70.789 53.016 70.827 ;
     RECT  42.624 70.405 42.648 70.979 ;
     RECT  61.536 69.973 62.112 70.979 ;
     RECT  9.552 70.645 9.576 70.995 ;
     RECT  22.752 70.933 22.776 71.019 ;
     RECT  9.552 70.995 10.296 71.083 ;
     RECT  59.808 70.645 59.832 71.171 ;
     RECT  67.2 66.227 67.512 71.187 ;
     RECT  51 70.827 53.016 71.275 ;
     RECT  67.008 71.187 67.512 71.275 ;
     RECT  29.4 70.691 30.12 71.315 ;
     RECT  47.904 69.301 47.928 71.317 ;
     RECT  61.8 70.979 62.112 71.327 ;
     RECT  47.904 71.317 48.024 71.363 ;
     RECT  51 71.275 52.248 71.363 ;
     RECT  58.128 71.279 58.152 71.363 ;
     RECT  48 71.363 48.024 71.403 ;
     RECT  61.8 71.327 62.712 71.411 ;
     RECT  23.904 70.635 24.312 71.437 ;
     RECT  27.264 71.509 27.288 71.595 ;
     RECT  9.552 71.083 9.576 71.651 ;
     RECT  43.776 70.405 43.8 71.651 ;
     RECT  26.064 70.405 26.088 71.653 ;
     RECT  26.064 71.653 26.808 71.737 ;
     RECT  37.104 70.645 37.128 71.797 ;
     RECT  38.736 71.763 38.76 71.797 ;
     RECT  37.104 71.797 38.76 71.891 ;
     RECT  7.8 69.443 8.112 72.019 ;
     RECT  53.808 72.117 53.832 72.205 ;
     RECT  34.176 70.729 35.112 72.229 ;
     RECT  18.6 69.491 18.912 72.277 ;
     RECT  26.064 71.737 26.088 72.419 ;
     RECT  40.2 69.547 40.92 72.419 ;
     RECT  18.336 72.277 18.912 72.565 ;
     RECT  38.448 71.891 38.76 72.565 ;
     RECT  34.176 72.229 35.208 72.611 ;
     RECT  22.656 71.797 22.68 72.619 ;
     RECT  38.448 72.565 38.856 72.659 ;
     RECT  43.68 72.565 43.704 72.947 ;
     RECT  69.888 72.325 69.912 72.947 ;
     RECT  7.68 72.019 8.112 72.949 ;
     RECT  51 71.363 51.528 72.995 ;
     RECT  75.312 70.645 75.336 72.995 ;
     RECT  38.448 72.659 38.472 73.235 ;
     RECT  17.904 72.565 18.912 73.477 ;
     RECT  34.8 72.611 35.208 73.523 ;
     RECT  17.904 73.477 19.368 73.579 ;
     RECT  71.04 73.525 71.064 73.619 ;
     RECT  43.344 73.381 43.368 73.763 ;
     RECT  10.848 73.765 10.872 73.781 ;
     RECT  10.224 73.781 10.872 73.849 ;
     RECT  63.84 72.901 63.864 73.907 ;
     RECT  38.688 73.813 38.712 73.955 ;
     RECT  29.4 71.315 29.712 74.015 ;
     RECT  24 71.437 24.312 74.037 ;
     RECT  22.176 74.015 22.2 74.099 ;
     RECT  29.4 74.015 30.264 74.099 ;
     RECT  10.224 73.849 10.248 74.147 ;
     RECT  7.392 72.949 8.112 74.339 ;
     RECT  23.76 74.037 24.312 74.339 ;
     RECT  36.864 74.259 36.888 74.347 ;
     RECT  38.208 74.293 38.232 74.377 ;
     RECT  56.4 69.731 56.712 74.485 ;
     RECT  18.6 73.579 19.368 74.579 ;
     RECT  51 72.995 51.312 74.581 ;
     RECT  11.424 74.533 11.448 74.617 ;
     RECT  51 74.581 52.008 74.667 ;
     RECT  58.896 74.581 58.92 74.677 ;
     RECT  58.896 74.677 59.88 74.731 ;
     RECT  59.856 74.731 59.88 74.771 ;
     RECT  48.48 74.629 48.504 74.795 ;
     RECT  47.328 74.741 47.352 74.829 ;
     RECT  58.32 74.835 58.344 74.923 ;
     RECT  34.8 73.523 35.112 74.965 ;
     RECT  33.552 74.629 33.576 75.051 ;
     RECT  34.56 74.965 35.112 75.051 ;
     RECT  13.2 70.153 13.512 75.091 ;
     RECT  18.6 74.579 19.032 75.091 ;
     RECT  15.696 75.091 15.72 75.125 ;
     RECT  31.68 74.997 31.704 75.155 ;
     RECT  61.8 71.411 62.112 75.157 ;
     RECT  13.2 75.091 13.656 75.179 ;
     RECT  15.696 75.125 16.68 75.179 ;
     RECT  17.856 75.091 19.032 75.179 ;
     RECT  52.416 74.677 52.44 75.189 ;
     RECT  54.24 75.157 54.264 75.243 ;
     RECT  56.4 74.485 57.048 75.299 ;
     RECT  61.68 75.157 62.112 75.307 ;
     RECT  60.384 75.253 60.408 75.347 ;
     RECT  64.848 75.253 64.872 75.347 ;
     RECT  52.416 75.189 53.16 75.405 ;
     RECT  18.6 75.179 19.032 75.443 ;
     RECT  16.656 75.179 16.68 75.683 ;
     RECT  52.416 75.405 52.44 75.875 ;
     RECT  34.8 75.051 35.112 76.069 ;
     RECT  38.928 76.085 38.952 76.173 ;
     RECT  33.696 76.149 33.72 76.237 ;
     RECT  61.8 75.307 62.112 76.357 ;
     RECT  23.904 74.339 24.312 76.403 ;
     RECT  34.8 76.069 35.208 76.403 ;
     RECT  55.392 75.541 55.416 76.405 ;
     RECT  56.4 75.299 56.712 76.405 ;
     RECT  55.392 76.405 56.712 76.499 ;
     RECT  64.944 75.541 64.968 76.547 ;
     RECT  43.92 76.357 43.944 76.549 ;
     RECT  43.92 76.549 44.184 76.651 ;
     RECT  42.672 76.693 42.696 76.779 ;
     RECT  43.92 76.651 43.944 76.779 ;
     RECT  63.84 76.725 63.864 76.813 ;
     RECT  55.392 76.499 55.416 76.931 ;
     RECT  61.8 76.357 62.76 76.981 ;
     RECT  61.536 76.981 62.76 77.035 ;
     RECT  61.536 77.035 62.112 77.065 ;
     RECT  29.4 74.099 29.712 77.125 ;
     RECT  48.48 77.279 48.504 77.363 ;
     RECT  21.216 76.309 21.24 77.555 ;
     RECT  27.36 77.471 27.384 77.555 ;
     RECT  34.8 76.403 35.112 77.749 ;
     RECT  31.872 77.749 31.896 77.833 ;
     RECT  33.936 77.749 35.112 78.083 ;
     RECT  49.68 76.885 49.704 78.083 ;
     RECT  29.4 77.125 30.216 78.515 ;
     RECT  32.928 77.749 32.952 78.613 ;
     RECT  32.928 78.613 33.72 78.659 ;
     RECT  41.712 77.701 41.736 78.707 ;
     RECT  38.784 79.391 38.808 79.475 ;
     RECT  48.48 78.373 48.504 79.475 ;
     RECT  37.296 79.413 37.32 79.501 ;
     RECT  33.696 78.659 33.72 79.571 ;
     RECT  2.4 69.011 2.712 79.673 ;
     RECT  7.8 74.339 8.112 79.673 ;
     RECT  13.2 75.179 13.512 79.673 ;
     RECT  18.6 75.443 18.912 79.673 ;
     RECT  24 76.403 24.312 79.673 ;
     RECT  29.4 78.515 29.712 79.673 ;
     RECT  34.8 78.083 35.112 79.673 ;
     RECT  40.2 72.419 40.512 79.673 ;
     RECT  45.6 68.243 45.912 79.673 ;
     RECT  51 74.667 51.312 79.673 ;
     RECT  56.4 76.499 56.712 79.673 ;
     RECT  61.8 77.065 62.112 79.673 ;
     RECT  67.2 71.275 67.512 79.673 ;
     RECT  72.6 70.585 72.912 79.673 ;
     RECT  78 66.667 78.312 79.673 ;
     RECT  2.4 79.673 2.52 79.943 ;
     RECT  7.8 79.673 7.92 79.943 ;
     RECT  13.2 79.673 13.32 79.943 ;
     RECT  18.6 79.673 18.72 79.943 ;
     RECT  24 79.673 24.12 79.943 ;
     RECT  29.4 79.673 29.52 79.943 ;
     RECT  34.8 79.673 34.92 79.943 ;
     RECT  40.2 79.673 40.32 79.943 ;
     RECT  45.6 79.673 45.72 79.943 ;
     RECT  51 79.673 51.12 79.943 ;
     RECT  56.4 79.673 56.52 79.943 ;
     RECT  61.8 79.673 61.92 79.943 ;
     RECT  67.2 79.673 67.32 79.943 ;
     RECT  72.6 79.673 72.72 79.943 ;
     RECT  78 79.673 78.12 79.943 ;
     RECT  41.952 81.909 41.976 82.064 ;
    LAYER M6 ;
     RECT  0.016 38.4 0.131 43.68 ;
     RECT  0.131 38.528 0.323 43.68 ;
     RECT  0.323 38.528 0.371 43.552 ;
     RECT  0.371 38.528 2.867 43.296 ;
     RECT  2.867 38.528 2.963 42.4 ;
     RECT  2.16 61.929 3.157 62.601 ;
     RECT  2.16 45.729 3.349 46.401 ;
     RECT  3.349 45.729 3.435 47.264 ;
     RECT  3.061 60.48 3.477 60.512 ;
     RECT  3.157 61.824 3.925 62.601 ;
     RECT  3.925 61.824 4.021 62.944 ;
     RECT  4.021 60.672 4.075 62.944 ;
     RECT  4.075 60.672 4.163 62.601 ;
     RECT  2.16 29.529 4.501 30.201 ;
     RECT  2.963 38.528 4.501 38.56 ;
     RECT  2.963 40.329 4.501 42.4 ;
     RECT  2.16 34.929 4.578 35.601 ;
     RECT  4.501 28.992 4.597 30.201 ;
     RECT  4.578 33.792 4.651 35.601 ;
     RECT  4.578 43.712 4.651 43.744 ;
     RECT  2.16 18.729 4.725 19.401 ;
     RECT  3.925 21.504 4.725 21.536 ;
     RECT  4.725 18.729 4.798 21.536 ;
     RECT  2.16 51.129 4.885 51.801 ;
     RECT  4.597 48.448 4.917 48.48 ;
     RECT  4.885 51.129 4.917 52.512 ;
     RECT  4.917 48.448 4.971 48.992 ;
     RECT  4.917 50.56 4.971 52.512 ;
     RECT  4.971 48.96 5.027 48.992 ;
     RECT  4.798 21.504 5.171 21.536 ;
     RECT  2.16 24.129 5.269 24.801 ;
     RECT  5.269 24 5.355 24.801 ;
     RECT  2.16 67.329 5.365 68.001 ;
     RECT  4.163 61.929 5.557 62.601 ;
     RECT  3.925 65.472 5.611 65.504 ;
     RECT  5.557 59.776 5.626 59.808 ;
     RECT  2.16 7.929 5.653 8.601 ;
     RECT  5.077 17.024 6.261 17.056 ;
     RECT  4.798 18.729 6.261 19.68 ;
     RECT  6.261 17.024 6.315 19.68 ;
     RECT  6.315 17.6 6.757 19.68 ;
     RECT  5.365 67.008 6.757 68.001 ;
     RECT  4.501 38.528 6.805 42.4 ;
     RECT  6.757 17.6 6.827 20 ;
     RECT  6.229 11.904 6.899 11.936 ;
     RECT  6.805 37.312 7.475 42.4 ;
     RECT  2.16 72.729 7.65 73.401 ;
     RECT  2.16 13.329 7.669 14.001 ;
     RECT  4.971 50.56 7.669 51.801 ;
     RECT  7.65 72.064 7.669 73.401 ;
     RECT  7.475 38.528 7.715 42.4 ;
     RECT  7.669 13.329 7.861 14.816 ;
     RECT  7.861 13.184 7.915 14.816 ;
     RECT  7.669 72.064 7.915 74.592 ;
     RECT  2.16 2.529 8.053 3.201 ;
     RECT  5.653 7.929 8.107 9.568 ;
     RECT  8.053 2.529 8.243 4 ;
     RECT  7.715 39.232 8.243 42.4 ;
     RECT  6.757 67.008 8.339 68.384 ;
     RECT  8.485 43.264 8.555 43.296 ;
     RECT  3.435 45.729 8.555 47.072 ;
     RECT  8.243 39.232 8.579 41.504 ;
     RECT  2.16 56.529 8.581 57.201 ;
     RECT  7.669 59.712 8.629 59.744 ;
     RECT  8.629 58.688 8.698 59.744 ;
     RECT  7.669 50.176 9.061 51.801 ;
     RECT  8.339 67.008 9.061 68.001 ;
     RECT  8.579 40.329 9.107 41.504 ;
     RECT  9.107 40.329 9.155 41.376 ;
     RECT  8.698 59.712 9.203 59.744 ;
     RECT  4.597 28.736 9.397 30.201 ;
     RECT  8.581 56.384 9.397 57.201 ;
     RECT  9.397 28.736 9.451 31.008 ;
     RECT  9.397 56.384 9.466 58.208 ;
     RECT  9.451 28.864 9.525 31.008 ;
     RECT  7.915 13.184 9.637 14.001 ;
     RECT  5.557 61.929 9.717 62.752 ;
     RECT  9.637 64.064 9.717 64.096 ;
     RECT  8.485 20.736 9.731 20.768 ;
     RECT  9.061 49.216 9.731 51.801 ;
     RECT  5.355 24.129 9.733 24.801 ;
     RECT  9.061 26.24 9.733 26.272 ;
     RECT  9.733 24.129 9.779 26.272 ;
     RECT  9.466 56.384 9.779 57.201 ;
     RECT  9.717 61.929 9.79 64.096 ;
     RECT  9.525 28.864 9.982 31.136 ;
     RECT  8.107 7.929 10.293 9.184 ;
     RECT  9.637 13.184 10.293 14.112 ;
     RECT  6.827 17.6 10.307 19.401 ;
     RECT  9.061 22.208 10.307 22.24 ;
     RECT  9.541 71.04 10.307 71.072 ;
     RECT  10.293 7.808 10.347 9.184 ;
     RECT  10.293 13.184 10.347 14.176 ;
     RECT  10.347 13.329 10.366 14.176 ;
     RECT  10.347 7.808 10.451 8.601 ;
     RECT  9.685 11.392 10.789 11.424 ;
     RECT  10.307 18.729 10.789 19.401 ;
     RECT  9.397 33.152 10.789 33.184 ;
     RECT  9.061 66.752 10.789 68.001 ;
     RECT  8.485 15.936 10.837 15.968 ;
     RECT  10.789 10.112 10.883 11.424 ;
     RECT  10.837 15.936 10.883 16.672 ;
     RECT  9.779 24.129 11.219 25.76 ;
     RECT  8.555 45.729 11.298 46.401 ;
     RECT  11.298 45.729 11.371 46.56 ;
     RECT  9.731 49.216 11.371 49.44 ;
     RECT  10.789 18.729 11.459 19.552 ;
     RECT  10.789 66.752 11.459 68.128 ;
     RECT  7.915 72.729 11.459 74.592 ;
     RECT  9.637 5.952 11.701 5.984 ;
     RECT  11.701 4.992 11.755 5.984 ;
     RECT  11.755 4.992 11.795 5.024 ;
     RECT  10.789 33.024 12.035 33.184 ;
     RECT  9.79 64.064 12.035 64.096 ;
     RECT  12.035 33.024 12.131 33.056 ;
     RECT  9.79 61.929 12.469 62.601 ;
     RECT  9.397 53.504 12.563 53.536 ;
     RECT  10.883 10.112 12.659 10.144 ;
     RECT  9.982 29.529 13.573 31.136 ;
     RECT  12.325 59.264 13.715 59.296 ;
     RECT  12.469 61.929 13.715 62.88 ;
     RECT  10.883 16.64 13.859 16.672 ;
     RECT  11.459 18.729 14.197 19.401 ;
     RECT  11.371 45.729 14.197 46.401 ;
     RECT  9.779 56.529 14.197 57.201 ;
     RECT  11.459 66.752 14.197 68.001 ;
     RECT  11.371 49.216 14.245 49.248 ;
     RECT  9.731 51.129 14.245 51.801 ;
     RECT  13.045 70.08 14.291 70.112 ;
     RECT  14.197 55.808 14.533 57.201 ;
     RECT  14.197 65.472 14.773 68.001 ;
     RECT  14.245 49.216 14.819 51.801 ;
     RECT  14.533 54.656 14.827 57.201 ;
     RECT  13.573 29.529 14.867 31.968 ;
     RECT  14.827 56.256 15.349 57.201 ;
     RECT  14.773 65.472 15.906 68.704 ;
     RECT  14.827 54.656 15.971 54.688 ;
     RECT  15.906 65.472 15.979 69.088 ;
     RECT  15.979 66.688 16.067 68.704 ;
     RECT  14.867 29.529 16.098 31.136 ;
     RECT  16.098 29.12 16.171 31.136 ;
     RECT  10.451 7.929 16.213 8.601 ;
     RECT  8.243 2.529 16.245 3.201 ;
     RECT  10.366 13.329 16.245 14.112 ;
     RECT  14.197 5.696 16.299 5.728 ;
     RECT  16.213 7.929 16.299 9.76 ;
     RECT  16.245 11.776 16.309 11.808 ;
     RECT  16.245 13.329 16.309 14.24 ;
     RECT  16.309 11.776 16.453 14.24 ;
     RECT  14.197 17.6 16.491 19.401 ;
     RECT  11.219 24.129 16.549 24.801 ;
     RECT  14.819 49.216 16.549 49.248 ;
     RECT  13.045 27.584 16.565 27.616 ;
     RECT  14.819 51.129 16.565 51.801 ;
     RECT  16.549 49.216 16.595 49.44 ;
     RECT  16.549 22.784 16.619 24.801 ;
     RECT  16.565 27.328 16.619 27.616 ;
     RECT  9.155 40.329 16.629 41.001 ;
     RECT  9.637 43.136 16.629 43.168 ;
     RECT  16.453 11.776 16.691 15.456 ;
     RECT  16.629 40.329 16.702 43.168 ;
     RECT  16.595 49.344 16.837 49.44 ;
     RECT  16.565 51.129 16.837 52.768 ;
     RECT  15.349 56.256 16.883 58.144 ;
     RECT  4.651 34.929 17.013 35.601 ;
     RECT  16.883 56.529 17.029 58.144 ;
     RECT  16.067 66.688 17.146 68.64 ;
     RECT  16.691 13.056 17.315 15.456 ;
     RECT  17.317 60.224 17.387 60.256 ;
     RECT  16.245 2.529 17.699 4 ;
     RECT  16.619 23.296 17.699 24.801 ;
     RECT  13.715 61.929 17.826 62.601 ;
     RECT  11.459 72.729 17.845 73.401 ;
     RECT  13.621 75.136 17.845 75.168 ;
     RECT  17.845 75.136 17.891 75.296 ;
     RECT  17.845 72.729 17.893 73.568 ;
     RECT  17.826 61.568 17.899 62.601 ;
     RECT  17.893 72.576 17.939 73.568 ;
     RECT  17.939 72.576 17.963 73.401 ;
     RECT  17.029 56.529 18.083 58.592 ;
     RECT  17.315 13.056 18.275 14.24 ;
     RECT  16.702 43.008 18.277 43.168 ;
     RECT  17.013 34.048 18.419 35.601 ;
     RECT  16.702 40.329 18.469 41.001 ;
     RECT  18.277 42.688 18.469 43.168 ;
     RECT  14.197 44.608 18.469 46.401 ;
     RECT  18.469 40.329 18.485 46.401 ;
     RECT  18.485 40.329 18.539 46.56 ;
     RECT  16.837 49.344 18.539 52.768 ;
     RECT  17.146 67.072 18.997 68.001 ;
     RECT  17.891 75.264 19.043 75.296 ;
     RECT  14.773 38.656 19.091 38.688 ;
     RECT  18.539 40.329 19.187 43.872 ;
     RECT  18.997 67.072 19.475 69.024 ;
     RECT  18.539 45.729 19.717 46.56 ;
     RECT  16.619 27.328 19.765 27.36 ;
     RECT  19.717 45.729 19.765 47.136 ;
     RECT  19.187 43.008 19.819 43.872 ;
     RECT  19.765 45.729 19.819 48.416 ;
     RECT  19.765 27.328 19.829 28.064 ;
     RECT  19.829 26.752 19.883 28.064 ;
     RECT  16.299 7.929 20.003 8.736 ;
     RECT  19.883 26.752 20.003 27.36 ;
     RECT  18.469 20.864 20.291 20.896 ;
     RECT  19.475 67.2 20.483 69.024 ;
     RECT  16.491 18.176 20.579 19.401 ;
     RECT  19.819 43.008 20.579 43.04 ;
     RECT  18.539 50.176 20.579 52.768 ;
     RECT  18.083 56.529 21.155 58.144 ;
     RECT  20.579 50.816 21.683 52.768 ;
     RECT  21.683 50.944 21.733 52.768 ;
     RECT  17.963 72.729 22.165 73.401 ;
     RECT  19.187 40.329 22.389 41.001 ;
     RECT  20.677 42.944 22.389 42.976 ;
     RECT  22.165 72.729 22.626 74.08 ;
     RECT  22.626 72.576 22.645 74.08 ;
     RECT  18.275 13.056 22.693 14.001 ;
     RECT  22.693 13.056 22.741 14.112 ;
     RECT  22.645 71.808 22.741 74.08 ;
     RECT  21.733 50.944 22.763 53.728 ;
     RECT  22.741 70.976 22.773 74.08 ;
     RECT  17.699 24.129 22.789 24.801 ;
     RECT  22.763 51.129 22.955 53.728 ;
     RECT  22.773 70.592 22.955 74.08 ;
     RECT  18.419 34.929 23.269 35.601 ;
     RECT  23.202 54.848 23.275 54.88 ;
     RECT  16.171 29.529 23.403 31.136 ;
     RECT  22.955 70.592 23.411 71.392 ;
     RECT  22.165 27.328 23.595 27.36 ;
     RECT  22.597 33.344 23.603 33.376 ;
     RECT  22.955 72.729 23.893 74.08 ;
     RECT  22.741 11.904 23.939 14.112 ;
     RECT  23.411 70.656 23.939 71.392 ;
     RECT  19.819 45.729 24.373 46.401 ;
     RECT  19.819 48.384 24.373 48.416 ;
     RECT  20.003 7.929 24.469 8.601 ;
     RECT  22.955 51.129 24.469 53.536 ;
     RECT  23.893 59.136 24.515 59.168 ;
     RECT  23.939 11.904 24.563 14.001 ;
     RECT  23.893 4.544 24.611 4.576 ;
     RECT  22.389 40.329 24.661 42.976 ;
     RECT  23.269 34.929 24.757 35.744 ;
     RECT  24.661 40.329 24.757 43.808 ;
     RECT  24.469 51.129 24.757 53.6 ;
     RECT  24.757 34.368 24.811 35.744 ;
     RECT  24.373 45.729 24.811 48.416 ;
     RECT  24.757 50.56 24.811 53.6 ;
     RECT  25.077 5.952 25.187 5.984 ;
     RECT  17.899 61.929 25.285 62.601 ;
     RECT  23.317 64.32 25.285 64.352 ;
     RECT  25.429 21.632 25.515 21.664 ;
     RECT  25.285 61.929 25.653 64.352 ;
     RECT  23.403 29.529 25.669 30.944 ;
     RECT  24.811 50.56 25.845 52.768 ;
     RECT  21.155 56.529 25.845 57.201 ;
     RECT  24.811 48.384 25.899 48.416 ;
     RECT  25.845 50.496 25.918 52.768 ;
     RECT  23.893 72.729 26.053 74.592 ;
     RECT  20.579 18.729 26.197 19.401 ;
     RECT  25.653 61.929 26.243 65.056 ;
     RECT  24.757 39.232 26.245 44.128 ;
     RECT  20.483 67.2 26.421 68.001 ;
     RECT  24.811 34.368 26.466 35.601 ;
     RECT  25.669 29.529 26.485 31.072 ;
     RECT  26.243 61.929 26.485 64.352 ;
     RECT  26.485 60.864 26.531 64.352 ;
     RECT  26.421 67.136 26.531 68.001 ;
     RECT  26.466 34.304 26.539 35.601 ;
     RECT  26.531 60.864 26.554 63.904 ;
     RECT  26.485 29.529 26.819 31.584 ;
     RECT  26.725 22.784 26.867 22.816 ;
     RECT  2.16 78.129 27.061 78.801 ;
     RECT  26.053 71.68 27.234 74.592 ;
     RECT  27.234 71.552 27.307 74.592 ;
     RECT  26.245 38.784 27.349 44.128 ;
     RECT  24.811 45.729 27.349 46.401 ;
     RECT  26.197 18.112 27.381 19.401 ;
     RECT  27.349 38.784 27.395 46.401 ;
     RECT  26.554 60.864 27.395 62.601 ;
     RECT  27.061 77.504 27.395 78.801 ;
     RECT  26.414 69.376 27.397 69.408 ;
     RECT  27.381 18.112 27.441 19.616 ;
     RECT  27.441 18.729 27.454 19.616 ;
     RECT  25.918 50.56 27.499 52.768 ;
     RECT  27.499 50.56 27.635 52.064 ;
     RECT  24.469 7.424 27.685 8.601 ;
     RECT  26.531 67.2 27.701 68.001 ;
     RECT  27.397 69.376 27.701 69.472 ;
     RECT  27.701 11.328 27.733 11.36 ;
     RECT  27.701 67.2 27.755 69.472 ;
     RECT  27.733 11.072 27.779 11.36 ;
     RECT  27.755 67.329 27.779 69.472 ;
     RECT  27.779 11.072 27.819 11.104 ;
     RECT  27.395 39.232 27.877 46.401 ;
     RECT  25.621 58.624 27.877 58.656 ;
     RECT  23.893 15.424 27.893 15.456 ;
     RECT  27.893 15.424 27.947 15.968 ;
     RECT  17.699 2.529 27.973 3.201 ;
     RECT  27.685 6.784 28.309 8.601 ;
     RECT  28.309 6.784 28.395 8.736 ;
     RECT  22.789 24.129 28.547 24.928 ;
     RECT  27.947 15.936 28.597 15.968 ;
     RECT  25.845 56.256 28.597 57.201 ;
     RECT  27.877 58.56 28.597 58.656 ;
     RECT  27.635 50.688 28.651 52.064 ;
     RECT  28.597 21.696 28.691 21.728 ;
     RECT  27.877 39.232 28.691 47.264 ;
     RECT  28.651 50.688 28.715 51.936 ;
     RECT  27.301 26.24 28.787 26.272 ;
     RECT  28.597 15.936 28.981 16.48 ;
     RECT  27.779 69.44 29.027 69.472 ;
     RECT  28.597 56.256 29.035 58.656 ;
     RECT  28.981 15.936 29.05 16.608 ;
     RECT  28.691 39.232 29.123 44.128 ;
     RECT  28.691 45.729 29.123 47.264 ;
     RECT  29.035 56.256 29.123 57.568 ;
     RECT  29.05 15.936 29.219 16.48 ;
     RECT  27.829 32.384 29.221 32.416 ;
     RECT  27.973 2.529 29.269 3.36 ;
     RECT  29.221 32.384 29.291 33.184 ;
     RECT  28.395 6.784 29.315 8.601 ;
     RECT  28.981 10.752 29.315 10.784 ;
     RECT  29.269 2.529 29.611 3.872 ;
     RECT  29.219 15.936 29.843 15.968 ;
     RECT  29.123 39.232 29.843 42.976 ;
     RECT  28.715 51.129 29.941 51.936 ;
     RECT  29.291 32.384 30.275 32.416 ;
     RECT  27.307 72.729 30.275 74.08 ;
     RECT  29.221 22.528 30.851 22.56 ;
     RECT  26.539 34.929 31.333 35.601 ;
     RECT  29.315 7.424 31.379 8.601 ;
     RECT  24.563 12.736 31.861 14.001 ;
     RECT  31.237 16.192 31.861 16.224 ;
     RECT  29.843 40.329 31.861 42.976 ;
     RECT  27.395 78.129 31.861 78.801 ;
     RECT  31.861 22.72 32.373 22.752 ;
     RECT  28.547 24.129 32.373 24.801 ;
     RECT  31.333 33.664 32.389 35.601 ;
     RECT  31.861 12.736 32.427 16.224 ;
     RECT  32.373 22.72 32.427 24.801 ;
     RECT  32.427 12.736 32.437 15.136 ;
     RECT  32.389 33.024 32.437 35.601 ;
     RECT  29.123 45.729 32.437 46.401 ;
     RECT  29.123 56.256 32.437 57.201 ;
     RECT  32.437 33.024 32.491 35.744 ;
     RECT  32.427 22.848 32.531 24.801 ;
     RECT  31.861 40.329 32.675 43.552 ;
     RECT  29.941 51.129 32.819 52.64 ;
     RECT  31.861 38.144 32.963 38.176 ;
     RECT  32.819 51.129 32.965 51.936 ;
     RECT  27.454 18.729 33.013 19.401 ;
     RECT  32.675 40.329 33.013 42.976 ;
     RECT  32.437 12.096 33.107 15.136 ;
     RECT  32.491 33.664 33.251 35.744 ;
     RECT  33.107 12.736 33.683 15.136 ;
     RECT  31.669 75.008 33.685 75.04 ;
     RECT  27.395 61.929 33.781 62.601 ;
     RECT  31.861 77.76 33.971 78.801 ;
     RECT  32.437 21.312 34.067 21.344 ;
     RECT  29.611 2.529 34.165 3.201 ;
     RECT  27.779 67.329 34.165 68.001 ;
     RECT  34.165 67.329 34.283 68.128 ;
     RECT  26.819 29.529 34.355 31.072 ;
     RECT  33.013 59.968 34.547 60 ;
     RECT  33.685 75.008 34.595 76.192 ;
     RECT  31.379 7.929 34.597 8.601 ;
     RECT  32.965 51.008 34.597 51.936 ;
     RECT  34.597 51.008 34.997 52.256 ;
     RECT  32.437 45.729 35.051 47.264 ;
     RECT  34.997 49.984 35.115 52.256 ;
     RECT  33.683 12.736 35.219 14.001 ;
     RECT  35.061 59.264 35.219 59.296 ;
     RECT  34.595 76.16 35.219 76.192 ;
     RECT  33.251 34.929 35.317 35.744 ;
     RECT  34.309 16.576 35.363 16.608 ;
     RECT  33.013 40.192 35.363 42.976 ;
     RECT  35.317 38.208 35.386 38.24 ;
     RECT  34.597 7.929 35.411 9.824 ;
     RECT  34.355 29.529 35.509 30.201 ;
     RECT  35.494 32.96 35.509 32.992 ;
     RECT  32.531 24.129 35.573 24.801 ;
     RECT  35.509 31.872 35.578 32.992 ;
     RECT  32.677 27.264 35.627 27.296 ;
     RECT  35.578 32.96 35.691 32.992 ;
     RECT  35.115 49.984 35.699 51.801 ;
     RECT  35.051 45.729 35.829 46.816 ;
     RECT  34.229 70.272 35.845 70.304 ;
     RECT  35.829 45.568 35.883 46.816 ;
     RECT  34.453 65.472 35.939 65.504 ;
     RECT  35.317 34.929 36.325 36.256 ;
     RECT  33.013 18.176 36.405 19.401 ;
     RECT  35.941 10.304 36.459 10.336 ;
     RECT  34.693 48.64 36.515 48.672 ;
     RECT  30.275 72.729 36.853 73.401 ;
     RECT  34.165 2.529 37.091 3.616 ;
     RECT  35.509 28.992 37.091 30.201 ;
     RECT  35.219 12.864 37.187 14.001 ;
     RECT  33.971 78.016 37.285 78.801 ;
     RECT  36.325 34.688 37.427 36.256 ;
     RECT  37.187 13.329 37.573 14.001 ;
     RECT  35.845 70.272 37.573 70.688 ;
     RECT  36.853 72.729 37.573 74.336 ;
     RECT  35.363 40.329 38.149 42.976 ;
     RECT  37.573 70.272 38.243 74.336 ;
     RECT  38.243 70.272 38.723 73.401 ;
     RECT  38.723 71.808 38.771 73.401 ;
     RECT  35.411 7.929 38.819 8.736 ;
     RECT  35.573 24 38.819 24.801 ;
     RECT  37.427 34.929 38.819 36.256 ;
     RECT  37.285 78.016 38.819 79.456 ;
     RECT  34.283 67.329 38.821 68.001 ;
     RECT  32.437 54.976 38.869 57.201 ;
     RECT  33.781 61.929 38.891 63.264 ;
     RECT  38.821 66.816 38.891 68.001 ;
     RECT  38.723 70.272 38.891 70.304 ;
     RECT  38.771 72.576 38.891 73.401 ;
     RECT  38.819 78.016 38.891 78.801 ;
     RECT  38.149 40.329 38.901 43.936 ;
     RECT  35.699 51.129 38.917 51.801 ;
     RECT  38.901 39.872 38.955 43.936 ;
     RECT  38.837 76.096 38.963 76.128 ;
     RECT  38.869 53.952 39.086 57.201 ;
     RECT  39.086 53.952 39.147 57.312 ;
     RECT  38.955 39.872 39.155 42.336 ;
     RECT  39.147 56.256 39.155 57.312 ;
     RECT  38.917 49.856 39.301 51.801 ;
     RECT  36.405 17.92 39.395 19.401 ;
     RECT  35.883 45.568 39.395 46.401 ;
     RECT  39.589 47.744 39.733 47.776 ;
     RECT  39.301 49.856 39.733 52.448 ;
     RECT  39.733 47.744 39.787 52.448 ;
     RECT  37.573 13.329 39.923 15.136 ;
     RECT  38.955 43.904 39.923 43.936 ;
     RECT  39.829 69.504 40.115 69.536 ;
     RECT  38.725 5.44 40.643 5.472 ;
     RECT  39.787 48.832 40.739 48.864 ;
     RECT  40.069 21.12 41.027 21.152 ;
     RECT  39.155 40.329 41.029 42.336 ;
     RECT  41.029 40 41.171 42.336 ;
     RECT  38.819 34.929 41.525 35.601 ;
     RECT  38.819 24.129 41.557 24.801 ;
     RECT  39.787 51.129 41.557 52.448 ;
     RECT  41.509 32.384 41.579 32.416 ;
     RECT  40.981 58.688 41.651 58.72 ;
     RECT  39.925 81.92 41.987 81.952 ;
     RECT  41.525 34.048 42.133 35.601 ;
     RECT  38.891 67.329 42.133 68.001 ;
     RECT  42.133 34.048 42.227 35.744 ;
     RECT  39.395 18.729 42.677 19.401 ;
     RECT  41.557 51.129 42.803 52.768 ;
     RECT  42.677 18.729 42.851 20.576 ;
     RECT  41.557 24.129 42.899 25.056 ;
     RECT  42.851 18.729 43.237 19.552 ;
     RECT  43.189 15.68 43.253 15.712 ;
     RECT  43.237 17.664 43.253 19.552 ;
     RECT  38.891 61.929 43.285 62.601 ;
     RECT  43.253 15.68 43.307 19.552 ;
     RECT  38.819 7.929 43.362 8.601 ;
     RECT  39.923 13.329 43.381 14.001 ;
     RECT  43.285 6.208 43.435 6.24 ;
     RECT  43.362 7.929 43.435 9.824 ;
     RECT  42.133 32.128 43.475 32.16 ;
     RECT  41.171 40.329 43.477 42.336 ;
     RECT  43.477 39.936 43.619 42.336 ;
     RECT  38.891 72.729 43.669 73.401 ;
     RECT  43.307 15.68 43.883 16.864 ;
     RECT  43.307 18.56 43.947 19.552 ;
     RECT  42.661 76.736 44.13 76.768 ;
     RECT  44.078 58.752 44.147 58.784 ;
     RECT  43.669 72.576 44.149 73.401 ;
     RECT  44.13 76.608 44.149 76.768 ;
     RECT  38.891 78.129 44.149 78.801 ;
     RECT  44.149 71.36 44.203 73.401 ;
     RECT  44.149 76.608 44.203 78.801 ;
     RECT  43.619 39.936 44.341 41.952 ;
     RECT  42.133 67.329 44.437 68.128 ;
     RECT  43.947 18.56 44.483 19.401 ;
     RECT  44.341 38.784 44.523 41.952 ;
     RECT  44.965 5.952 45.493 5.984 ;
     RECT  43.435 7.929 45.493 8.601 ;
     RECT  39.395 45.729 45.493 46.401 ;
     RECT  42.803 51.129 45.493 51.801 ;
     RECT  42.709 27.072 45.941 27.104 ;
     RECT  44.053 22.72 46.019 22.752 ;
     RECT  45.941 27.072 46.019 28 ;
     RECT  43.861 43.584 46.019 43.616 ;
     RECT  44.523 40.329 46.117 41.952 ;
     RECT  45.493 5.952 46.211 8.601 ;
     RECT  42.899 24.129 46.261 24.801 ;
     RECT  46.019 27.072 46.261 27.104 ;
     RECT  45.493 51.129 46.307 52.256 ;
     RECT  46.261 26.816 46.315 27.104 ;
     RECT  46.261 24 46.33 24.801 ;
     RECT  43.883 16.832 46.693 16.864 ;
     RECT  43.861 49.472 46.693 49.504 ;
     RECT  43.285 61.929 46.693 63.52 ;
     RECT  45.493 45.568 46.787 46.401 ;
     RECT  44.437 66.944 46.787 68.192 ;
     RECT  46.211 7.232 46.835 8.601 ;
     RECT  46.693 48.32 47.157 49.504 ;
     RECT  46.307 51.129 47.157 51.936 ;
     RECT  46.787 66.944 47.173 68.001 ;
     RECT  47.157 48.32 47.23 51.936 ;
     RECT  42.227 34.929 47.269 35.744 ;
     RECT  39.155 56.256 47.363 57.201 ;
     RECT  46.693 60.8 47.363 63.52 ;
     RECT  44.965 31.872 47.365 31.904 ;
     RECT  47.363 61.504 47.595 63.52 ;
     RECT  47.595 61.504 47.603 62.601 ;
     RECT  46.117 39.872 47.653 41.952 ;
     RECT  47.23 51.129 47.653 51.936 ;
     RECT  47.653 39.872 47.723 43.168 ;
     RECT  47.23 48.32 47.723 49.504 ;
     RECT  47.653 51.129 47.723 52 ;
     RECT  47.723 39.872 47.845 41.952 ;
     RECT  47.173 65.856 47.845 68.001 ;
     RECT  37.091 29.529 47.861 30.201 ;
     RECT  47.365 31.872 47.861 32.48 ;
     RECT  44.203 71.36 47.893 71.392 ;
     RECT  47.861 29.529 47.915 32.48 ;
     RECT  47.893 71.296 47.979 71.392 ;
     RECT  47.723 48.32 47.987 48.352 ;
     RECT  47.979 71.36 48.035 71.392 ;
     RECT  47.845 64.896 48.043 68.001 ;
     RECT  47.269 34.24 48.227 35.744 ;
     RECT  48.043 65.024 48.323 68.001 ;
     RECT  43.381 12.224 48.373 14.001 ;
     RECT  46.693 16.704 48.373 16.864 ;
     RECT  47.915 29.529 48.421 30.816 ;
     RECT  48.373 16.576 48.442 16.864 ;
     RECT  48.227 34.929 48.467 35.744 ;
     RECT  48.442 16.704 48.501 16.864 ;
     RECT  47.317 74.752 48.515 74.784 ;
     RECT  44.203 77.312 48.515 78.801 ;
     RECT  48.501 16.704 48.707 17.12 ;
     RECT  46.315 26.816 48.853 26.848 ;
     RECT  47.845 4.544 48.949 4.576 ;
     RECT  48.853 26.816 48.949 26.976 ;
     RECT  48.707 17.024 49.043 17.12 ;
     RECT  48.421 28.928 49.077 30.816 ;
     RECT  47.845 39.68 49.091 41.952 ;
     RECT  47.723 51.129 49.141 51.936 ;
     RECT  43.765 53.568 49.141 53.6 ;
     RECT  47.363 56.529 49.141 57.201 ;
     RECT  46.835 7.929 49.189 8.601 ;
     RECT  49.141 51.129 49.195 53.6 ;
     RECT  49.141 56.529 49.21 57.312 ;
     RECT  49.077 28.352 49.237 30.816 ;
     RECT  47.915 32.448 49.237 32.48 ;
     RECT  48.949 4.544 49.259 5.792 ;
     RECT  48.373 11.904 49.259 15.2 ;
     RECT  49.237 28.352 49.269 32.48 ;
     RECT  49.269 28.352 49.379 32.736 ;
     RECT  48.949 26.688 49.387 26.976 ;
     RECT  49.379 28.864 49.387 32.736 ;
     RECT  49.043 17.024 49.571 17.056 ;
     RECT  49.259 5.76 49.619 5.792 ;
     RECT  48.421 47.808 49.619 47.84 ;
     RECT  48.323 66.624 49.619 68.001 ;
     RECT  48.323 65.024 49.955 65.056 ;
     RECT  49.189 7.929 50.101 8.736 ;
     RECT  49.387 28.928 50.17 32.736 ;
     RECT  49.195 51.129 50.483 52.96 ;
     RECT  50.101 7.929 50.725 9.376 ;
     RECT  44.483 18.729 50.741 19.401 ;
     RECT  50.725 6.784 50.795 9.376 ;
     RECT  50.741 18.729 50.819 19.552 ;
     RECT  50.17 31.936 51.381 32.736 ;
     RECT  48.467 34.929 51.381 35.601 ;
     RECT  51.381 31.936 51.435 35.601 ;
     RECT  50.101 27.264 51.443 27.296 ;
     RECT  51.435 31.936 51.539 31.968 ;
     RECT  50.795 7.929 51.587 9.376 ;
     RECT  44.203 72.729 51.973 73.401 ;
     RECT  50.821 38.208 52.019 38.24 ;
     RECT  52.261 5.952 52.405 5.984 ;
     RECT  51.587 7.929 52.405 8.601 ;
     RECT  51.973 72.729 52.405 74.656 ;
     RECT  49.259 13.329 52.499 15.2 ;
     RECT  50.869 70.784 52.547 70.816 ;
     RECT  49.21 56.529 52.693 57.201 ;
     RECT  51.435 33.92 52.883 35.601 ;
     RECT  46.33 24.129 52.981 24.801 ;
     RECT  52.069 54.592 53.301 54.624 ;
     RECT  52.693 55.936 53.301 57.201 ;
     RECT  52.405 5.952 53.365 8.601 ;
     RECT  52.261 10.24 53.365 10.272 ;
     RECT  53.301 54.592 53.411 57.201 ;
     RECT  47.603 61.929 53.413 62.601 ;
     RECT  50.17 28.928 53.493 30.201 ;
     RECT  52.981 24.129 53.547 25.632 ;
     RECT  53.365 5.952 53.651 10.272 ;
     RECT  52.981 71.232 53.749 71.264 ;
     RECT  52.405 72.729 53.749 75.36 ;
     RECT  53.749 71.232 53.803 75.36 ;
     RECT  53.749 58.752 53.818 58.784 ;
     RECT  53.803 72.128 53.843 75.36 ;
     RECT  53.651 6.272 53.891 10.272 ;
     RECT  53.891 7.04 53.939 10.272 ;
     RECT  53.87 70.656 53.939 70.688 ;
     RECT  50.869 48.128 53.941 48.16 ;
     RECT  50.483 51.129 54.069 51.936 ;
     RECT  53.843 72.729 54.069 75.36 ;
     RECT  37.091 2.529 54.085 3.201 ;
     RECT  50.819 18.729 54.085 19.401 ;
     RECT  53.941 47.872 54.123 48.16 ;
     RECT  54.069 72.729 54.123 76.448 ;
     RECT  54.069 49.664 54.133 49.696 ;
     RECT  54.069 51.129 54.133 52.128 ;
     RECT  49.619 67.329 54.133 68.001 ;
     RECT  54.133 49.664 54.142 52.128 ;
     RECT  54.142 49.664 54.187 51.936 ;
     RECT  54.123 75.2 54.275 76.448 ;
     RECT  54.187 49.664 54.611 51.801 ;
     RECT  54.133 66.944 54.638 68.001 ;
     RECT  53.413 61.929 54.645 63.776 ;
     RECT  53.939 7.104 54.69 10.272 ;
     RECT  54.645 61.376 54.699 63.776 ;
     RECT  54.69 7.104 54.763 10.528 ;
     RECT  53.411 55.936 54.851 57.201 ;
     RECT  52.883 34.929 54.901 35.601 ;
     RECT  52.405 36.992 54.901 37.024 ;
     RECT  54.763 7.296 54.947 9.248 ;
     RECT  49.259 11.904 54.949 11.936 ;
     RECT  54.901 34.929 54.955 37.024 ;
     RECT  52.499 13.329 54.965 14.001 ;
     RECT  53.493 28.928 54.965 30.56 ;
     RECT  54.901 38.784 54.995 38.816 ;
     RECT  54.949 11.84 55.019 11.936 ;
     RECT  54.085 18.729 55.093 20 ;
     RECT  52.981 16.192 55.147 16.224 ;
     RECT  55.093 18.624 55.147 20 ;
     RECT  54.965 28.8 55.147 30.56 ;
     RECT  54.085 2.529 55.571 4.192 ;
     RECT  54.613 32.832 55.717 32.864 ;
     RECT  55.717 31.872 55.787 32.864 ;
     RECT  55.147 28.992 55.813 30.56 ;
     RECT  54.851 56.529 55.813 57.201 ;
     RECT  53.547 24.129 55.859 25.12 ;
     RECT  54.275 76.416 55.907 76.448 ;
     RECT  55.787 32.832 56.147 32.864 ;
     RECT  54.699 61.376 56.293 62.601 ;
     RECT  55.571 2.529 56.437 3.201 ;
     RECT  54.947 7.296 56.773 8.736 ;
     RECT  55.147 18.624 56.773 19.401 ;
     RECT  56.293 61.376 56.773 62.752 ;
     RECT  56.437 2.368 56.819 3.201 ;
     RECT  56.773 7.296 56.819 8.864 ;
     RECT  55.813 56.529 56.819 58.144 ;
     RECT  55.813 28.992 56.867 30.816 ;
     RECT  56.819 2.529 56.869 3.201 ;
     RECT  56.437 5.12 56.885 5.152 ;
     RECT  56.869 2.529 56.939 3.744 ;
     RECT  55.859 24.129 56.965 24.801 ;
     RECT  54.965 13.329 57.011 14.112 ;
     RECT  56.773 61.056 57.011 62.752 ;
     RECT  56.965 22.848 57.013 24.801 ;
     RECT  57.013 22.72 57.067 24.801 ;
     RECT  56.867 28.992 57.397 30.56 ;
     RECT  57.397 28.544 57.451 30.56 ;
     RECT  57.378 33.152 57.451 33.184 ;
     RECT  56.885 5.12 57.541 5.28 ;
     RECT  57.541 5.12 57.635 5.984 ;
     RECT  54.123 48.128 57.635 48.16 ;
     RECT  53.749 54.08 57.635 54.112 ;
     RECT  57.635 5.248 57.683 5.984 ;
     RECT  57.011 61.056 57.731 62.601 ;
     RECT  56.819 7.929 58.163 8.864 ;
     RECT  56.773 17.856 58.163 19.401 ;
     RECT  53.509 43.52 58.163 43.552 ;
     RECT  57.909 71.296 58.163 71.328 ;
     RECT  57.013 74.88 58.355 74.912 ;
     RECT  54.638 66.944 58.453 68.128 ;
     RECT  58.453 66.944 58.597 68.448 ;
     RECT  57.067 24.129 58.613 24.801 ;
     RECT  57.067 22.72 58.667 22.752 ;
     RECT  57.451 28.544 58.667 30.201 ;
     RECT  54.955 34.929 58.739 36.512 ;
     RECT  58.739 34.929 58.787 35.872 ;
     RECT  58.117 38.208 58.931 38.24 ;
     RECT  57.683 5.952 59.171 5.984 ;
     RECT  58.163 18.624 59.315 19.401 ;
     RECT  58.597 65.92 59.315 68.448 ;
     RECT  58.613 24.129 59.747 25.056 ;
     RECT  58.645 47.872 59.891 47.904 ;
     RECT  58.885 74.688 59.891 74.72 ;
     RECT  49.091 40.329 59.947 41.952 ;
     RECT  59.947 40.329 60.139 41.632 ;
     RECT  59.315 65.92 60.179 68.001 ;
     RECT  59.221 59.264 60.323 59.296 ;
     RECT  60.085 26.688 60.707 26.72 ;
     RECT  56.819 56.529 60.949 57.201 ;
     RECT  55.019 11.904 60.997 11.936 ;
     RECT  57.011 13.329 60.997 14.001 ;
     RECT  57.731 61.929 61.525 62.601 ;
     RECT  48.515 78.129 61.525 78.801 ;
     RECT  61.525 61.929 61.669 63.904 ;
     RECT  60.179 66.944 61.669 68.001 ;
     RECT  60.997 11.904 61.715 14.001 ;
     RECT  60.373 75.264 61.715 75.296 ;
     RECT  58.667 28.992 62.197 30.201 ;
     RECT  58.787 34.929 62.197 35.601 ;
     RECT  61.669 66.688 62.197 68.001 ;
     RECT  62.197 66.048 62.266 68.001 ;
     RECT  62.197 28.416 62.325 30.201 ;
     RECT  62.293 26.752 62.379 26.784 ;
     RECT  60.949 56.32 62.485 57.201 ;
     RECT  62.197 34.112 62.629 35.601 ;
     RECT  46.787 45.729 62.629 46.401 ;
     RECT  62.266 66.944 62.677 68.001 ;
     RECT  62.629 33.856 62.709 35.601 ;
     RECT  61.525 76.992 62.725 78.801 ;
     RECT  62.725 76.736 62.771 78.801 ;
     RECT  62.709 33.024 63.011 35.601 ;
     RECT  56.939 2.529 63.205 3.201 ;
     RECT  61.715 11.904 63.205 11.936 ;
     RECT  61.715 13.329 63.205 14.001 ;
     RECT  63.205 53.44 63.275 53.472 ;
     RECT  62.325 28.416 63.541 31.136 ;
     RECT  62.485 55.872 63.637 57.201 ;
     RECT  62.629 45.729 63.861 47.264 ;
     RECT  63.637 55.872 63.875 57.696 ;
     RECT  62.771 76.736 63.875 76.768 ;
     RECT  63.861 44.608 63.915 47.264 ;
     RECT  63.854 43.264 63.923 43.296 ;
     RECT  62.677 71.36 64.437 71.392 ;
     RECT  63.541 27.968 64.451 31.136 ;
     RECT  62.677 66.944 64.453 68.64 ;
     RECT  64.437 71.232 64.491 71.392 ;
     RECT  63.205 11.904 64.499 14.001 ;
     RECT  64.357 59.264 64.747 59.296 ;
     RECT  63.011 33.856 64.757 35.601 ;
     RECT  64.757 33.856 64.811 35.936 ;
     RECT  64.453 65.984 64.875 68.64 ;
     RECT  63.875 56.32 64.883 57.696 ;
     RECT  64.814 75.264 64.883 75.296 ;
     RECT  58.163 7.929 64.933 8.601 ;
     RECT  64.875 65.984 64.933 68.001 ;
     RECT  64.883 56.32 64.979 57.201 ;
     RECT  59.315 18.729 64.981 19.401 ;
     RECT  61.669 61.824 65.003 63.904 ;
     RECT  64.933 65.856 65.003 68.001 ;
     RECT  64.933 7.929 65.013 8.736 ;
     RECT  62.629 16 65.013 16.032 ;
     RECT  64.981 18.729 65.067 20.576 ;
     RECT  64.811 34.112 65.205 35.936 ;
     RECT  59.747 24.129 65.221 24.801 ;
     RECT  65.205 34.112 65.259 36.512 ;
     RECT  64.451 28.416 65.269 31.136 ;
     RECT  65.205 32.448 65.269 32.48 ;
     RECT  65.269 28.416 65.315 32.48 ;
     RECT  64.933 38.208 65.515 38.24 ;
     RECT  64.499 13.329 65.589 14.001 ;
     RECT  65.003 61.824 65.603 63.264 ;
     RECT  65.013 16 65.643 17.056 ;
     RECT  64.499 11.904 65.653 11.936 ;
     RECT  65.589 13.329 65.662 14.624 ;
     RECT  65.662 13.329 65.707 14.496 ;
     RECT  65.013 7.929 65.835 9.76 ;
     RECT  65.653 11.584 65.845 11.936 ;
     RECT  65.707 13.329 65.845 14.001 ;
     RECT  65.845 11.584 65.854 14.001 ;
     RECT  65.221 23.296 65.941 24.801 ;
     RECT  65.941 22.464 66.101 24.801 ;
     RECT  66.101 22.464 66.155 26.016 ;
     RECT  65.315 28.416 66.179 31.904 ;
     RECT  65.603 61.929 66.179 63.264 ;
     RECT  66.179 28.416 66.603 31.136 ;
     RECT  66.603 28.992 66.731 31.136 ;
     RECT  65.067 18.729 66.853 19.68 ;
     RECT  64.491 71.232 67.043 71.264 ;
     RECT  66.155 22.464 67.573 22.496 ;
     RECT  66.853 18.368 67.619 19.68 ;
     RECT  67.573 22.144 67.619 22.496 ;
     RECT  63.205 2.529 67.859 3.872 ;
     RECT  65.643 17.024 67.859 17.056 ;
     RECT  63.915 44.608 67.859 46.401 ;
     RECT  66.421 53.824 67.859 53.856 ;
     RECT  65.003 66.048 67.859 68.001 ;
     RECT  66.517 60.288 67.907 60.32 ;
     RECT  60.139 40.329 68.341 41.001 ;
     RECT  54.611 50.816 68.341 51.801 ;
     RECT  67.619 18.368 68.387 19.401 ;
     RECT  68.341 38.72 68.41 41.001 ;
     RECT  65.854 11.904 68.435 14.001 ;
     RECT  66.155 24.129 68.435 26.016 ;
     RECT  65.259 34.929 68.435 36.512 ;
     RECT  68.41 38.72 68.435 38.752 ;
     RECT  66.997 32.96 68.531 32.992 ;
     RECT  65.835 7.929 69.493 8.601 ;
     RECT  67.619 22.144 69.587 22.176 ;
     RECT  68.341 49.536 69.749 51.801 ;
     RECT  68.435 13.184 70.069 14.001 ;
     RECT  69.749 48.384 70.259 51.801 ;
     RECT  68.435 34.929 70.645 35.601 ;
     RECT  70.259 48.384 70.787 48.416 ;
     RECT  67.859 67.008 71.029 68.001 ;
     RECT  54.123 72.729 71.029 73.401 ;
     RECT  71.029 72.729 71.098 73.568 ;
     RECT  67.859 45.729 71.221 46.401 ;
     RECT  71.029 66.688 71.275 68.001 ;
     RECT  70.069 11.968 71.411 14.001 ;
     RECT  69.493 7.929 71.701 9.824 ;
     RECT  68.917 65.28 71.749 65.312 ;
     RECT  71.749 65.28 71.795 65.44 ;
     RECT  71.221 53.504 71.797 53.536 ;
     RECT  70.645 34.176 71.843 35.601 ;
     RECT  70.693 37.056 71.843 37.088 ;
     RECT  71.797 53.504 72.037 54.112 ;
     RECT  72.037 53.504 72.107 55.072 ;
     RECT  66.179 61.929 72.325 62.601 ;
     RECT  68.41 40.329 72.469 41.001 ;
     RECT  66.731 29.529 72.515 31.136 ;
     RECT  72.469 40.329 72.747 42.144 ;
     RECT  71.701 7.808 73.043 9.824 ;
     RECT  70.259 50.816 73.043 51.801 ;
     RECT  73.043 51.008 73.205 51.801 ;
     RECT  72.107 53.504 73.205 53.536 ;
     RECT  64.979 56.529 73.205 57.201 ;
     RECT  73.189 58.752 73.205 58.784 ;
     RECT  73.205 51.008 73.259 53.536 ;
     RECT  73.205 56.529 73.259 58.784 ;
     RECT  72.747 40.329 73.477 41.001 ;
     RECT  72.325 61.184 73.523 62.601 ;
     RECT  71.797 17.024 73.525 17.056 ;
     RECT  71.029 70.528 73.571 70.56 ;
     RECT  68.387 18.729 73.589 19.401 ;
     RECT  73.589 18.729 73.667 20 ;
     RECT  72.515 29.529 73.813 31.008 ;
     RECT  73.813 28.672 73.859 31.008 ;
     RECT  71.275 67.329 73.861 68.001 ;
     RECT  73.859 28.672 73.899 30.816 ;
     RECT  73.525 17.024 74.037 17.184 ;
     RECT  73.667 18.729 74.037 19.401 ;
     RECT  74.037 17.024 74.091 19.401 ;
     RECT  72.997 48.96 74.099 48.992 ;
     RECT  71.221 45.729 74.101 46.816 ;
     RECT  73.259 51.008 74.283 52.256 ;
     RECT  74.229 48.384 74.339 48.416 ;
     RECT  68.435 24.129 74.341 24.801 ;
     RECT  71.797 26.752 74.357 26.784 ;
     RECT  74.341 24 74.411 24.801 ;
     RECT  74.357 26.496 74.411 26.784 ;
     RECT  74.101 44.864 74.613 46.816 ;
     RECT  71.795 65.408 74.629 65.44 ;
     RECT  74.613 43.584 74.667 46.816 ;
     RECT  73.043 7.929 74.677 9.824 ;
     RECT  73.477 38.912 74.723 41.001 ;
     RECT  74.667 43.584 74.723 46.401 ;
     RECT  74.677 7.929 74.731 10.848 ;
     RECT  74.731 10.816 74.741 10.848 ;
     RECT  71.411 13.184 74.795 14.001 ;
     RECT  74.741 10.816 74.819 11.36 ;
     RECT  74.723 43.584 74.819 43.616 ;
     RECT  73.523 61.504 75.059 62.601 ;
     RECT  74.283 51.129 75.155 52.256 ;
     RECT  75.059 61.824 75.179 62.601 ;
     RECT  74.629 64.768 75.179 65.44 ;
     RECT  71.797 5.76 75.299 5.792 ;
     RECT  71.843 34.624 75.491 35.601 ;
     RECT  74.723 39.936 75.499 41.001 ;
     RECT  75.491 34.752 75.514 35.601 ;
     RECT  73.861 67.008 76.357 68.001 ;
     RECT  75.301 70.656 76.451 70.688 ;
     RECT  75.179 64.768 76.739 64.8 ;
     RECT  74.723 45.504 76.789 46.401 ;
     RECT  75.493 42.624 76.853 42.656 ;
     RECT  76.853 42.624 76.907 42.784 ;
     RECT  76.789 44.48 76.907 46.401 ;
     RECT  76.907 42.752 76.931 42.784 ;
     RECT  73.259 56.529 76.979 57.888 ;
     RECT  75.179 61.929 77.221 62.601 ;
     RECT  75.589 31.68 77.317 31.712 ;
     RECT  77.317 31.488 77.363 31.712 ;
     RECT  75.514 34.929 77.365 35.601 ;
     RECT  74.795 13.329 77.461 14.001 ;
     RECT  74.091 17.6 77.555 19.401 ;
     RECT  74.411 26.496 77.555 26.528 ;
     RECT  75.445 38.144 77.555 38.176 ;
     RECT  76.907 45.504 77.555 46.401 ;
     RECT  76.357 66.624 77.555 68.001 ;
     RECT  77.555 18.729 77.893 19.401 ;
     RECT  77.555 45.729 78.373 46.401 ;
     RECT  78.373 45.729 78.443 47.264 ;
     RECT  78.373 49.088 78.443 49.12 ;
     RECT  77.363 31.488 78.707 31.52 ;
     RECT  77.365 34.816 78.707 35.601 ;
     RECT  77.221 61.929 78.707 63.904 ;
     RECT  77.461 13.329 78.755 14.304 ;
     RECT  77.893 18.729 78.803 20 ;
     RECT  67.859 2.529 79.92 3.201 ;
     RECT  74.731 7.929 79.92 8.601 ;
     RECT  78.755 13.329 79.92 14.001 ;
     RECT  78.803 18.729 79.92 19.401 ;
     RECT  74.411 24.129 79.92 24.801 ;
     RECT  73.899 29.529 79.92 30.201 ;
     RECT  78.707 34.929 79.92 35.601 ;
     RECT  75.499 40.329 79.92 41.001 ;
     RECT  78.443 45.729 79.92 46.401 ;
     RECT  75.155 51.129 79.92 51.801 ;
     RECT  76.979 56.529 79.92 57.201 ;
     RECT  78.707 61.929 79.92 62.601 ;
     RECT  77.555 67.329 79.92 68.001 ;
     RECT  71.098 72.729 79.92 73.401 ;
     RECT  62.771 78.129 79.92 78.801 ;
    LAYER M7 ;
     RECT  56.448 2.357 56.48 3.701 ;
     RECT  56.448 3.701 56.928 5.163 ;
     RECT  56.896 5.163 56.928 5.291 ;
     RECT  11.712 4.981 11.744 5.995 ;
     RECT  29.568 3.829 29.6 6.773 ;
     RECT  28.352 6.773 29.6 7.413 ;
     RECT  25.088 5.941 25.12 7.467 ;
     RECT  27.776 7.413 29.6 7.467 ;
     RECT  27.776 7.467 28.384 8.747 ;
     RECT  8.064 3.957 8.096 9.579 ;
     RECT  65.024 3.829 65.056 9.717 ;
     RECT  65.024 9.717 65.824 9.771 ;
     RECT  36.416 3.573 36.448 10.293 ;
     RECT  35.968 10.293 36.448 10.347 ;
     RECT  54.72 7.093 54.752 10.539 ;
     RECT  27.776 8.747 27.808 10.741 ;
     RECT  74.688 5.749 74.72 10.859 ;
     RECT  27.776 10.741 29.024 11.317 ;
     RECT  65.792 9.771 65.824 11.573 ;
     RECT  16.256 3.957 16.288 11.819 ;
     RECT  49.216 4.533 49.248 11.893 ;
     RECT  65.664 11.573 65.824 11.893 ;
     RECT  48.384 11.893 49.248 12.587 ;
     RECT  49.216 12.587 49.248 12.715 ;
     RECT  35.968 10.347 36 12.853 ;
     RECT  23.872 12.725 23.904 13.045 ;
     RECT  23.552 13.045 23.904 13.099 ;
     RECT  35.968 12.853 36.192 13.163 ;
     RECT  74.752 11.317 74.784 13.173 ;
     RECT  36.032 13.163 36.192 13.227 ;
     RECT  65.664 11.893 65.888 13.227 ;
     RECT  73.536 13.173 74.784 13.227 ;
     RECT  16.32 11.893 16.352 14.123 ;
     RECT  10.304 7.797 10.336 14.187 ;
     RECT  32.384 14.069 32.416 14.197 ;
     RECT  65.664 13.227 65.696 14.507 ;
     RECT  32.384 14.197 32.48 15.147 ;
     RECT  48.512 14.069 48.544 15.157 ;
     RECT  27.712 11.317 29.024 15.467 ;
     RECT  43.392 6.197 43.424 15.669 ;
     RECT  27.904 15.467 29.024 15.979 ;
     RECT  65.6 14.581 65.632 15.989 ;
     RECT  65.024 15.989 65.632 16.043 ;
     RECT  54.976 11.829 55.008 16.181 ;
     RECT  32.384 15.147 32.416 16.235 ;
     RECT  54.976 16.181 55.136 16.235 ;
     RECT  28.608 15.979 29.024 16.619 ;
     RECT  48.384 15.157 48.544 16.619 ;
     RECT  43.392 15.669 43.872 16.821 ;
     RECT  73.536 13.227 73.568 17.013 ;
     RECT  48.512 16.619 48.544 17.131 ;
     RECT  73.536 17.013 74.08 17.195 ;
     RECT  6.272 17.013 6.304 17.589 ;
     RECT  7.872 13.173 7.904 17.589 ;
     RECT  16.256 14.197 16.288 17.589 ;
     RECT  6.272 17.589 7.904 17.643 ;
     RECT  16.256 17.589 16.48 17.643 ;
     RECT  73.6 17.195 74.08 17.643 ;
     RECT  43.264 16.821 43.872 17.707 ;
     RECT  36.032 13.227 36.064 17.909 ;
     RECT  28.608 16.619 28.64 18.101 ;
     RECT  36.032 17.909 36.448 18.219 ;
     RECT  43.84 17.707 43.872 18.549 ;
     RECT  16.448 17.643 16.48 18.667 ;
     RECT  43.84 18.549 43.936 19.563 ;
     RECT  50.752 6.773 50.784 19.563 ;
     RECT  27.392 18.101 28.64 19.627 ;
     RECT  6.784 17.643 6.816 20.011 ;
     RECT  55.104 16.235 55.136 20.011 ;
     RECT  73.6 17.643 73.632 20.011 ;
     RECT  42.688 19.893 42.72 20.587 ;
     RECT  65.024 16.043 65.056 20.587 ;
     RECT  4.736 19.637 4.768 21.547 ;
     RECT  28.608 19.627 28.64 21.739 ;
     RECT  32.384 22.709 32.416 22.891 ;
     RECT  57.024 22.709 57.056 22.891 ;
     RECT  25.472 21.621 25.504 24.885 ;
     RECT  25.472 24.885 26.784 24.939 ;
     RECT  66.112 23.285 66.144 25.973 ;
     RECT  66.112 25.973 66.4 26.027 ;
     RECT  74.368 23.989 74.4 26.741 ;
     RECT  73.856 26.741 74.4 26.795 ;
     RECT  49.344 26.677 49.376 26.805 ;
     RECT  49.024 26.805 49.376 26.987 ;
     RECT  46.272 23.989 46.304 27.061 ;
     RECT  45.952 27.061 46.304 27.115 ;
     RECT  23.552 13.099 23.584 27.317 ;
     RECT  16.576 22.773 16.608 27.573 ;
     RECT  16.128 27.573 16.608 27.627 ;
     RECT  45.952 27.115 45.984 28.011 ;
     RECT  19.84 26.741 19.872 28.075 ;
     RECT  49.344 26.987 49.376 28.341 ;
     RECT  66.368 26.027 66.4 28.405 ;
     RECT  66.368 28.405 66.592 28.459 ;
     RECT  58.624 22.709 58.656 28.533 ;
     RECT  57.408 28.533 58.656 28.587 ;
     RECT  5.312 23.989 5.344 28.725 ;
     RECT  9.92 25.589 9.952 28.725 ;
     RECT  4.608 28.725 5.344 28.779 ;
     RECT  9.408 28.725 9.952 28.907 ;
     RECT  54.976 28.789 55.136 28.971 ;
     RECT  66.56 28.459 66.592 28.981 ;
     RECT  35.584 23.989 35.616 29.035 ;
     RECT  66.56 28.981 66.72 29.035 ;
     RECT  55.104 28.971 55.136 30.379 ;
     RECT  53.504 25.589 53.536 30.571 ;
     RECT  26.752 24.939 26.784 30.645 ;
     RECT  26.496 30.645 26.784 30.699 ;
     RECT  49.088 28.341 49.376 30.709 ;
     RECT  47.872 30.709 49.376 30.827 ;
     RECT  64.32 27.957 64.352 30.827 ;
     RECT  73.856 26.795 73.888 30.827 ;
     RECT  22.464 27.317 23.584 30.955 ;
     RECT  16.128 27.627 16.16 31.029 ;
     RECT  16.128 31.029 17.056 31.083 ;
     RECT  66.688 29.035 66.72 31.083 ;
     RECT  9.408 28.907 9.568 31.147 ;
     RECT  22.464 30.955 23.392 31.147 ;
     RECT  62.336 11.893 62.368 31.147 ;
     RECT  49.28 30.827 49.376 31.285 ;
     RECT  49.28 31.285 50.144 31.979 ;
     RECT  49.28 31.979 49.312 32.747 ;
     RECT  55.744 31.861 55.776 32.875 ;
     RECT  35.52 31.861 35.552 32.949 ;
     RECT  35.52 32.949 35.68 33.003 ;
     RECT  9.408 31.147 9.44 33.195 ;
     RECT  29.248 32.373 29.28 33.195 ;
     RECT  32.448 33.013 32.48 33.707 ;
     RECT  65.216 32.437 65.248 33.845 ;
     RECT  62.72 33.013 62.752 33.899 ;
     RECT  41.536 32.373 41.568 34.091 ;
     RECT  26.496 30.699 26.528 34.347 ;
     RECT  51.392 32.693 51.424 34.539 ;
     RECT  73.792 30.965 73.824 34.667 ;
     RECT  35.648 33.003 35.68 35.701 ;
     RECT  35.328 35.701 35.68 35.755 ;
     RECT  47.872 30.827 47.904 35.755 ;
     RECT  64.768 33.845 65.248 35.947 ;
     RECT  65.216 35.947 65.248 36.469 ;
     RECT  57.408 28.587 57.44 36.523 ;
     RECT  65.216 36.469 65.504 36.523 ;
     RECT  35.328 35.755 35.36 38.251 ;
     RECT  65.472 36.523 65.504 38.251 ;
     RECT  17.024 31.083 17.056 38.699 ;
     RECT  54.912 36.469 54.944 38.827 ;
     RECT  4.608 28.779 4.64 39.275 ;
     RECT  24.768 34.357 24.8 39.403 ;
     RECT  68.352 38.709 68.384 39.403 ;
     RECT  44.48 38.773 44.512 39.979 ;
     RECT  75.456 34.741 75.488 39.979 ;
     RECT  60.096 26.677 60.128 41.589 ;
     RECT  59.904 41.589 60.128 41.643 ;
     RECT  22.464 31.147 22.496 41.781 ;
     RECT  22.464 41.781 22.752 42.037 ;
     RECT  38.912 39.861 38.944 42.037 ;
     RECT  22.4 42.037 22.752 42.091 ;
     RECT  38.912 42.037 39.968 42.677 ;
     RECT  16.64 42.037 16.672 43.179 ;
     RECT  31.872 42.677 31.904 43.563 ;
     RECT  38.784 42.677 39.968 43.947 ;
     RECT  76.864 42.613 76.896 44.523 ;
     RECT  18.304 42.677 18.336 44.597 ;
     RECT  19.776 43.829 19.808 44.597 ;
     RECT  18.304 44.597 19.808 44.651 ;
     RECT  35.84 42.677 35.872 46.773 ;
     RECT  74.624 43.573 74.656 46.773 ;
     RECT  35.008 46.773 35.872 46.827 ;
     RECT  72.704 42.101 72.736 46.827 ;
     RECT  74.24 46.773 74.656 46.827 ;
     RECT  4.608 41.909 4.64 47.029 ;
     RECT  8.512 41.461 8.544 47.083 ;
     RECT  39.936 43.947 39.968 47.733 ;
     RECT  53.952 43.509 53.984 47.861 ;
     RECT  53.952 47.861 54.112 47.915 ;
     RECT  47.68 39.861 47.712 48.309 ;
     RECT  24.768 43.765 24.8 48.373 ;
     RECT  18.496 44.651 19.808 48.427 ;
     RECT  3.392 47.029 4.64 48.437 ;
     RECT  3.392 48.437 4.96 48.491 ;
     RECT  78.4 47.221 78.432 49.131 ;
     RECT  11.328 46.517 11.36 49.451 ;
     RECT  69.76 48.373 69.792 49.579 ;
     RECT  47.168 48.309 47.712 49.963 ;
     RECT  54.08 47.915 54.112 50.101 ;
     RECT  39.744 47.733 39.968 50.347 ;
     RECT  63.872 43.253 63.904 50.805 ;
     RECT  28.672 50.677 28.704 50.859 ;
     RECT  54.08 50.101 54.432 50.859 ;
     RECT  63.872 50.805 64.608 50.869 ;
     RECT  63.232 50.869 64.608 50.923 ;
     RECT  22.4 42.091 22.432 50.933 ;
     RECT  59.904 41.643 59.936 50.987 ;
     RECT  74.24 46.827 74.272 50.997 ;
     RECT  73.216 50.997 74.272 51.051 ;
     RECT  54.08 50.859 54.176 51.947 ;
     RECT  27.456 51.893 28.64 51.957 ;
     RECT  47.68 49.963 47.712 52.011 ;
     RECT  35.008 46.827 35.04 52.202 ;
     RECT  35.008 52.202 35.104 52.203 ;
     RECT  18.496 48.427 18.528 52.277 ;
     RECT  18.496 52.277 18.784 52.331 ;
     RECT  22.4 50.933 22.752 52.395 ;
     RECT  4.928 48.491 4.96 52.523 ;
     RECT  16.576 49.397 16.608 52.779 ;
     RECT  22.912 52.981 22.944 53.493 ;
     RECT  24.768 48.373 25.888 53.611 ;
     RECT  22.912 53.493 23.264 53.739 ;
     RECT  39.936 50.347 39.968 53.941 ;
     RECT  54.08 51.947 54.112 54.069 ;
     RECT  73.216 51.051 73.248 54.069 ;
     RECT  53.76 54.069 54.112 54.123 ;
     RECT  23.232 53.739 23.264 54.891 ;
     RECT  72.064 54.069 73.248 55.083 ;
     RECT  53.76 54.123 53.792 55.221 ;
     RECT  53.312 55.221 53.792 55.979 ;
     RECT  14.784 55.797 14.816 56.299 ;
     RECT  25.856 53.611 25.888 56.299 ;
     RECT  63.232 50.923 63.264 56.363 ;
     RECT  39.104 53.941 39.968 57.323 ;
     RECT  49.152 52.917 49.184 57.323 ;
     RECT  27.392 51.957 28.64 57.525 ;
     RECT  27.392 57.525 29.024 57.579 ;
     RECT  18.752 52.331 18.784 58.101 ;
     RECT  17.856 58.101 18.784 58.155 ;
     RECT  9.408 49.397 9.44 58.219 ;
     RECT  17.856 58.155 17.888 58.549 ;
     RECT  28.992 57.579 29.024 58.667 ;
     RECT  44.096 53.557 44.128 58.795 ;
     RECT  53.76 55.979 53.792 58.795 ;
     RECT  73.216 55.083 73.248 58.795 ;
     RECT  64.576 50.923 64.608 59.253 ;
     RECT  35.072 52.203 35.104 59.307 ;
     RECT  8.64 58.677 8.672 59.755 ;
     RECT  17.344 58.549 17.888 60.267 ;
     RECT  3.392 48.491 3.424 60.523 ;
     RECT  27.392 57.579 27.424 60.853 ;
     RECT  26.496 60.853 27.424 62.709 ;
     RECT  4.032 60.661 4.064 62.955 ;
     RECT  39.936 57.323 39.968 63.221 ;
     RECT  64.576 59.253 64.736 63.221 ;
     RECT  64.448 63.221 64.736 63.861 ;
     RECT  25.664 62.709 27.424 63.915 ;
     RECT  64.448 63.861 64.992 63.915 ;
     RECT  77.632 63.221 77.664 63.915 ;
     RECT  9.728 63.221 9.76 64.107 ;
     RECT  47.552 61.493 47.584 64.885 ;
     RECT  25.664 63.915 25.696 65.067 ;
     RECT  5.568 59.765 5.6 65.461 ;
     RECT  5.376 65.461 5.6 65.515 ;
     RECT  64.576 63.915 64.992 65.899 ;
     RECT  64.576 65.899 64.608 65.973 ;
     RECT  47.552 64.885 48.032 66.667 ;
     RECT  15.936 65.461 15.968 66.677 ;
     RECT  17.856 60.267 17.888 66.677 ;
     RECT  71.232 65.269 71.264 66.677 ;
     RECT  47.744 66.667 48.032 66.731 ;
     RECT  71.04 66.677 71.264 66.731 ;
     RECT  47.744 66.731 47.968 66.987 ;
     RECT  64.512 65.973 64.608 66.987 ;
     RECT  5.376 65.515 5.408 67.051 ;
     RECT  64.576 66.987 64.608 67.051 ;
     RECT  15.936 66.677 17.888 67.061 ;
     RECT  27.392 63.915 27.424 67.125 ;
     RECT  26.432 67.125 27.424 67.189 ;
     RECT  62.208 66.037 62.24 67.243 ;
     RECT  75.136 61.813 75.168 67.243 ;
     RECT  54.656 61.365 54.688 68.139 ;
     RECT  15.936 67.061 17.952 68.651 ;
     RECT  26.432 67.189 27.744 69.035 ;
     RECT  15.936 68.651 15.968 69.099 ;
     RECT  26.432 69.035 27.296 69.419 ;
     RECT  34.24 68.085 34.272 70.315 ;
     RECT  22.784 70.581 22.816 70.645 ;
     RECT  22.784 70.645 23.904 70.763 ;
     RECT  53.888 70.645 53.92 71.221 ;
     RECT  64.832 68.085 64.864 71.221 ;
     RECT  47.936 66.987 47.968 71.339 ;
     RECT  57.92 68.085 57.952 71.339 ;
     RECT  22.912 70.763 23.904 71.403 ;
     RECT  64.448 71.221 64.864 71.403 ;
     RECT  22.912 71.403 22.944 71.851 ;
     RECT  7.872 66.997 7.904 72.053 ;
     RECT  7.68 72.053 7.904 72.107 ;
     RECT  53.76 71.221 53.92 72.171 ;
     RECT  17.92 68.651 17.952 72.619 ;
     RECT  71.04 66.731 71.072 73.579 ;
     RECT  22.656 72.565 22.688 74.091 ;
     RECT  27.264 69.419 27.296 74.549 ;
     RECT  7.68 72.107 7.712 74.603 ;
     RECT  27.072 74.549 27.296 74.603 ;
     RECT  53.888 72.171 53.92 74.613 ;
     RECT  53.888 74.613 54.112 74.667 ;
     RECT  17.856 73.525 17.888 75.307 ;
     RECT  64.832 71.403 64.864 75.307 ;
     RECT  34.176 74.997 34.208 76.203 ;
     RECT  54.08 74.667 54.112 76.459 ;
     RECT  44.16 71.349 44.192 77.355 ;
     RECT  27.072 74.603 27.104 77.547 ;
     RECT  38.848 63.221 39.968 78.059 ;
     RECT  39.936 78.059 39.968 81.963 ;
  END
END ot_dsrom_wsrc_mirror
END LIBRARY
